VERSION 5.8 ;
BUSBITCHARS "[]" ;
DIVIDERCHAR "/" ;
UNITS DISTANCE MICRONS 2000 ;

# Comprehensive Standard Cell Library
# Technology: tcbn07 (7nm node), BWP300H8P64PD (Back-end), LVT (Low Vt)
# Contains all standard cells for CPU design
# Auto-generated from cpu_syn.v netlist

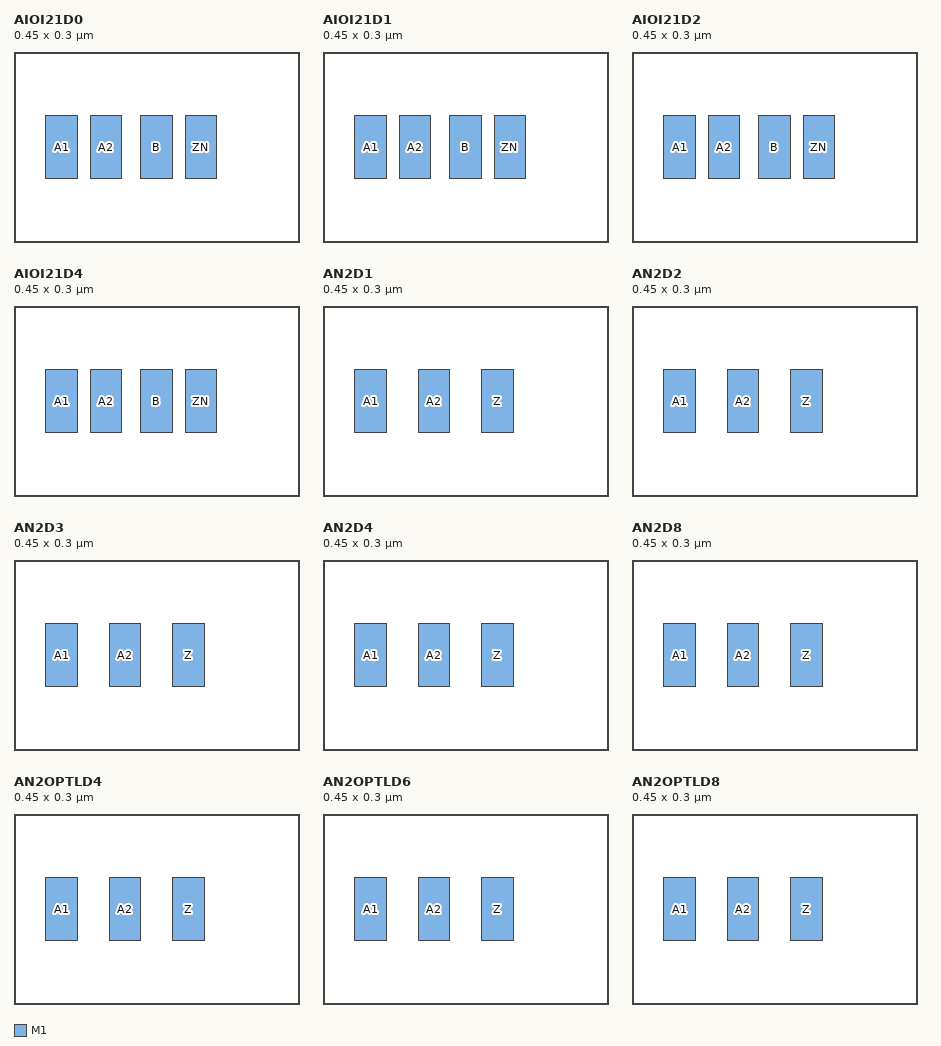
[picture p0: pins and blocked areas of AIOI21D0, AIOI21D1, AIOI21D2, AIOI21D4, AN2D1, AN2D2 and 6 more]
MACRO AIOI21D0
  CLASS CORE ;
  ORIGIN 0.0 0.0 ;
  SIZE 0.45 BY 0.3 ;
  SYMMETRY X Y ;
  PIN A1
    DIRECTION INPUT ;
    USE SIGNAL ;
    PORT
      LAYER M1 ;
      RECT 0.05 0.1 0.10 0.2 ;
    END
  END A1
  PIN A2
    DIRECTION INPUT ;
    USE SIGNAL ;
    PORT
      LAYER M1 ;
      RECT 0.12 0.1 0.17 0.2 ;
    END
  END A2
  PIN B
    DIRECTION INPUT ;
    USE SIGNAL ;
    PORT
      LAYER M1 ;
      RECT 0.20 0.1 0.25 0.2 ;
    END
  END B
  PIN ZN
    DIRECTION OUTPUT ;
    USE SIGNAL ;
    PORT
      LAYER M1 ;
      RECT 0.27 0.1 0.32 0.2 ;
    END
  END ZN
END AIOI21D0
MACRO AIOI21D1
  CLASS CORE ;
  ORIGIN 0.0 0.0 ;
  SIZE 0.45 BY 0.3 ;
  SYMMETRY X Y ;
  PIN A1
    DIRECTION INPUT ;
    USE SIGNAL ;
    PORT
      LAYER M1 ;
      RECT 0.05 0.1 0.10 0.2 ;
    END
  END A1
  PIN A2
    DIRECTION INPUT ;
    USE SIGNAL ;
    PORT
      LAYER M1 ;
      RECT 0.12 0.1 0.17 0.2 ;
    END
  END A2
  PIN B
    DIRECTION INPUT ;
    USE SIGNAL ;
    PORT
      LAYER M1 ;
      RECT 0.20 0.1 0.25 0.2 ;
    END
  END B
  PIN ZN
    DIRECTION OUTPUT ;
    USE SIGNAL ;
    PORT
      LAYER M1 ;
      RECT 0.27 0.1 0.32 0.2 ;
    END
  END ZN
END AIOI21D1
MACRO AIOI21D2
  CLASS CORE ;
  ORIGIN 0.0 0.0 ;
  SIZE 0.45 BY 0.3 ;
  SYMMETRY X Y ;
  PIN A1
    DIRECTION INPUT ;
    USE SIGNAL ;
    PORT
      LAYER M1 ;
      RECT 0.05 0.1 0.10 0.2 ;
    END
  END A1
  PIN A2
    DIRECTION INPUT ;
    USE SIGNAL ;
    PORT
      LAYER M1 ;
      RECT 0.12 0.1 0.17 0.2 ;
    END
  END A2
  PIN B
    DIRECTION INPUT ;
    USE SIGNAL ;
    PORT
      LAYER M1 ;
      RECT 0.20 0.1 0.25 0.2 ;
    END
  END B
  PIN ZN
    DIRECTION OUTPUT ;
    USE SIGNAL ;
    PORT
      LAYER M1 ;
      RECT 0.27 0.1 0.32 0.2 ;
    END
  END ZN
END AIOI21D2
MACRO AIOI21D4
  CLASS CORE ;
  ORIGIN 0.0 0.0 ;
  SIZE 0.45 BY 0.3 ;
  SYMMETRY X Y ;
  PIN A1
    DIRECTION INPUT ;
    USE SIGNAL ;
    PORT
      LAYER M1 ;
      RECT 0.05 0.1 0.10 0.2 ;
    END
  END A1
  PIN A2
    DIRECTION INPUT ;
    USE SIGNAL ;
    PORT
      LAYER M1 ;
      RECT 0.12 0.1 0.17 0.2 ;
    END
  END A2
  PIN B
    DIRECTION INPUT ;
    USE SIGNAL ;
    PORT
      LAYER M1 ;
      RECT 0.20 0.1 0.25 0.2 ;
    END
  END B
  PIN ZN
    DIRECTION OUTPUT ;
    USE SIGNAL ;
    PORT
      LAYER M1 ;
      RECT 0.27 0.1 0.32 0.2 ;
    END
  END ZN
END AIOI21D4
MACRO AN2D1
  CLASS CORE ;
  ORIGIN 0.0 0.0 ;
  SIZE 0.45 BY 0.3 ;
  SYMMETRY X Y ;
  PIN A1
    DIRECTION INPUT ;
    USE SIGNAL ;
    PORT
      LAYER M1 ;
      RECT 0.05 0.1 0.10 0.2 ;
    END
  END A1
  PIN A2
    DIRECTION INPUT ;
    USE SIGNAL ;
    PORT
      LAYER M1 ;
      RECT 0.15 0.1 0.20 0.2 ;
    END
  END A2
  PIN Z
    DIRECTION OUTPUT ;
    USE SIGNAL ;
    PORT
      LAYER M1 ;
      RECT 0.25 0.1 0.30 0.2 ;
    END
  END Z
END AN2D1
MACRO AN2D2
  CLASS CORE ;
  ORIGIN 0.0 0.0 ;
  SIZE 0.45 BY 0.3 ;
  SYMMETRY X Y ;
  PIN A1
    DIRECTION INPUT ;
    USE SIGNAL ;
    PORT
      LAYER M1 ;
      RECT 0.05 0.1 0.10 0.2 ;
    END
  END A1
  PIN A2
    DIRECTION INPUT ;
    USE SIGNAL ;
    PORT
      LAYER M1 ;
      RECT 0.15 0.1 0.20 0.2 ;
    END
  END A2
  PIN Z
    DIRECTION OUTPUT ;
    USE SIGNAL ;
    PORT
      LAYER M1 ;
      RECT 0.25 0.1 0.30 0.2 ;
    END
  END Z
END AN2D2
MACRO AN2D3
  CLASS CORE ;
  ORIGIN 0.0 0.0 ;
  SIZE 0.45 BY 0.3 ;
  SYMMETRY X Y ;
  PIN A1
    DIRECTION INPUT ;
    USE SIGNAL ;
    PORT
      LAYER M1 ;
      RECT 0.05 0.1 0.10 0.2 ;
    END
  END A1
  PIN A2
    DIRECTION INPUT ;
    USE SIGNAL ;
    PORT
      LAYER M1 ;
      RECT 0.15 0.1 0.20 0.2 ;
    END
  END A2
  PIN Z
    DIRECTION OUTPUT ;
    USE SIGNAL ;
    PORT
      LAYER M1 ;
      RECT 0.25 0.1 0.30 0.2 ;
    END
  END Z
END AN2D3
MACRO AN2D4
  CLASS CORE ;
  ORIGIN 0.0 0.0 ;
  SIZE 0.45 BY 0.3 ;
  SYMMETRY X Y ;
  PIN A1
    DIRECTION INPUT ;
    USE SIGNAL ;
    PORT
      LAYER M1 ;
      RECT 0.05 0.1 0.10 0.2 ;
    END
  END A1
  PIN A2
    DIRECTION INPUT ;
    USE SIGNAL ;
    PORT
      LAYER M1 ;
      RECT 0.15 0.1 0.20 0.2 ;
    END
  END A2
  PIN Z
    DIRECTION OUTPUT ;
    USE SIGNAL ;
    PORT
      LAYER M1 ;
      RECT 0.25 0.1 0.30 0.2 ;
    END
  END Z
END AN2D4
MACRO AN2D8
  CLASS CORE ;
  ORIGIN 0.0 0.0 ;
  SIZE 0.45 BY 0.3 ;
  SYMMETRY X Y ;
  PIN A1
    DIRECTION INPUT ;
    USE SIGNAL ;
    PORT
      LAYER M1 ;
      RECT 0.05 0.1 0.10 0.2 ;
    END
  END A1
  PIN A2
    DIRECTION INPUT ;
    USE SIGNAL ;
    PORT
      LAYER M1 ;
      RECT 0.15 0.1 0.20 0.2 ;
    END
  END A2
  PIN Z
    DIRECTION OUTPUT ;
    USE SIGNAL ;
    PORT
      LAYER M1 ;
      RECT 0.25 0.1 0.30 0.2 ;
    END
  END Z
END AN2D8
MACRO AN2OPTLD4
  CLASS CORE ;
  ORIGIN 0.0 0.0 ;
  SIZE 0.45 BY 0.3 ;
  SYMMETRY X Y ;
  PIN A1
    DIRECTION INPUT ;
    USE SIGNAL ;
    PORT
      LAYER M1 ;
      RECT 0.05 0.1 0.10 0.2 ;
    END
  END A1
  PIN A2
    DIRECTION INPUT ;
    USE SIGNAL ;
    PORT
      LAYER M1 ;
      RECT 0.15 0.1 0.20 0.2 ;
    END
  END A2
  PIN Z
    DIRECTION OUTPUT ;
    USE SIGNAL ;
    PORT
      LAYER M1 ;
      RECT 0.25 0.1 0.30 0.2 ;
    END
  END Z
END AN2OPTLD4
MACRO AN2OPTLD6
  CLASS CORE ;
  ORIGIN 0.0 0.0 ;
  SIZE 0.45 BY 0.3 ;
  SYMMETRY X Y ;
  PIN A1
    DIRECTION INPUT ;
    USE SIGNAL ;
    PORT
      LAYER M1 ;
      RECT 0.05 0.1 0.10 0.2 ;
    END
  END A1
  PIN A2
    DIRECTION INPUT ;
    USE SIGNAL ;
    PORT
      LAYER M1 ;
      RECT 0.15 0.1 0.20 0.2 ;
    END
  END A2
  PIN Z
    DIRECTION OUTPUT ;
    USE SIGNAL ;
    PORT
      LAYER M1 ;
      RECT 0.25 0.1 0.30 0.2 ;
    END
  END Z
END AN2OPTLD6
MACRO AN2OPTLD8
  CLASS CORE ;
  ORIGIN 0.0 0.0 ;
  SIZE 0.45 BY 0.3 ;
  SYMMETRY X Y ;
  PIN A1
    DIRECTION INPUT ;
    USE SIGNAL ;
    PORT
      LAYER M1 ;
      RECT 0.05 0.1 0.10 0.2 ;
    END
  END A1
  PIN A2
    DIRECTION INPUT ;
    USE SIGNAL ;
    PORT
      LAYER M1 ;
      RECT 0.15 0.1 0.20 0.2 ;
    END
  END A2
  PIN Z
    DIRECTION OUTPUT ;
    USE SIGNAL ;
    PORT
      LAYER M1 ;
      RECT 0.25 0.1 0.30 0.2 ;
    END
  END Z
END AN2OPTLD8
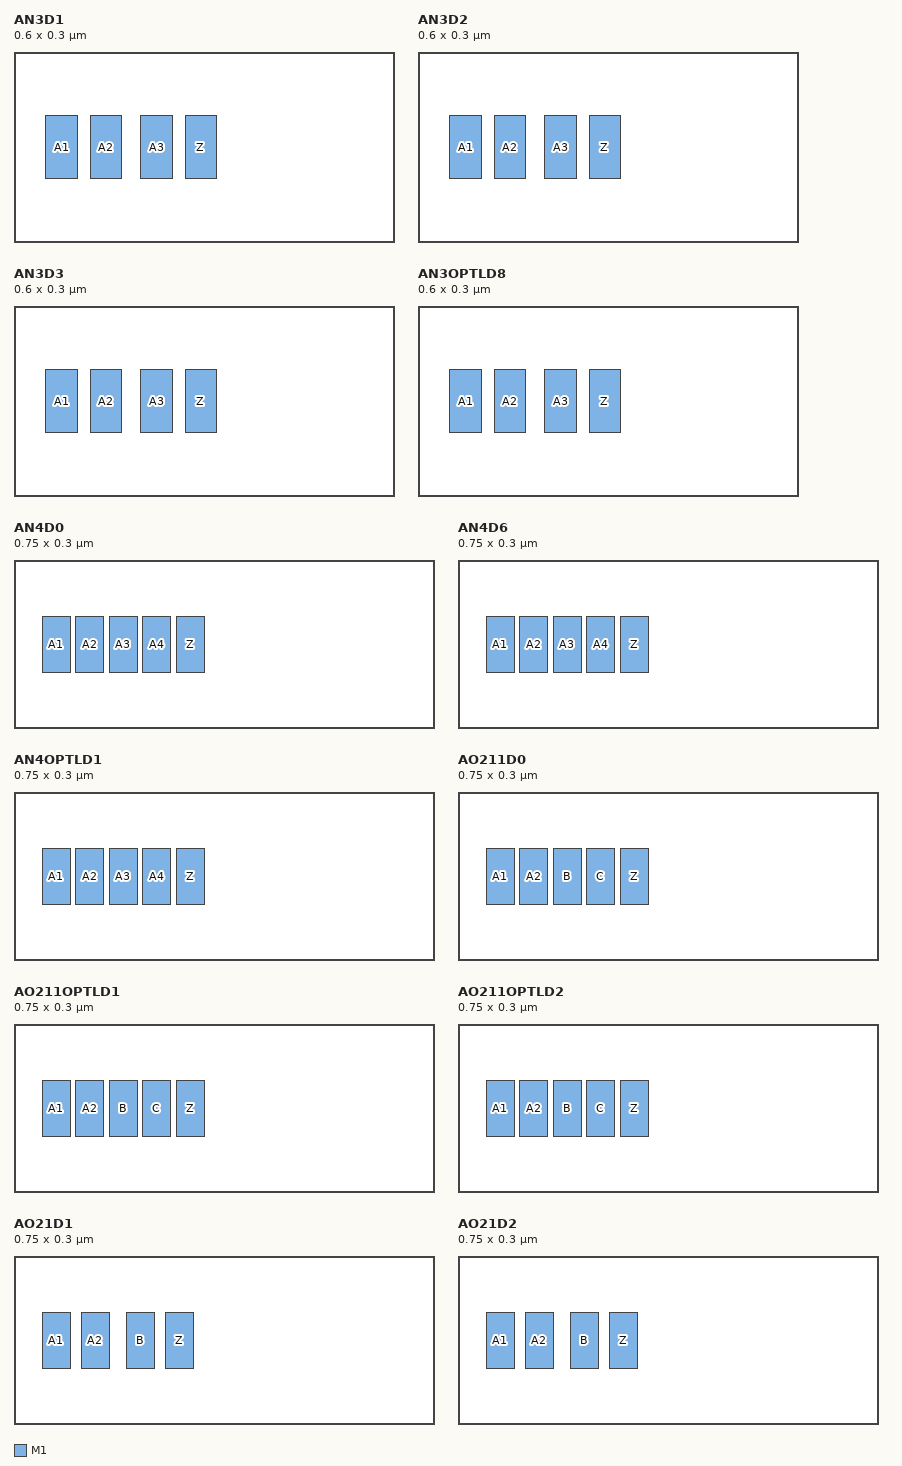
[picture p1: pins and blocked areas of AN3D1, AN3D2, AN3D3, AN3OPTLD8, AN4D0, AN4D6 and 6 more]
MACRO AN3D1
  CLASS CORE ;
  ORIGIN 0.0 0.0 ;
  SIZE 0.6 BY 0.3 ;
  SYMMETRY X Y ;
  PIN A1
    DIRECTION INPUT ;
    USE SIGNAL ;
    PORT
      LAYER M1 ;
      RECT 0.05 0.1 0.10 0.2 ;
    END
  END A1
  PIN A2
    DIRECTION INPUT ;
    USE SIGNAL ;
    PORT
      LAYER M1 ;
      RECT 0.12 0.1 0.17 0.2 ;
    END
  END A2
  PIN A3
    DIRECTION INPUT ;
    USE SIGNAL ;
    PORT
      LAYER M1 ;
      RECT 0.20 0.1 0.25 0.2 ;
    END
  END A3
  PIN Z
    DIRECTION OUTPUT ;
    USE SIGNAL ;
    PORT
      LAYER M1 ;
      RECT 0.27 0.1 0.32 0.2 ;
    END
  END Z
END AN3D1
MACRO AN3D2
  CLASS CORE ;
  ORIGIN 0.0 0.0 ;
  SIZE 0.6 BY 0.3 ;
  SYMMETRY X Y ;
  PIN A1
    DIRECTION INPUT ;
    USE SIGNAL ;
    PORT
      LAYER M1 ;
      RECT 0.05 0.1 0.10 0.2 ;
    END
  END A1
  PIN A2
    DIRECTION INPUT ;
    USE SIGNAL ;
    PORT
      LAYER M1 ;
      RECT 0.12 0.1 0.17 0.2 ;
    END
  END A2
  PIN A3
    DIRECTION INPUT ;
    USE SIGNAL ;
    PORT
      LAYER M1 ;
      RECT 0.20 0.1 0.25 0.2 ;
    END
  END A3
  PIN Z
    DIRECTION OUTPUT ;
    USE SIGNAL ;
    PORT
      LAYER M1 ;
      RECT 0.27 0.1 0.32 0.2 ;
    END
  END Z
END AN3D2
MACRO AN3D3
  CLASS CORE ;
  ORIGIN 0.0 0.0 ;
  SIZE 0.6 BY 0.3 ;
  SYMMETRY X Y ;
  PIN A1
    DIRECTION INPUT ;
    USE SIGNAL ;
    PORT
      LAYER M1 ;
      RECT 0.05 0.1 0.10 0.2 ;
    END
  END A1
  PIN A2
    DIRECTION INPUT ;
    USE SIGNAL ;
    PORT
      LAYER M1 ;
      RECT 0.12 0.1 0.17 0.2 ;
    END
  END A2
  PIN A3
    DIRECTION INPUT ;
    USE SIGNAL ;
    PORT
      LAYER M1 ;
      RECT 0.20 0.1 0.25 0.2 ;
    END
  END A3
  PIN Z
    DIRECTION OUTPUT ;
    USE SIGNAL ;
    PORT
      LAYER M1 ;
      RECT 0.27 0.1 0.32 0.2 ;
    END
  END Z
END AN3D3
MACRO AN3OPTLD8
  CLASS CORE ;
  ORIGIN 0.0 0.0 ;
  SIZE 0.6 BY 0.3 ;
  SYMMETRY X Y ;
  PIN A1
    DIRECTION INPUT ;
    USE SIGNAL ;
    PORT
      LAYER M1 ;
      RECT 0.05 0.1 0.10 0.2 ;
    END
  END A1
  PIN A2
    DIRECTION INPUT ;
    USE SIGNAL ;
    PORT
      LAYER M1 ;
      RECT 0.12 0.1 0.17 0.2 ;
    END
  END A2
  PIN A3
    DIRECTION INPUT ;
    USE SIGNAL ;
    PORT
      LAYER M1 ;
      RECT 0.20 0.1 0.25 0.2 ;
    END
  END A3
  PIN Z
    DIRECTION OUTPUT ;
    USE SIGNAL ;
    PORT
      LAYER M1 ;
      RECT 0.27 0.1 0.32 0.2 ;
    END
  END Z
END AN3OPTLD8
MACRO AN4D0
  CLASS CORE ;
  ORIGIN 0.0 0.0 ;
  SIZE 0.75 BY 0.3 ;
  SYMMETRY X Y ;
  PIN A1
    DIRECTION INPUT ;
    USE SIGNAL ;
    PORT
      LAYER M1 ;
      RECT 0.05 0.1 0.10 0.2 ;
    END
  END A1
  PIN A2
    DIRECTION INPUT ;
    USE SIGNAL ;
    PORT
      LAYER M1 ;
      RECT 0.11 0.1 0.16 0.2 ;
    END
  END A2
  PIN A3
    DIRECTION INPUT ;
    USE SIGNAL ;
    PORT
      LAYER M1 ;
      RECT 0.17 0.1 0.22 0.2 ;
    END
  END A3
  PIN A4
    DIRECTION INPUT ;
    USE SIGNAL ;
    PORT
      LAYER M1 ;
      RECT 0.23 0.1 0.28 0.2 ;
    END
  END A4
  PIN Z
    DIRECTION OUTPUT ;
    USE SIGNAL ;
    PORT
      LAYER M1 ;
      RECT 0.29 0.1 0.34 0.2 ;
    END
  END Z
END AN4D0
MACRO AN4D6
  CLASS CORE ;
  ORIGIN 0.0 0.0 ;
  SIZE 0.75 BY 0.3 ;
  SYMMETRY X Y ;
  PIN A1
    DIRECTION INPUT ;
    USE SIGNAL ;
    PORT
      LAYER M1 ;
      RECT 0.05 0.1 0.10 0.2 ;
    END
  END A1
  PIN A2
    DIRECTION INPUT ;
    USE SIGNAL ;
    PORT
      LAYER M1 ;
      RECT 0.11 0.1 0.16 0.2 ;
    END
  END A2
  PIN A3
    DIRECTION INPUT ;
    USE SIGNAL ;
    PORT
      LAYER M1 ;
      RECT 0.17 0.1 0.22 0.2 ;
    END
  END A3
  PIN A4
    DIRECTION INPUT ;
    USE SIGNAL ;
    PORT
      LAYER M1 ;
      RECT 0.23 0.1 0.28 0.2 ;
    END
  END A4
  PIN Z
    DIRECTION OUTPUT ;
    USE SIGNAL ;
    PORT
      LAYER M1 ;
      RECT 0.29 0.1 0.34 0.2 ;
    END
  END Z
END AN4D6
MACRO AN4OPTLD1
  CLASS CORE ;
  ORIGIN 0.0 0.0 ;
  SIZE 0.75 BY 0.3 ;
  SYMMETRY X Y ;
  PIN A1
    DIRECTION INPUT ;
    USE SIGNAL ;
    PORT
      LAYER M1 ;
      RECT 0.05 0.1 0.10 0.2 ;
    END
  END A1
  PIN A2
    DIRECTION INPUT ;
    USE SIGNAL ;
    PORT
      LAYER M1 ;
      RECT 0.11 0.1 0.16 0.2 ;
    END
  END A2
  PIN A3
    DIRECTION INPUT ;
    USE SIGNAL ;
    PORT
      LAYER M1 ;
      RECT 0.17 0.1 0.22 0.2 ;
    END
  END A3
  PIN A4
    DIRECTION INPUT ;
    USE SIGNAL ;
    PORT
      LAYER M1 ;
      RECT 0.23 0.1 0.28 0.2 ;
    END
  END A4
  PIN Z
    DIRECTION OUTPUT ;
    USE SIGNAL ;
    PORT
      LAYER M1 ;
      RECT 0.29 0.1 0.34 0.2 ;
    END
  END Z
END AN4OPTLD1
MACRO AO211D0
  CLASS CORE ;
  ORIGIN 0.0 0.0 ;
  SIZE 0.75 BY 0.3 ;
  SYMMETRY X Y ;
  PIN A1
    DIRECTION INPUT ;
    USE SIGNAL ;
    PORT
      LAYER M1 ;
      RECT 0.05 0.1 0.10 0.2 ;
    END
  END A1
  PIN A2
    DIRECTION INPUT ;
    USE SIGNAL ;
    PORT
      LAYER M1 ;
      RECT 0.11 0.1 0.16 0.2 ;
    END
  END A2
  PIN B
    DIRECTION INPUT ;
    USE SIGNAL ;
    PORT
      LAYER M1 ;
      RECT 0.17 0.1 0.22 0.2 ;
    END
  END B
  PIN C
    DIRECTION INPUT ;
    USE SIGNAL ;
    PORT
      LAYER M1 ;
      RECT 0.23 0.1 0.28 0.2 ;
    END
  END C
  PIN Z
    DIRECTION OUTPUT ;
    USE SIGNAL ;
    PORT
      LAYER M1 ;
      RECT 0.29 0.1 0.34 0.2 ;
    END
  END Z
END AO211D0
MACRO AO211OPTLD1
  CLASS CORE ;
  ORIGIN 0.0 0.0 ;
  SIZE 0.75 BY 0.3 ;
  SYMMETRY X Y ;
  PIN A1
    DIRECTION INPUT ;
    USE SIGNAL ;
    PORT
      LAYER M1 ;
      RECT 0.05 0.1 0.10 0.2 ;
    END
  END A1
  PIN A2
    DIRECTION INPUT ;
    USE SIGNAL ;
    PORT
      LAYER M1 ;
      RECT 0.11 0.1 0.16 0.2 ;
    END
  END A2
  PIN B
    DIRECTION INPUT ;
    USE SIGNAL ;
    PORT
      LAYER M1 ;
      RECT 0.17 0.1 0.22 0.2 ;
    END
  END B
  PIN C
    DIRECTION INPUT ;
    USE SIGNAL ;
    PORT
      LAYER M1 ;
      RECT 0.23 0.1 0.28 0.2 ;
    END
  END C
  PIN Z
    DIRECTION OUTPUT ;
    USE SIGNAL ;
    PORT
      LAYER M1 ;
      RECT 0.29 0.1 0.34 0.2 ;
    END
  END Z
END AO211OPTLD1
MACRO AO211OPTLD2
  CLASS CORE ;
  ORIGIN 0.0 0.0 ;
  SIZE 0.75 BY 0.3 ;
  SYMMETRY X Y ;
  PIN A1
    DIRECTION INPUT ;
    USE SIGNAL ;
    PORT
      LAYER M1 ;
      RECT 0.05 0.1 0.10 0.2 ;
    END
  END A1
  PIN A2
    DIRECTION INPUT ;
    USE SIGNAL ;
    PORT
      LAYER M1 ;
      RECT 0.11 0.1 0.16 0.2 ;
    END
  END A2
  PIN B
    DIRECTION INPUT ;
    USE SIGNAL ;
    PORT
      LAYER M1 ;
      RECT 0.17 0.1 0.22 0.2 ;
    END
  END B
  PIN C
    DIRECTION INPUT ;
    USE SIGNAL ;
    PORT
      LAYER M1 ;
      RECT 0.23 0.1 0.28 0.2 ;
    END
  END C
  PIN Z
    DIRECTION OUTPUT ;
    USE SIGNAL ;
    PORT
      LAYER M1 ;
      RECT 0.29 0.1 0.34 0.2 ;
    END
  END Z
END AO211OPTLD2
MACRO AO21D1
  CLASS CORE ;
  ORIGIN 0.0 0.0 ;
  SIZE 0.75 BY 0.3 ;
  SYMMETRY X Y ;
  PIN A1
    DIRECTION INPUT ;
    USE SIGNAL ;
    PORT
      LAYER M1 ;
      RECT 0.05 0.1 0.10 0.2 ;
    END
  END A1
  PIN A2
    DIRECTION INPUT ;
    USE SIGNAL ;
    PORT
      LAYER M1 ;
      RECT 0.12 0.1 0.17 0.2 ;
    END
  END A2
  PIN B
    DIRECTION INPUT ;
    USE SIGNAL ;
    PORT
      LAYER M1 ;
      RECT 0.20 0.1 0.25 0.2 ;
    END
  END B
  PIN Z
    DIRECTION OUTPUT ;
    USE SIGNAL ;
    PORT
      LAYER M1 ;
      RECT 0.27 0.1 0.32 0.2 ;
    END
  END Z
END AO21D1
MACRO AO21D2
  CLASS CORE ;
  ORIGIN 0.0 0.0 ;
  SIZE 0.75 BY 0.3 ;
  SYMMETRY X Y ;
  PIN A1
    DIRECTION INPUT ;
    USE SIGNAL ;
    PORT
      LAYER M1 ;
      RECT 0.05 0.1 0.10 0.2 ;
    END
  END A1
  PIN A2
    DIRECTION INPUT ;
    USE SIGNAL ;
    PORT
      LAYER M1 ;
      RECT 0.12 0.1 0.17 0.2 ;
    END
  END A2
  PIN B
    DIRECTION INPUT ;
    USE SIGNAL ;
    PORT
      LAYER M1 ;
      RECT 0.20 0.1 0.25 0.2 ;
    END
  END B
  PIN Z
    DIRECTION OUTPUT ;
    USE SIGNAL ;
    PORT
      LAYER M1 ;
      RECT 0.27 0.1 0.32 0.2 ;
    END
  END Z
END AO21D2
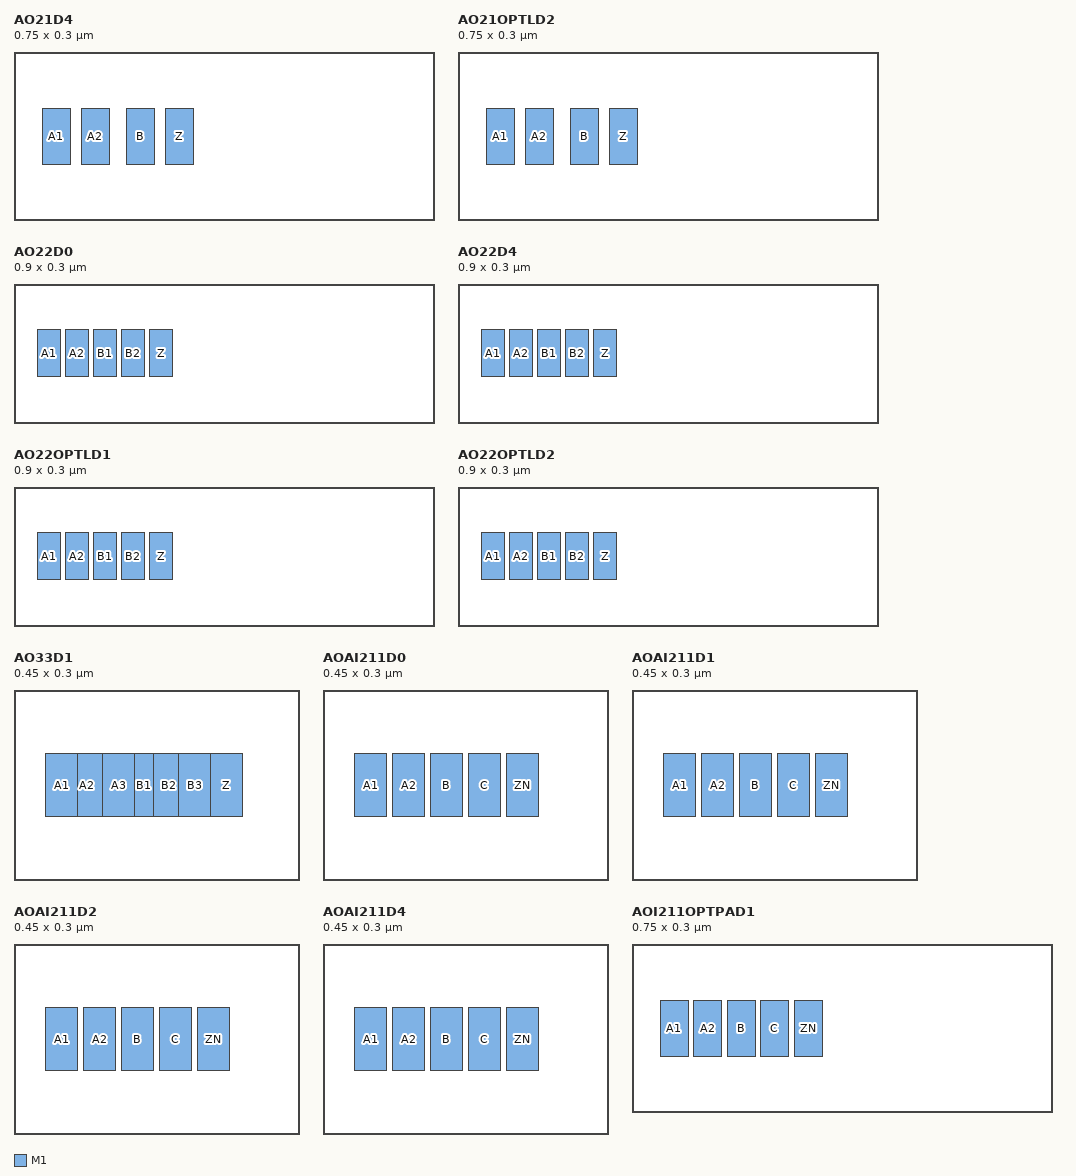
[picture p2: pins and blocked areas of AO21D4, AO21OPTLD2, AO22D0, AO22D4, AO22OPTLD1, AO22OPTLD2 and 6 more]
MACRO AO21D4
  CLASS CORE ;
  ORIGIN 0.0 0.0 ;
  SIZE 0.75 BY 0.3 ;
  SYMMETRY X Y ;
  PIN A1
    DIRECTION INPUT ;
    USE SIGNAL ;
    PORT
      LAYER M1 ;
      RECT 0.05 0.1 0.10 0.2 ;
    END
  END A1
  PIN A2
    DIRECTION INPUT ;
    USE SIGNAL ;
    PORT
      LAYER M1 ;
      RECT 0.12 0.1 0.17 0.2 ;
    END
  END A2
  PIN B
    DIRECTION INPUT ;
    USE SIGNAL ;
    PORT
      LAYER M1 ;
      RECT 0.20 0.1 0.25 0.2 ;
    END
  END B
  PIN Z
    DIRECTION OUTPUT ;
    USE SIGNAL ;
    PORT
      LAYER M1 ;
      RECT 0.27 0.1 0.32 0.2 ;
    END
  END Z
END AO21D4
MACRO AO21OPTLD2
  CLASS CORE ;
  ORIGIN 0.0 0.0 ;
  SIZE 0.75 BY 0.3 ;
  SYMMETRY X Y ;
  PIN A1
    DIRECTION INPUT ;
    USE SIGNAL ;
    PORT
      LAYER M1 ;
      RECT 0.05 0.1 0.10 0.2 ;
    END
  END A1
  PIN A2
    DIRECTION INPUT ;
    USE SIGNAL ;
    PORT
      LAYER M1 ;
      RECT 0.12 0.1 0.17 0.2 ;
    END
  END A2
  PIN B
    DIRECTION INPUT ;
    USE SIGNAL ;
    PORT
      LAYER M1 ;
      RECT 0.20 0.1 0.25 0.2 ;
    END
  END B
  PIN Z
    DIRECTION OUTPUT ;
    USE SIGNAL ;
    PORT
      LAYER M1 ;
      RECT 0.27 0.1 0.32 0.2 ;
    END
  END Z
END AO21OPTLD2
MACRO AO22D0
  CLASS CORE ;
  ORIGIN 0.0 0.0 ;
  SIZE 0.9 BY 0.3 ;
  SYMMETRY X Y ;
  PIN A1
    DIRECTION INPUT ;
    USE SIGNAL ;
    PORT
      LAYER M1 ;
      RECT 0.05 0.1 0.10 0.2 ;
    END
  END A1
  PIN A2
    DIRECTION INPUT ;
    USE SIGNAL ;
    PORT
      LAYER M1 ;
      RECT 0.11 0.1 0.16 0.2 ;
    END
  END A2
  PIN B1
    DIRECTION INPUT ;
    USE SIGNAL ;
    PORT
      LAYER M1 ;
      RECT 0.17 0.1 0.22 0.2 ;
    END
  END B1
  PIN B2
    DIRECTION INPUT ;
    USE SIGNAL ;
    PORT
      LAYER M1 ;
      RECT 0.23 0.1 0.28 0.2 ;
    END
  END B2
  PIN Z
    DIRECTION OUTPUT ;
    USE SIGNAL ;
    PORT
      LAYER M1 ;
      RECT 0.29 0.1 0.34 0.2 ;
    END
  END Z
END AO22D0
MACRO AO22D4
  CLASS CORE ;
  ORIGIN 0.0 0.0 ;
  SIZE 0.9 BY 0.3 ;
  SYMMETRY X Y ;
  PIN A1
    DIRECTION INPUT ;
    USE SIGNAL ;
    PORT
      LAYER M1 ;
      RECT 0.05 0.1 0.10 0.2 ;
    END
  END A1
  PIN A2
    DIRECTION INPUT ;
    USE SIGNAL ;
    PORT
      LAYER M1 ;
      RECT 0.11 0.1 0.16 0.2 ;
    END
  END A2
  PIN B1
    DIRECTION INPUT ;
    USE SIGNAL ;
    PORT
      LAYER M1 ;
      RECT 0.17 0.1 0.22 0.2 ;
    END
  END B1
  PIN B2
    DIRECTION INPUT ;
    USE SIGNAL ;
    PORT
      LAYER M1 ;
      RECT 0.23 0.1 0.28 0.2 ;
    END
  END B2
  PIN Z
    DIRECTION OUTPUT ;
    USE SIGNAL ;
    PORT
      LAYER M1 ;
      RECT 0.29 0.1 0.34 0.2 ;
    END
  END Z
END AO22D4
MACRO AO22OPTLD1
  CLASS CORE ;
  ORIGIN 0.0 0.0 ;
  SIZE 0.9 BY 0.3 ;
  SYMMETRY X Y ;
  PIN A1
    DIRECTION INPUT ;
    USE SIGNAL ;
    PORT
      LAYER M1 ;
      RECT 0.05 0.1 0.10 0.2 ;
    END
  END A1
  PIN A2
    DIRECTION INPUT ;
    USE SIGNAL ;
    PORT
      LAYER M1 ;
      RECT 0.11 0.1 0.16 0.2 ;
    END
  END A2
  PIN B1
    DIRECTION INPUT ;
    USE SIGNAL ;
    PORT
      LAYER M1 ;
      RECT 0.17 0.1 0.22 0.2 ;
    END
  END B1
  PIN B2
    DIRECTION INPUT ;
    USE SIGNAL ;
    PORT
      LAYER M1 ;
      RECT 0.23 0.1 0.28 0.2 ;
    END
  END B2
  PIN Z
    DIRECTION OUTPUT ;
    USE SIGNAL ;
    PORT
      LAYER M1 ;
      RECT 0.29 0.1 0.34 0.2 ;
    END
  END Z
END AO22OPTLD1
MACRO AO22OPTLD2
  CLASS CORE ;
  ORIGIN 0.0 0.0 ;
  SIZE 0.9 BY 0.3 ;
  SYMMETRY X Y ;
  PIN A1
    DIRECTION INPUT ;
    USE SIGNAL ;
    PORT
      LAYER M1 ;
      RECT 0.05 0.1 0.10 0.2 ;
    END
  END A1
  PIN A2
    DIRECTION INPUT ;
    USE SIGNAL ;
    PORT
      LAYER M1 ;
      RECT 0.11 0.1 0.16 0.2 ;
    END
  END A2
  PIN B1
    DIRECTION INPUT ;
    USE SIGNAL ;
    PORT
      LAYER M1 ;
      RECT 0.17 0.1 0.22 0.2 ;
    END
  END B1
  PIN B2
    DIRECTION INPUT ;
    USE SIGNAL ;
    PORT
      LAYER M1 ;
      RECT 0.23 0.1 0.28 0.2 ;
    END
  END B2
  PIN Z
    DIRECTION OUTPUT ;
    USE SIGNAL ;
    PORT
      LAYER M1 ;
      RECT 0.29 0.1 0.34 0.2 ;
    END
  END Z
END AO22OPTLD2
MACRO AO33D1
  CLASS CORE ;
  ORIGIN 0.0 0.0 ;
  SIZE 0.45 BY 0.3 ;
  SYMMETRY X Y ;
  PIN A1
    DIRECTION INPUT ;
    USE SIGNAL ;
    PORT
      LAYER M1 ;
      RECT 0.05 0.1 0.10 0.2 ;
    END
  END A1
  PIN A2
    DIRECTION INPUT ;
    USE SIGNAL ;
    PORT
      LAYER M1 ;
      RECT 0.09 0.1 0.14 0.2 ;
    END
  END A2
  PIN A3
    DIRECTION INPUT ;
    USE SIGNAL ;
    PORT
      LAYER M1 ;
      RECT 0.14 0.1 0.19 0.2 ;
    END
  END A3
  PIN B1
    DIRECTION INPUT ;
    USE SIGNAL ;
    PORT
      LAYER M1 ;
      RECT 0.18 0.1 0.23 0.2 ;
    END
  END B1
  PIN B2
    DIRECTION INPUT ;
    USE SIGNAL ;
    PORT
      LAYER M1 ;
      RECT 0.22 0.1 0.27 0.2 ;
    END
  END B2
  PIN B3
    DIRECTION INPUT ;
    USE SIGNAL ;
    PORT
      LAYER M1 ;
      RECT 0.26 0.1 0.31 0.2 ;
    END
  END B3
  PIN Z
    DIRECTION OUTPUT ;
    USE SIGNAL ;
    PORT
      LAYER M1 ;
      RECT 0.31 0.1 0.36 0.2 ;
    END
  END Z
END AO33D1
MACRO AOAI211D0
  CLASS CORE ;
  ORIGIN 0.0 0.0 ;
  SIZE 0.45 BY 0.3 ;
  SYMMETRY X Y ;
  PIN A1
    DIRECTION INPUT ;
    USE SIGNAL ;
    PORT
      LAYER M1 ;
      RECT 0.05 0.1 0.10 0.2 ;
    END
  END A1
  PIN A2
    DIRECTION INPUT ;
    USE SIGNAL ;
    PORT
      LAYER M1 ;
      RECT 0.11 0.1 0.16 0.2 ;
    END
  END A2
  PIN B
    DIRECTION INPUT ;
    USE SIGNAL ;
    PORT
      LAYER M1 ;
      RECT 0.17 0.1 0.22 0.2 ;
    END
  END B
  PIN C
    DIRECTION INPUT ;
    USE SIGNAL ;
    PORT
      LAYER M1 ;
      RECT 0.23 0.1 0.28 0.2 ;
    END
  END C
  PIN ZN
    DIRECTION OUTPUT ;
    USE SIGNAL ;
    PORT
      LAYER M1 ;
      RECT 0.29 0.1 0.34 0.2 ;
    END
  END ZN
END AOAI211D0
MACRO AOAI211D1
  CLASS CORE ;
  ORIGIN 0.0 0.0 ;
  SIZE 0.45 BY 0.3 ;
  SYMMETRY X Y ;
  PIN A1
    DIRECTION INPUT ;
    USE SIGNAL ;
    PORT
      LAYER M1 ;
      RECT 0.05 0.1 0.10 0.2 ;
    END
  END A1
  PIN A2
    DIRECTION INPUT ;
    USE SIGNAL ;
    PORT
      LAYER M1 ;
      RECT 0.11 0.1 0.16 0.2 ;
    END
  END A2
  PIN B
    DIRECTION INPUT ;
    USE SIGNAL ;
    PORT
      LAYER M1 ;
      RECT 0.17 0.1 0.22 0.2 ;
    END
  END B
  PIN C
    DIRECTION INPUT ;
    USE SIGNAL ;
    PORT
      LAYER M1 ;
      RECT 0.23 0.1 0.28 0.2 ;
    END
  END C
  PIN ZN
    DIRECTION OUTPUT ;
    USE SIGNAL ;
    PORT
      LAYER M1 ;
      RECT 0.29 0.1 0.34 0.2 ;
    END
  END ZN
END AOAI211D1
MACRO AOAI211D2
  CLASS CORE ;
  ORIGIN 0.0 0.0 ;
  SIZE 0.45 BY 0.3 ;
  SYMMETRY X Y ;
  PIN A1
    DIRECTION INPUT ;
    USE SIGNAL ;
    PORT
      LAYER M1 ;
      RECT 0.05 0.1 0.10 0.2 ;
    END
  END A1
  PIN A2
    DIRECTION INPUT ;
    USE SIGNAL ;
    PORT
      LAYER M1 ;
      RECT 0.11 0.1 0.16 0.2 ;
    END
  END A2
  PIN B
    DIRECTION INPUT ;
    USE SIGNAL ;
    PORT
      LAYER M1 ;
      RECT 0.17 0.1 0.22 0.2 ;
    END
  END B
  PIN C
    DIRECTION INPUT ;
    USE SIGNAL ;
    PORT
      LAYER M1 ;
      RECT 0.23 0.1 0.28 0.2 ;
    END
  END C
  PIN ZN
    DIRECTION OUTPUT ;
    USE SIGNAL ;
    PORT
      LAYER M1 ;
      RECT 0.29 0.1 0.34 0.2 ;
    END
  END ZN
END AOAI211D2
MACRO AOAI211D4
  CLASS CORE ;
  ORIGIN 0.0 0.0 ;
  SIZE 0.45 BY 0.3 ;
  SYMMETRY X Y ;
  PIN A1
    DIRECTION INPUT ;
    USE SIGNAL ;
    PORT
      LAYER M1 ;
      RECT 0.05 0.1 0.10 0.2 ;
    END
  END A1
  PIN A2
    DIRECTION INPUT ;
    USE SIGNAL ;
    PORT
      LAYER M1 ;
      RECT 0.11 0.1 0.16 0.2 ;
    END
  END A2
  PIN B
    DIRECTION INPUT ;
    USE SIGNAL ;
    PORT
      LAYER M1 ;
      RECT 0.17 0.1 0.22 0.2 ;
    END
  END B
  PIN C
    DIRECTION INPUT ;
    USE SIGNAL ;
    PORT
      LAYER M1 ;
      RECT 0.23 0.1 0.28 0.2 ;
    END
  END C
  PIN ZN
    DIRECTION OUTPUT ;
    USE SIGNAL ;
    PORT
      LAYER M1 ;
      RECT 0.29 0.1 0.34 0.2 ;
    END
  END ZN
END AOAI211D4
MACRO AOI211OPTPAD1
  CLASS CORE ;
  ORIGIN 0.0 0.0 ;
  SIZE 0.75 BY 0.3 ;
  SYMMETRY X Y ;
  PIN A1
    DIRECTION INPUT ;
    USE SIGNAL ;
    PORT
      LAYER M1 ;
      RECT 0.05 0.1 0.10 0.2 ;
    END
  END A1
  PIN A2
    DIRECTION INPUT ;
    USE SIGNAL ;
    PORT
      LAYER M1 ;
      RECT 0.11 0.1 0.16 0.2 ;
    END
  END A2
  PIN B
    DIRECTION INPUT ;
    USE SIGNAL ;
    PORT
      LAYER M1 ;
      RECT 0.17 0.1 0.22 0.2 ;
    END
  END B
  PIN C
    DIRECTION INPUT ;
    USE SIGNAL ;
    PORT
      LAYER M1 ;
      RECT 0.23 0.1 0.28 0.2 ;
    END
  END C
  PIN ZN
    DIRECTION OUTPUT ;
    USE SIGNAL ;
    PORT
      LAYER M1 ;
      RECT 0.29 0.1 0.34 0.2 ;
    END
  END ZN
END AOI211OPTPAD1
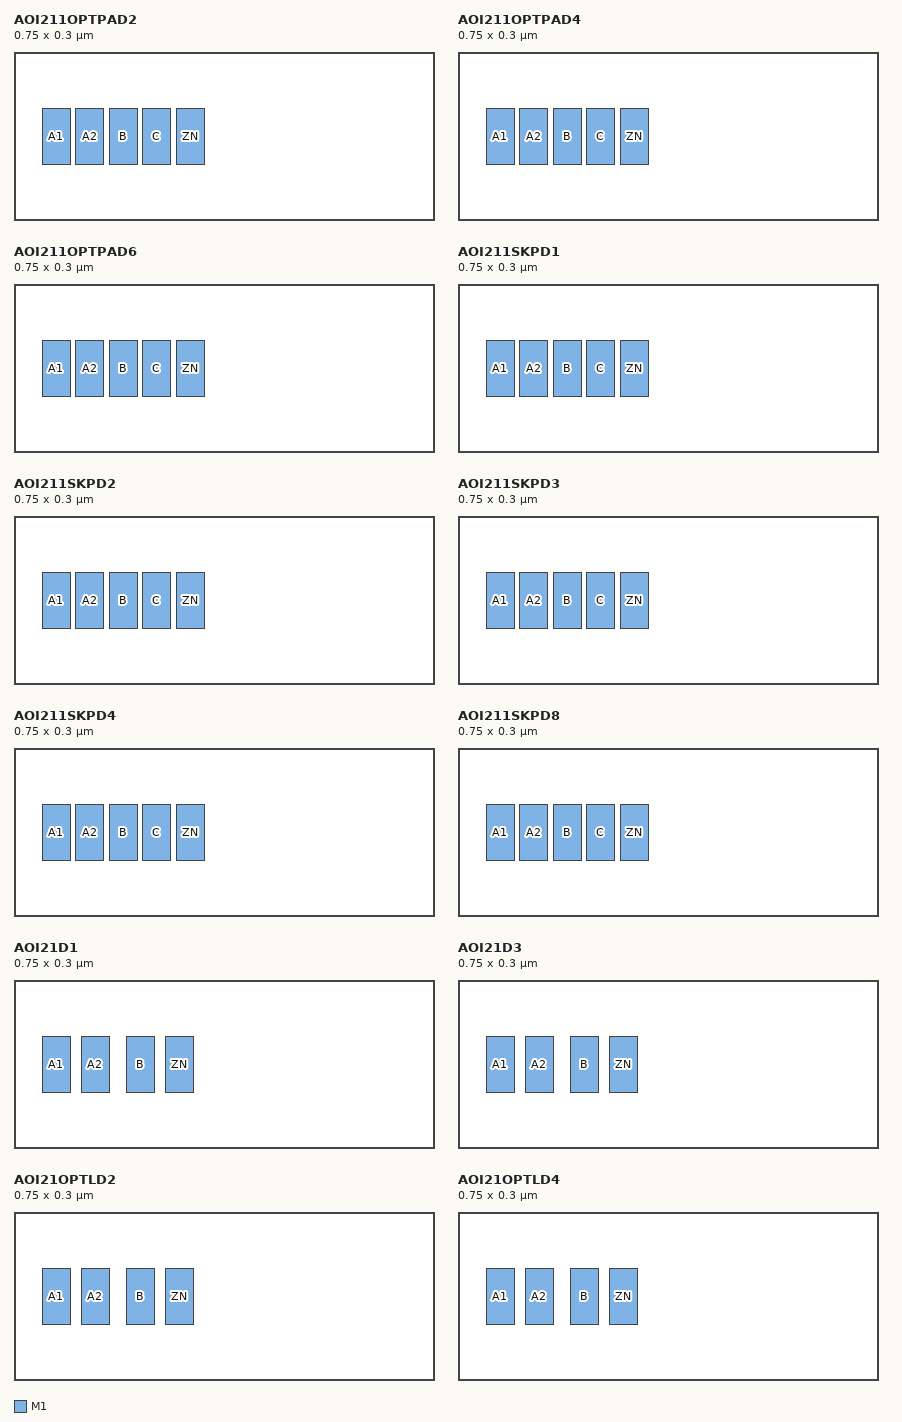
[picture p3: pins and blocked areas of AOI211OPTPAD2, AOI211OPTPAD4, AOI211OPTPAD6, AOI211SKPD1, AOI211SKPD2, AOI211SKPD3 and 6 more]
MACRO AOI211OPTPAD2
  CLASS CORE ;
  ORIGIN 0.0 0.0 ;
  SIZE 0.75 BY 0.3 ;
  SYMMETRY X Y ;
  PIN A1
    DIRECTION INPUT ;
    USE SIGNAL ;
    PORT
      LAYER M1 ;
      RECT 0.05 0.1 0.10 0.2 ;
    END
  END A1
  PIN A2
    DIRECTION INPUT ;
    USE SIGNAL ;
    PORT
      LAYER M1 ;
      RECT 0.11 0.1 0.16 0.2 ;
    END
  END A2
  PIN B
    DIRECTION INPUT ;
    USE SIGNAL ;
    PORT
      LAYER M1 ;
      RECT 0.17 0.1 0.22 0.2 ;
    END
  END B
  PIN C
    DIRECTION INPUT ;
    USE SIGNAL ;
    PORT
      LAYER M1 ;
      RECT 0.23 0.1 0.28 0.2 ;
    END
  END C
  PIN ZN
    DIRECTION OUTPUT ;
    USE SIGNAL ;
    PORT
      LAYER M1 ;
      RECT 0.29 0.1 0.34 0.2 ;
    END
  END ZN
END AOI211OPTPAD2
MACRO AOI211OPTPAD4
  CLASS CORE ;
  ORIGIN 0.0 0.0 ;
  SIZE 0.75 BY 0.3 ;
  SYMMETRY X Y ;
  PIN A1
    DIRECTION INPUT ;
    USE SIGNAL ;
    PORT
      LAYER M1 ;
      RECT 0.05 0.1 0.10 0.2 ;
    END
  END A1
  PIN A2
    DIRECTION INPUT ;
    USE SIGNAL ;
    PORT
      LAYER M1 ;
      RECT 0.11 0.1 0.16 0.2 ;
    END
  END A2
  PIN B
    DIRECTION INPUT ;
    USE SIGNAL ;
    PORT
      LAYER M1 ;
      RECT 0.17 0.1 0.22 0.2 ;
    END
  END B
  PIN C
    DIRECTION INPUT ;
    USE SIGNAL ;
    PORT
      LAYER M1 ;
      RECT 0.23 0.1 0.28 0.2 ;
    END
  END C
  PIN ZN
    DIRECTION OUTPUT ;
    USE SIGNAL ;
    PORT
      LAYER M1 ;
      RECT 0.29 0.1 0.34 0.2 ;
    END
  END ZN
END AOI211OPTPAD4
MACRO AOI211OPTPAD6
  CLASS CORE ;
  ORIGIN 0.0 0.0 ;
  SIZE 0.75 BY 0.3 ;
  SYMMETRY X Y ;
  PIN A1
    DIRECTION INPUT ;
    USE SIGNAL ;
    PORT
      LAYER M1 ;
      RECT 0.05 0.1 0.10 0.2 ;
    END
  END A1
  PIN A2
    DIRECTION INPUT ;
    USE SIGNAL ;
    PORT
      LAYER M1 ;
      RECT 0.11 0.1 0.16 0.2 ;
    END
  END A2
  PIN B
    DIRECTION INPUT ;
    USE SIGNAL ;
    PORT
      LAYER M1 ;
      RECT 0.17 0.1 0.22 0.2 ;
    END
  END B
  PIN C
    DIRECTION INPUT ;
    USE SIGNAL ;
    PORT
      LAYER M1 ;
      RECT 0.23 0.1 0.28 0.2 ;
    END
  END C
  PIN ZN
    DIRECTION OUTPUT ;
    USE SIGNAL ;
    PORT
      LAYER M1 ;
      RECT 0.29 0.1 0.34 0.2 ;
    END
  END ZN
END AOI211OPTPAD6
MACRO AOI211SKPD1
  CLASS CORE ;
  ORIGIN 0.0 0.0 ;
  SIZE 0.75 BY 0.3 ;
  SYMMETRY X Y ;
  PIN A1
    DIRECTION INPUT ;
    USE SIGNAL ;
    PORT
      LAYER M1 ;
      RECT 0.05 0.1 0.10 0.2 ;
    END
  END A1
  PIN A2
    DIRECTION INPUT ;
    USE SIGNAL ;
    PORT
      LAYER M1 ;
      RECT 0.11 0.1 0.16 0.2 ;
    END
  END A2
  PIN B
    DIRECTION INPUT ;
    USE SIGNAL ;
    PORT
      LAYER M1 ;
      RECT 0.17 0.1 0.22 0.2 ;
    END
  END B
  PIN C
    DIRECTION INPUT ;
    USE SIGNAL ;
    PORT
      LAYER M1 ;
      RECT 0.23 0.1 0.28 0.2 ;
    END
  END C
  PIN ZN
    DIRECTION OUTPUT ;
    USE SIGNAL ;
    PORT
      LAYER M1 ;
      RECT 0.29 0.1 0.34 0.2 ;
    END
  END ZN
END AOI211SKPD1
MACRO AOI211SKPD2
  CLASS CORE ;
  ORIGIN 0.0 0.0 ;
  SIZE 0.75 BY 0.3 ;
  SYMMETRY X Y ;
  PIN A1
    DIRECTION INPUT ;
    USE SIGNAL ;
    PORT
      LAYER M1 ;
      RECT 0.05 0.1 0.10 0.2 ;
    END
  END A1
  PIN A2
    DIRECTION INPUT ;
    USE SIGNAL ;
    PORT
      LAYER M1 ;
      RECT 0.11 0.1 0.16 0.2 ;
    END
  END A2
  PIN B
    DIRECTION INPUT ;
    USE SIGNAL ;
    PORT
      LAYER M1 ;
      RECT 0.17 0.1 0.22 0.2 ;
    END
  END B
  PIN C
    DIRECTION INPUT ;
    USE SIGNAL ;
    PORT
      LAYER M1 ;
      RECT 0.23 0.1 0.28 0.2 ;
    END
  END C
  PIN ZN
    DIRECTION OUTPUT ;
    USE SIGNAL ;
    PORT
      LAYER M1 ;
      RECT 0.29 0.1 0.34 0.2 ;
    END
  END ZN
END AOI211SKPD2
MACRO AOI211SKPD3
  CLASS CORE ;
  ORIGIN 0.0 0.0 ;
  SIZE 0.75 BY 0.3 ;
  SYMMETRY X Y ;
  PIN A1
    DIRECTION INPUT ;
    USE SIGNAL ;
    PORT
      LAYER M1 ;
      RECT 0.05 0.1 0.10 0.2 ;
    END
  END A1
  PIN A2
    DIRECTION INPUT ;
    USE SIGNAL ;
    PORT
      LAYER M1 ;
      RECT 0.11 0.1 0.16 0.2 ;
    END
  END A2
  PIN B
    DIRECTION INPUT ;
    USE SIGNAL ;
    PORT
      LAYER M1 ;
      RECT 0.17 0.1 0.22 0.2 ;
    END
  END B
  PIN C
    DIRECTION INPUT ;
    USE SIGNAL ;
    PORT
      LAYER M1 ;
      RECT 0.23 0.1 0.28 0.2 ;
    END
  END C
  PIN ZN
    DIRECTION OUTPUT ;
    USE SIGNAL ;
    PORT
      LAYER M1 ;
      RECT 0.29 0.1 0.34 0.2 ;
    END
  END ZN
END AOI211SKPD3
MACRO AOI211SKPD4
  CLASS CORE ;
  ORIGIN 0.0 0.0 ;
  SIZE 0.75 BY 0.3 ;
  SYMMETRY X Y ;
  PIN A1
    DIRECTION INPUT ;
    USE SIGNAL ;
    PORT
      LAYER M1 ;
      RECT 0.05 0.1 0.10 0.2 ;
    END
  END A1
  PIN A2
    DIRECTION INPUT ;
    USE SIGNAL ;
    PORT
      LAYER M1 ;
      RECT 0.11 0.1 0.16 0.2 ;
    END
  END A2
  PIN B
    DIRECTION INPUT ;
    USE SIGNAL ;
    PORT
      LAYER M1 ;
      RECT 0.17 0.1 0.22 0.2 ;
    END
  END B
  PIN C
    DIRECTION INPUT ;
    USE SIGNAL ;
    PORT
      LAYER M1 ;
      RECT 0.23 0.1 0.28 0.2 ;
    END
  END C
  PIN ZN
    DIRECTION OUTPUT ;
    USE SIGNAL ;
    PORT
      LAYER M1 ;
      RECT 0.29 0.1 0.34 0.2 ;
    END
  END ZN
END AOI211SKPD4
MACRO AOI211SKPD8
  CLASS CORE ;
  ORIGIN 0.0 0.0 ;
  SIZE 0.75 BY 0.3 ;
  SYMMETRY X Y ;
  PIN A1
    DIRECTION INPUT ;
    USE SIGNAL ;
    PORT
      LAYER M1 ;
      RECT 0.05 0.1 0.10 0.2 ;
    END
  END A1
  PIN A2
    DIRECTION INPUT ;
    USE SIGNAL ;
    PORT
      LAYER M1 ;
      RECT 0.11 0.1 0.16 0.2 ;
    END
  END A2
  PIN B
    DIRECTION INPUT ;
    USE SIGNAL ;
    PORT
      LAYER M1 ;
      RECT 0.17 0.1 0.22 0.2 ;
    END
  END B
  PIN C
    DIRECTION INPUT ;
    USE SIGNAL ;
    PORT
      LAYER M1 ;
      RECT 0.23 0.1 0.28 0.2 ;
    END
  END C
  PIN ZN
    DIRECTION OUTPUT ;
    USE SIGNAL ;
    PORT
      LAYER M1 ;
      RECT 0.29 0.1 0.34 0.2 ;
    END
  END ZN
END AOI211SKPD8
MACRO AOI21D1
  CLASS CORE ;
  ORIGIN 0.0 0.0 ;
  SIZE 0.75 BY 0.3 ;
  SYMMETRY X Y ;
  PIN A1
    DIRECTION INPUT ;
    USE SIGNAL ;
    PORT
      LAYER M1 ;
      RECT 0.05 0.1 0.10 0.2 ;
    END
  END A1
  PIN A2
    DIRECTION INPUT ;
    USE SIGNAL ;
    PORT
      LAYER M1 ;
      RECT 0.12 0.1 0.17 0.2 ;
    END
  END A2
  PIN B
    DIRECTION INPUT ;
    USE SIGNAL ;
    PORT
      LAYER M1 ;
      RECT 0.20 0.1 0.25 0.2 ;
    END
  END B
  PIN ZN
    DIRECTION OUTPUT ;
    USE SIGNAL ;
    PORT
      LAYER M1 ;
      RECT 0.27 0.1 0.32 0.2 ;
    END
  END ZN
END AOI21D1
MACRO AOI21D3
  CLASS CORE ;
  ORIGIN 0.0 0.0 ;
  SIZE 0.75 BY 0.3 ;
  SYMMETRY X Y ;
  PIN A1
    DIRECTION INPUT ;
    USE SIGNAL ;
    PORT
      LAYER M1 ;
      RECT 0.05 0.1 0.10 0.2 ;
    END
  END A1
  PIN A2
    DIRECTION INPUT ;
    USE SIGNAL ;
    PORT
      LAYER M1 ;
      RECT 0.12 0.1 0.17 0.2 ;
    END
  END A2
  PIN B
    DIRECTION INPUT ;
    USE SIGNAL ;
    PORT
      LAYER M1 ;
      RECT 0.20 0.1 0.25 0.2 ;
    END
  END B
  PIN ZN
    DIRECTION OUTPUT ;
    USE SIGNAL ;
    PORT
      LAYER M1 ;
      RECT 0.27 0.1 0.32 0.2 ;
    END
  END ZN
END AOI21D3
MACRO AOI21OPTLD2
  CLASS CORE ;
  ORIGIN 0.0 0.0 ;
  SIZE 0.75 BY 0.3 ;
  SYMMETRY X Y ;
  PIN A1
    DIRECTION INPUT ;
    USE SIGNAL ;
    PORT
      LAYER M1 ;
      RECT 0.05 0.1 0.10 0.2 ;
    END
  END A1
  PIN A2
    DIRECTION INPUT ;
    USE SIGNAL ;
    PORT
      LAYER M1 ;
      RECT 0.12 0.1 0.17 0.2 ;
    END
  END A2
  PIN B
    DIRECTION INPUT ;
    USE SIGNAL ;
    PORT
      LAYER M1 ;
      RECT 0.20 0.1 0.25 0.2 ;
    END
  END B
  PIN ZN
    DIRECTION OUTPUT ;
    USE SIGNAL ;
    PORT
      LAYER M1 ;
      RECT 0.27 0.1 0.32 0.2 ;
    END
  END ZN
END AOI21OPTLD2
MACRO AOI21OPTLD4
  CLASS CORE ;
  ORIGIN 0.0 0.0 ;
  SIZE 0.75 BY 0.3 ;
  SYMMETRY X Y ;
  PIN A1
    DIRECTION INPUT ;
    USE SIGNAL ;
    PORT
      LAYER M1 ;
      RECT 0.05 0.1 0.10 0.2 ;
    END
  END A1
  PIN A2
    DIRECTION INPUT ;
    USE SIGNAL ;
    PORT
      LAYER M1 ;
      RECT 0.12 0.1 0.17 0.2 ;
    END
  END A2
  PIN B
    DIRECTION INPUT ;
    USE SIGNAL ;
    PORT
      LAYER M1 ;
      RECT 0.20 0.1 0.25 0.2 ;
    END
  END B
  PIN ZN
    DIRECTION OUTPUT ;
    USE SIGNAL ;
    PORT
      LAYER M1 ;
      RECT 0.27 0.1 0.32 0.2 ;
    END
  END ZN
END AOI21OPTLD4
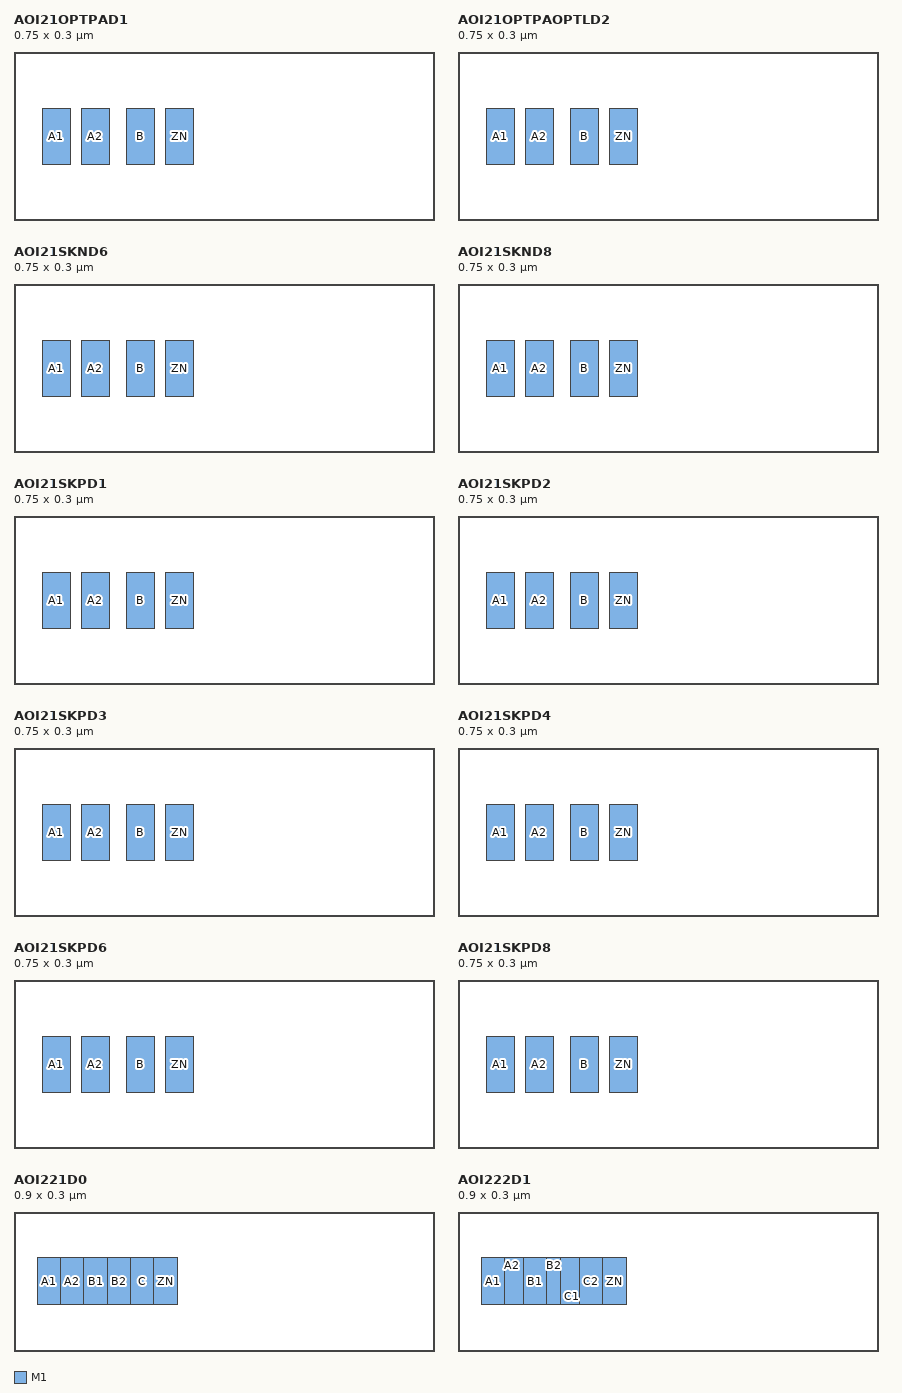
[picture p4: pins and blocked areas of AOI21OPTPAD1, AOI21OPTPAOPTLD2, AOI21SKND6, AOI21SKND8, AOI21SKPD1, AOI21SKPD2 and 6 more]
MACRO AOI21OPTPAD1
  CLASS CORE ;
  ORIGIN 0.0 0.0 ;
  SIZE 0.75 BY 0.3 ;
  SYMMETRY X Y ;
  PIN A1
    DIRECTION INPUT ;
    USE SIGNAL ;
    PORT
      LAYER M1 ;
      RECT 0.05 0.1 0.10 0.2 ;
    END
  END A1
  PIN A2
    DIRECTION INPUT ;
    USE SIGNAL ;
    PORT
      LAYER M1 ;
      RECT 0.12 0.1 0.17 0.2 ;
    END
  END A2
  PIN B
    DIRECTION INPUT ;
    USE SIGNAL ;
    PORT
      LAYER M1 ;
      RECT 0.20 0.1 0.25 0.2 ;
    END
  END B
  PIN ZN
    DIRECTION OUTPUT ;
    USE SIGNAL ;
    PORT
      LAYER M1 ;
      RECT 0.27 0.1 0.32 0.2 ;
    END
  END ZN
END AOI21OPTPAD1
MACRO AOI21OPTPAOPTLD2
  CLASS CORE ;
  ORIGIN 0.0 0.0 ;
  SIZE 0.75 BY 0.3 ;
  SYMMETRY X Y ;
  PIN A1
    DIRECTION INPUT ;
    USE SIGNAL ;
    PORT
      LAYER M1 ;
      RECT 0.05 0.1 0.10 0.2 ;
    END
  END A1
  PIN A2
    DIRECTION INPUT ;
    USE SIGNAL ;
    PORT
      LAYER M1 ;
      RECT 0.12 0.1 0.17 0.2 ;
    END
  END A2
  PIN B
    DIRECTION INPUT ;
    USE SIGNAL ;
    PORT
      LAYER M1 ;
      RECT 0.20 0.1 0.25 0.2 ;
    END
  END B
  PIN ZN
    DIRECTION OUTPUT ;
    USE SIGNAL ;
    PORT
      LAYER M1 ;
      RECT 0.27 0.1 0.32 0.2 ;
    END
  END ZN
END AOI21OPTPAOPTLD2
MACRO AOI21SKND6
  CLASS CORE ;
  ORIGIN 0.0 0.0 ;
  SIZE 0.75 BY 0.3 ;
  SYMMETRY X Y ;
  PIN A1
    DIRECTION INPUT ;
    USE SIGNAL ;
    PORT
      LAYER M1 ;
      RECT 0.05 0.1 0.10 0.2 ;
    END
  END A1
  PIN A2
    DIRECTION INPUT ;
    USE SIGNAL ;
    PORT
      LAYER M1 ;
      RECT 0.12 0.1 0.17 0.2 ;
    END
  END A2
  PIN B
    DIRECTION INPUT ;
    USE SIGNAL ;
    PORT
      LAYER M1 ;
      RECT 0.20 0.1 0.25 0.2 ;
    END
  END B
  PIN ZN
    DIRECTION OUTPUT ;
    USE SIGNAL ;
    PORT
      LAYER M1 ;
      RECT 0.27 0.1 0.32 0.2 ;
    END
  END ZN
END AOI21SKND6
MACRO AOI21SKND8
  CLASS CORE ;
  ORIGIN 0.0 0.0 ;
  SIZE 0.75 BY 0.3 ;
  SYMMETRY X Y ;
  PIN A1
    DIRECTION INPUT ;
    USE SIGNAL ;
    PORT
      LAYER M1 ;
      RECT 0.05 0.1 0.10 0.2 ;
    END
  END A1
  PIN A2
    DIRECTION INPUT ;
    USE SIGNAL ;
    PORT
      LAYER M1 ;
      RECT 0.12 0.1 0.17 0.2 ;
    END
  END A2
  PIN B
    DIRECTION INPUT ;
    USE SIGNAL ;
    PORT
      LAYER M1 ;
      RECT 0.20 0.1 0.25 0.2 ;
    END
  END B
  PIN ZN
    DIRECTION OUTPUT ;
    USE SIGNAL ;
    PORT
      LAYER M1 ;
      RECT 0.27 0.1 0.32 0.2 ;
    END
  END ZN
END AOI21SKND8
MACRO AOI21SKPD1
  CLASS CORE ;
  ORIGIN 0.0 0.0 ;
  SIZE 0.75 BY 0.3 ;
  SYMMETRY X Y ;
  PIN A1
    DIRECTION INPUT ;
    USE SIGNAL ;
    PORT
      LAYER M1 ;
      RECT 0.05 0.1 0.10 0.2 ;
    END
  END A1
  PIN A2
    DIRECTION INPUT ;
    USE SIGNAL ;
    PORT
      LAYER M1 ;
      RECT 0.12 0.1 0.17 0.2 ;
    END
  END A2
  PIN B
    DIRECTION INPUT ;
    USE SIGNAL ;
    PORT
      LAYER M1 ;
      RECT 0.20 0.1 0.25 0.2 ;
    END
  END B
  PIN ZN
    DIRECTION OUTPUT ;
    USE SIGNAL ;
    PORT
      LAYER M1 ;
      RECT 0.27 0.1 0.32 0.2 ;
    END
  END ZN
END AOI21SKPD1
MACRO AOI21SKPD2
  CLASS CORE ;
  ORIGIN 0.0 0.0 ;
  SIZE 0.75 BY 0.3 ;
  SYMMETRY X Y ;
  PIN A1
    DIRECTION INPUT ;
    USE SIGNAL ;
    PORT
      LAYER M1 ;
      RECT 0.05 0.1 0.10 0.2 ;
    END
  END A1
  PIN A2
    DIRECTION INPUT ;
    USE SIGNAL ;
    PORT
      LAYER M1 ;
      RECT 0.12 0.1 0.17 0.2 ;
    END
  END A2
  PIN B
    DIRECTION INPUT ;
    USE SIGNAL ;
    PORT
      LAYER M1 ;
      RECT 0.20 0.1 0.25 0.2 ;
    END
  END B
  PIN ZN
    DIRECTION OUTPUT ;
    USE SIGNAL ;
    PORT
      LAYER M1 ;
      RECT 0.27 0.1 0.32 0.2 ;
    END
  END ZN
END AOI21SKPD2
MACRO AOI21SKPD3
  CLASS CORE ;
  ORIGIN 0.0 0.0 ;
  SIZE 0.75 BY 0.3 ;
  SYMMETRY X Y ;
  PIN A1
    DIRECTION INPUT ;
    USE SIGNAL ;
    PORT
      LAYER M1 ;
      RECT 0.05 0.1 0.10 0.2 ;
    END
  END A1
  PIN A2
    DIRECTION INPUT ;
    USE SIGNAL ;
    PORT
      LAYER M1 ;
      RECT 0.12 0.1 0.17 0.2 ;
    END
  END A2
  PIN B
    DIRECTION INPUT ;
    USE SIGNAL ;
    PORT
      LAYER M1 ;
      RECT 0.20 0.1 0.25 0.2 ;
    END
  END B
  PIN ZN
    DIRECTION OUTPUT ;
    USE SIGNAL ;
    PORT
      LAYER M1 ;
      RECT 0.27 0.1 0.32 0.2 ;
    END
  END ZN
END AOI21SKPD3
MACRO AOI21SKPD4
  CLASS CORE ;
  ORIGIN 0.0 0.0 ;
  SIZE 0.75 BY 0.3 ;
  SYMMETRY X Y ;
  PIN A1
    DIRECTION INPUT ;
    USE SIGNAL ;
    PORT
      LAYER M1 ;
      RECT 0.05 0.1 0.10 0.2 ;
    END
  END A1
  PIN A2
    DIRECTION INPUT ;
    USE SIGNAL ;
    PORT
      LAYER M1 ;
      RECT 0.12 0.1 0.17 0.2 ;
    END
  END A2
  PIN B
    DIRECTION INPUT ;
    USE SIGNAL ;
    PORT
      LAYER M1 ;
      RECT 0.20 0.1 0.25 0.2 ;
    END
  END B
  PIN ZN
    DIRECTION OUTPUT ;
    USE SIGNAL ;
    PORT
      LAYER M1 ;
      RECT 0.27 0.1 0.32 0.2 ;
    END
  END ZN
END AOI21SKPD4
MACRO AOI21SKPD6
  CLASS CORE ;
  ORIGIN 0.0 0.0 ;
  SIZE 0.75 BY 0.3 ;
  SYMMETRY X Y ;
  PIN A1
    DIRECTION INPUT ;
    USE SIGNAL ;
    PORT
      LAYER M1 ;
      RECT 0.05 0.1 0.10 0.2 ;
    END
  END A1
  PIN A2
    DIRECTION INPUT ;
    USE SIGNAL ;
    PORT
      LAYER M1 ;
      RECT 0.12 0.1 0.17 0.2 ;
    END
  END A2
  PIN B
    DIRECTION INPUT ;
    USE SIGNAL ;
    PORT
      LAYER M1 ;
      RECT 0.20 0.1 0.25 0.2 ;
    END
  END B
  PIN ZN
    DIRECTION OUTPUT ;
    USE SIGNAL ;
    PORT
      LAYER M1 ;
      RECT 0.27 0.1 0.32 0.2 ;
    END
  END ZN
END AOI21SKPD6
MACRO AOI21SKPD8
  CLASS CORE ;
  ORIGIN 0.0 0.0 ;
  SIZE 0.75 BY 0.3 ;
  SYMMETRY X Y ;
  PIN A1
    DIRECTION INPUT ;
    USE SIGNAL ;
    PORT
      LAYER M1 ;
      RECT 0.05 0.1 0.10 0.2 ;
    END
  END A1
  PIN A2
    DIRECTION INPUT ;
    USE SIGNAL ;
    PORT
      LAYER M1 ;
      RECT 0.12 0.1 0.17 0.2 ;
    END
  END A2
  PIN B
    DIRECTION INPUT ;
    USE SIGNAL ;
    PORT
      LAYER M1 ;
      RECT 0.20 0.1 0.25 0.2 ;
    END
  END B
  PIN ZN
    DIRECTION OUTPUT ;
    USE SIGNAL ;
    PORT
      LAYER M1 ;
      RECT 0.27 0.1 0.32 0.2 ;
    END
  END ZN
END AOI21SKPD8
MACRO AOI221D0
  CLASS CORE ;
  ORIGIN 0.0 0.0 ;
  SIZE 0.9 BY 0.3 ;
  SYMMETRY X Y ;
  PIN A1
    DIRECTION INPUT ;
    USE SIGNAL ;
    PORT
      LAYER M1 ;
      RECT 0.05 0.1 0.10 0.2 ;
    END
  END A1
  PIN A2
    DIRECTION INPUT ;
    USE SIGNAL ;
    PORT
      LAYER M1 ;
      RECT 0.10 0.1 0.15 0.2 ;
    END
  END A2
  PIN B1
    DIRECTION INPUT ;
    USE SIGNAL ;
    PORT
      LAYER M1 ;
      RECT 0.15 0.1 0.20 0.2 ;
    END
  END B1
  PIN B2
    DIRECTION INPUT ;
    USE SIGNAL ;
    PORT
      LAYER M1 ;
      RECT 0.20 0.1 0.25 0.2 ;
    END
  END B2
  PIN C
    DIRECTION INPUT ;
    USE SIGNAL ;
    PORT
      LAYER M1 ;
      RECT 0.25 0.1 0.30 0.2 ;
    END
  END C
  PIN ZN
    DIRECTION OUTPUT ;
    USE SIGNAL ;
    PORT
      LAYER M1 ;
      RECT 0.30 0.1 0.35 0.2 ;
    END
  END ZN
END AOI221D0
MACRO AOI222D1
  CLASS CORE ;
  ORIGIN 0.0 0.0 ;
  SIZE 0.9 BY 0.3 ;
  SYMMETRY X Y ;
  PIN A1
    DIRECTION INPUT ;
    USE SIGNAL ;
    PORT
      LAYER M1 ;
      RECT 0.05 0.1 0.10 0.2 ;
    END
  END A1
  PIN A2
    DIRECTION INPUT ;
    USE SIGNAL ;
    PORT
      LAYER M1 ;
      RECT 0.09 0.1 0.14 0.2 ;
    END
  END A2
  PIN B1
    DIRECTION INPUT ;
    USE SIGNAL ;
    PORT
      LAYER M1 ;
      RECT 0.14 0.1 0.19 0.2 ;
    END
  END B1
  PIN B2
    DIRECTION INPUT ;
    USE SIGNAL ;
    PORT
      LAYER M1 ;
      RECT 0.18 0.1 0.23 0.2 ;
    END
  END B2
  PIN C1
    DIRECTION INPUT ;
    USE SIGNAL ;
    PORT
      LAYER M1 ;
      RECT 0.22 0.1 0.27 0.2 ;
    END
  END C1
  PIN C2
    DIRECTION INPUT ;
    USE SIGNAL ;
    PORT
      LAYER M1 ;
      RECT 0.26 0.1 0.31 0.2 ;
    END
  END C2
  PIN ZN
    DIRECTION OUTPUT ;
    USE SIGNAL ;
    PORT
      LAYER M1 ;
      RECT 0.31 0.1 0.36 0.2 ;
    END
  END ZN
END AOI222D1
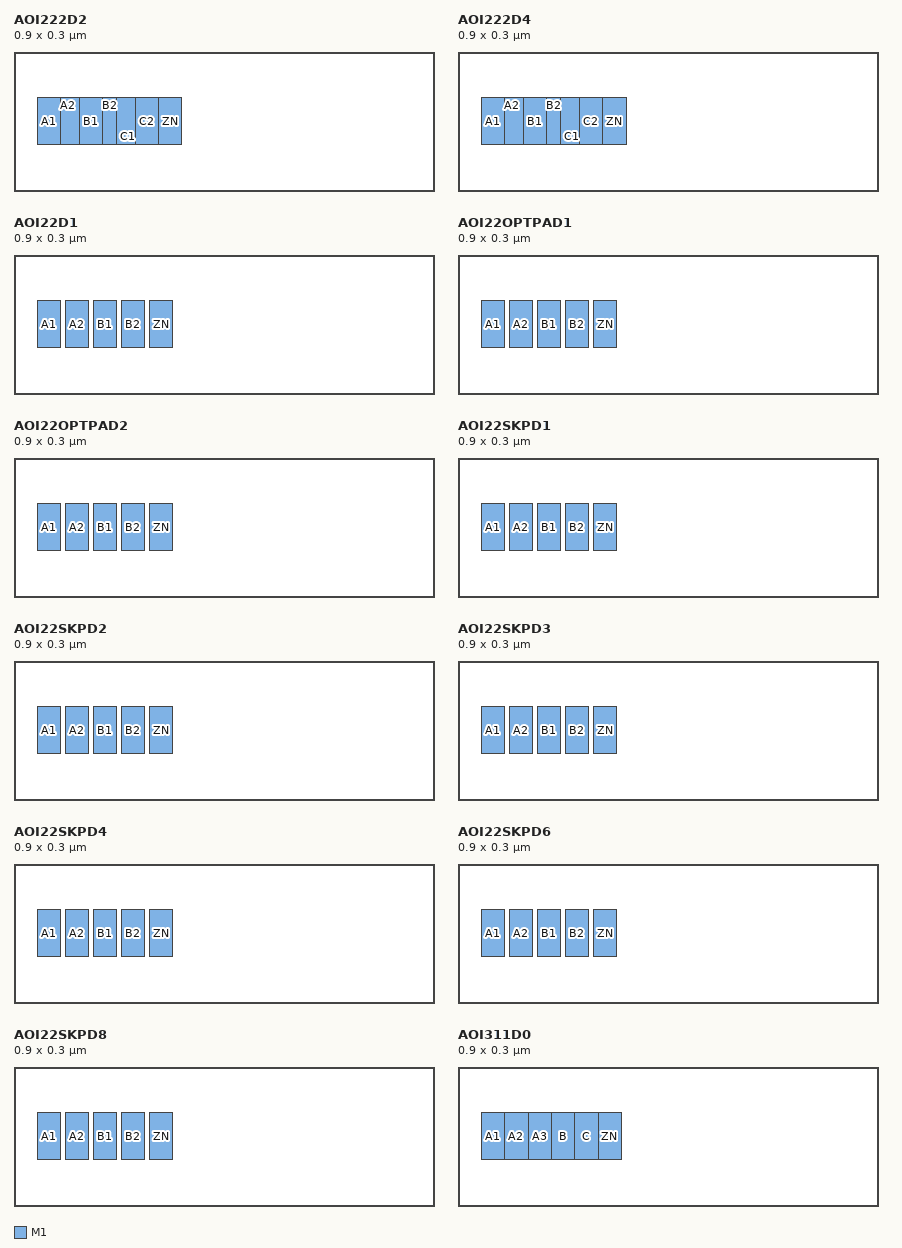
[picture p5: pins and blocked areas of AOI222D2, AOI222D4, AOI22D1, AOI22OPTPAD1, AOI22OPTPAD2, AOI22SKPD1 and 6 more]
MACRO AOI222D2
  CLASS CORE ;
  ORIGIN 0.0 0.0 ;
  SIZE 0.9 BY 0.3 ;
  SYMMETRY X Y ;
  PIN A1
    DIRECTION INPUT ;
    USE SIGNAL ;
    PORT
      LAYER M1 ;
      RECT 0.05 0.1 0.10 0.2 ;
    END
  END A1
  PIN A2
    DIRECTION INPUT ;
    USE SIGNAL ;
    PORT
      LAYER M1 ;
      RECT 0.09 0.1 0.14 0.2 ;
    END
  END A2
  PIN B1
    DIRECTION INPUT ;
    USE SIGNAL ;
    PORT
      LAYER M1 ;
      RECT 0.14 0.1 0.19 0.2 ;
    END
  END B1
  PIN B2
    DIRECTION INPUT ;
    USE SIGNAL ;
    PORT
      LAYER M1 ;
      RECT 0.18 0.1 0.23 0.2 ;
    END
  END B2
  PIN C1
    DIRECTION INPUT ;
    USE SIGNAL ;
    PORT
      LAYER M1 ;
      RECT 0.22 0.1 0.27 0.2 ;
    END
  END C1
  PIN C2
    DIRECTION INPUT ;
    USE SIGNAL ;
    PORT
      LAYER M1 ;
      RECT 0.26 0.1 0.31 0.2 ;
    END
  END C2
  PIN ZN
    DIRECTION OUTPUT ;
    USE SIGNAL ;
    PORT
      LAYER M1 ;
      RECT 0.31 0.1 0.36 0.2 ;
    END
  END ZN
END AOI222D2
MACRO AOI222D4
  CLASS CORE ;
  ORIGIN 0.0 0.0 ;
  SIZE 0.9 BY 0.3 ;
  SYMMETRY X Y ;
  PIN A1
    DIRECTION INPUT ;
    USE SIGNAL ;
    PORT
      LAYER M1 ;
      RECT 0.05 0.1 0.10 0.2 ;
    END
  END A1
  PIN A2
    DIRECTION INPUT ;
    USE SIGNAL ;
    PORT
      LAYER M1 ;
      RECT 0.09 0.1 0.14 0.2 ;
    END
  END A2
  PIN B1
    DIRECTION INPUT ;
    USE SIGNAL ;
    PORT
      LAYER M1 ;
      RECT 0.14 0.1 0.19 0.2 ;
    END
  END B1
  PIN B2
    DIRECTION INPUT ;
    USE SIGNAL ;
    PORT
      LAYER M1 ;
      RECT 0.18 0.1 0.23 0.2 ;
    END
  END B2
  PIN C1
    DIRECTION INPUT ;
    USE SIGNAL ;
    PORT
      LAYER M1 ;
      RECT 0.22 0.1 0.27 0.2 ;
    END
  END C1
  PIN C2
    DIRECTION INPUT ;
    USE SIGNAL ;
    PORT
      LAYER M1 ;
      RECT 0.26 0.1 0.31 0.2 ;
    END
  END C2
  PIN ZN
    DIRECTION OUTPUT ;
    USE SIGNAL ;
    PORT
      LAYER M1 ;
      RECT 0.31 0.1 0.36 0.2 ;
    END
  END ZN
END AOI222D4
MACRO AOI22D1
  CLASS CORE ;
  ORIGIN 0.0 0.0 ;
  SIZE 0.9 BY 0.3 ;
  SYMMETRY X Y ;
  PIN A1
    DIRECTION INPUT ;
    USE SIGNAL ;
    PORT
      LAYER M1 ;
      RECT 0.05 0.1 0.10 0.2 ;
    END
  END A1
  PIN A2
    DIRECTION INPUT ;
    USE SIGNAL ;
    PORT
      LAYER M1 ;
      RECT 0.11 0.1 0.16 0.2 ;
    END
  END A2
  PIN B1
    DIRECTION INPUT ;
    USE SIGNAL ;
    PORT
      LAYER M1 ;
      RECT 0.17 0.1 0.22 0.2 ;
    END
  END B1
  PIN B2
    DIRECTION INPUT ;
    USE SIGNAL ;
    PORT
      LAYER M1 ;
      RECT 0.23 0.1 0.28 0.2 ;
    END
  END B2
  PIN ZN
    DIRECTION OUTPUT ;
    USE SIGNAL ;
    PORT
      LAYER M1 ;
      RECT 0.29 0.1 0.34 0.2 ;
    END
  END ZN
END AOI22D1
MACRO AOI22OPTPAD1
  CLASS CORE ;
  ORIGIN 0.0 0.0 ;
  SIZE 0.9 BY 0.3 ;
  SYMMETRY X Y ;
  PIN A1
    DIRECTION INPUT ;
    USE SIGNAL ;
    PORT
      LAYER M1 ;
      RECT 0.05 0.1 0.10 0.2 ;
    END
  END A1
  PIN A2
    DIRECTION INPUT ;
    USE SIGNAL ;
    PORT
      LAYER M1 ;
      RECT 0.11 0.1 0.16 0.2 ;
    END
  END A2
  PIN B1
    DIRECTION INPUT ;
    USE SIGNAL ;
    PORT
      LAYER M1 ;
      RECT 0.17 0.1 0.22 0.2 ;
    END
  END B1
  PIN B2
    DIRECTION INPUT ;
    USE SIGNAL ;
    PORT
      LAYER M1 ;
      RECT 0.23 0.1 0.28 0.2 ;
    END
  END B2
  PIN ZN
    DIRECTION OUTPUT ;
    USE SIGNAL ;
    PORT
      LAYER M1 ;
      RECT 0.29 0.1 0.34 0.2 ;
    END
  END ZN
END AOI22OPTPAD1
MACRO AOI22OPTPAD2
  CLASS CORE ;
  ORIGIN 0.0 0.0 ;
  SIZE 0.9 BY 0.3 ;
  SYMMETRY X Y ;
  PIN A1
    DIRECTION INPUT ;
    USE SIGNAL ;
    PORT
      LAYER M1 ;
      RECT 0.05 0.1 0.10 0.2 ;
    END
  END A1
  PIN A2
    DIRECTION INPUT ;
    USE SIGNAL ;
    PORT
      LAYER M1 ;
      RECT 0.11 0.1 0.16 0.2 ;
    END
  END A2
  PIN B1
    DIRECTION INPUT ;
    USE SIGNAL ;
    PORT
      LAYER M1 ;
      RECT 0.17 0.1 0.22 0.2 ;
    END
  END B1
  PIN B2
    DIRECTION INPUT ;
    USE SIGNAL ;
    PORT
      LAYER M1 ;
      RECT 0.23 0.1 0.28 0.2 ;
    END
  END B2
  PIN ZN
    DIRECTION OUTPUT ;
    USE SIGNAL ;
    PORT
      LAYER M1 ;
      RECT 0.29 0.1 0.34 0.2 ;
    END
  END ZN
END AOI22OPTPAD2
MACRO AOI22SKPD1
  CLASS CORE ;
  ORIGIN 0.0 0.0 ;
  SIZE 0.9 BY 0.3 ;
  SYMMETRY X Y ;
  PIN A1
    DIRECTION INPUT ;
    USE SIGNAL ;
    PORT
      LAYER M1 ;
      RECT 0.05 0.1 0.10 0.2 ;
    END
  END A1
  PIN A2
    DIRECTION INPUT ;
    USE SIGNAL ;
    PORT
      LAYER M1 ;
      RECT 0.11 0.1 0.16 0.2 ;
    END
  END A2
  PIN B1
    DIRECTION INPUT ;
    USE SIGNAL ;
    PORT
      LAYER M1 ;
      RECT 0.17 0.1 0.22 0.2 ;
    END
  END B1
  PIN B2
    DIRECTION INPUT ;
    USE SIGNAL ;
    PORT
      LAYER M1 ;
      RECT 0.23 0.1 0.28 0.2 ;
    END
  END B2
  PIN ZN
    DIRECTION OUTPUT ;
    USE SIGNAL ;
    PORT
      LAYER M1 ;
      RECT 0.29 0.1 0.34 0.2 ;
    END
  END ZN
END AOI22SKPD1
MACRO AOI22SKPD2
  CLASS CORE ;
  ORIGIN 0.0 0.0 ;
  SIZE 0.9 BY 0.3 ;
  SYMMETRY X Y ;
  PIN A1
    DIRECTION INPUT ;
    USE SIGNAL ;
    PORT
      LAYER M1 ;
      RECT 0.05 0.1 0.10 0.2 ;
    END
  END A1
  PIN A2
    DIRECTION INPUT ;
    USE SIGNAL ;
    PORT
      LAYER M1 ;
      RECT 0.11 0.1 0.16 0.2 ;
    END
  END A2
  PIN B1
    DIRECTION INPUT ;
    USE SIGNAL ;
    PORT
      LAYER M1 ;
      RECT 0.17 0.1 0.22 0.2 ;
    END
  END B1
  PIN B2
    DIRECTION INPUT ;
    USE SIGNAL ;
    PORT
      LAYER M1 ;
      RECT 0.23 0.1 0.28 0.2 ;
    END
  END B2
  PIN ZN
    DIRECTION OUTPUT ;
    USE SIGNAL ;
    PORT
      LAYER M1 ;
      RECT 0.29 0.1 0.34 0.2 ;
    END
  END ZN
END AOI22SKPD2
MACRO AOI22SKPD3
  CLASS CORE ;
  ORIGIN 0.0 0.0 ;
  SIZE 0.9 BY 0.3 ;
  SYMMETRY X Y ;
  PIN A1
    DIRECTION INPUT ;
    USE SIGNAL ;
    PORT
      LAYER M1 ;
      RECT 0.05 0.1 0.10 0.2 ;
    END
  END A1
  PIN A2
    DIRECTION INPUT ;
    USE SIGNAL ;
    PORT
      LAYER M1 ;
      RECT 0.11 0.1 0.16 0.2 ;
    END
  END A2
  PIN B1
    DIRECTION INPUT ;
    USE SIGNAL ;
    PORT
      LAYER M1 ;
      RECT 0.17 0.1 0.22 0.2 ;
    END
  END B1
  PIN B2
    DIRECTION INPUT ;
    USE SIGNAL ;
    PORT
      LAYER M1 ;
      RECT 0.23 0.1 0.28 0.2 ;
    END
  END B2
  PIN ZN
    DIRECTION OUTPUT ;
    USE SIGNAL ;
    PORT
      LAYER M1 ;
      RECT 0.29 0.1 0.34 0.2 ;
    END
  END ZN
END AOI22SKPD3
MACRO AOI22SKPD4
  CLASS CORE ;
  ORIGIN 0.0 0.0 ;
  SIZE 0.9 BY 0.3 ;
  SYMMETRY X Y ;
  PIN A1
    DIRECTION INPUT ;
    USE SIGNAL ;
    PORT
      LAYER M1 ;
      RECT 0.05 0.1 0.10 0.2 ;
    END
  END A1
  PIN A2
    DIRECTION INPUT ;
    USE SIGNAL ;
    PORT
      LAYER M1 ;
      RECT 0.11 0.1 0.16 0.2 ;
    END
  END A2
  PIN B1
    DIRECTION INPUT ;
    USE SIGNAL ;
    PORT
      LAYER M1 ;
      RECT 0.17 0.1 0.22 0.2 ;
    END
  END B1
  PIN B2
    DIRECTION INPUT ;
    USE SIGNAL ;
    PORT
      LAYER M1 ;
      RECT 0.23 0.1 0.28 0.2 ;
    END
  END B2
  PIN ZN
    DIRECTION OUTPUT ;
    USE SIGNAL ;
    PORT
      LAYER M1 ;
      RECT 0.29 0.1 0.34 0.2 ;
    END
  END ZN
END AOI22SKPD4
MACRO AOI22SKPD6
  CLASS CORE ;
  ORIGIN 0.0 0.0 ;
  SIZE 0.9 BY 0.3 ;
  SYMMETRY X Y ;
  PIN A1
    DIRECTION INPUT ;
    USE SIGNAL ;
    PORT
      LAYER M1 ;
      RECT 0.05 0.1 0.10 0.2 ;
    END
  END A1
  PIN A2
    DIRECTION INPUT ;
    USE SIGNAL ;
    PORT
      LAYER M1 ;
      RECT 0.11 0.1 0.16 0.2 ;
    END
  END A2
  PIN B1
    DIRECTION INPUT ;
    USE SIGNAL ;
    PORT
      LAYER M1 ;
      RECT 0.17 0.1 0.22 0.2 ;
    END
  END B1
  PIN B2
    DIRECTION INPUT ;
    USE SIGNAL ;
    PORT
      LAYER M1 ;
      RECT 0.23 0.1 0.28 0.2 ;
    END
  END B2
  PIN ZN
    DIRECTION OUTPUT ;
    USE SIGNAL ;
    PORT
      LAYER M1 ;
      RECT 0.29 0.1 0.34 0.2 ;
    END
  END ZN
END AOI22SKPD6
MACRO AOI22SKPD8
  CLASS CORE ;
  ORIGIN 0.0 0.0 ;
  SIZE 0.9 BY 0.3 ;
  SYMMETRY X Y ;
  PIN A1
    DIRECTION INPUT ;
    USE SIGNAL ;
    PORT
      LAYER M1 ;
      RECT 0.05 0.1 0.10 0.2 ;
    END
  END A1
  PIN A2
    DIRECTION INPUT ;
    USE SIGNAL ;
    PORT
      LAYER M1 ;
      RECT 0.11 0.1 0.16 0.2 ;
    END
  END A2
  PIN B1
    DIRECTION INPUT ;
    USE SIGNAL ;
    PORT
      LAYER M1 ;
      RECT 0.17 0.1 0.22 0.2 ;
    END
  END B1
  PIN B2
    DIRECTION INPUT ;
    USE SIGNAL ;
    PORT
      LAYER M1 ;
      RECT 0.23 0.1 0.28 0.2 ;
    END
  END B2
  PIN ZN
    DIRECTION OUTPUT ;
    USE SIGNAL ;
    PORT
      LAYER M1 ;
      RECT 0.29 0.1 0.34 0.2 ;
    END
  END ZN
END AOI22SKPD8
MACRO AOI311D0
  CLASS CORE ;
  ORIGIN 0.0 0.0 ;
  SIZE 0.9 BY 0.3 ;
  SYMMETRY X Y ;
  PIN A1
    DIRECTION INPUT ;
    USE SIGNAL ;
    PORT
      LAYER M1 ;
      RECT 0.05 0.1 0.10 0.2 ;
    END
  END A1
  PIN A2
    DIRECTION INPUT ;
    USE SIGNAL ;
    PORT
      LAYER M1 ;
      RECT 0.10 0.1 0.15 0.2 ;
    END
  END A2
  PIN A3
    DIRECTION INPUT ;
    USE SIGNAL ;
    PORT
      LAYER M1 ;
      RECT 0.15 0.1 0.20 0.2 ;
    END
  END A3
  PIN B
    DIRECTION INPUT ;
    USE SIGNAL ;
    PORT
      LAYER M1 ;
      RECT 0.20 0.1 0.25 0.2 ;
    END
  END B
  PIN C
    DIRECTION INPUT ;
    USE SIGNAL ;
    PORT
      LAYER M1 ;
      RECT 0.25 0.1 0.30 0.2 ;
    END
  END C
  PIN ZN
    DIRECTION OUTPUT ;
    USE SIGNAL ;
    PORT
      LAYER M1 ;
      RECT 0.30 0.1 0.35 0.2 ;
    END
  END ZN
END AOI311D0
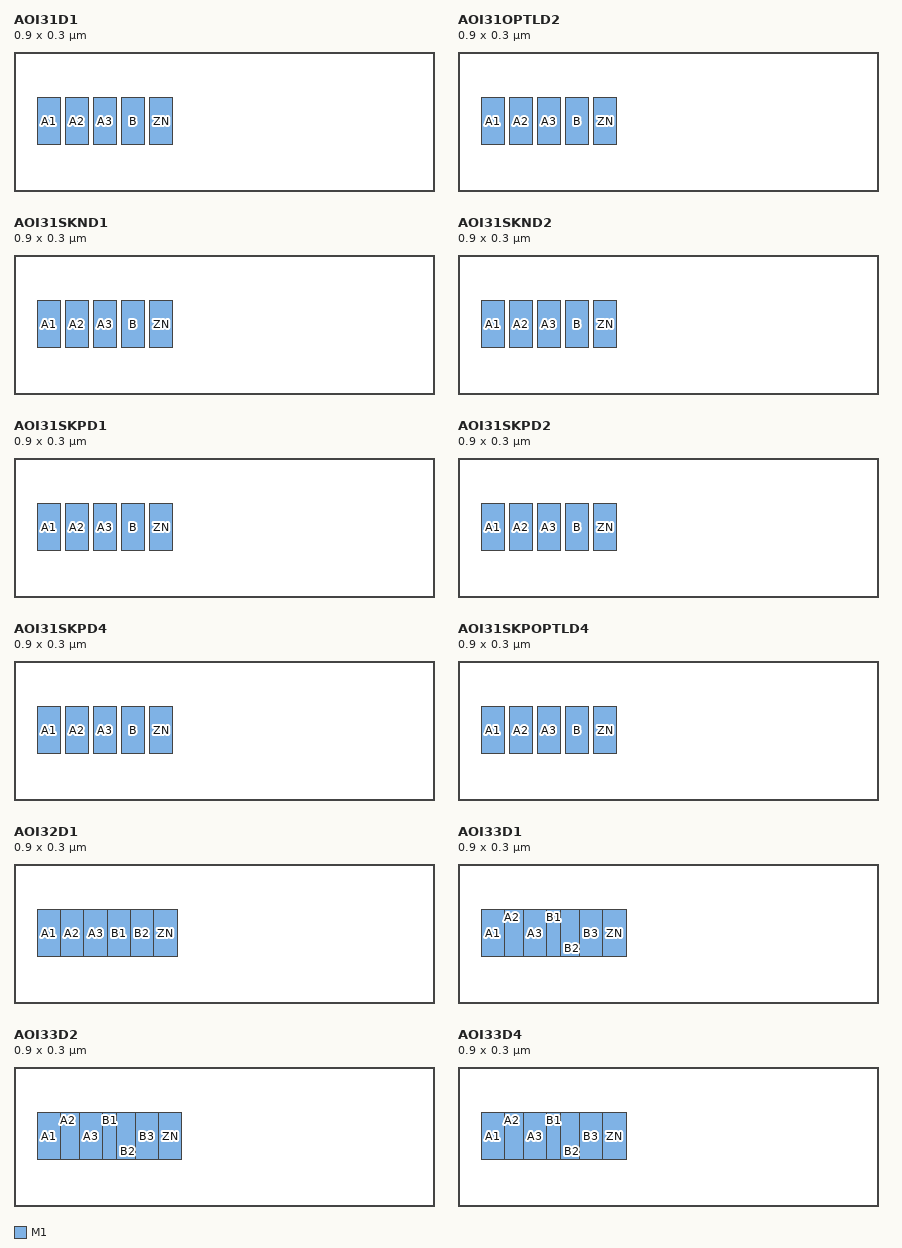
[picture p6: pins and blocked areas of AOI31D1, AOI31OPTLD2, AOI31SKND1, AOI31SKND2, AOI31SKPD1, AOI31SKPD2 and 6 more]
MACRO AOI31D1
  CLASS CORE ;
  ORIGIN 0.0 0.0 ;
  SIZE 0.9 BY 0.3 ;
  SYMMETRY X Y ;
  PIN A1
    DIRECTION INPUT ;
    USE SIGNAL ;
    PORT
      LAYER M1 ;
      RECT 0.05 0.1 0.10 0.2 ;
    END
  END A1
  PIN A2
    DIRECTION INPUT ;
    USE SIGNAL ;
    PORT
      LAYER M1 ;
      RECT 0.11 0.1 0.16 0.2 ;
    END
  END A2
  PIN A3
    DIRECTION INPUT ;
    USE SIGNAL ;
    PORT
      LAYER M1 ;
      RECT 0.17 0.1 0.22 0.2 ;
    END
  END A3
  PIN B
    DIRECTION INPUT ;
    USE SIGNAL ;
    PORT
      LAYER M1 ;
      RECT 0.23 0.1 0.28 0.2 ;
    END
  END B
  PIN ZN
    DIRECTION OUTPUT ;
    USE SIGNAL ;
    PORT
      LAYER M1 ;
      RECT 0.29 0.1 0.34 0.2 ;
    END
  END ZN
END AOI31D1
MACRO AOI31OPTLD2
  CLASS CORE ;
  ORIGIN 0.0 0.0 ;
  SIZE 0.9 BY 0.3 ;
  SYMMETRY X Y ;
  PIN A1
    DIRECTION INPUT ;
    USE SIGNAL ;
    PORT
      LAYER M1 ;
      RECT 0.05 0.1 0.10 0.2 ;
    END
  END A1
  PIN A2
    DIRECTION INPUT ;
    USE SIGNAL ;
    PORT
      LAYER M1 ;
      RECT 0.11 0.1 0.16 0.2 ;
    END
  END A2
  PIN A3
    DIRECTION INPUT ;
    USE SIGNAL ;
    PORT
      LAYER M1 ;
      RECT 0.17 0.1 0.22 0.2 ;
    END
  END A3
  PIN B
    DIRECTION INPUT ;
    USE SIGNAL ;
    PORT
      LAYER M1 ;
      RECT 0.23 0.1 0.28 0.2 ;
    END
  END B
  PIN ZN
    DIRECTION OUTPUT ;
    USE SIGNAL ;
    PORT
      LAYER M1 ;
      RECT 0.29 0.1 0.34 0.2 ;
    END
  END ZN
END AOI31OPTLD2
MACRO AOI31SKND1
  CLASS CORE ;
  ORIGIN 0.0 0.0 ;
  SIZE 0.9 BY 0.3 ;
  SYMMETRY X Y ;
  PIN A1
    DIRECTION INPUT ;
    USE SIGNAL ;
    PORT
      LAYER M1 ;
      RECT 0.05 0.1 0.10 0.2 ;
    END
  END A1
  PIN A2
    DIRECTION INPUT ;
    USE SIGNAL ;
    PORT
      LAYER M1 ;
      RECT 0.11 0.1 0.16 0.2 ;
    END
  END A2
  PIN A3
    DIRECTION INPUT ;
    USE SIGNAL ;
    PORT
      LAYER M1 ;
      RECT 0.17 0.1 0.22 0.2 ;
    END
  END A3
  PIN B
    DIRECTION INPUT ;
    USE SIGNAL ;
    PORT
      LAYER M1 ;
      RECT 0.23 0.1 0.28 0.2 ;
    END
  END B
  PIN ZN
    DIRECTION OUTPUT ;
    USE SIGNAL ;
    PORT
      LAYER M1 ;
      RECT 0.29 0.1 0.34 0.2 ;
    END
  END ZN
END AOI31SKND1
MACRO AOI31SKND2
  CLASS CORE ;
  ORIGIN 0.0 0.0 ;
  SIZE 0.9 BY 0.3 ;
  SYMMETRY X Y ;
  PIN A1
    DIRECTION INPUT ;
    USE SIGNAL ;
    PORT
      LAYER M1 ;
      RECT 0.05 0.1 0.10 0.2 ;
    END
  END A1
  PIN A2
    DIRECTION INPUT ;
    USE SIGNAL ;
    PORT
      LAYER M1 ;
      RECT 0.11 0.1 0.16 0.2 ;
    END
  END A2
  PIN A3
    DIRECTION INPUT ;
    USE SIGNAL ;
    PORT
      LAYER M1 ;
      RECT 0.17 0.1 0.22 0.2 ;
    END
  END A3
  PIN B
    DIRECTION INPUT ;
    USE SIGNAL ;
    PORT
      LAYER M1 ;
      RECT 0.23 0.1 0.28 0.2 ;
    END
  END B
  PIN ZN
    DIRECTION OUTPUT ;
    USE SIGNAL ;
    PORT
      LAYER M1 ;
      RECT 0.29 0.1 0.34 0.2 ;
    END
  END ZN
END AOI31SKND2
MACRO AOI31SKPD1
  CLASS CORE ;
  ORIGIN 0.0 0.0 ;
  SIZE 0.9 BY 0.3 ;
  SYMMETRY X Y ;
  PIN A1
    DIRECTION INPUT ;
    USE SIGNAL ;
    PORT
      LAYER M1 ;
      RECT 0.05 0.1 0.10 0.2 ;
    END
  END A1
  PIN A2
    DIRECTION INPUT ;
    USE SIGNAL ;
    PORT
      LAYER M1 ;
      RECT 0.11 0.1 0.16 0.2 ;
    END
  END A2
  PIN A3
    DIRECTION INPUT ;
    USE SIGNAL ;
    PORT
      LAYER M1 ;
      RECT 0.17 0.1 0.22 0.2 ;
    END
  END A3
  PIN B
    DIRECTION INPUT ;
    USE SIGNAL ;
    PORT
      LAYER M1 ;
      RECT 0.23 0.1 0.28 0.2 ;
    END
  END B
  PIN ZN
    DIRECTION OUTPUT ;
    USE SIGNAL ;
    PORT
      LAYER M1 ;
      RECT 0.29 0.1 0.34 0.2 ;
    END
  END ZN
END AOI31SKPD1
MACRO AOI31SKPD2
  CLASS CORE ;
  ORIGIN 0.0 0.0 ;
  SIZE 0.9 BY 0.3 ;
  SYMMETRY X Y ;
  PIN A1
    DIRECTION INPUT ;
    USE SIGNAL ;
    PORT
      LAYER M1 ;
      RECT 0.05 0.1 0.10 0.2 ;
    END
  END A1
  PIN A2
    DIRECTION INPUT ;
    USE SIGNAL ;
    PORT
      LAYER M1 ;
      RECT 0.11 0.1 0.16 0.2 ;
    END
  END A2
  PIN A3
    DIRECTION INPUT ;
    USE SIGNAL ;
    PORT
      LAYER M1 ;
      RECT 0.17 0.1 0.22 0.2 ;
    END
  END A3
  PIN B
    DIRECTION INPUT ;
    USE SIGNAL ;
    PORT
      LAYER M1 ;
      RECT 0.23 0.1 0.28 0.2 ;
    END
  END B
  PIN ZN
    DIRECTION OUTPUT ;
    USE SIGNAL ;
    PORT
      LAYER M1 ;
      RECT 0.29 0.1 0.34 0.2 ;
    END
  END ZN
END AOI31SKPD2
MACRO AOI31SKPD4
  CLASS CORE ;
  ORIGIN 0.0 0.0 ;
  SIZE 0.9 BY 0.3 ;
  SYMMETRY X Y ;
  PIN A1
    DIRECTION INPUT ;
    USE SIGNAL ;
    PORT
      LAYER M1 ;
      RECT 0.05 0.1 0.10 0.2 ;
    END
  END A1
  PIN A2
    DIRECTION INPUT ;
    USE SIGNAL ;
    PORT
      LAYER M1 ;
      RECT 0.11 0.1 0.16 0.2 ;
    END
  END A2
  PIN A3
    DIRECTION INPUT ;
    USE SIGNAL ;
    PORT
      LAYER M1 ;
      RECT 0.17 0.1 0.22 0.2 ;
    END
  END A3
  PIN B
    DIRECTION INPUT ;
    USE SIGNAL ;
    PORT
      LAYER M1 ;
      RECT 0.23 0.1 0.28 0.2 ;
    END
  END B
  PIN ZN
    DIRECTION OUTPUT ;
    USE SIGNAL ;
    PORT
      LAYER M1 ;
      RECT 0.29 0.1 0.34 0.2 ;
    END
  END ZN
END AOI31SKPD4
MACRO AOI31SKPOPTLD4
  CLASS CORE ;
  ORIGIN 0.0 0.0 ;
  SIZE 0.9 BY 0.3 ;
  SYMMETRY X Y ;
  PIN A1
    DIRECTION INPUT ;
    USE SIGNAL ;
    PORT
      LAYER M1 ;
      RECT 0.05 0.1 0.10 0.2 ;
    END
  END A1
  PIN A2
    DIRECTION INPUT ;
    USE SIGNAL ;
    PORT
      LAYER M1 ;
      RECT 0.11 0.1 0.16 0.2 ;
    END
  END A2
  PIN A3
    DIRECTION INPUT ;
    USE SIGNAL ;
    PORT
      LAYER M1 ;
      RECT 0.17 0.1 0.22 0.2 ;
    END
  END A3
  PIN B
    DIRECTION INPUT ;
    USE SIGNAL ;
    PORT
      LAYER M1 ;
      RECT 0.23 0.1 0.28 0.2 ;
    END
  END B
  PIN ZN
    DIRECTION OUTPUT ;
    USE SIGNAL ;
    PORT
      LAYER M1 ;
      RECT 0.29 0.1 0.34 0.2 ;
    END
  END ZN
END AOI31SKPOPTLD4
MACRO AOI32D1
  CLASS CORE ;
  ORIGIN 0.0 0.0 ;
  SIZE 0.9 BY 0.3 ;
  SYMMETRY X Y ;
  PIN A1
    DIRECTION INPUT ;
    USE SIGNAL ;
    PORT
      LAYER M1 ;
      RECT 0.05 0.1 0.10 0.2 ;
    END
  END A1
  PIN A2
    DIRECTION INPUT ;
    USE SIGNAL ;
    PORT
      LAYER M1 ;
      RECT 0.10 0.1 0.15 0.2 ;
    END
  END A2
  PIN A3
    DIRECTION INPUT ;
    USE SIGNAL ;
    PORT
      LAYER M1 ;
      RECT 0.15 0.1 0.20 0.2 ;
    END
  END A3
  PIN B1
    DIRECTION INPUT ;
    USE SIGNAL ;
    PORT
      LAYER M1 ;
      RECT 0.20 0.1 0.25 0.2 ;
    END
  END B1
  PIN B2
    DIRECTION INPUT ;
    USE SIGNAL ;
    PORT
      LAYER M1 ;
      RECT 0.25 0.1 0.30 0.2 ;
    END
  END B2
  PIN ZN
    DIRECTION OUTPUT ;
    USE SIGNAL ;
    PORT
      LAYER M1 ;
      RECT 0.30 0.1 0.35 0.2 ;
    END
  END ZN
END AOI32D1
MACRO AOI33D1
  CLASS CORE ;
  ORIGIN 0.0 0.0 ;
  SIZE 0.9 BY 0.3 ;
  SYMMETRY X Y ;
  PIN A1
    DIRECTION INPUT ;
    USE SIGNAL ;
    PORT
      LAYER M1 ;
      RECT 0.05 0.1 0.10 0.2 ;
    END
  END A1
  PIN A2
    DIRECTION INPUT ;
    USE SIGNAL ;
    PORT
      LAYER M1 ;
      RECT 0.09 0.1 0.14 0.2 ;
    END
  END A2
  PIN A3
    DIRECTION INPUT ;
    USE SIGNAL ;
    PORT
      LAYER M1 ;
      RECT 0.14 0.1 0.19 0.2 ;
    END
  END A3
  PIN B1
    DIRECTION INPUT ;
    USE SIGNAL ;
    PORT
      LAYER M1 ;
      RECT 0.18 0.1 0.23 0.2 ;
    END
  END B1
  PIN B2
    DIRECTION INPUT ;
    USE SIGNAL ;
    PORT
      LAYER M1 ;
      RECT 0.22 0.1 0.27 0.2 ;
    END
  END B2
  PIN B3
    DIRECTION INPUT ;
    USE SIGNAL ;
    PORT
      LAYER M1 ;
      RECT 0.26 0.1 0.31 0.2 ;
    END
  END B3
  PIN ZN
    DIRECTION OUTPUT ;
    USE SIGNAL ;
    PORT
      LAYER M1 ;
      RECT 0.31 0.1 0.36 0.2 ;
    END
  END ZN
END AOI33D1
MACRO AOI33D2
  CLASS CORE ;
  ORIGIN 0.0 0.0 ;
  SIZE 0.9 BY 0.3 ;
  SYMMETRY X Y ;
  PIN A1
    DIRECTION INPUT ;
    USE SIGNAL ;
    PORT
      LAYER M1 ;
      RECT 0.05 0.1 0.10 0.2 ;
    END
  END A1
  PIN A2
    DIRECTION INPUT ;
    USE SIGNAL ;
    PORT
      LAYER M1 ;
      RECT 0.09 0.1 0.14 0.2 ;
    END
  END A2
  PIN A3
    DIRECTION INPUT ;
    USE SIGNAL ;
    PORT
      LAYER M1 ;
      RECT 0.14 0.1 0.19 0.2 ;
    END
  END A3
  PIN B1
    DIRECTION INPUT ;
    USE SIGNAL ;
    PORT
      LAYER M1 ;
      RECT 0.18 0.1 0.23 0.2 ;
    END
  END B1
  PIN B2
    DIRECTION INPUT ;
    USE SIGNAL ;
    PORT
      LAYER M1 ;
      RECT 0.22 0.1 0.27 0.2 ;
    END
  END B2
  PIN B3
    DIRECTION INPUT ;
    USE SIGNAL ;
    PORT
      LAYER M1 ;
      RECT 0.26 0.1 0.31 0.2 ;
    END
  END B3
  PIN ZN
    DIRECTION OUTPUT ;
    USE SIGNAL ;
    PORT
      LAYER M1 ;
      RECT 0.31 0.1 0.36 0.2 ;
    END
  END ZN
END AOI33D2
MACRO AOI33D4
  CLASS CORE ;
  ORIGIN 0.0 0.0 ;
  SIZE 0.9 BY 0.3 ;
  SYMMETRY X Y ;
  PIN A1
    DIRECTION INPUT ;
    USE SIGNAL ;
    PORT
      LAYER M1 ;
      RECT 0.05 0.1 0.10 0.2 ;
    END
  END A1
  PIN A2
    DIRECTION INPUT ;
    USE SIGNAL ;
    PORT
      LAYER M1 ;
      RECT 0.09 0.1 0.14 0.2 ;
    END
  END A2
  PIN A3
    DIRECTION INPUT ;
    USE SIGNAL ;
    PORT
      LAYER M1 ;
      RECT 0.14 0.1 0.19 0.2 ;
    END
  END A3
  PIN B1
    DIRECTION INPUT ;
    USE SIGNAL ;
    PORT
      LAYER M1 ;
      RECT 0.18 0.1 0.23 0.2 ;
    END
  END B1
  PIN B2
    DIRECTION INPUT ;
    USE SIGNAL ;
    PORT
      LAYER M1 ;
      RECT 0.22 0.1 0.27 0.2 ;
    END
  END B2
  PIN B3
    DIRECTION INPUT ;
    USE SIGNAL ;
    PORT
      LAYER M1 ;
      RECT 0.26 0.1 0.31 0.2 ;
    END
  END B3
  PIN ZN
    DIRECTION OUTPUT ;
    USE SIGNAL ;
    PORT
      LAYER M1 ;
      RECT 0.31 0.1 0.36 0.2 ;
    END
  END ZN
END AOI33D4
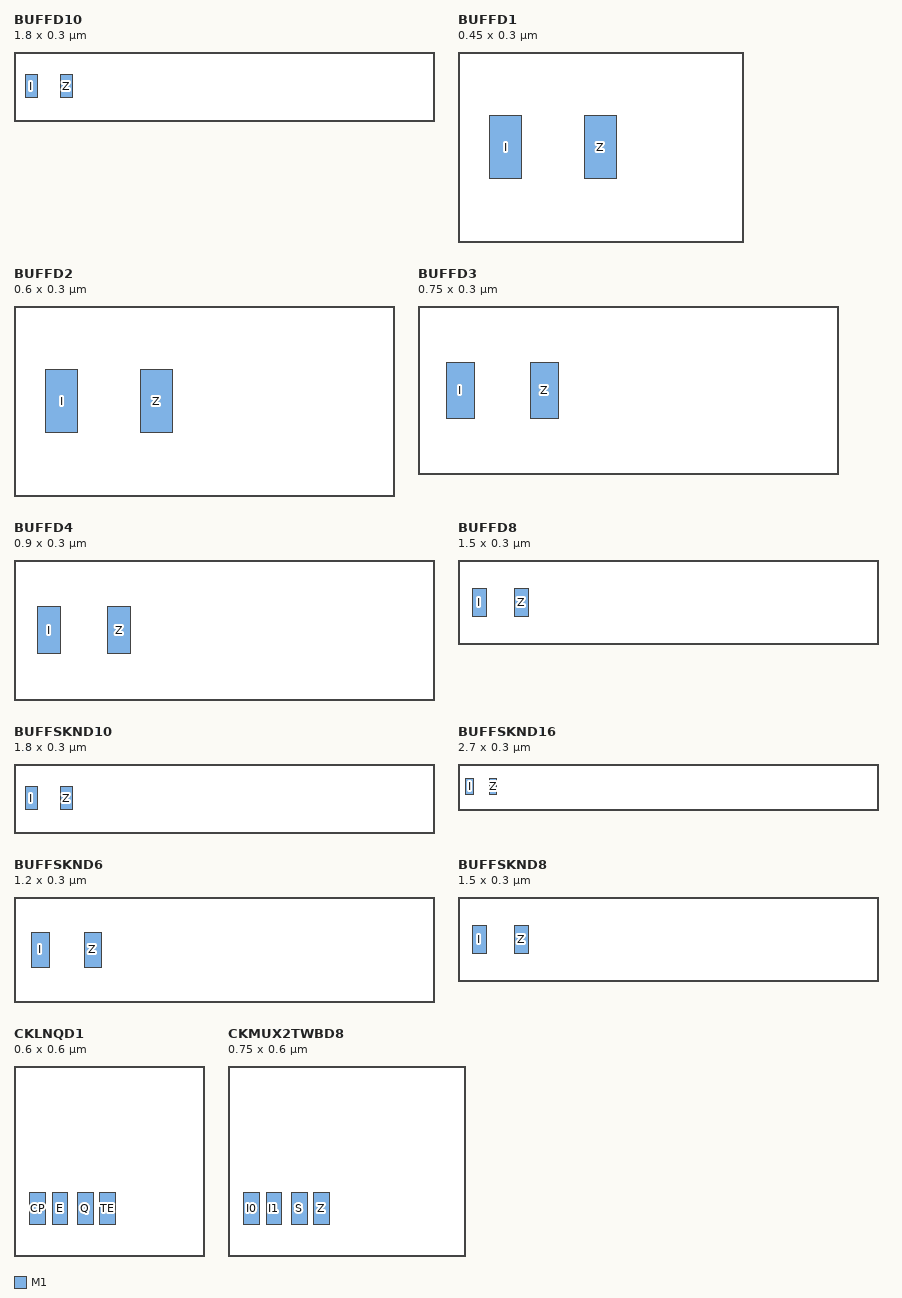
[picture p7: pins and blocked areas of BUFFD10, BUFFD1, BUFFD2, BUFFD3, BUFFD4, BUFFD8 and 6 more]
MACRO BUFFD10
  CLASS CORE ;
  ORIGIN 0.0 0.0 ;
  SIZE 1.8 BY 0.3 ;
  SYMMETRY X Y ;
  PIN I
    DIRECTION INPUT ;
    USE SIGNAL ;
    PORT
      LAYER M1 ;
      RECT 0.05 0.1 0.10 0.2 ;
    END
  END I
  PIN Z
    DIRECTION OUTPUT ;
    USE SIGNAL ;
    PORT
      LAYER M1 ;
      RECT 0.20 0.1 0.25 0.2 ;
    END
  END Z
END BUFFD10
MACRO BUFFD1
  CLASS CORE ;
  ORIGIN 0.0 0.0 ;
  SIZE 0.44999999999999996 BY 0.3 ;
  SYMMETRY X Y ;
  PIN I
    DIRECTION INPUT ;
    USE SIGNAL ;
    PORT
      LAYER M1 ;
      RECT 0.05 0.1 0.10 0.2 ;
    END
  END I
  PIN Z
    DIRECTION OUTPUT ;
    USE SIGNAL ;
    PORT
      LAYER M1 ;
      RECT 0.20 0.1 0.25 0.2 ;
    END
  END Z
END BUFFD1
MACRO BUFFD2
  CLASS CORE ;
  ORIGIN 0.0 0.0 ;
  SIZE 0.6 BY 0.3 ;
  SYMMETRY X Y ;
  PIN I
    DIRECTION INPUT ;
    USE SIGNAL ;
    PORT
      LAYER M1 ;
      RECT 0.05 0.1 0.10 0.2 ;
    END
  END I
  PIN Z
    DIRECTION OUTPUT ;
    USE SIGNAL ;
    PORT
      LAYER M1 ;
      RECT 0.20 0.1 0.25 0.2 ;
    END
  END Z
END BUFFD2
MACRO BUFFD3
  CLASS CORE ;
  ORIGIN 0.0 0.0 ;
  SIZE 0.75 BY 0.3 ;
  SYMMETRY X Y ;
  PIN I
    DIRECTION INPUT ;
    USE SIGNAL ;
    PORT
      LAYER M1 ;
      RECT 0.05 0.1 0.10 0.2 ;
    END
  END I
  PIN Z
    DIRECTION OUTPUT ;
    USE SIGNAL ;
    PORT
      LAYER M1 ;
      RECT 0.20 0.1 0.25 0.2 ;
    END
  END Z
END BUFFD3
MACRO BUFFD4
  CLASS CORE ;
  ORIGIN 0.0 0.0 ;
  SIZE 0.8999999999999999 BY 0.3 ;
  SYMMETRY X Y ;
  PIN I
    DIRECTION INPUT ;
    USE SIGNAL ;
    PORT
      LAYER M1 ;
      RECT 0.05 0.1 0.10 0.2 ;
    END
  END I
  PIN Z
    DIRECTION OUTPUT ;
    USE SIGNAL ;
    PORT
      LAYER M1 ;
      RECT 0.20 0.1 0.25 0.2 ;
    END
  END Z
END BUFFD4
MACRO BUFFD8
  CLASS CORE ;
  ORIGIN 0.0 0.0 ;
  SIZE 1.5 BY 0.3 ;
  SYMMETRY X Y ;
  PIN I
    DIRECTION INPUT ;
    USE SIGNAL ;
    PORT
      LAYER M1 ;
      RECT 0.05 0.1 0.10 0.2 ;
    END
  END I
  PIN Z
    DIRECTION OUTPUT ;
    USE SIGNAL ;
    PORT
      LAYER M1 ;
      RECT 0.20 0.1 0.25 0.2 ;
    END
  END Z
END BUFFD8
MACRO BUFFSKND10
  CLASS CORE ;
  ORIGIN 0.0 0.0 ;
  SIZE 1.8 BY 0.3 ;
  SYMMETRY X Y ;
  PIN I
    DIRECTION INPUT ;
    USE SIGNAL ;
    PORT
      LAYER M1 ;
      RECT 0.05 0.1 0.10 0.2 ;
    END
  END I
  PIN Z
    DIRECTION OUTPUT ;
    USE SIGNAL ;
    PORT
      LAYER M1 ;
      RECT 0.20 0.1 0.25 0.2 ;
    END
  END Z
END BUFFSKND10
MACRO BUFFSKND16
  CLASS CORE ;
  ORIGIN 0.0 0.0 ;
  SIZE 2.6999999999999997 BY 0.3 ;
  SYMMETRY X Y ;
  PIN I
    DIRECTION INPUT ;
    USE SIGNAL ;
    PORT
      LAYER M1 ;
      RECT 0.05 0.1 0.10 0.2 ;
    END
  END I
  PIN Z
    DIRECTION OUTPUT ;
    USE SIGNAL ;
    PORT
      LAYER M1 ;
      RECT 0.20 0.1 0.25 0.2 ;
    END
  END Z
END BUFFSKND16
MACRO BUFFSKND6
  CLASS CORE ;
  ORIGIN 0.0 0.0 ;
  SIZE 1.2 BY 0.3 ;
  SYMMETRY X Y ;
  PIN I
    DIRECTION INPUT ;
    USE SIGNAL ;
    PORT
      LAYER M1 ;
      RECT 0.05 0.1 0.10 0.2 ;
    END
  END I
  PIN Z
    DIRECTION OUTPUT ;
    USE SIGNAL ;
    PORT
      LAYER M1 ;
      RECT 0.20 0.1 0.25 0.2 ;
    END
  END Z
END BUFFSKND6
MACRO BUFFSKND8
  CLASS CORE ;
  ORIGIN 0.0 0.0 ;
  SIZE 1.5 BY 0.3 ;
  SYMMETRY X Y ;
  PIN I
    DIRECTION INPUT ;
    USE SIGNAL ;
    PORT
      LAYER M1 ;
      RECT 0.05 0.1 0.10 0.2 ;
    END
  END I
  PIN Z
    DIRECTION OUTPUT ;
    USE SIGNAL ;
    PORT
      LAYER M1 ;
      RECT 0.20 0.1 0.25 0.2 ;
    END
  END Z
END BUFFSKND8
MACRO CKLNQD1
  CLASS CORE ;
  ORIGIN 0.0 0.0 ;
  SIZE 0.6 BY 0.6 ;
  SYMMETRY X Y ;
  PIN CP
    DIRECTION INPUT ;
    USE SIGNAL ;
    PORT
      LAYER M1 ;
      RECT 0.05 0.1 0.10 0.2 ;
    END
  END CP
  PIN E
    DIRECTION INPUT ;
    USE SIGNAL ;
    PORT
      LAYER M1 ;
      RECT 0.12 0.1 0.17 0.2 ;
    END
  END E
  PIN Q
    DIRECTION OUTPUT ;
    USE SIGNAL ;
    PORT
      LAYER M1 ;
      RECT 0.20 0.1 0.25 0.2 ;
    END
  END Q
  PIN TE
    DIRECTION INPUT ;
    USE SIGNAL ;
    PORT
      LAYER M1 ;
      RECT 0.27 0.1 0.32 0.2 ;
    END
  END TE
END CKLNQD1
MACRO CKMUX2TWBD8
  CLASS CORE ;
  ORIGIN 0.0 0.0 ;
  SIZE 0.75 BY 0.6 ;
  SYMMETRY X Y ;
  PIN I0
    DIRECTION INPUT ;
    USE SIGNAL ;
    PORT
      LAYER M1 ;
      RECT 0.05 0.1 0.10 0.2 ;
    END
  END I0
  PIN I1
    DIRECTION INPUT ;
    USE SIGNAL ;
    PORT
      LAYER M1 ;
      RECT 0.12 0.1 0.17 0.2 ;
    END
  END I1
  PIN S
    DIRECTION OUTPUT ;
    USE SIGNAL ;
    PORT
      LAYER M1 ;
      RECT 0.20 0.1 0.25 0.2 ;
    END
  END S
  PIN Z
    DIRECTION OUTPUT ;
    USE SIGNAL ;
    PORT
      LAYER M1 ;
      RECT 0.27 0.1 0.32 0.2 ;
    END
  END Z
END CKMUX2TWBD8
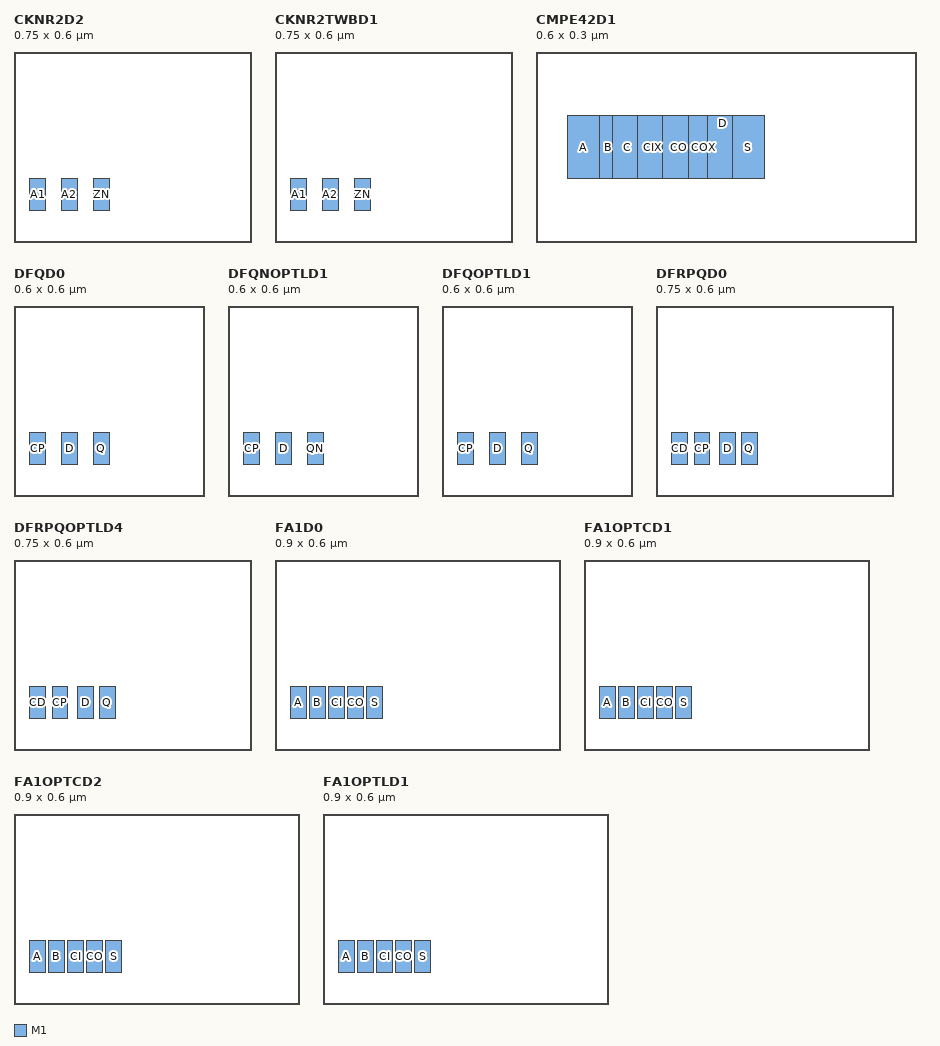
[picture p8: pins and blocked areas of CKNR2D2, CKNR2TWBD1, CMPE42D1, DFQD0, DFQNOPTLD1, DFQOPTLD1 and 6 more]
MACRO CKNR2D2
  CLASS CORE ;
  ORIGIN 0.0 0.0 ;
  SIZE 0.75 BY 0.6 ;
  SYMMETRY X Y ;
  PIN A1
    DIRECTION INPUT ;
    USE SIGNAL ;
    PORT
      LAYER M1 ;
      RECT 0.05 0.1 0.10 0.2 ;
    END
  END A1
  PIN A2
    DIRECTION INPUT ;
    USE SIGNAL ;
    PORT
      LAYER M1 ;
      RECT 0.15 0.1 0.20 0.2 ;
    END
  END A2
  PIN ZN
    DIRECTION OUTPUT ;
    USE SIGNAL ;
    PORT
      LAYER M1 ;
      RECT 0.25 0.1 0.30 0.2 ;
    END
  END ZN
END CKNR2D2
MACRO CKNR2TWBD1
  CLASS CORE ;
  ORIGIN 0.0 0.0 ;
  SIZE 0.75 BY 0.6 ;
  SYMMETRY X Y ;
  PIN A1
    DIRECTION INPUT ;
    USE SIGNAL ;
    PORT
      LAYER M1 ;
      RECT 0.05 0.1 0.10 0.2 ;
    END
  END A1
  PIN A2
    DIRECTION INPUT ;
    USE SIGNAL ;
    PORT
      LAYER M1 ;
      RECT 0.15 0.1 0.20 0.2 ;
    END
  END A2
  PIN ZN
    DIRECTION OUTPUT ;
    USE SIGNAL ;
    PORT
      LAYER M1 ;
      RECT 0.25 0.1 0.30 0.2 ;
    END
  END ZN
END CKNR2TWBD1
MACRO CMPE42D1
  CLASS CORE ;
  ORIGIN 0.0 0.0 ;
  SIZE 0.6 BY 0.3 ;
  SYMMETRY X Y ;
  PIN A
    DIRECTION INPUT ;
    USE SIGNAL ;
    PORT
      LAYER M1 ;
      RECT 0.05 0.1 0.10 0.2 ;
    END
  END A
  PIN B
    DIRECTION INPUT ;
    USE SIGNAL ;
    PORT
      LAYER M1 ;
      RECT 0.09 0.1 0.14 0.2 ;
    END
  END B
  PIN C
    DIRECTION INPUT ;
    USE SIGNAL ;
    PORT
      LAYER M1 ;
      RECT 0.12 0.1 0.17 0.2 ;
    END
  END C
  PIN CIX
    DIRECTION INPUT ;
    USE SIGNAL ;
    PORT
      LAYER M1 ;
      RECT 0.16 0.1 0.21 0.2 ;
    END
  END CIX
  PIN CO
    DIRECTION OUTPUT ;
    USE SIGNAL ;
    PORT
      LAYER M1 ;
      RECT 0.20 0.1 0.25 0.2 ;
    END
  END CO
  PIN COX
    DIRECTION INPUT ;
    USE SIGNAL ;
    PORT
      LAYER M1 ;
      RECT 0.24 0.1 0.29 0.2 ;
    END
  END COX
  PIN D
    DIRECTION INPUT ;
    USE SIGNAL ;
    PORT
      LAYER M1 ;
      RECT 0.27 0.1 0.32 0.2 ;
    END
  END D
  PIN S
    DIRECTION OUTPUT ;
    USE SIGNAL ;
    PORT
      LAYER M1 ;
      RECT 0.31 0.1 0.36 0.2 ;
    END
  END S
END CMPE42D1
MACRO DFQD0
  CLASS CORE ;
  ORIGIN 0.0 0.0 ;
  SIZE 0.6 BY 0.6 ;
  SYMMETRY X Y ;
  PIN CP
    DIRECTION INPUT ;
    USE SIGNAL ;
    PORT
      LAYER M1 ;
      RECT 0.05 0.1 0.10 0.2 ;
    END
  END CP
  PIN D
    DIRECTION INPUT ;
    USE SIGNAL ;
    PORT
      LAYER M1 ;
      RECT 0.15 0.1 0.20 0.2 ;
    END
  END D
  PIN Q
    DIRECTION OUTPUT ;
    USE SIGNAL ;
    PORT
      LAYER M1 ;
      RECT 0.25 0.1 0.30 0.2 ;
    END
  END Q
END DFQD0
MACRO DFQNOPTLD1
  CLASS CORE ;
  ORIGIN 0.0 0.0 ;
  SIZE 0.6 BY 0.6 ;
  SYMMETRY X Y ;
  PIN CP
    DIRECTION INPUT ;
    USE SIGNAL ;
    PORT
      LAYER M1 ;
      RECT 0.05 0.1 0.10 0.2 ;
    END
  END CP
  PIN D
    DIRECTION INPUT ;
    USE SIGNAL ;
    PORT
      LAYER M1 ;
      RECT 0.15 0.1 0.20 0.2 ;
    END
  END D
  PIN QN
    DIRECTION OUTPUT ;
    USE SIGNAL ;
    PORT
      LAYER M1 ;
      RECT 0.25 0.1 0.30 0.2 ;
    END
  END QN
END DFQNOPTLD1
MACRO DFQOPTLD1
  CLASS CORE ;
  ORIGIN 0.0 0.0 ;
  SIZE 0.6 BY 0.6 ;
  SYMMETRY X Y ;
  PIN CP
    DIRECTION INPUT ;
    USE SIGNAL ;
    PORT
      LAYER M1 ;
      RECT 0.05 0.1 0.10 0.2 ;
    END
  END CP
  PIN D
    DIRECTION INPUT ;
    USE SIGNAL ;
    PORT
      LAYER M1 ;
      RECT 0.15 0.1 0.20 0.2 ;
    END
  END D
  PIN Q
    DIRECTION OUTPUT ;
    USE SIGNAL ;
    PORT
      LAYER M1 ;
      RECT 0.25 0.1 0.30 0.2 ;
    END
  END Q
END DFQOPTLD1
MACRO DFRPQD0
  CLASS CORE ;
  ORIGIN 0.0 0.0 ;
  SIZE 0.75 BY 0.6 ;
  SYMMETRY X Y ;
  PIN CD
    DIRECTION INPUT ;
    USE SIGNAL ;
    PORT
      LAYER M1 ;
      RECT 0.05 0.1 0.10 0.2 ;
    END
  END CD
  PIN CP
    DIRECTION INPUT ;
    USE SIGNAL ;
    PORT
      LAYER M1 ;
      RECT 0.12 0.1 0.17 0.2 ;
    END
  END CP
  PIN D
    DIRECTION INPUT ;
    USE SIGNAL ;
    PORT
      LAYER M1 ;
      RECT 0.20 0.1 0.25 0.2 ;
    END
  END D
  PIN Q
    DIRECTION OUTPUT ;
    USE SIGNAL ;
    PORT
      LAYER M1 ;
      RECT 0.27 0.1 0.32 0.2 ;
    END
  END Q
END DFRPQD0
MACRO DFRPQOPTLD4
  CLASS CORE ;
  ORIGIN 0.0 0.0 ;
  SIZE 0.75 BY 0.6 ;
  SYMMETRY X Y ;
  PIN CD
    DIRECTION INPUT ;
    USE SIGNAL ;
    PORT
      LAYER M1 ;
      RECT 0.05 0.1 0.10 0.2 ;
    END
  END CD
  PIN CP
    DIRECTION INPUT ;
    USE SIGNAL ;
    PORT
      LAYER M1 ;
      RECT 0.12 0.1 0.17 0.2 ;
    END
  END CP
  PIN D
    DIRECTION INPUT ;
    USE SIGNAL ;
    PORT
      LAYER M1 ;
      RECT 0.20 0.1 0.25 0.2 ;
    END
  END D
  PIN Q
    DIRECTION OUTPUT ;
    USE SIGNAL ;
    PORT
      LAYER M1 ;
      RECT 0.27 0.1 0.32 0.2 ;
    END
  END Q
END DFRPQOPTLD4
MACRO FA1D0
  CLASS CORE ;
  ORIGIN 0.0 0.0 ;
  SIZE 0.9 BY 0.6 ;
  SYMMETRY X Y ;
  PIN A
    DIRECTION INPUT ;
    USE SIGNAL ;
    PORT
      LAYER M1 ;
      RECT 0.05 0.1 0.10 0.2 ;
    END
  END A
  PIN B
    DIRECTION INPUT ;
    USE SIGNAL ;
    PORT
      LAYER M1 ;
      RECT 0.11 0.1 0.16 0.2 ;
    END
  END B
  PIN CI
    DIRECTION INPUT ;
    USE SIGNAL ;
    PORT
      LAYER M1 ;
      RECT 0.17 0.1 0.22 0.2 ;
    END
  END CI
  PIN CO
    DIRECTION OUTPUT ;
    USE SIGNAL ;
    PORT
      LAYER M1 ;
      RECT 0.23 0.1 0.28 0.2 ;
    END
  END CO
  PIN S
    DIRECTION OUTPUT ;
    USE SIGNAL ;
    PORT
      LAYER M1 ;
      RECT 0.29 0.1 0.34 0.2 ;
    END
  END S
END FA1D0
MACRO FA1OPTCD1
  CLASS CORE ;
  ORIGIN 0.0 0.0 ;
  SIZE 0.9 BY 0.6 ;
  SYMMETRY X Y ;
  PIN A
    DIRECTION INPUT ;
    USE SIGNAL ;
    PORT
      LAYER M1 ;
      RECT 0.05 0.1 0.10 0.2 ;
    END
  END A
  PIN B
    DIRECTION INPUT ;
    USE SIGNAL ;
    PORT
      LAYER M1 ;
      RECT 0.11 0.1 0.16 0.2 ;
    END
  END B
  PIN CI
    DIRECTION INPUT ;
    USE SIGNAL ;
    PORT
      LAYER M1 ;
      RECT 0.17 0.1 0.22 0.2 ;
    END
  END CI
  PIN CO
    DIRECTION OUTPUT ;
    USE SIGNAL ;
    PORT
      LAYER M1 ;
      RECT 0.23 0.1 0.28 0.2 ;
    END
  END CO
  PIN S
    DIRECTION OUTPUT ;
    USE SIGNAL ;
    PORT
      LAYER M1 ;
      RECT 0.29 0.1 0.34 0.2 ;
    END
  END S
END FA1OPTCD1
MACRO FA1OPTCD2
  CLASS CORE ;
  ORIGIN 0.0 0.0 ;
  SIZE 0.9 BY 0.6 ;
  SYMMETRY X Y ;
  PIN A
    DIRECTION INPUT ;
    USE SIGNAL ;
    PORT
      LAYER M1 ;
      RECT 0.05 0.1 0.10 0.2 ;
    END
  END A
  PIN B
    DIRECTION INPUT ;
    USE SIGNAL ;
    PORT
      LAYER M1 ;
      RECT 0.11 0.1 0.16 0.2 ;
    END
  END B
  PIN CI
    DIRECTION INPUT ;
    USE SIGNAL ;
    PORT
      LAYER M1 ;
      RECT 0.17 0.1 0.22 0.2 ;
    END
  END CI
  PIN CO
    DIRECTION OUTPUT ;
    USE SIGNAL ;
    PORT
      LAYER M1 ;
      RECT 0.23 0.1 0.28 0.2 ;
    END
  END CO
  PIN S
    DIRECTION OUTPUT ;
    USE SIGNAL ;
    PORT
      LAYER M1 ;
      RECT 0.29 0.1 0.34 0.2 ;
    END
  END S
END FA1OPTCD2
MACRO FA1OPTLD1
  CLASS CORE ;
  ORIGIN 0.0 0.0 ;
  SIZE 0.9 BY 0.6 ;
  SYMMETRY X Y ;
  PIN A
    DIRECTION INPUT ;
    USE SIGNAL ;
    PORT
      LAYER M1 ;
      RECT 0.05 0.1 0.10 0.2 ;
    END
  END A
  PIN B
    DIRECTION INPUT ;
    USE SIGNAL ;
    PORT
      LAYER M1 ;
      RECT 0.11 0.1 0.16 0.2 ;
    END
  END B
  PIN CI
    DIRECTION INPUT ;
    USE SIGNAL ;
    PORT
      LAYER M1 ;
      RECT 0.17 0.1 0.22 0.2 ;
    END
  END CI
  PIN CO
    DIRECTION OUTPUT ;
    USE SIGNAL ;
    PORT
      LAYER M1 ;
      RECT 0.23 0.1 0.28 0.2 ;
    END
  END CO
  PIN S
    DIRECTION OUTPUT ;
    USE SIGNAL ;
    PORT
      LAYER M1 ;
      RECT 0.29 0.1 0.34 0.2 ;
    END
  END S
END FA1OPTLD1
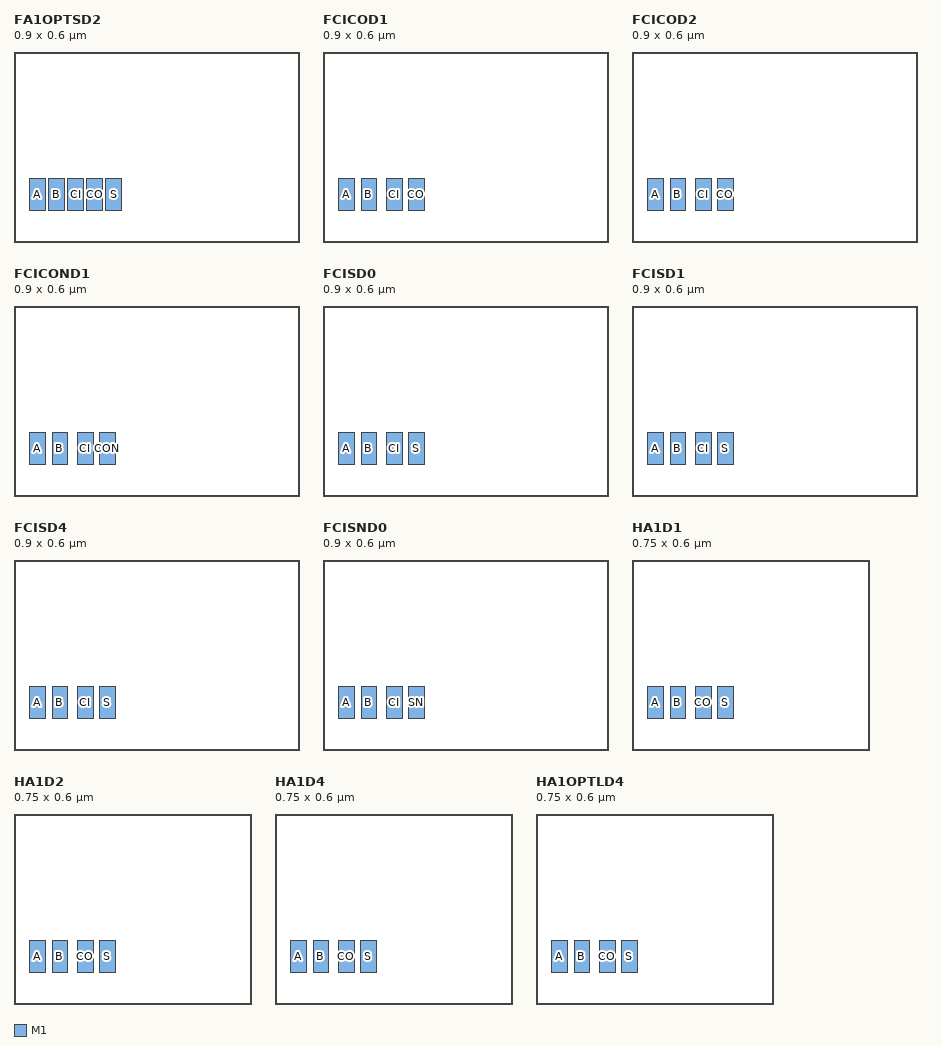
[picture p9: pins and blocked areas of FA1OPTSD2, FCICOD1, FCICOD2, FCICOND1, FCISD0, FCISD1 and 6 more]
MACRO FA1OPTSD2
  CLASS CORE ;
  ORIGIN 0.0 0.0 ;
  SIZE 0.9 BY 0.6 ;
  SYMMETRY X Y ;
  PIN A
    DIRECTION INPUT ;
    USE SIGNAL ;
    PORT
      LAYER M1 ;
      RECT 0.05 0.1 0.10 0.2 ;
    END
  END A
  PIN B
    DIRECTION INPUT ;
    USE SIGNAL ;
    PORT
      LAYER M1 ;
      RECT 0.11 0.1 0.16 0.2 ;
    END
  END B
  PIN CI
    DIRECTION INPUT ;
    USE SIGNAL ;
    PORT
      LAYER M1 ;
      RECT 0.17 0.1 0.22 0.2 ;
    END
  END CI
  PIN CO
    DIRECTION OUTPUT ;
    USE SIGNAL ;
    PORT
      LAYER M1 ;
      RECT 0.23 0.1 0.28 0.2 ;
    END
  END CO
  PIN S
    DIRECTION OUTPUT ;
    USE SIGNAL ;
    PORT
      LAYER M1 ;
      RECT 0.29 0.1 0.34 0.2 ;
    END
  END S
END FA1OPTSD2
MACRO FCICOD1
  CLASS CORE ;
  ORIGIN 0.0 0.0 ;
  SIZE 0.9 BY 0.6 ;
  SYMMETRY X Y ;
  PIN A
    DIRECTION INPUT ;
    USE SIGNAL ;
    PORT
      LAYER M1 ;
      RECT 0.05 0.1 0.10 0.2 ;
    END
  END A
  PIN B
    DIRECTION INPUT ;
    USE SIGNAL ;
    PORT
      LAYER M1 ;
      RECT 0.12 0.1 0.17 0.2 ;
    END
  END B
  PIN CI
    DIRECTION INPUT ;
    USE SIGNAL ;
    PORT
      LAYER M1 ;
      RECT 0.20 0.1 0.25 0.2 ;
    END
  END CI
  PIN CO
    DIRECTION OUTPUT ;
    USE SIGNAL ;
    PORT
      LAYER M1 ;
      RECT 0.27 0.1 0.32 0.2 ;
    END
  END CO
END FCICOD1
MACRO FCICOD2
  CLASS CORE ;
  ORIGIN 0.0 0.0 ;
  SIZE 0.9 BY 0.6 ;
  SYMMETRY X Y ;
  PIN A
    DIRECTION INPUT ;
    USE SIGNAL ;
    PORT
      LAYER M1 ;
      RECT 0.05 0.1 0.10 0.2 ;
    END
  END A
  PIN B
    DIRECTION INPUT ;
    USE SIGNAL ;
    PORT
      LAYER M1 ;
      RECT 0.12 0.1 0.17 0.2 ;
    END
  END B
  PIN CI
    DIRECTION INPUT ;
    USE SIGNAL ;
    PORT
      LAYER M1 ;
      RECT 0.20 0.1 0.25 0.2 ;
    END
  END CI
  PIN CO
    DIRECTION OUTPUT ;
    USE SIGNAL ;
    PORT
      LAYER M1 ;
      RECT 0.27 0.1 0.32 0.2 ;
    END
  END CO
END FCICOD2
MACRO FCICOND1
  CLASS CORE ;
  ORIGIN 0.0 0.0 ;
  SIZE 0.9 BY 0.6 ;
  SYMMETRY X Y ;
  PIN A
    DIRECTION INPUT ;
    USE SIGNAL ;
    PORT
      LAYER M1 ;
      RECT 0.05 0.1 0.10 0.2 ;
    END
  END A
  PIN B
    DIRECTION INPUT ;
    USE SIGNAL ;
    PORT
      LAYER M1 ;
      RECT 0.12 0.1 0.17 0.2 ;
    END
  END B
  PIN CI
    DIRECTION OUTPUT ;
    USE SIGNAL ;
    PORT
      LAYER M1 ;
      RECT 0.20 0.1 0.25 0.2 ;
    END
  END CI
  PIN CON
    DIRECTION INPUT ;
    USE SIGNAL ;
    PORT
      LAYER M1 ;
      RECT 0.27 0.1 0.32 0.2 ;
    END
  END CON
END FCICOND1
MACRO FCISD0
  CLASS CORE ;
  ORIGIN 0.0 0.0 ;
  SIZE 0.9 BY 0.6 ;
  SYMMETRY X Y ;
  PIN A
    DIRECTION INPUT ;
    USE SIGNAL ;
    PORT
      LAYER M1 ;
      RECT 0.05 0.1 0.10 0.2 ;
    END
  END A
  PIN B
    DIRECTION INPUT ;
    USE SIGNAL ;
    PORT
      LAYER M1 ;
      RECT 0.12 0.1 0.17 0.2 ;
    END
  END B
  PIN CI
    DIRECTION INPUT ;
    USE SIGNAL ;
    PORT
      LAYER M1 ;
      RECT 0.20 0.1 0.25 0.2 ;
    END
  END CI
  PIN S
    DIRECTION OUTPUT ;
    USE SIGNAL ;
    PORT
      LAYER M1 ;
      RECT 0.27 0.1 0.32 0.2 ;
    END
  END S
END FCISD0
MACRO FCISD1
  CLASS CORE ;
  ORIGIN 0.0 0.0 ;
  SIZE 0.9 BY 0.6 ;
  SYMMETRY X Y ;
  PIN A
    DIRECTION INPUT ;
    USE SIGNAL ;
    PORT
      LAYER M1 ;
      RECT 0.05 0.1 0.10 0.2 ;
    END
  END A
  PIN B
    DIRECTION INPUT ;
    USE SIGNAL ;
    PORT
      LAYER M1 ;
      RECT 0.12 0.1 0.17 0.2 ;
    END
  END B
  PIN CI
    DIRECTION INPUT ;
    USE SIGNAL ;
    PORT
      LAYER M1 ;
      RECT 0.20 0.1 0.25 0.2 ;
    END
  END CI
  PIN S
    DIRECTION OUTPUT ;
    USE SIGNAL ;
    PORT
      LAYER M1 ;
      RECT 0.27 0.1 0.32 0.2 ;
    END
  END S
END FCISD1
MACRO FCISD4
  CLASS CORE ;
  ORIGIN 0.0 0.0 ;
  SIZE 0.9 BY 0.6 ;
  SYMMETRY X Y ;
  PIN A
    DIRECTION INPUT ;
    USE SIGNAL ;
    PORT
      LAYER M1 ;
      RECT 0.05 0.1 0.10 0.2 ;
    END
  END A
  PIN B
    DIRECTION INPUT ;
    USE SIGNAL ;
    PORT
      LAYER M1 ;
      RECT 0.12 0.1 0.17 0.2 ;
    END
  END B
  PIN CI
    DIRECTION INPUT ;
    USE SIGNAL ;
    PORT
      LAYER M1 ;
      RECT 0.20 0.1 0.25 0.2 ;
    END
  END CI
  PIN S
    DIRECTION OUTPUT ;
    USE SIGNAL ;
    PORT
      LAYER M1 ;
      RECT 0.27 0.1 0.32 0.2 ;
    END
  END S
END FCISD4
MACRO FCISND0
  CLASS CORE ;
  ORIGIN 0.0 0.0 ;
  SIZE 0.9 BY 0.6 ;
  SYMMETRY X Y ;
  PIN A
    DIRECTION OUTPUT ;
    USE SIGNAL ;
    PORT
      LAYER M1 ;
      RECT 0.05 0.1 0.10 0.2 ;
    END
  END A
  PIN B
    DIRECTION INPUT ;
    USE SIGNAL ;
    PORT
      LAYER M1 ;
      RECT 0.12 0.1 0.17 0.2 ;
    END
  END B
  PIN CI
    DIRECTION INPUT ;
    USE SIGNAL ;
    PORT
      LAYER M1 ;
      RECT 0.20 0.1 0.25 0.2 ;
    END
  END CI
  PIN SN
    DIRECTION INPUT ;
    USE SIGNAL ;
    PORT
      LAYER M1 ;
      RECT 0.27 0.1 0.32 0.2 ;
    END
  END SN
END FCISND0
MACRO HA1D1
  CLASS CORE ;
  ORIGIN 0.0 0.0 ;
  SIZE 0.75 BY 0.6 ;
  SYMMETRY X Y ;
  PIN A
    DIRECTION INPUT ;
    USE SIGNAL ;
    PORT
      LAYER M1 ;
      RECT 0.05 0.1 0.10 0.2 ;
    END
  END A
  PIN B
    DIRECTION INPUT ;
    USE SIGNAL ;
    PORT
      LAYER M1 ;
      RECT 0.12 0.1 0.17 0.2 ;
    END
  END B
  PIN CO
    DIRECTION OUTPUT ;
    USE SIGNAL ;
    PORT
      LAYER M1 ;
      RECT 0.20 0.1 0.25 0.2 ;
    END
  END CO
  PIN S
    DIRECTION OUTPUT ;
    USE SIGNAL ;
    PORT
      LAYER M1 ;
      RECT 0.27 0.1 0.32 0.2 ;
    END
  END S
END HA1D1
MACRO HA1D2
  CLASS CORE ;
  ORIGIN 0.0 0.0 ;
  SIZE 0.75 BY 0.6 ;
  SYMMETRY X Y ;
  PIN A
    DIRECTION INPUT ;
    USE SIGNAL ;
    PORT
      LAYER M1 ;
      RECT 0.05 0.1 0.10 0.2 ;
    END
  END A
  PIN B
    DIRECTION INPUT ;
    USE SIGNAL ;
    PORT
      LAYER M1 ;
      RECT 0.12 0.1 0.17 0.2 ;
    END
  END B
  PIN CO
    DIRECTION OUTPUT ;
    USE SIGNAL ;
    PORT
      LAYER M1 ;
      RECT 0.20 0.1 0.25 0.2 ;
    END
  END CO
  PIN S
    DIRECTION OUTPUT ;
    USE SIGNAL ;
    PORT
      LAYER M1 ;
      RECT 0.27 0.1 0.32 0.2 ;
    END
  END S
END HA1D2
MACRO HA1D4
  CLASS CORE ;
  ORIGIN 0.0 0.0 ;
  SIZE 0.75 BY 0.6 ;
  SYMMETRY X Y ;
  PIN A
    DIRECTION INPUT ;
    USE SIGNAL ;
    PORT
      LAYER M1 ;
      RECT 0.05 0.1 0.10 0.2 ;
    END
  END A
  PIN B
    DIRECTION INPUT ;
    USE SIGNAL ;
    PORT
      LAYER M1 ;
      RECT 0.12 0.1 0.17 0.2 ;
    END
  END B
  PIN CO
    DIRECTION OUTPUT ;
    USE SIGNAL ;
    PORT
      LAYER M1 ;
      RECT 0.20 0.1 0.25 0.2 ;
    END
  END CO
  PIN S
    DIRECTION OUTPUT ;
    USE SIGNAL ;
    PORT
      LAYER M1 ;
      RECT 0.27 0.1 0.32 0.2 ;
    END
  END S
END HA1D4
MACRO HA1OPTLD4
  CLASS CORE ;
  ORIGIN 0.0 0.0 ;
  SIZE 0.75 BY 0.6 ;
  SYMMETRY X Y ;
  PIN A
    DIRECTION INPUT ;
    USE SIGNAL ;
    PORT
      LAYER M1 ;
      RECT 0.05 0.1 0.10 0.2 ;
    END
  END A
  PIN B
    DIRECTION INPUT ;
    USE SIGNAL ;
    PORT
      LAYER M1 ;
      RECT 0.12 0.1 0.17 0.2 ;
    END
  END B
  PIN CO
    DIRECTION OUTPUT ;
    USE SIGNAL ;
    PORT
      LAYER M1 ;
      RECT 0.20 0.1 0.25 0.2 ;
    END
  END CO
  PIN S
    DIRECTION OUTPUT ;
    USE SIGNAL ;
    PORT
      LAYER M1 ;
      RECT 0.27 0.1 0.32 0.2 ;
    END
  END S
END HA1OPTLD4
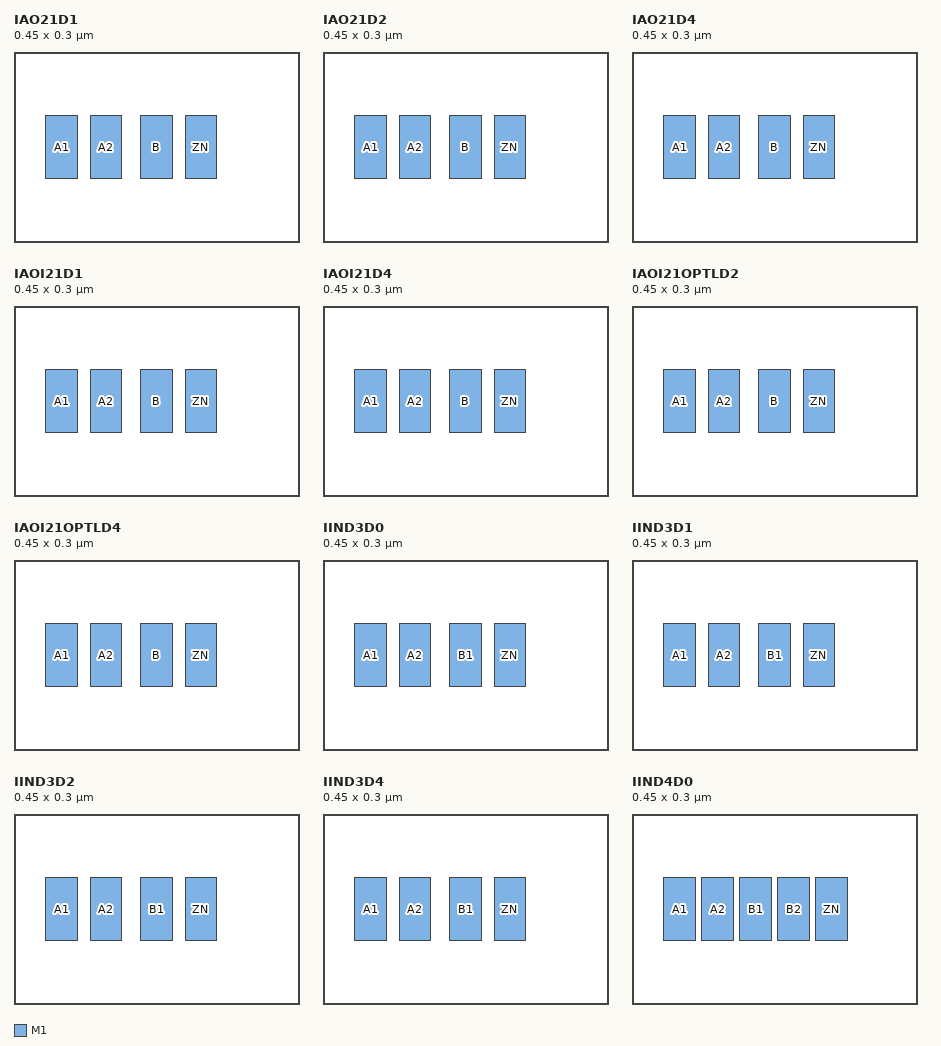
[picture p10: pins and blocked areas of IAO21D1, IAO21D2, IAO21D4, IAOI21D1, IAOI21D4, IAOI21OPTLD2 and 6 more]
MACRO IAO21D1
  CLASS CORE ;
  ORIGIN 0.0 0.0 ;
  SIZE 0.45 BY 0.3 ;
  SYMMETRY X Y ;
  PIN A1
    DIRECTION INPUT ;
    USE SIGNAL ;
    PORT
      LAYER M1 ;
      RECT 0.05 0.1 0.10 0.2 ;
    END
  END A1
  PIN A2
    DIRECTION INPUT ;
    USE SIGNAL ;
    PORT
      LAYER M1 ;
      RECT 0.12 0.1 0.17 0.2 ;
    END
  END A2
  PIN B
    DIRECTION INPUT ;
    USE SIGNAL ;
    PORT
      LAYER M1 ;
      RECT 0.20 0.1 0.25 0.2 ;
    END
  END B
  PIN ZN
    DIRECTION OUTPUT ;
    USE SIGNAL ;
    PORT
      LAYER M1 ;
      RECT 0.27 0.1 0.32 0.2 ;
    END
  END ZN
END IAO21D1
MACRO IAO21D2
  CLASS CORE ;
  ORIGIN 0.0 0.0 ;
  SIZE 0.45 BY 0.3 ;
  SYMMETRY X Y ;
  PIN A1
    DIRECTION INPUT ;
    USE SIGNAL ;
    PORT
      LAYER M1 ;
      RECT 0.05 0.1 0.10 0.2 ;
    END
  END A1
  PIN A2
    DIRECTION INPUT ;
    USE SIGNAL ;
    PORT
      LAYER M1 ;
      RECT 0.12 0.1 0.17 0.2 ;
    END
  END A2
  PIN B
    DIRECTION INPUT ;
    USE SIGNAL ;
    PORT
      LAYER M1 ;
      RECT 0.20 0.1 0.25 0.2 ;
    END
  END B
  PIN ZN
    DIRECTION OUTPUT ;
    USE SIGNAL ;
    PORT
      LAYER M1 ;
      RECT 0.27 0.1 0.32 0.2 ;
    END
  END ZN
END IAO21D2
MACRO IAO21D4
  CLASS CORE ;
  ORIGIN 0.0 0.0 ;
  SIZE 0.45 BY 0.3 ;
  SYMMETRY X Y ;
  PIN A1
    DIRECTION INPUT ;
    USE SIGNAL ;
    PORT
      LAYER M1 ;
      RECT 0.05 0.1 0.10 0.2 ;
    END
  END A1
  PIN A2
    DIRECTION INPUT ;
    USE SIGNAL ;
    PORT
      LAYER M1 ;
      RECT 0.12 0.1 0.17 0.2 ;
    END
  END A2
  PIN B
    DIRECTION INPUT ;
    USE SIGNAL ;
    PORT
      LAYER M1 ;
      RECT 0.20 0.1 0.25 0.2 ;
    END
  END B
  PIN ZN
    DIRECTION OUTPUT ;
    USE SIGNAL ;
    PORT
      LAYER M1 ;
      RECT 0.27 0.1 0.32 0.2 ;
    END
  END ZN
END IAO21D4
MACRO IAOI21D1
  CLASS CORE ;
  ORIGIN 0.0 0.0 ;
  SIZE 0.45 BY 0.3 ;
  SYMMETRY X Y ;
  PIN A1
    DIRECTION INPUT ;
    USE SIGNAL ;
    PORT
      LAYER M1 ;
      RECT 0.05 0.1 0.10 0.2 ;
    END
  END A1
  PIN A2
    DIRECTION INPUT ;
    USE SIGNAL ;
    PORT
      LAYER M1 ;
      RECT 0.12 0.1 0.17 0.2 ;
    END
  END A2
  PIN B
    DIRECTION INPUT ;
    USE SIGNAL ;
    PORT
      LAYER M1 ;
      RECT 0.20 0.1 0.25 0.2 ;
    END
  END B
  PIN ZN
    DIRECTION OUTPUT ;
    USE SIGNAL ;
    PORT
      LAYER M1 ;
      RECT 0.27 0.1 0.32 0.2 ;
    END
  END ZN
END IAOI21D1
MACRO IAOI21D4
  CLASS CORE ;
  ORIGIN 0.0 0.0 ;
  SIZE 0.45 BY 0.3 ;
  SYMMETRY X Y ;
  PIN A1
    DIRECTION INPUT ;
    USE SIGNAL ;
    PORT
      LAYER M1 ;
      RECT 0.05 0.1 0.10 0.2 ;
    END
  END A1
  PIN A2
    DIRECTION INPUT ;
    USE SIGNAL ;
    PORT
      LAYER M1 ;
      RECT 0.12 0.1 0.17 0.2 ;
    END
  END A2
  PIN B
    DIRECTION INPUT ;
    USE SIGNAL ;
    PORT
      LAYER M1 ;
      RECT 0.20 0.1 0.25 0.2 ;
    END
  END B
  PIN ZN
    DIRECTION OUTPUT ;
    USE SIGNAL ;
    PORT
      LAYER M1 ;
      RECT 0.27 0.1 0.32 0.2 ;
    END
  END ZN
END IAOI21D4
MACRO IAOI21OPTLD2
  CLASS CORE ;
  ORIGIN 0.0 0.0 ;
  SIZE 0.45 BY 0.3 ;
  SYMMETRY X Y ;
  PIN A1
    DIRECTION INPUT ;
    USE SIGNAL ;
    PORT
      LAYER M1 ;
      RECT 0.05 0.1 0.10 0.2 ;
    END
  END A1
  PIN A2
    DIRECTION INPUT ;
    USE SIGNAL ;
    PORT
      LAYER M1 ;
      RECT 0.12 0.1 0.17 0.2 ;
    END
  END A2
  PIN B
    DIRECTION INPUT ;
    USE SIGNAL ;
    PORT
      LAYER M1 ;
      RECT 0.20 0.1 0.25 0.2 ;
    END
  END B
  PIN ZN
    DIRECTION OUTPUT ;
    USE SIGNAL ;
    PORT
      LAYER M1 ;
      RECT 0.27 0.1 0.32 0.2 ;
    END
  END ZN
END IAOI21OPTLD2
MACRO IAOI21OPTLD4
  CLASS CORE ;
  ORIGIN 0.0 0.0 ;
  SIZE 0.45 BY 0.3 ;
  SYMMETRY X Y ;
  PIN A1
    DIRECTION INPUT ;
    USE SIGNAL ;
    PORT
      LAYER M1 ;
      RECT 0.05 0.1 0.10 0.2 ;
    END
  END A1
  PIN A2
    DIRECTION INPUT ;
    USE SIGNAL ;
    PORT
      LAYER M1 ;
      RECT 0.12 0.1 0.17 0.2 ;
    END
  END A2
  PIN B
    DIRECTION INPUT ;
    USE SIGNAL ;
    PORT
      LAYER M1 ;
      RECT 0.20 0.1 0.25 0.2 ;
    END
  END B
  PIN ZN
    DIRECTION OUTPUT ;
    USE SIGNAL ;
    PORT
      LAYER M1 ;
      RECT 0.27 0.1 0.32 0.2 ;
    END
  END ZN
END IAOI21OPTLD4
MACRO IIND3D0
  CLASS CORE ;
  ORIGIN 0.0 0.0 ;
  SIZE 0.45 BY 0.3 ;
  SYMMETRY X Y ;
  PIN A1
    DIRECTION INPUT ;
    USE SIGNAL ;
    PORT
      LAYER M1 ;
      RECT 0.05 0.1 0.10 0.2 ;
    END
  END A1
  PIN A2
    DIRECTION INPUT ;
    USE SIGNAL ;
    PORT
      LAYER M1 ;
      RECT 0.12 0.1 0.17 0.2 ;
    END
  END A2
  PIN B1
    DIRECTION INPUT ;
    USE SIGNAL ;
    PORT
      LAYER M1 ;
      RECT 0.20 0.1 0.25 0.2 ;
    END
  END B1
  PIN ZN
    DIRECTION OUTPUT ;
    USE SIGNAL ;
    PORT
      LAYER M1 ;
      RECT 0.27 0.1 0.32 0.2 ;
    END
  END ZN
END IIND3D0
MACRO IIND3D1
  CLASS CORE ;
  ORIGIN 0.0 0.0 ;
  SIZE 0.45 BY 0.3 ;
  SYMMETRY X Y ;
  PIN A1
    DIRECTION INPUT ;
    USE SIGNAL ;
    PORT
      LAYER M1 ;
      RECT 0.05 0.1 0.10 0.2 ;
    END
  END A1
  PIN A2
    DIRECTION INPUT ;
    USE SIGNAL ;
    PORT
      LAYER M1 ;
      RECT 0.12 0.1 0.17 0.2 ;
    END
  END A2
  PIN B1
    DIRECTION INPUT ;
    USE SIGNAL ;
    PORT
      LAYER M1 ;
      RECT 0.20 0.1 0.25 0.2 ;
    END
  END B1
  PIN ZN
    DIRECTION OUTPUT ;
    USE SIGNAL ;
    PORT
      LAYER M1 ;
      RECT 0.27 0.1 0.32 0.2 ;
    END
  END ZN
END IIND3D1
MACRO IIND3D2
  CLASS CORE ;
  ORIGIN 0.0 0.0 ;
  SIZE 0.45 BY 0.3 ;
  SYMMETRY X Y ;
  PIN A1
    DIRECTION INPUT ;
    USE SIGNAL ;
    PORT
      LAYER M1 ;
      RECT 0.05 0.1 0.10 0.2 ;
    END
  END A1
  PIN A2
    DIRECTION INPUT ;
    USE SIGNAL ;
    PORT
      LAYER M1 ;
      RECT 0.12 0.1 0.17 0.2 ;
    END
  END A2
  PIN B1
    DIRECTION INPUT ;
    USE SIGNAL ;
    PORT
      LAYER M1 ;
      RECT 0.20 0.1 0.25 0.2 ;
    END
  END B1
  PIN ZN
    DIRECTION OUTPUT ;
    USE SIGNAL ;
    PORT
      LAYER M1 ;
      RECT 0.27 0.1 0.32 0.2 ;
    END
  END ZN
END IIND3D2
MACRO IIND3D4
  CLASS CORE ;
  ORIGIN 0.0 0.0 ;
  SIZE 0.45 BY 0.3 ;
  SYMMETRY X Y ;
  PIN A1
    DIRECTION INPUT ;
    USE SIGNAL ;
    PORT
      LAYER M1 ;
      RECT 0.05 0.1 0.10 0.2 ;
    END
  END A1
  PIN A2
    DIRECTION INPUT ;
    USE SIGNAL ;
    PORT
      LAYER M1 ;
      RECT 0.12 0.1 0.17 0.2 ;
    END
  END A2
  PIN B1
    DIRECTION INPUT ;
    USE SIGNAL ;
    PORT
      LAYER M1 ;
      RECT 0.20 0.1 0.25 0.2 ;
    END
  END B1
  PIN ZN
    DIRECTION OUTPUT ;
    USE SIGNAL ;
    PORT
      LAYER M1 ;
      RECT 0.27 0.1 0.32 0.2 ;
    END
  END ZN
END IIND3D4
MACRO IIND4D0
  CLASS CORE ;
  ORIGIN 0.0 0.0 ;
  SIZE 0.45 BY 0.3 ;
  SYMMETRY X Y ;
  PIN A1
    DIRECTION INPUT ;
    USE SIGNAL ;
    PORT
      LAYER M1 ;
      RECT 0.05 0.1 0.10 0.2 ;
    END
  END A1
  PIN A2
    DIRECTION INPUT ;
    USE SIGNAL ;
    PORT
      LAYER M1 ;
      RECT 0.11 0.1 0.16 0.2 ;
    END
  END A2
  PIN B1
    DIRECTION INPUT ;
    USE SIGNAL ;
    PORT
      LAYER M1 ;
      RECT 0.17 0.1 0.22 0.2 ;
    END
  END B1
  PIN B2
    DIRECTION INPUT ;
    USE SIGNAL ;
    PORT
      LAYER M1 ;
      RECT 0.23 0.1 0.28 0.2 ;
    END
  END B2
  PIN ZN
    DIRECTION OUTPUT ;
    USE SIGNAL ;
    PORT
      LAYER M1 ;
      RECT 0.29 0.1 0.34 0.2 ;
    END
  END ZN
END IIND4D0
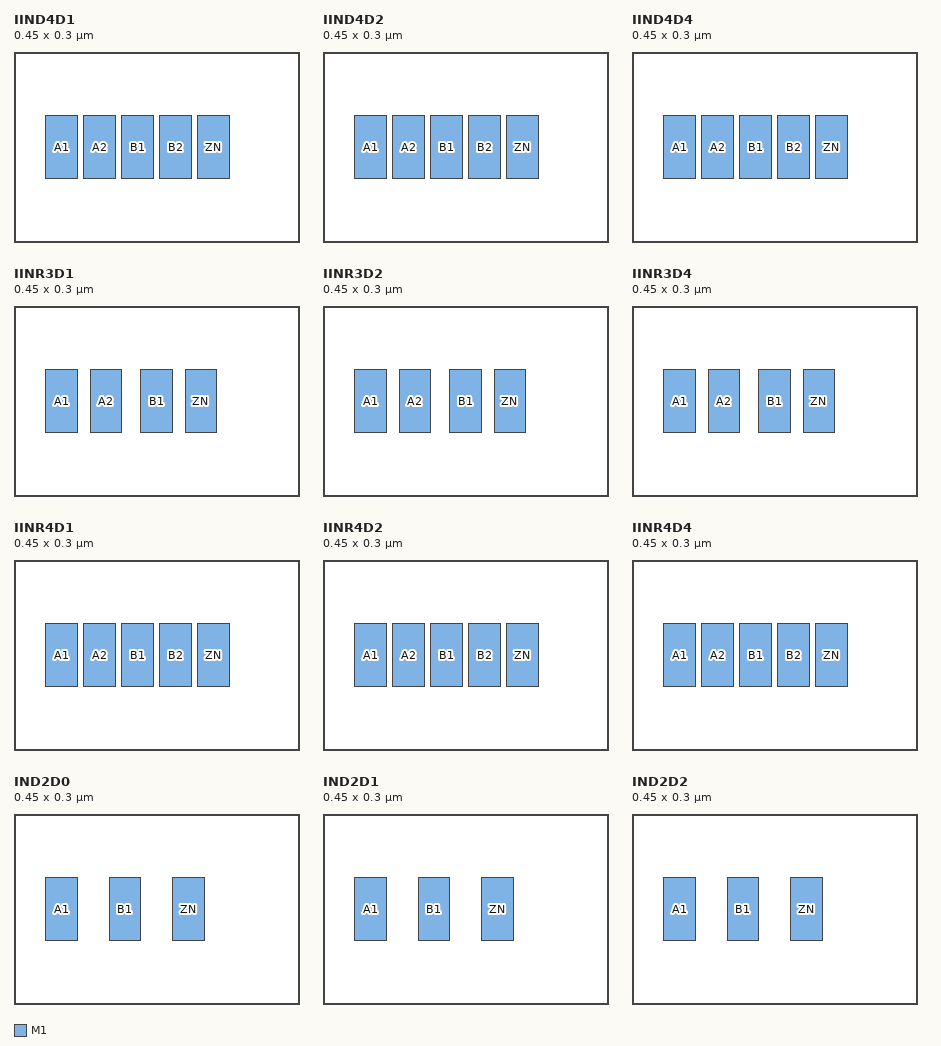
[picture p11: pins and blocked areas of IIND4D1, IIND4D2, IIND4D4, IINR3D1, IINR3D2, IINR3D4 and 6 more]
MACRO IIND4D1
  CLASS CORE ;
  ORIGIN 0.0 0.0 ;
  SIZE 0.45 BY 0.3 ;
  SYMMETRY X Y ;
  PIN A1
    DIRECTION INPUT ;
    USE SIGNAL ;
    PORT
      LAYER M1 ;
      RECT 0.05 0.1 0.10 0.2 ;
    END
  END A1
  PIN A2
    DIRECTION INPUT ;
    USE SIGNAL ;
    PORT
      LAYER M1 ;
      RECT 0.11 0.1 0.16 0.2 ;
    END
  END A2
  PIN B1
    DIRECTION INPUT ;
    USE SIGNAL ;
    PORT
      LAYER M1 ;
      RECT 0.17 0.1 0.22 0.2 ;
    END
  END B1
  PIN B2
    DIRECTION INPUT ;
    USE SIGNAL ;
    PORT
      LAYER M1 ;
      RECT 0.23 0.1 0.28 0.2 ;
    END
  END B2
  PIN ZN
    DIRECTION OUTPUT ;
    USE SIGNAL ;
    PORT
      LAYER M1 ;
      RECT 0.29 0.1 0.34 0.2 ;
    END
  END ZN
END IIND4D1
MACRO IIND4D2
  CLASS CORE ;
  ORIGIN 0.0 0.0 ;
  SIZE 0.45 BY 0.3 ;
  SYMMETRY X Y ;
  PIN A1
    DIRECTION INPUT ;
    USE SIGNAL ;
    PORT
      LAYER M1 ;
      RECT 0.05 0.1 0.10 0.2 ;
    END
  END A1
  PIN A2
    DIRECTION INPUT ;
    USE SIGNAL ;
    PORT
      LAYER M1 ;
      RECT 0.11 0.1 0.16 0.2 ;
    END
  END A2
  PIN B1
    DIRECTION INPUT ;
    USE SIGNAL ;
    PORT
      LAYER M1 ;
      RECT 0.17 0.1 0.22 0.2 ;
    END
  END B1
  PIN B2
    DIRECTION INPUT ;
    USE SIGNAL ;
    PORT
      LAYER M1 ;
      RECT 0.23 0.1 0.28 0.2 ;
    END
  END B2
  PIN ZN
    DIRECTION OUTPUT ;
    USE SIGNAL ;
    PORT
      LAYER M1 ;
      RECT 0.29 0.1 0.34 0.2 ;
    END
  END ZN
END IIND4D2
MACRO IIND4D4
  CLASS CORE ;
  ORIGIN 0.0 0.0 ;
  SIZE 0.45 BY 0.3 ;
  SYMMETRY X Y ;
  PIN A1
    DIRECTION INPUT ;
    USE SIGNAL ;
    PORT
      LAYER M1 ;
      RECT 0.05 0.1 0.10 0.2 ;
    END
  END A1
  PIN A2
    DIRECTION INPUT ;
    USE SIGNAL ;
    PORT
      LAYER M1 ;
      RECT 0.11 0.1 0.16 0.2 ;
    END
  END A2
  PIN B1
    DIRECTION INPUT ;
    USE SIGNAL ;
    PORT
      LAYER M1 ;
      RECT 0.17 0.1 0.22 0.2 ;
    END
  END B1
  PIN B2
    DIRECTION INPUT ;
    USE SIGNAL ;
    PORT
      LAYER M1 ;
      RECT 0.23 0.1 0.28 0.2 ;
    END
  END B2
  PIN ZN
    DIRECTION OUTPUT ;
    USE SIGNAL ;
    PORT
      LAYER M1 ;
      RECT 0.29 0.1 0.34 0.2 ;
    END
  END ZN
END IIND4D4
MACRO IINR3D1
  CLASS CORE ;
  ORIGIN 0.0 0.0 ;
  SIZE 0.45 BY 0.3 ;
  SYMMETRY X Y ;
  PIN A1
    DIRECTION INPUT ;
    USE SIGNAL ;
    PORT
      LAYER M1 ;
      RECT 0.05 0.1 0.10 0.2 ;
    END
  END A1
  PIN A2
    DIRECTION INPUT ;
    USE SIGNAL ;
    PORT
      LAYER M1 ;
      RECT 0.12 0.1 0.17 0.2 ;
    END
  END A2
  PIN B1
    DIRECTION INPUT ;
    USE SIGNAL ;
    PORT
      LAYER M1 ;
      RECT 0.20 0.1 0.25 0.2 ;
    END
  END B1
  PIN ZN
    DIRECTION OUTPUT ;
    USE SIGNAL ;
    PORT
      LAYER M1 ;
      RECT 0.27 0.1 0.32 0.2 ;
    END
  END ZN
END IINR3D1
MACRO IINR3D2
  CLASS CORE ;
  ORIGIN 0.0 0.0 ;
  SIZE 0.45 BY 0.3 ;
  SYMMETRY X Y ;
  PIN A1
    DIRECTION INPUT ;
    USE SIGNAL ;
    PORT
      LAYER M1 ;
      RECT 0.05 0.1 0.10 0.2 ;
    END
  END A1
  PIN A2
    DIRECTION INPUT ;
    USE SIGNAL ;
    PORT
      LAYER M1 ;
      RECT 0.12 0.1 0.17 0.2 ;
    END
  END A2
  PIN B1
    DIRECTION INPUT ;
    USE SIGNAL ;
    PORT
      LAYER M1 ;
      RECT 0.20 0.1 0.25 0.2 ;
    END
  END B1
  PIN ZN
    DIRECTION OUTPUT ;
    USE SIGNAL ;
    PORT
      LAYER M1 ;
      RECT 0.27 0.1 0.32 0.2 ;
    END
  END ZN
END IINR3D2
MACRO IINR3D4
  CLASS CORE ;
  ORIGIN 0.0 0.0 ;
  SIZE 0.45 BY 0.3 ;
  SYMMETRY X Y ;
  PIN A1
    DIRECTION INPUT ;
    USE SIGNAL ;
    PORT
      LAYER M1 ;
      RECT 0.05 0.1 0.10 0.2 ;
    END
  END A1
  PIN A2
    DIRECTION INPUT ;
    USE SIGNAL ;
    PORT
      LAYER M1 ;
      RECT 0.12 0.1 0.17 0.2 ;
    END
  END A2
  PIN B1
    DIRECTION INPUT ;
    USE SIGNAL ;
    PORT
      LAYER M1 ;
      RECT 0.20 0.1 0.25 0.2 ;
    END
  END B1
  PIN ZN
    DIRECTION OUTPUT ;
    USE SIGNAL ;
    PORT
      LAYER M1 ;
      RECT 0.27 0.1 0.32 0.2 ;
    END
  END ZN
END IINR3D4
MACRO IINR4D1
  CLASS CORE ;
  ORIGIN 0.0 0.0 ;
  SIZE 0.45 BY 0.3 ;
  SYMMETRY X Y ;
  PIN A1
    DIRECTION INPUT ;
    USE SIGNAL ;
    PORT
      LAYER M1 ;
      RECT 0.05 0.1 0.10 0.2 ;
    END
  END A1
  PIN A2
    DIRECTION INPUT ;
    USE SIGNAL ;
    PORT
      LAYER M1 ;
      RECT 0.11 0.1 0.16 0.2 ;
    END
  END A2
  PIN B1
    DIRECTION INPUT ;
    USE SIGNAL ;
    PORT
      LAYER M1 ;
      RECT 0.17 0.1 0.22 0.2 ;
    END
  END B1
  PIN B2
    DIRECTION INPUT ;
    USE SIGNAL ;
    PORT
      LAYER M1 ;
      RECT 0.23 0.1 0.28 0.2 ;
    END
  END B2
  PIN ZN
    DIRECTION OUTPUT ;
    USE SIGNAL ;
    PORT
      LAYER M1 ;
      RECT 0.29 0.1 0.34 0.2 ;
    END
  END ZN
END IINR4D1
MACRO IINR4D2
  CLASS CORE ;
  ORIGIN 0.0 0.0 ;
  SIZE 0.45 BY 0.3 ;
  SYMMETRY X Y ;
  PIN A1
    DIRECTION INPUT ;
    USE SIGNAL ;
    PORT
      LAYER M1 ;
      RECT 0.05 0.1 0.10 0.2 ;
    END
  END A1
  PIN A2
    DIRECTION INPUT ;
    USE SIGNAL ;
    PORT
      LAYER M1 ;
      RECT 0.11 0.1 0.16 0.2 ;
    END
  END A2
  PIN B1
    DIRECTION INPUT ;
    USE SIGNAL ;
    PORT
      LAYER M1 ;
      RECT 0.17 0.1 0.22 0.2 ;
    END
  END B1
  PIN B2
    DIRECTION INPUT ;
    USE SIGNAL ;
    PORT
      LAYER M1 ;
      RECT 0.23 0.1 0.28 0.2 ;
    END
  END B2
  PIN ZN
    DIRECTION OUTPUT ;
    USE SIGNAL ;
    PORT
      LAYER M1 ;
      RECT 0.29 0.1 0.34 0.2 ;
    END
  END ZN
END IINR4D2
MACRO IINR4D4
  CLASS CORE ;
  ORIGIN 0.0 0.0 ;
  SIZE 0.45 BY 0.3 ;
  SYMMETRY X Y ;
  PIN A1
    DIRECTION INPUT ;
    USE SIGNAL ;
    PORT
      LAYER M1 ;
      RECT 0.05 0.1 0.10 0.2 ;
    END
  END A1
  PIN A2
    DIRECTION INPUT ;
    USE SIGNAL ;
    PORT
      LAYER M1 ;
      RECT 0.11 0.1 0.16 0.2 ;
    END
  END A2
  PIN B1
    DIRECTION INPUT ;
    USE SIGNAL ;
    PORT
      LAYER M1 ;
      RECT 0.17 0.1 0.22 0.2 ;
    END
  END B1
  PIN B2
    DIRECTION INPUT ;
    USE SIGNAL ;
    PORT
      LAYER M1 ;
      RECT 0.23 0.1 0.28 0.2 ;
    END
  END B2
  PIN ZN
    DIRECTION OUTPUT ;
    USE SIGNAL ;
    PORT
      LAYER M1 ;
      RECT 0.29 0.1 0.34 0.2 ;
    END
  END ZN
END IINR4D4
MACRO IND2D0
  CLASS CORE ;
  ORIGIN 0.0 0.0 ;
  SIZE 0.45 BY 0.3 ;
  SYMMETRY X Y ;
  PIN A1
    DIRECTION INPUT ;
    USE SIGNAL ;
    PORT
      LAYER M1 ;
      RECT 0.05 0.1 0.10 0.2 ;
    END
  END A1
  PIN B1
    DIRECTION INPUT ;
    USE SIGNAL ;
    PORT
      LAYER M1 ;
      RECT 0.15 0.1 0.20 0.2 ;
    END
  END B1
  PIN ZN
    DIRECTION OUTPUT ;
    USE SIGNAL ;
    PORT
      LAYER M1 ;
      RECT 0.25 0.1 0.30 0.2 ;
    END
  END ZN
END IND2D0
MACRO IND2D1
  CLASS CORE ;
  ORIGIN 0.0 0.0 ;
  SIZE 0.45 BY 0.3 ;
  SYMMETRY X Y ;
  PIN A1
    DIRECTION INPUT ;
    USE SIGNAL ;
    PORT
      LAYER M1 ;
      RECT 0.05 0.1 0.10 0.2 ;
    END
  END A1
  PIN B1
    DIRECTION INPUT ;
    USE SIGNAL ;
    PORT
      LAYER M1 ;
      RECT 0.15 0.1 0.20 0.2 ;
    END
  END B1
  PIN ZN
    DIRECTION OUTPUT ;
    USE SIGNAL ;
    PORT
      LAYER M1 ;
      RECT 0.25 0.1 0.30 0.2 ;
    END
  END ZN
END IND2D1
MACRO IND2D2
  CLASS CORE ;
  ORIGIN 0.0 0.0 ;
  SIZE 0.45 BY 0.3 ;
  SYMMETRY X Y ;
  PIN A1
    DIRECTION INPUT ;
    USE SIGNAL ;
    PORT
      LAYER M1 ;
      RECT 0.05 0.1 0.10 0.2 ;
    END
  END A1
  PIN B1
    DIRECTION INPUT ;
    USE SIGNAL ;
    PORT
      LAYER M1 ;
      RECT 0.15 0.1 0.20 0.2 ;
    END
  END B1
  PIN ZN
    DIRECTION OUTPUT ;
    USE SIGNAL ;
    PORT
      LAYER M1 ;
      RECT 0.25 0.1 0.30 0.2 ;
    END
  END ZN
END IND2D2
MACRO IND2D3
  CLASS CORE ;
  ORIGIN 0.0 0.0 ;
  SIZE 0.45 BY 0.3 ;
  SYMMETRY X Y ;
  PIN A1
    DIRECTION INPUT ;
    USE SIGNAL ;
    PORT
      LAYER M1 ;
      RECT 0.05 0.1 0.10 0.2 ;
    END
  END A1
  PIN B1
    DIRECTION INPUT ;
    USE SIGNAL ;
    PORT
      LAYER M1 ;
      RECT 0.15 0.1 0.20 0.2 ;
    END
  END B1
  PIN ZN
    DIRECTION OUTPUT ;
    USE SIGNAL ;
    PORT
      LAYER M1 ;
      RECT 0.25 0.1 0.30 0.2 ;
    END
  END ZN
END IND2D3
MACRO IND2D4
  CLASS CORE ;
  ORIGIN 0.0 0.0 ;
  SIZE 0.45 BY 0.3 ;
  SYMMETRY X Y ;
  PIN A1
    DIRECTION INPUT ;
    USE SIGNAL ;
    PORT
      LAYER M1 ;
      RECT 0.05 0.1 0.10 0.2 ;
    END
  END A1
  PIN B1
    DIRECTION INPUT ;
    USE SIGNAL ;
    PORT
      LAYER M1 ;
      RECT 0.15 0.1 0.20 0.2 ;
    END
  END B1
  PIN ZN
    DIRECTION OUTPUT ;
    USE SIGNAL ;
    PORT
      LAYER M1 ;
      RECT 0.25 0.1 0.30 0.2 ;
    END
  END ZN
END IND2D4
MACRO IND2D6
  CLASS CORE ;
  ORIGIN 0.0 0.0 ;
  SIZE 0.45 BY 0.3 ;
  SYMMETRY X Y ;
  PIN A1
    DIRECTION INPUT ;
    USE SIGNAL ;
    PORT
      LAYER M1 ;
      RECT 0.05 0.1 0.10 0.2 ;
    END
  END A1
  PIN B1
    DIRECTION INPUT ;
    USE SIGNAL ;
    PORT
      LAYER M1 ;
      RECT 0.15 0.1 0.20 0.2 ;
    END
  END B1
  PIN ZN
    DIRECTION OUTPUT ;
    USE SIGNAL ;
    PORT
      LAYER M1 ;
      RECT 0.25 0.1 0.30 0.2 ;
    END
  END ZN
END IND2D6
MACRO IND2D8
  CLASS CORE ;
  ORIGIN 0.0 0.0 ;
  SIZE 0.45 BY 0.3 ;
  SYMMETRY X Y ;
  PIN A1
    DIRECTION INPUT ;
    USE SIGNAL ;
    PORT
      LAYER M1 ;
      RECT 0.05 0.1 0.10 0.2 ;
    END
  END A1
  PIN B1
    DIRECTION INPUT ;
    USE SIGNAL ;
    PORT
      LAYER M1 ;
      RECT 0.15 0.1 0.20 0.2 ;
    END
  END B1
  PIN ZN
    DIRECTION OUTPUT ;
    USE SIGNAL ;
    PORT
      LAYER M1 ;
      RECT 0.25 0.1 0.30 0.2 ;
    END
  END ZN
END IND2D8
MACRO IND3D1
  CLASS CORE ;
  ORIGIN 0.0 0.0 ;
  SIZE 0.45 BY 0.3 ;
  SYMMETRY X Y ;
  PIN A1
    DIRECTION INPUT ;
    USE SIGNAL ;
    PORT
      LAYER M1 ;
      RECT 0.05 0.1 0.10 0.2 ;
    END
  END A1
  PIN B1
    DIRECTION INPUT ;
    USE SIGNAL ;
    PORT
      LAYER M1 ;
      RECT 0.12 0.1 0.17 0.2 ;
    END
  END B1
  PIN B2
    DIRECTION INPUT ;
    USE SIGNAL ;
    PORT
      LAYER M1 ;
      RECT 0.20 0.1 0.25 0.2 ;
    END
  END B2
  PIN ZN
    DIRECTION OUTPUT ;
    USE SIGNAL ;
    PORT
      LAYER M1 ;
      RECT 0.27 0.1 0.32 0.2 ;
    END
  END ZN
END IND3D1
MACRO IND3D3
  CLASS CORE ;
  ORIGIN 0.0 0.0 ;
  SIZE 0.45 BY 0.3 ;
  SYMMETRY X Y ;
  PIN A1
    DIRECTION INPUT ;
    USE SIGNAL ;
    PORT
      LAYER M1 ;
      RECT 0.05 0.1 0.10 0.2 ;
    END
  END A1
  PIN B1
    DIRECTION INPUT ;
    USE SIGNAL ;
    PORT
      LAYER M1 ;
      RECT 0.12 0.1 0.17 0.2 ;
    END
  END B1
  PIN B2
    DIRECTION INPUT ;
    USE SIGNAL ;
    PORT
      LAYER M1 ;
      RECT 0.20 0.1 0.25 0.2 ;
    END
  END B2
  PIN ZN
    DIRECTION OUTPUT ;
    USE SIGNAL ;
    PORT
      LAYER M1 ;
      RECT 0.27 0.1 0.32 0.2 ;
    END
  END ZN
END IND3D3
MACRO IND3OPTPAD1
  CLASS CORE ;
  ORIGIN 0.0 0.0 ;
  SIZE 0.45 BY 0.3 ;
  SYMMETRY X Y ;
  PIN A1
    DIRECTION INPUT ;
    USE SIGNAL ;
    PORT
      LAYER M1 ;
      RECT 0.05 0.1 0.10 0.2 ;
    END
  END A1
  PIN B1
    DIRECTION INPUT ;
    USE SIGNAL ;
    PORT
      LAYER M1 ;
      RECT 0.12 0.1 0.17 0.2 ;
    END
  END B1
  PIN B2
    DIRECTION INPUT ;
    USE SIGNAL ;
    PORT
      LAYER M1 ;
      RECT 0.20 0.1 0.25 0.2 ;
    END
  END B2
  PIN ZN
    DIRECTION OUTPUT ;
    USE SIGNAL ;
    PORT
      LAYER M1 ;
      RECT 0.27 0.1 0.32 0.2 ;
    END
  END ZN
END IND3OPTPAD1
MACRO IND3OPTPAD2
  CLASS CORE ;
  ORIGIN 0.0 0.0 ;
  SIZE 0.45 BY 0.3 ;
  SYMMETRY X Y ;
  PIN A1
    DIRECTION INPUT ;
    USE SIGNAL ;
    PORT
      LAYER M1 ;
      RECT 0.05 0.1 0.10 0.2 ;
    END
  END A1
  PIN B1
    DIRECTION INPUT ;
    USE SIGNAL ;
    PORT
      LAYER M1 ;
      RECT 0.12 0.1 0.17 0.2 ;
    END
  END B1
  PIN B2
    DIRECTION INPUT ;
    USE SIGNAL ;
    PORT
      LAYER M1 ;
      RECT 0.20 0.1 0.25 0.2 ;
    END
  END B2
  PIN ZN
    DIRECTION OUTPUT ;
    USE SIGNAL ;
    PORT
      LAYER M1 ;
      RECT 0.27 0.1 0.32 0.2 ;
    END
  END ZN
END IND3OPTPAD2
MACRO IND4D0
  CLASS CORE ;
  ORIGIN 0.0 0.0 ;
  SIZE 0.45 BY 0.3 ;
  SYMMETRY X Y ;
  PIN A1
    DIRECTION INPUT ;
    USE SIGNAL ;
    PORT
      LAYER M1 ;
      RECT 0.05 0.1 0.10 0.2 ;
    END
  END A1
  PIN B1
    DIRECTION INPUT ;
    USE SIGNAL ;
    PORT
      LAYER M1 ;
      RECT 0.11 0.1 0.16 0.2 ;
    END
  END B1
  PIN B2
    DIRECTION INPUT ;
    USE SIGNAL ;
    PORT
      LAYER M1 ;
      RECT 0.17 0.1 0.22 0.2 ;
    END
  END B2
  PIN B3
    DIRECTION INPUT ;
    USE SIGNAL ;
    PORT
      LAYER M1 ;
      RECT 0.23 0.1 0.28 0.2 ;
    END
  END B3
  PIN ZN
    DIRECTION OUTPUT ;
    USE SIGNAL ;
    PORT
      LAYER M1 ;
      RECT 0.29 0.1 0.34 0.2 ;
    END
  END ZN
END IND4D0
MACRO IND4D1
  CLASS CORE ;
  ORIGIN 0.0 0.0 ;
  SIZE 0.45 BY 0.3 ;
  SYMMETRY X Y ;
  PIN A1
    DIRECTION INPUT ;
    USE SIGNAL ;
    PORT
      LAYER M1 ;
      RECT 0.05 0.1 0.10 0.2 ;
    END
  END A1
  PIN B1
    DIRECTION INPUT ;
    USE SIGNAL ;
    PORT
      LAYER M1 ;
      RECT 0.11 0.1 0.16 0.2 ;
    END
  END B1
  PIN B2
    DIRECTION INPUT ;
    USE SIGNAL ;
    PORT
      LAYER M1 ;
      RECT 0.17 0.1 0.22 0.2 ;
    END
  END B2
  PIN B3
    DIRECTION INPUT ;
    USE SIGNAL ;
    PORT
      LAYER M1 ;
      RECT 0.23 0.1 0.28 0.2 ;
    END
  END B3
  PIN ZN
    DIRECTION OUTPUT ;
    USE SIGNAL ;
    PORT
      LAYER M1 ;
      RECT 0.29 0.1 0.34 0.2 ;
    END
  END ZN
END IND4D1
MACRO IND4D2
  CLASS CORE ;
  ORIGIN 0.0 0.0 ;
  SIZE 0.45 BY 0.3 ;
  SYMMETRY X Y ;
  PIN A1
    DIRECTION INPUT ;
    USE SIGNAL ;
    PORT
      LAYER M1 ;
      RECT 0.05 0.1 0.10 0.2 ;
    END
  END A1
  PIN B1
    DIRECTION INPUT ;
    USE SIGNAL ;
    PORT
      LAYER M1 ;
      RECT 0.11 0.1 0.16 0.2 ;
    END
  END B1
  PIN B2
    DIRECTION INPUT ;
    USE SIGNAL ;
    PORT
      LAYER M1 ;
      RECT 0.17 0.1 0.22 0.2 ;
    END
  END B2
  PIN B3
    DIRECTION INPUT ;
    USE SIGNAL ;
    PORT
      LAYER M1 ;
      RECT 0.23 0.1 0.28 0.2 ;
    END
  END B3
  PIN ZN
    DIRECTION OUTPUT ;
    USE SIGNAL ;
    PORT
      LAYER M1 ;
      RECT 0.29 0.1 0.34 0.2 ;
    END
  END ZN
END IND4D2
MACRO IND4D4
  CLASS CORE ;
  ORIGIN 0.0 0.0 ;
  SIZE 0.45 BY 0.3 ;
  SYMMETRY X Y ;
  PIN A1
    DIRECTION INPUT ;
    USE SIGNAL ;
    PORT
      LAYER M1 ;
      RECT 0.05 0.1 0.10 0.2 ;
    END
  END A1
  PIN B1
    DIRECTION INPUT ;
    USE SIGNAL ;
    PORT
      LAYER M1 ;
      RECT 0.11 0.1 0.16 0.2 ;
    END
  END B1
  PIN B2
    DIRECTION INPUT ;
    USE SIGNAL ;
    PORT
      LAYER M1 ;
      RECT 0.17 0.1 0.22 0.2 ;
    END
  END B2
  PIN B3
    DIRECTION INPUT ;
    USE SIGNAL ;
    PORT
      LAYER M1 ;
      RECT 0.23 0.1 0.28 0.2 ;
    END
  END B3
  PIN ZN
    DIRECTION OUTPUT ;
    USE SIGNAL ;
    PORT
      LAYER M1 ;
      RECT 0.29 0.1 0.34 0.2 ;
    END
  END ZN
END IND4D4
MACRO INR2D1
  CLASS CORE ;
  ORIGIN 0.0 0.0 ;
  SIZE 0.45 BY 0.3 ;
  SYMMETRY X Y ;
  PIN A1
    DIRECTION INPUT ;
    USE SIGNAL ;
    PORT
      LAYER M1 ;
      RECT 0.05 0.1 0.10 0.2 ;
    END
  END A1
  PIN B1
    DIRECTION INPUT ;
    USE SIGNAL ;
    PORT
      LAYER M1 ;
      RECT 0.15 0.1 0.20 0.2 ;
    END
  END B1
  PIN ZN
    DIRECTION OUTPUT ;
    USE SIGNAL ;
    PORT
      LAYER M1 ;
      RECT 0.25 0.1 0.30 0.2 ;
    END
  END ZN
END INR2D1
MACRO INR2D2
  CLASS CORE ;
  ORIGIN 0.0 0.0 ;
  SIZE 0.45 BY 0.3 ;
  SYMMETRY X Y ;
  PIN A1
    DIRECTION INPUT ;
    USE SIGNAL ;
    PORT
      LAYER M1 ;
      RECT 0.05 0.1 0.10 0.2 ;
    END
  END A1
  PIN B1
    DIRECTION INPUT ;
    USE SIGNAL ;
    PORT
      LAYER M1 ;
      RECT 0.15 0.1 0.20 0.2 ;
    END
  END B1
  PIN ZN
    DIRECTION OUTPUT ;
    USE SIGNAL ;
    PORT
      LAYER M1 ;
      RECT 0.25 0.1 0.30 0.2 ;
    END
  END ZN
END INR2D2
MACRO INR2D3
  CLASS CORE ;
  ORIGIN 0.0 0.0 ;
  SIZE 0.45 BY 0.3 ;
  SYMMETRY X Y ;
  PIN A1
    DIRECTION INPUT ;
    USE SIGNAL ;
    PORT
      LAYER M1 ;
      RECT 0.05 0.1 0.10 0.2 ;
    END
  END A1
  PIN B1
    DIRECTION INPUT ;
    USE SIGNAL ;
    PORT
      LAYER M1 ;
      RECT 0.15 0.1 0.20 0.2 ;
    END
  END B1
  PIN ZN
    DIRECTION OUTPUT ;
    USE SIGNAL ;
    PORT
      LAYER M1 ;
      RECT 0.25 0.1 0.30 0.2 ;
    END
  END ZN
END INR2D3
MACRO INR2D4
  CLASS CORE ;
  ORIGIN 0.0 0.0 ;
  SIZE 0.45 BY 0.3 ;
  SYMMETRY X Y ;
  PIN A1
    DIRECTION INPUT ;
    USE SIGNAL ;
    PORT
      LAYER M1 ;
      RECT 0.05 0.1 0.10 0.2 ;
    END
  END A1
  PIN B1
    DIRECTION INPUT ;
    USE SIGNAL ;
    PORT
      LAYER M1 ;
      RECT 0.15 0.1 0.20 0.2 ;
    END
  END B1
  PIN ZN
    DIRECTION OUTPUT ;
    USE SIGNAL ;
    PORT
      LAYER M1 ;
      RECT 0.25 0.1 0.30 0.2 ;
    END
  END ZN
END INR2D4
MACRO INR2D6
  CLASS CORE ;
  ORIGIN 0.0 0.0 ;
  SIZE 0.45 BY 0.3 ;
  SYMMETRY X Y ;
  PIN A1
    DIRECTION INPUT ;
    USE SIGNAL ;
    PORT
      LAYER M1 ;
      RECT 0.05 0.1 0.10 0.2 ;
    END
  END A1
  PIN B1
    DIRECTION INPUT ;
    USE SIGNAL ;
    PORT
      LAYER M1 ;
      RECT 0.15 0.1 0.20 0.2 ;
    END
  END B1
  PIN ZN
    DIRECTION OUTPUT ;
    USE SIGNAL ;
    PORT
      LAYER M1 ;
      RECT 0.25 0.1 0.30 0.2 ;
    END
  END ZN
END INR2D6
MACRO INR2D8
  CLASS CORE ;
  ORIGIN 0.0 0.0 ;
  SIZE 0.45 BY 0.3 ;
  SYMMETRY X Y ;
  PIN A1
    DIRECTION INPUT ;
    USE SIGNAL ;
    PORT
      LAYER M1 ;
      RECT 0.05 0.1 0.10 0.2 ;
    END
  END A1
  PIN B1
    DIRECTION INPUT ;
    USE SIGNAL ;
    PORT
      LAYER M1 ;
      RECT 0.15 0.1 0.20 0.2 ;
    END
  END B1
  PIN ZN
    DIRECTION OUTPUT ;
    USE SIGNAL ;
    PORT
      LAYER M1 ;
      RECT 0.25 0.1 0.30 0.2 ;
    END
  END ZN
END INR2D8
MACRO INR3D1
  CLASS CORE ;
  ORIGIN 0.0 0.0 ;
  SIZE 0.45 BY 0.3 ;
  SYMMETRY X Y ;
  PIN A1
    DIRECTION INPUT ;
    USE SIGNAL ;
    PORT
      LAYER M1 ;
      RECT 0.05 0.1 0.10 0.2 ;
    END
  END A1
  PIN B1
    DIRECTION INPUT ;
    USE SIGNAL ;
    PORT
      LAYER M1 ;
      RECT 0.12 0.1 0.17 0.2 ;
    END
  END B1
  PIN B2
    DIRECTION INPUT ;
    USE SIGNAL ;
    PORT
      LAYER M1 ;
      RECT 0.20 0.1 0.25 0.2 ;
    END
  END B2
  PIN ZN
    DIRECTION OUTPUT ;
    USE SIGNAL ;
    PORT
      LAYER M1 ;
      RECT 0.27 0.1 0.32 0.2 ;
    END
  END ZN
END INR3D1
MACRO INR3D3
  CLASS CORE ;
  ORIGIN 0.0 0.0 ;
  SIZE 0.45 BY 0.3 ;
  SYMMETRY X Y ;
  PIN A1
    DIRECTION INPUT ;
    USE SIGNAL ;
    PORT
      LAYER M1 ;
      RECT 0.05 0.1 0.10 0.2 ;
    END
  END A1
  PIN B1
    DIRECTION INPUT ;
    USE SIGNAL ;
    PORT
      LAYER M1 ;
      RECT 0.12 0.1 0.17 0.2 ;
    END
  END B1
  PIN B2
    DIRECTION INPUT ;
    USE SIGNAL ;
    PORT
      LAYER M1 ;
      RECT 0.20 0.1 0.25 0.2 ;
    END
  END B2
  PIN ZN
    DIRECTION OUTPUT ;
    USE SIGNAL ;
    PORT
      LAYER M1 ;
      RECT 0.27 0.1 0.32 0.2 ;
    END
  END ZN
END INR3D3
MACRO INR3D4
  CLASS CORE ;
  ORIGIN 0.0 0.0 ;
  SIZE 0.45 BY 0.3 ;
  SYMMETRY X Y ;
  PIN A1
    DIRECTION INPUT ;
    USE SIGNAL ;
    PORT
      LAYER M1 ;
      RECT 0.05 0.1 0.10 0.2 ;
    END
  END A1
  PIN B1
    DIRECTION INPUT ;
    USE SIGNAL ;
    PORT
      LAYER M1 ;
      RECT 0.12 0.1 0.17 0.2 ;
    END
  END B1
  PIN B2
    DIRECTION INPUT ;
    USE SIGNAL ;
    PORT
      LAYER M1 ;
      RECT 0.20 0.1 0.25 0.2 ;
    END
  END B2
  PIN ZN
    DIRECTION OUTPUT ;
    USE SIGNAL ;
    PORT
      LAYER M1 ;
      RECT 0.27 0.1 0.32 0.2 ;
    END
  END ZN
END INR3D4
MACRO INR3D6
  CLASS CORE ;
  ORIGIN 0.0 0.0 ;
  SIZE 0.45 BY 0.3 ;
  SYMMETRY X Y ;
  PIN A1
    DIRECTION INPUT ;
    USE SIGNAL ;
    PORT
      LAYER M1 ;
      RECT 0.05 0.1 0.10 0.2 ;
    END
  END A1
  PIN B1
    DIRECTION INPUT ;
    USE SIGNAL ;
    PORT
      LAYER M1 ;
      RECT 0.12 0.1 0.17 0.2 ;
    END
  END B1
  PIN B2
    DIRECTION INPUT ;
    USE SIGNAL ;
    PORT
      LAYER M1 ;
      RECT 0.20 0.1 0.25 0.2 ;
    END
  END B2
  PIN ZN
    DIRECTION OUTPUT ;
    USE SIGNAL ;
    PORT
      LAYER M1 ;
      RECT 0.27 0.1 0.32 0.2 ;
    END
  END ZN
END INR3D6
MACRO INR3D8
  CLASS CORE ;
  ORIGIN 0.0 0.0 ;
  SIZE 0.45 BY 0.3 ;
  SYMMETRY X Y ;
  PIN A1
    DIRECTION INPUT ;
    USE SIGNAL ;
    PORT
      LAYER M1 ;
      RECT 0.05 0.1 0.10 0.2 ;
    END
  END A1
  PIN B1
    DIRECTION INPUT ;
    USE SIGNAL ;
    PORT
      LAYER M1 ;
      RECT 0.12 0.1 0.17 0.2 ;
    END
  END B1
  PIN B2
    DIRECTION INPUT ;
    USE SIGNAL ;
    PORT
      LAYER M1 ;
      RECT 0.20 0.1 0.25 0.2 ;
    END
  END B2
  PIN ZN
    DIRECTION OUTPUT ;
    USE SIGNAL ;
    PORT
      LAYER M1 ;
      RECT 0.27 0.1 0.32 0.2 ;
    END
  END ZN
END INR3D8
MACRO INR3OPTPAD1
  CLASS CORE ;
  ORIGIN 0.0 0.0 ;
  SIZE 0.45 BY 0.3 ;
  SYMMETRY X Y ;
  PIN A1
    DIRECTION INPUT ;
    USE SIGNAL ;
    PORT
      LAYER M1 ;
      RECT 0.05 0.1 0.10 0.2 ;
    END
  END A1
  PIN B1
    DIRECTION INPUT ;
    USE SIGNAL ;
    PORT
      LAYER M1 ;
      RECT 0.12 0.1 0.17 0.2 ;
    END
  END B1
  PIN B2
    DIRECTION INPUT ;
    USE SIGNAL ;
    PORT
      LAYER M1 ;
      RECT 0.20 0.1 0.25 0.2 ;
    END
  END B2
  PIN ZN
    DIRECTION OUTPUT ;
    USE SIGNAL ;
    PORT
      LAYER M1 ;
      RECT 0.27 0.1 0.32 0.2 ;
    END
  END ZN
END INR3OPTPAD1
MACRO INR3OPTPAD2
  CLASS CORE ;
  ORIGIN 0.0 0.0 ;
  SIZE 0.45 BY 0.3 ;
  SYMMETRY X Y ;
  PIN A1
    DIRECTION INPUT ;
    USE SIGNAL ;
    PORT
      LAYER M1 ;
      RECT 0.05 0.1 0.10 0.2 ;
    END
  END A1
  PIN B1
    DIRECTION INPUT ;
    USE SIGNAL ;
    PORT
      LAYER M1 ;
      RECT 0.12 0.1 0.17 0.2 ;
    END
  END B1
  PIN B2
    DIRECTION INPUT ;
    USE SIGNAL ;
    PORT
      LAYER M1 ;
      RECT 0.20 0.1 0.25 0.2 ;
    END
  END B2
  PIN ZN
    DIRECTION OUTPUT ;
    USE SIGNAL ;
    PORT
      LAYER M1 ;
      RECT 0.27 0.1 0.32 0.2 ;
    END
  END ZN
END INR3OPTPAD2
MACRO INR4D1
  CLASS CORE ;
  ORIGIN 0.0 0.0 ;
  SIZE 0.45 BY 0.3 ;
  SYMMETRY X Y ;
  PIN A1
    DIRECTION INPUT ;
    USE SIGNAL ;
    PORT
      LAYER M1 ;
      RECT 0.05 0.1 0.10 0.2 ;
    END
  END A1
  PIN B1
    DIRECTION INPUT ;
    USE SIGNAL ;
    PORT
      LAYER M1 ;
      RECT 0.11 0.1 0.16 0.2 ;
    END
  END B1
  PIN B2
    DIRECTION INPUT ;
    USE SIGNAL ;
    PORT
      LAYER M1 ;
      RECT 0.17 0.1 0.22 0.2 ;
    END
  END B2
  PIN B3
    DIRECTION INPUT ;
    USE SIGNAL ;
    PORT
      LAYER M1 ;
      RECT 0.23 0.1 0.28 0.2 ;
    END
  END B3
  PIN ZN
    DIRECTION OUTPUT ;
    USE SIGNAL ;
    PORT
      LAYER M1 ;
      RECT 0.29 0.1 0.34 0.2 ;
    END
  END ZN
END INR4D1
MACRO INR4D2
  CLASS CORE ;
  ORIGIN 0.0 0.0 ;
  SIZE 0.45 BY 0.3 ;
  SYMMETRY X Y ;
  PIN A1
    DIRECTION INPUT ;
    USE SIGNAL ;
    PORT
      LAYER M1 ;
      RECT 0.05 0.1 0.10 0.2 ;
    END
  END A1
  PIN B1
    DIRECTION INPUT ;
    USE SIGNAL ;
    PORT
      LAYER M1 ;
      RECT 0.11 0.1 0.16 0.2 ;
    END
  END B1
  PIN B2
    DIRECTION INPUT ;
    USE SIGNAL ;
    PORT
      LAYER M1 ;
      RECT 0.17 0.1 0.22 0.2 ;
    END
  END B2
  PIN B3
    DIRECTION INPUT ;
    USE SIGNAL ;
    PORT
      LAYER M1 ;
      RECT 0.23 0.1 0.28 0.2 ;
    END
  END B3
  PIN ZN
    DIRECTION OUTPUT ;
    USE SIGNAL ;
    PORT
      LAYER M1 ;
      RECT 0.29 0.1 0.34 0.2 ;
    END
  END ZN
END INR4D2
MACRO INR4D4
  CLASS CORE ;
  ORIGIN 0.0 0.0 ;
  SIZE 0.45 BY 0.3 ;
  SYMMETRY X Y ;
  PIN A1
    DIRECTION INPUT ;
    USE SIGNAL ;
    PORT
      LAYER M1 ;
      RECT 0.05 0.1 0.10 0.2 ;
    END
  END A1
  PIN B1
    DIRECTION INPUT ;
    USE SIGNAL ;
    PORT
      LAYER M1 ;
      RECT 0.11 0.1 0.16 0.2 ;
    END
  END B1
  PIN B2
    DIRECTION INPUT ;
    USE SIGNAL ;
    PORT
      LAYER M1 ;
      RECT 0.17 0.1 0.22 0.2 ;
    END
  END B2
  PIN B3
    DIRECTION INPUT ;
    USE SIGNAL ;
    PORT
      LAYER M1 ;
      RECT 0.23 0.1 0.28 0.2 ;
    END
  END B3
  PIN ZN
    DIRECTION OUTPUT ;
    USE SIGNAL ;
    PORT
      LAYER M1 ;
      RECT 0.29 0.1 0.34 0.2 ;
    END
  END ZN
END INR4D4
MACRO INVD1
  CLASS CORE ;
  ORIGIN 0.0 0.0 ;
  SIZE 0.45 BY 0.3 ;
  SYMMETRY X Y ;
  PIN I
    DIRECTION INPUT ;
    USE SIGNAL ;
    PORT
      LAYER M1 ;
      RECT 0.05 0.1 0.10 0.2 ;
    END
  END I
  PIN ZN
    DIRECTION OUTPUT ;
    USE SIGNAL ;
    PORT
      LAYER M1 ;
      RECT 0.20 0.1 0.25 0.2 ;
    END
  END ZN
END INVD1
MACRO INVD2
  CLASS CORE ;
  ORIGIN 0.0 0.0 ;
  SIZE 0.45 BY 0.3 ;
  SYMMETRY X Y ;
  PIN I
    DIRECTION INPUT ;
    USE SIGNAL ;
    PORT
      LAYER M1 ;
      RECT 0.05 0.1 0.10 0.2 ;
    END
  END I
  PIN ZN
    DIRECTION OUTPUT ;
    USE SIGNAL ;
    PORT
      LAYER M1 ;
      RECT 0.20 0.1 0.25 0.2 ;
    END
  END ZN
END INVD2
MACRO INVD3
  CLASS CORE ;
  ORIGIN 0.0 0.0 ;
  SIZE 0.45 BY 0.3 ;
  SYMMETRY X Y ;
  PIN I
    DIRECTION INPUT ;
    USE SIGNAL ;
    PORT
      LAYER M1 ;
      RECT 0.05 0.1 0.10 0.2 ;
    END
  END I
  PIN ZN
    DIRECTION OUTPUT ;
    USE SIGNAL ;
    PORT
      LAYER M1 ;
      RECT 0.20 0.1 0.25 0.2 ;
    END
  END ZN
END INVD3
MACRO INVD4
  CLASS CORE ;
  ORIGIN 0.0 0.0 ;
  SIZE 0.45 BY 0.3 ;
  SYMMETRY X Y ;
  PIN I
    DIRECTION INPUT ;
    USE SIGNAL ;
    PORT
      LAYER M1 ;
      RECT 0.05 0.1 0.10 0.2 ;
    END
  END I
  PIN ZN
    DIRECTION OUTPUT ;
    USE SIGNAL ;
    PORT
      LAYER M1 ;
      RECT 0.20 0.1 0.25 0.2 ;
    END
  END ZN
END INVD4
MACRO INVD8
  CLASS CORE ;
  ORIGIN 0.0 0.0 ;
  SIZE 0.45 BY 0.3 ;
  SYMMETRY X Y ;
  PIN I
    DIRECTION INPUT ;
    USE SIGNAL ;
    PORT
      LAYER M1 ;
      RECT 0.05 0.1 0.10 0.2 ;
    END
  END I
  PIN ZN
    DIRECTION OUTPUT ;
    USE SIGNAL ;
    PORT
      LAYER M1 ;
      RECT 0.20 0.1 0.25 0.2 ;
    END
  END ZN
END INVD8
MACRO INVSKND5
  CLASS CORE ;
  ORIGIN 0.0 0.0 ;
  SIZE 0.45 BY 0.3 ;
  SYMMETRY X Y ;
  PIN I
    DIRECTION INPUT ;
    USE SIGNAL ;
    PORT
      LAYER M1 ;
      RECT 0.05 0.1 0.10 0.2 ;
    END
  END I
  PIN ZN
    DIRECTION OUTPUT ;
    USE SIGNAL ;
    PORT
      LAYER M1 ;
      RECT 0.20 0.1 0.25 0.2 ;
    END
  END ZN
END INVSKND5
MACRO INVSKPD12
  CLASS CORE ;
  ORIGIN 0.0 0.0 ;
  SIZE 0.45 BY 0.3 ;
  SYMMETRY X Y ;
  PIN I
    DIRECTION INPUT ;
    USE SIGNAL ;
    PORT
      LAYER M1 ;
      RECT 0.05 0.1 0.10 0.2 ;
    END
  END I
  PIN ZN
    DIRECTION OUTPUT ;
    USE SIGNAL ;
    PORT
      LAYER M1 ;
      RECT 0.20 0.1 0.25 0.2 ;
    END
  END ZN
END INVSKPD12
MACRO INVSKPD14
  CLASS CORE ;
  ORIGIN 0.0 0.0 ;
  SIZE 0.45 BY 0.3 ;
  SYMMETRY X Y ;
  PIN I
    DIRECTION INPUT ;
    USE SIGNAL ;
    PORT
      LAYER M1 ;
      RECT 0.05 0.1 0.10 0.2 ;
    END
  END I
  PIN ZN
    DIRECTION OUTPUT ;
    USE SIGNAL ;
    PORT
      LAYER M1 ;
      RECT 0.20 0.1 0.25 0.2 ;
    END
  END ZN
END INVSKPD14
MACRO INVSKPD1
  CLASS CORE ;
  ORIGIN 0.0 0.0 ;
  SIZE 0.45 BY 0.3 ;
  SYMMETRY X Y ;
  PIN I
    DIRECTION INPUT ;
    USE SIGNAL ;
    PORT
      LAYER M1 ;
      RECT 0.05 0.1 0.10 0.2 ;
    END
  END I
  PIN ZN
    DIRECTION OUTPUT ;
    USE SIGNAL ;
    PORT
      LAYER M1 ;
      RECT 0.20 0.1 0.25 0.2 ;
    END
  END ZN
END INVSKPD1
MACRO INVSKPD2
  CLASS CORE ;
  ORIGIN 0.0 0.0 ;
  SIZE 0.45 BY 0.3 ;
  SYMMETRY X Y ;
  PIN I
    DIRECTION INPUT ;
    USE SIGNAL ;
    PORT
      LAYER M1 ;
      RECT 0.05 0.1 0.10 0.2 ;
    END
  END I
  PIN ZN
    DIRECTION OUTPUT ;
    USE SIGNAL ;
    PORT
      LAYER M1 ;
      RECT 0.20 0.1 0.25 0.2 ;
    END
  END ZN
END INVSKPD2
MACRO INVSKPD3
  CLASS CORE ;
  ORIGIN 0.0 0.0 ;
  SIZE 0.45 BY 0.3 ;
  SYMMETRY X Y ;
  PIN I
    DIRECTION INPUT ;
    USE SIGNAL ;
    PORT
      LAYER M1 ;
      RECT 0.05 0.1 0.10 0.2 ;
    END
  END I
  PIN ZN
    DIRECTION OUTPUT ;
    USE SIGNAL ;
    PORT
      LAYER M1 ;
      RECT 0.20 0.1 0.25 0.2 ;
    END
  END ZN
END INVSKPD3
MACRO INVSKPD4
  CLASS CORE ;
  ORIGIN 0.0 0.0 ;
  SIZE 0.45 BY 0.3 ;
  SYMMETRY X Y ;
  PIN I
    DIRECTION INPUT ;
    USE SIGNAL ;
    PORT
      LAYER M1 ;
      RECT 0.05 0.1 0.10 0.2 ;
    END
  END I
  PIN ZN
    DIRECTION OUTPUT ;
    USE SIGNAL ;
    PORT
      LAYER M1 ;
      RECT 0.20 0.1 0.25 0.2 ;
    END
  END ZN
END INVSKPD4
MACRO INVSKPD6
  CLASS CORE ;
  ORIGIN 0.0 0.0 ;
  SIZE 0.45 BY 0.3 ;
  SYMMETRY X Y ;
  PIN I
    DIRECTION INPUT ;
    USE SIGNAL ;
    PORT
      LAYER M1 ;
      RECT 0.05 0.1 0.10 0.2 ;
    END
  END I
  PIN ZN
    DIRECTION OUTPUT ;
    USE SIGNAL ;
    PORT
      LAYER M1 ;
      RECT 0.20 0.1 0.25 0.2 ;
    END
  END ZN
END INVSKPD6
MACRO INVSKPD8
  CLASS CORE ;
  ORIGIN 0.0 0.0 ;
  SIZE 0.45 BY 0.3 ;
  SYMMETRY X Y ;
  PIN I
    DIRECTION INPUT ;
    USE SIGNAL ;
    PORT
      LAYER M1 ;
      RECT 0.05 0.1 0.10 0.2 ;
    END
  END I
  PIN ZN
    DIRECTION OUTPUT ;
    USE SIGNAL ;
    PORT
      LAYER M1 ;
      RECT 0.20 0.1 0.25 0.2 ;
    END
  END ZN
END INVSKPD8
MACRO IOA21D0
  CLASS CORE ;
  ORIGIN 0.0 0.0 ;
  SIZE 0.45 BY 0.3 ;
  SYMMETRY X Y ;
  PIN A1
    DIRECTION INPUT ;
    USE SIGNAL ;
    PORT
      LAYER M1 ;
      RECT 0.05 0.1 0.10 0.2 ;
    END
  END A1
  PIN A2
    DIRECTION INPUT ;
    USE SIGNAL ;
    PORT
      LAYER M1 ;
      RECT 0.12 0.1 0.17 0.2 ;
    END
  END A2
  PIN B
    DIRECTION INPUT ;
    USE SIGNAL ;
    PORT
      LAYER M1 ;
      RECT 0.20 0.1 0.25 0.2 ;
    END
  END B
  PIN ZN
    DIRECTION OUTPUT ;
    USE SIGNAL ;
    PORT
      LAYER M1 ;
      RECT 0.27 0.1 0.32 0.2 ;
    END
  END ZN
END IOA21D0
MACRO IOA21D1
  CLASS CORE ;
  ORIGIN 0.0 0.0 ;
  SIZE 0.45 BY 0.3 ;
  SYMMETRY X Y ;
  PIN A1
    DIRECTION INPUT ;
    USE SIGNAL ;
    PORT
      LAYER M1 ;
      RECT 0.05 0.1 0.10 0.2 ;
    END
  END A1
  PIN A2
    DIRECTION INPUT ;
    USE SIGNAL ;
    PORT
      LAYER M1 ;
      RECT 0.12 0.1 0.17 0.2 ;
    END
  END A2
  PIN B
    DIRECTION INPUT ;
    USE SIGNAL ;
    PORT
      LAYER M1 ;
      RECT 0.20 0.1 0.25 0.2 ;
    END
  END B
  PIN ZN
    DIRECTION OUTPUT ;
    USE SIGNAL ;
    PORT
      LAYER M1 ;
      RECT 0.27 0.1 0.32 0.2 ;
    END
  END ZN
END IOA21D1
MACRO IOA21D2
  CLASS CORE ;
  ORIGIN 0.0 0.0 ;
  SIZE 0.45 BY 0.3 ;
  SYMMETRY X Y ;
  PIN A1
    DIRECTION INPUT ;
    USE SIGNAL ;
    PORT
      LAYER M1 ;
      RECT 0.05 0.1 0.10 0.2 ;
    END
  END A1
  PIN A2
    DIRECTION INPUT ;
    USE SIGNAL ;
    PORT
      LAYER M1 ;
      RECT 0.12 0.1 0.17 0.2 ;
    END
  END A2
  PIN B
    DIRECTION INPUT ;
    USE SIGNAL ;
    PORT
      LAYER M1 ;
      RECT 0.20 0.1 0.25 0.2 ;
    END
  END B
  PIN ZN
    DIRECTION OUTPUT ;
    USE SIGNAL ;
    PORT
      LAYER M1 ;
      RECT 0.27 0.1 0.32 0.2 ;
    END
  END ZN
END IOA21D2
MACRO IOA21D4
  CLASS CORE ;
  ORIGIN 0.0 0.0 ;
  SIZE 0.45 BY 0.3 ;
  SYMMETRY X Y ;
  PIN A1
    DIRECTION INPUT ;
    USE SIGNAL ;
    PORT
      LAYER M1 ;
      RECT 0.05 0.1 0.10 0.2 ;
    END
  END A1
  PIN A2
    DIRECTION INPUT ;
    USE SIGNAL ;
    PORT
      LAYER M1 ;
      RECT 0.12 0.1 0.17 0.2 ;
    END
  END A2
  PIN B
    DIRECTION INPUT ;
    USE SIGNAL ;
    PORT
      LAYER M1 ;
      RECT 0.20 0.1 0.25 0.2 ;
    END
  END B
  PIN ZN
    DIRECTION OUTPUT ;
    USE SIGNAL ;
    PORT
      LAYER M1 ;
      RECT 0.27 0.1 0.32 0.2 ;
    END
  END ZN
END IOA21D4
MACRO IOAI21D0
  CLASS CORE ;
  ORIGIN 0.0 0.0 ;
  SIZE 0.45 BY 0.3 ;
  SYMMETRY X Y ;
  PIN A1
    DIRECTION INPUT ;
    USE SIGNAL ;
    PORT
      LAYER M1 ;
      RECT 0.05 0.1 0.10 0.2 ;
    END
  END A1
  PIN A2
    DIRECTION INPUT ;
    USE SIGNAL ;
    PORT
      LAYER M1 ;
      RECT 0.12 0.1 0.17 0.2 ;
    END
  END A2
  PIN B
    DIRECTION INPUT ;
    USE SIGNAL ;
    PORT
      LAYER M1 ;
      RECT 0.20 0.1 0.25 0.2 ;
    END
  END B
  PIN ZN
    DIRECTION OUTPUT ;
    USE SIGNAL ;
    PORT
      LAYER M1 ;
      RECT 0.27 0.1 0.32 0.2 ;
    END
  END ZN
END IOAI21D0
MACRO IOAI21D1
  CLASS CORE ;
  ORIGIN 0.0 0.0 ;
  SIZE 0.45 BY 0.3 ;
  SYMMETRY X Y ;
  PIN A1
    DIRECTION INPUT ;
    USE SIGNAL ;
    PORT
      LAYER M1 ;
      RECT 0.05 0.1 0.10 0.2 ;
    END
  END A1
  PIN A2
    DIRECTION INPUT ;
    USE SIGNAL ;
    PORT
      LAYER M1 ;
      RECT 0.12 0.1 0.17 0.2 ;
    END
  END A2
  PIN B
    DIRECTION INPUT ;
    USE SIGNAL ;
    PORT
      LAYER M1 ;
      RECT 0.20 0.1 0.25 0.2 ;
    END
  END B
  PIN ZN
    DIRECTION OUTPUT ;
    USE SIGNAL ;
    PORT
      LAYER M1 ;
      RECT 0.27 0.1 0.32 0.2 ;
    END
  END ZN
END IOAI21D1
MACRO IOAI21D2
  CLASS CORE ;
  ORIGIN 0.0 0.0 ;
  SIZE 0.45 BY 0.3 ;
  SYMMETRY X Y ;
  PIN A1
    DIRECTION INPUT ;
    USE SIGNAL ;
    PORT
      LAYER M1 ;
      RECT 0.05 0.1 0.10 0.2 ;
    END
  END A1
  PIN A2
    DIRECTION INPUT ;
    USE SIGNAL ;
    PORT
      LAYER M1 ;
      RECT 0.12 0.1 0.17 0.2 ;
    END
  END A2
  PIN B
    DIRECTION INPUT ;
    USE SIGNAL ;
    PORT
      LAYER M1 ;
      RECT 0.20 0.1 0.25 0.2 ;
    END
  END B
  PIN ZN
    DIRECTION OUTPUT ;
    USE SIGNAL ;
    PORT
      LAYER M1 ;
      RECT 0.27 0.1 0.32 0.2 ;
    END
  END ZN
END IOAI21D2
MACRO IOAI21D4
  CLASS CORE ;
  ORIGIN 0.0 0.0 ;
  SIZE 0.45 BY 0.3 ;
  SYMMETRY X Y ;
  PIN A1
    DIRECTION INPUT ;
    USE SIGNAL ;
    PORT
      LAYER M1 ;
      RECT 0.05 0.1 0.10 0.2 ;
    END
  END A1
  PIN A2
    DIRECTION INPUT ;
    USE SIGNAL ;
    PORT
      LAYER M1 ;
      RECT 0.12 0.1 0.17 0.2 ;
    END
  END A2
  PIN B
    DIRECTION INPUT ;
    USE SIGNAL ;
    PORT
      LAYER M1 ;
      RECT 0.20 0.1 0.25 0.2 ;
    END
  END B
  PIN ZN
    DIRECTION OUTPUT ;
    USE SIGNAL ;
    PORT
      LAYER M1 ;
      RECT 0.27 0.1 0.32 0.2 ;
    END
  END ZN
END IOAI21D4
MACRO IOAI21OPTLD2
  CLASS CORE ;
  ORIGIN 0.0 0.0 ;
  SIZE 0.45 BY 0.3 ;
  SYMMETRY X Y ;
  PIN A1
    DIRECTION INPUT ;
    USE SIGNAL ;
    PORT
      LAYER M1 ;
      RECT 0.05 0.1 0.10 0.2 ;
    END
  END A1
  PIN A2
    DIRECTION INPUT ;
    USE SIGNAL ;
    PORT
      LAYER M1 ;
      RECT 0.12 0.1 0.17 0.2 ;
    END
  END A2
  PIN B
    DIRECTION INPUT ;
    USE SIGNAL ;
    PORT
      LAYER M1 ;
      RECT 0.20 0.1 0.25 0.2 ;
    END
  END B
  PIN ZN
    DIRECTION OUTPUT ;
    USE SIGNAL ;
    PORT
      LAYER M1 ;
      RECT 0.27 0.1 0.32 0.2 ;
    END
  END ZN
END IOAI21OPTLD2
MACRO ISOCLSNKCWD4
  CLASS CORE ;
  ORIGIN 0.0 0.0 ;
  SIZE 0.45 BY 0.3 ;
  SYMMETRY X Y ;
  PIN I
    DIRECTION INPUT ;
    USE SIGNAL ;
    PORT
      LAYER M1 ;
      RECT 0.05 0.1 0.10 0.2 ;
    END
  END I
  PIN ISO
    DIRECTION INPUT ;
    USE SIGNAL ;
    PORT
      LAYER M1 ;
      RECT 0.15 0.1 0.20 0.2 ;
    END
  END ISO
  PIN Z
    DIRECTION OUTPUT ;
    USE SIGNAL ;
    PORT
      LAYER M1 ;
      RECT 0.25 0.1 0.30 0.2 ;
    END
  END Z
END ISOCLSNKCWD4
MACRO MAOI222D2
  CLASS CORE ;
  ORIGIN 0.0 0.0 ;
  SIZE 0.45 BY 0.3 ;
  SYMMETRY X Y ;
  PIN A
    DIRECTION INPUT ;
    USE SIGNAL ;
    PORT
      LAYER M1 ;
      RECT 0.05 0.1 0.10 0.2 ;
    END
  END A
  PIN B
    DIRECTION INPUT ;
    USE SIGNAL ;
    PORT
      LAYER M1 ;
      RECT 0.12 0.1 0.17 0.2 ;
    END
  END B
  PIN C
    DIRECTION INPUT ;
    USE SIGNAL ;
    PORT
      LAYER M1 ;
      RECT 0.20 0.1 0.25 0.2 ;
    END
  END C
  PIN ZN
    DIRECTION OUTPUT ;
    USE SIGNAL ;
    PORT
      LAYER M1 ;
      RECT 0.27 0.1 0.32 0.2 ;
    END
  END ZN
END MAOI222D2
MACRO MAOI222D4
  CLASS CORE ;
  ORIGIN 0.0 0.0 ;
  SIZE 0.45 BY 0.3 ;
  SYMMETRY X Y ;
  PIN A
    DIRECTION INPUT ;
    USE SIGNAL ;
    PORT
      LAYER M1 ;
      RECT 0.05 0.1 0.10 0.2 ;
    END
  END A
  PIN B
    DIRECTION INPUT ;
    USE SIGNAL ;
    PORT
      LAYER M1 ;
      RECT 0.12 0.1 0.17 0.2 ;
    END
  END B
  PIN C
    DIRECTION INPUT ;
    USE SIGNAL ;
    PORT
      LAYER M1 ;
      RECT 0.20 0.1 0.25 0.2 ;
    END
  END C
  PIN ZN
    DIRECTION OUTPUT ;
    USE SIGNAL ;
    PORT
      LAYER M1 ;
      RECT 0.27 0.1 0.32 0.2 ;
    END
  END ZN
END MAOI222D4
MACRO MAOI22D1
  CLASS CORE ;
  ORIGIN 0.0 0.0 ;
  SIZE 0.45 BY 0.3 ;
  SYMMETRY X Y ;
  PIN A1
    DIRECTION INPUT ;
    USE SIGNAL ;
    PORT
      LAYER M1 ;
      RECT 0.05 0.1 0.10 0.2 ;
    END
  END A1
  PIN A2
    DIRECTION INPUT ;
    USE SIGNAL ;
    PORT
      LAYER M1 ;
      RECT 0.11 0.1 0.16 0.2 ;
    END
  END A2
  PIN B1
    DIRECTION INPUT ;
    USE SIGNAL ;
    PORT
      LAYER M1 ;
      RECT 0.17 0.1 0.22 0.2 ;
    END
  END B1
  PIN B2
    DIRECTION INPUT ;
    USE SIGNAL ;
    PORT
      LAYER M1 ;
      RECT 0.23 0.1 0.28 0.2 ;
    END
  END B2
  PIN ZN
    DIRECTION OUTPUT ;
    USE SIGNAL ;
    PORT
      LAYER M1 ;
      RECT 0.29 0.1 0.34 0.2 ;
    END
  END ZN
END MAOI22D1
MACRO MAOI22D2
  CLASS CORE ;
  ORIGIN 0.0 0.0 ;
  SIZE 0.45 BY 0.3 ;
  SYMMETRY X Y ;
  PIN A1
    DIRECTION INPUT ;
    USE SIGNAL ;
    PORT
      LAYER M1 ;
      RECT 0.05 0.1 0.10 0.2 ;
    END
  END A1
  PIN A2
    DIRECTION INPUT ;
    USE SIGNAL ;
    PORT
      LAYER M1 ;
      RECT 0.11 0.1 0.16 0.2 ;
    END
  END A2
  PIN B1
    DIRECTION INPUT ;
    USE SIGNAL ;
    PORT
      LAYER M1 ;
      RECT 0.17 0.1 0.22 0.2 ;
    END
  END B1
  PIN B2
    DIRECTION INPUT ;
    USE SIGNAL ;
    PORT
      LAYER M1 ;
      RECT 0.23 0.1 0.28 0.2 ;
    END
  END B2
  PIN ZN
    DIRECTION OUTPUT ;
    USE SIGNAL ;
    PORT
      LAYER M1 ;
      RECT 0.29 0.1 0.34 0.2 ;
    END
  END ZN
END MAOI22D2
MACRO MAOI22D4
  CLASS CORE ;
  ORIGIN 0.0 0.0 ;
  SIZE 0.45 BY 0.3 ;
  SYMMETRY X Y ;
  PIN A1
    DIRECTION INPUT ;
    USE SIGNAL ;
    PORT
      LAYER M1 ;
      RECT 0.05 0.1 0.10 0.2 ;
    END
  END A1
  PIN A2
    DIRECTION INPUT ;
    USE SIGNAL ;
    PORT
      LAYER M1 ;
      RECT 0.11 0.1 0.16 0.2 ;
    END
  END A2
  PIN B1
    DIRECTION INPUT ;
    USE SIGNAL ;
    PORT
      LAYER M1 ;
      RECT 0.17 0.1 0.22 0.2 ;
    END
  END B1
  PIN B2
    DIRECTION INPUT ;
    USE SIGNAL ;
    PORT
      LAYER M1 ;
      RECT 0.23 0.1 0.28 0.2 ;
    END
  END B2
  PIN ZN
    DIRECTION OUTPUT ;
    USE SIGNAL ;
    PORT
      LAYER M1 ;
      RECT 0.29 0.1 0.34 0.2 ;
    END
  END ZN
END MAOI22D4
MACRO MOAI22D0
  CLASS CORE ;
  ORIGIN 0.0 0.0 ;
  SIZE 0.45 BY 0.3 ;
  SYMMETRY X Y ;
  PIN A1
    DIRECTION INPUT ;
    USE SIGNAL ;
    PORT
      LAYER M1 ;
      RECT 0.05 0.1 0.10 0.2 ;
    END
  END A1
  PIN A2
    DIRECTION INPUT ;
    USE SIGNAL ;
    PORT
      LAYER M1 ;
      RECT 0.11 0.1 0.16 0.2 ;
    END
  END A2
  PIN B1
    DIRECTION INPUT ;
    USE SIGNAL ;
    PORT
      LAYER M1 ;
      RECT 0.17 0.1 0.22 0.2 ;
    END
  END B1
  PIN B2
    DIRECTION INPUT ;
    USE SIGNAL ;
    PORT
      LAYER M1 ;
      RECT 0.23 0.1 0.28 0.2 ;
    END
  END B2
  PIN ZN
    DIRECTION OUTPUT ;
    USE SIGNAL ;
    PORT
      LAYER M1 ;
      RECT 0.29 0.1 0.34 0.2 ;
    END
  END ZN
END MOAI22D0
MACRO MOAI22D2
  CLASS CORE ;
  ORIGIN 0.0 0.0 ;
  SIZE 0.45 BY 0.3 ;
  SYMMETRY X Y ;
  PIN A1
    DIRECTION INPUT ;
    USE SIGNAL ;
    PORT
      LAYER M1 ;
      RECT 0.05 0.1 0.10 0.2 ;
    END
  END A1
  PIN A2
    DIRECTION INPUT ;
    USE SIGNAL ;
    PORT
      LAYER M1 ;
      RECT 0.11 0.1 0.16 0.2 ;
    END
  END A2
  PIN B1
    DIRECTION INPUT ;
    USE SIGNAL ;
    PORT
      LAYER M1 ;
      RECT 0.17 0.1 0.22 0.2 ;
    END
  END B1
  PIN B2
    DIRECTION INPUT ;
    USE SIGNAL ;
    PORT
      LAYER M1 ;
      RECT 0.23 0.1 0.28 0.2 ;
    END
  END B2
  PIN ZN
    DIRECTION OUTPUT ;
    USE SIGNAL ;
    PORT
      LAYER M1 ;
      RECT 0.29 0.1 0.34 0.2 ;
    END
  END ZN
END MOAI22D2
MACRO MOAI22D4
  CLASS CORE ;
  ORIGIN 0.0 0.0 ;
  SIZE 0.45 BY 0.3 ;
  SYMMETRY X Y ;
  PIN A1
    DIRECTION INPUT ;
    USE SIGNAL ;
    PORT
      LAYER M1 ;
      RECT 0.05 0.1 0.10 0.2 ;
    END
  END A1
  PIN A2
    DIRECTION INPUT ;
    USE SIGNAL ;
    PORT
      LAYER M1 ;
      RECT 0.11 0.1 0.16 0.2 ;
    END
  END A2
  PIN B1
    DIRECTION INPUT ;
    USE SIGNAL ;
    PORT
      LAYER M1 ;
      RECT 0.17 0.1 0.22 0.2 ;
    END
  END B1
  PIN B2
    DIRECTION INPUT ;
    USE SIGNAL ;
    PORT
      LAYER M1 ;
      RECT 0.23 0.1 0.28 0.2 ;
    END
  END B2
  PIN ZN
    DIRECTION OUTPUT ;
    USE SIGNAL ;
    PORT
      LAYER M1 ;
      RECT 0.29 0.1 0.34 0.2 ;
    END
  END ZN
END MOAI22D4
MACRO MUX2D0
  CLASS CORE ;
  ORIGIN 0.0 0.0 ;
  SIZE 0.45 BY 0.3 ;
  SYMMETRY X Y ;
  PIN I0
    DIRECTION INPUT ;
    USE SIGNAL ;
    PORT
      LAYER M1 ;
      RECT 0.05 0.1 0.10 0.2 ;
    END
  END I0
  PIN I1
    DIRECTION INPUT ;
    USE SIGNAL ;
    PORT
      LAYER M1 ;
      RECT 0.12 0.1 0.17 0.2 ;
    END
  END I1
  PIN S
    DIRECTION INPUT ;
    USE SIGNAL ;
    PORT
      LAYER M1 ;
      RECT 0.20 0.1 0.25 0.2 ;
    END
  END S
  PIN Z
    DIRECTION OUTPUT ;
    USE SIGNAL ;
    PORT
      LAYER M1 ;
      RECT 0.27 0.1 0.32 0.2 ;
    END
  END Z
END MUX2D0
MACRO MUX2D1
  CLASS CORE ;
  ORIGIN 0.0 0.0 ;
  SIZE 0.45 BY 0.3 ;
  SYMMETRY X Y ;
  PIN I0
    DIRECTION INPUT ;
    USE SIGNAL ;
    PORT
      LAYER M1 ;
      RECT 0.05 0.1 0.10 0.2 ;
    END
  END I0
  PIN I1
    DIRECTION INPUT ;
    USE SIGNAL ;
    PORT
      LAYER M1 ;
      RECT 0.12 0.1 0.17 0.2 ;
    END
  END I1
  PIN S
    DIRECTION INPUT ;
    USE SIGNAL ;
    PORT
      LAYER M1 ;
      RECT 0.20 0.1 0.25 0.2 ;
    END
  END S
  PIN Z
    DIRECTION OUTPUT ;
    USE SIGNAL ;
    PORT
      LAYER M1 ;
      RECT 0.27 0.1 0.32 0.2 ;
    END
  END Z
END MUX2D1
MACRO MUX2D2
  CLASS CORE ;
  ORIGIN 0.0 0.0 ;
  SIZE 0.45 BY 0.3 ;
  SYMMETRY X Y ;
  PIN I0
    DIRECTION INPUT ;
    USE SIGNAL ;
    PORT
      LAYER M1 ;
      RECT 0.05 0.1 0.10 0.2 ;
    END
  END I0
  PIN I1
    DIRECTION INPUT ;
    USE SIGNAL ;
    PORT
      LAYER M1 ;
      RECT 0.12 0.1 0.17 0.2 ;
    END
  END I1
  PIN S
    DIRECTION INPUT ;
    USE SIGNAL ;
    PORT
      LAYER M1 ;
      RECT 0.20 0.1 0.25 0.2 ;
    END
  END S
  PIN Z
    DIRECTION OUTPUT ;
    USE SIGNAL ;
    PORT
      LAYER M1 ;
      RECT 0.27 0.1 0.32 0.2 ;
    END
  END Z
END MUX2D2
MACRO MUX2D3
  CLASS CORE ;
  ORIGIN 0.0 0.0 ;
  SIZE 0.45 BY 0.3 ;
  SYMMETRY X Y ;
  PIN I0
    DIRECTION INPUT ;
    USE SIGNAL ;
    PORT
      LAYER M1 ;
      RECT 0.05 0.1 0.10 0.2 ;
    END
  END I0
  PIN I1
    DIRECTION INPUT ;
    USE SIGNAL ;
    PORT
      LAYER M1 ;
      RECT 0.12 0.1 0.17 0.2 ;
    END
  END I1
  PIN S
    DIRECTION INPUT ;
    USE SIGNAL ;
    PORT
      LAYER M1 ;
      RECT 0.20 0.1 0.25 0.2 ;
    END
  END S
  PIN Z
    DIRECTION OUTPUT ;
    USE SIGNAL ;
    PORT
      LAYER M1 ;
      RECT 0.27 0.1 0.32 0.2 ;
    END
  END Z
END MUX2D3
MACRO MUX2D4
  CLASS CORE ;
  ORIGIN 0.0 0.0 ;
  SIZE 0.45 BY 0.3 ;
  SYMMETRY X Y ;
  PIN I0
    DIRECTION INPUT ;
    USE SIGNAL ;
    PORT
      LAYER M1 ;
      RECT 0.05 0.1 0.10 0.2 ;
    END
  END I0
  PIN I1
    DIRECTION INPUT ;
    USE SIGNAL ;
    PORT
      LAYER M1 ;
      RECT 0.12 0.1 0.17 0.2 ;
    END
  END I1
  PIN S
    DIRECTION OUTPUT ;
    USE SIGNAL ;
    PORT
      LAYER M1 ;
      RECT 0.20 0.1 0.25 0.2 ;
    END
  END S
  PIN Z
    DIRECTION OUTPUT ;
    USE SIGNAL ;
    PORT
      LAYER M1 ;
      RECT 0.27 0.1 0.32 0.2 ;
    END
  END Z
END MUX2D4
MACRO MUX2ND0
  CLASS CORE ;
  ORIGIN 0.0 0.0 ;
  SIZE 0.45 BY 0.3 ;
  SYMMETRY X Y ;
  PIN I0
    DIRECTION INPUT ;
    USE SIGNAL ;
    PORT
      LAYER M1 ;
      RECT 0.05 0.1 0.10 0.2 ;
    END
  END I0
  PIN I1
    DIRECTION INPUT ;
    USE SIGNAL ;
    PORT
      LAYER M1 ;
      RECT 0.12 0.1 0.17 0.2 ;
    END
  END I1
  PIN S
    DIRECTION INPUT ;
    USE SIGNAL ;
    PORT
      LAYER M1 ;
      RECT 0.20 0.1 0.25 0.2 ;
    END
  END S
  PIN ZN
    DIRECTION OUTPUT ;
    USE SIGNAL ;
    PORT
      LAYER M1 ;
      RECT 0.27 0.1 0.32 0.2 ;
    END
  END ZN
END MUX2ND0
MACRO MUX2ND3
  CLASS CORE ;
  ORIGIN 0.0 0.0 ;
  SIZE 0.45 BY 0.3 ;
  SYMMETRY X Y ;
  PIN I0
    DIRECTION INPUT ;
    USE SIGNAL ;
    PORT
      LAYER M1 ;
      RECT 0.05 0.1 0.10 0.2 ;
    END
  END I0
  PIN I1
    DIRECTION INPUT ;
    USE SIGNAL ;
    PORT
      LAYER M1 ;
      RECT 0.12 0.1 0.17 0.2 ;
    END
  END I1
  PIN S
    DIRECTION OUTPUT ;
    USE SIGNAL ;
    PORT
      LAYER M1 ;
      RECT 0.20 0.1 0.25 0.2 ;
    END
  END S
  PIN ZN
    DIRECTION OUTPUT ;
    USE SIGNAL ;
    PORT
      LAYER M1 ;
      RECT 0.27 0.1 0.32 0.2 ;
    END
  END ZN
END MUX2ND3
MACRO MUX2ND4
  CLASS CORE ;
  ORIGIN 0.0 0.0 ;
  SIZE 0.45 BY 0.3 ;
  SYMMETRY X Y ;
  PIN I0
    DIRECTION INPUT ;
    USE SIGNAL ;
    PORT
      LAYER M1 ;
      RECT 0.05 0.1 0.10 0.2 ;
    END
  END I0
  PIN I1
    DIRECTION INPUT ;
    USE SIGNAL ;
    PORT
      LAYER M1 ;
      RECT 0.12 0.1 0.17 0.2 ;
    END
  END I1
  PIN S
    DIRECTION OUTPUT ;
    USE SIGNAL ;
    PORT
      LAYER M1 ;
      RECT 0.20 0.1 0.25 0.2 ;
    END
  END S
  PIN ZN
    DIRECTION OUTPUT ;
    USE SIGNAL ;
    PORT
      LAYER M1 ;
      RECT 0.27 0.1 0.32 0.2 ;
    END
  END ZN
END MUX2ND4
MACRO MUX2ND8
  CLASS CORE ;
  ORIGIN 0.0 0.0 ;
  SIZE 0.45 BY 0.3 ;
  SYMMETRY X Y ;
  PIN I0
    DIRECTION INPUT ;
    USE SIGNAL ;
    PORT
      LAYER M1 ;
      RECT 0.05 0.1 0.10 0.2 ;
    END
  END I0
  PIN I1
    DIRECTION INPUT ;
    USE SIGNAL ;
    PORT
      LAYER M1 ;
      RECT 0.12 0.1 0.17 0.2 ;
    END
  END I1
  PIN S
    DIRECTION OUTPUT ;
    USE SIGNAL ;
    PORT
      LAYER M1 ;
      RECT 0.20 0.1 0.25 0.2 ;
    END
  END S
  PIN ZN
    DIRECTION OUTPUT ;
    USE SIGNAL ;
    PORT
      LAYER M1 ;
      RECT 0.27 0.1 0.32 0.2 ;
    END
  END ZN
END MUX2ND8
MACRO MUX3D0
  CLASS CORE ;
  ORIGIN 0.0 0.0 ;
  SIZE 0.45 BY 0.3 ;
  SYMMETRY X Y ;
  PIN I0
    DIRECTION INPUT ;
    USE SIGNAL ;
    PORT
      LAYER M1 ;
      RECT 0.05 0.1 0.10 0.2 ;
    END
  END I0
  PIN I1
    DIRECTION INPUT ;
    USE SIGNAL ;
    PORT
      LAYER M1 ;
      RECT 0.10 0.1 0.15 0.2 ;
    END
  END I1
  PIN I2
    DIRECTION INPUT ;
    USE SIGNAL ;
    PORT
      LAYER M1 ;
      RECT 0.15 0.1 0.20 0.2 ;
    END
  END I2
  PIN S0
    DIRECTION INPUT ;
    USE SIGNAL ;
    PORT
      LAYER M1 ;
      RECT 0.20 0.1 0.25 0.2 ;
    END
  END S0
  PIN S1
    DIRECTION INPUT ;
    USE SIGNAL ;
    PORT
      LAYER M1 ;
      RECT 0.25 0.1 0.30 0.2 ;
    END
  END S1
  PIN Z
    DIRECTION OUTPUT ;
    USE SIGNAL ;
    PORT
      LAYER M1 ;
      RECT 0.30 0.1 0.35 0.2 ;
    END
  END Z
END MUX3D0
MACRO MUX3OPTLD1
  CLASS CORE ;
  ORIGIN 0.0 0.0 ;
  SIZE 0.45 BY 0.3 ;
  SYMMETRY X Y ;
  PIN I0
    DIRECTION INPUT ;
    USE SIGNAL ;
    PORT
      LAYER M1 ;
      RECT 0.05 0.1 0.10 0.2 ;
    END
  END I0
  PIN I1
    DIRECTION INPUT ;
    USE SIGNAL ;
    PORT
      LAYER M1 ;
      RECT 0.10 0.1 0.15 0.2 ;
    END
  END I1
  PIN I2
    DIRECTION INPUT ;
    USE SIGNAL ;
    PORT
      LAYER M1 ;
      RECT 0.15 0.1 0.20 0.2 ;
    END
  END I2
  PIN S0
    DIRECTION INPUT ;
    USE SIGNAL ;
    PORT
      LAYER M1 ;
      RECT 0.20 0.1 0.25 0.2 ;
    END
  END S0
  PIN S1
    DIRECTION INPUT ;
    USE SIGNAL ;
    PORT
      LAYER M1 ;
      RECT 0.25 0.1 0.30 0.2 ;
    END
  END S1
  PIN Z
    DIRECTION OUTPUT ;
    USE SIGNAL ;
    PORT
      LAYER M1 ;
      RECT 0.30 0.1 0.35 0.2 ;
    END
  END Z
END MUX3OPTLD1
MACRO MUX4D0
  CLASS CORE ;
  ORIGIN 0.0 0.0 ;
  SIZE 0.45 BY 0.3 ;
  SYMMETRY X Y ;
  PIN I0
    DIRECTION INPUT ;
    USE SIGNAL ;
    PORT
      LAYER M1 ;
      RECT 0.05 0.1 0.10 0.2 ;
    END
  END I0
  PIN I1
    DIRECTION INPUT ;
    USE SIGNAL ;
    PORT
      LAYER M1 ;
      RECT 0.09 0.1 0.14 0.2 ;
    END
  END I1
  PIN I2
    DIRECTION INPUT ;
    USE SIGNAL ;
    PORT
      LAYER M1 ;
      RECT 0.14 0.1 0.19 0.2 ;
    END
  END I2
  PIN I3
    DIRECTION INPUT ;
    USE SIGNAL ;
    PORT
      LAYER M1 ;
      RECT 0.18 0.1 0.23 0.2 ;
    END
  END I3
  PIN S0
    DIRECTION INPUT ;
    USE SIGNAL ;
    PORT
      LAYER M1 ;
      RECT 0.22 0.1 0.27 0.2 ;
    END
  END S0
  PIN S1
    DIRECTION INPUT ;
    USE SIGNAL ;
    PORT
      LAYER M1 ;
      RECT 0.26 0.1 0.31 0.2 ;
    END
  END S1
  PIN Z
    DIRECTION OUTPUT ;
    USE SIGNAL ;
    PORT
      LAYER M1 ;
      RECT 0.31 0.1 0.36 0.2 ;
    END
  END Z
END MUX4D0
MACRO MUX4ND0
  CLASS CORE ;
  ORIGIN 0.0 0.0 ;
  SIZE 0.45 BY 0.3 ;
  SYMMETRY X Y ;
  PIN I0
    DIRECTION INPUT ;
    USE SIGNAL ;
    PORT
      LAYER M1 ;
      RECT 0.05 0.1 0.10 0.2 ;
    END
  END I0
  PIN I1
    DIRECTION INPUT ;
    USE SIGNAL ;
    PORT
      LAYER M1 ;
      RECT 0.09 0.1 0.14 0.2 ;
    END
  END I1
  PIN I2
    DIRECTION INPUT ;
    USE SIGNAL ;
    PORT
      LAYER M1 ;
      RECT 0.14 0.1 0.19 0.2 ;
    END
  END I2
  PIN I3
    DIRECTION INPUT ;
    USE SIGNAL ;
    PORT
      LAYER M1 ;
      RECT 0.18 0.1 0.23 0.2 ;
    END
  END I3
  PIN S0
    DIRECTION INPUT ;
    USE SIGNAL ;
    PORT
      LAYER M1 ;
      RECT 0.22 0.1 0.27 0.2 ;
    END
  END S0
  PIN S1
    DIRECTION INPUT ;
    USE SIGNAL ;
    PORT
      LAYER M1 ;
      RECT 0.26 0.1 0.31 0.2 ;
    END
  END S1
  PIN ZN
    DIRECTION OUTPUT ;
    USE SIGNAL ;
    PORT
      LAYER M1 ;
      RECT 0.31 0.1 0.36 0.2 ;
    END
  END ZN
END MUX4ND0
MACRO ND2D1
  CLASS CORE ;
  ORIGIN 0.0 0.0 ;
  SIZE 0.45 BY 0.3 ;
  SYMMETRY X Y ;
  PIN A1
    DIRECTION INPUT ;
    USE SIGNAL ;
    PORT
      LAYER M1 ;
      RECT 0.05 0.1 0.10 0.2 ;
    END
  END A1
  PIN A2
    DIRECTION INPUT ;
    USE SIGNAL ;
    PORT
      LAYER M1 ;
      RECT 0.15 0.1 0.20 0.2 ;
    END
  END A2
  PIN ZN
    DIRECTION OUTPUT ;
    USE SIGNAL ;
    PORT
      LAYER M1 ;
      RECT 0.25 0.1 0.30 0.2 ;
    END
  END ZN
END ND2D1
MACRO ND2OPTPAD1
  CLASS CORE ;
  ORIGIN 0.0 0.0 ;
  SIZE 0.45 BY 0.3 ;
  SYMMETRY X Y ;
  PIN A1
    DIRECTION INPUT ;
    USE SIGNAL ;
    PORT
      LAYER M1 ;
      RECT 0.05 0.1 0.10 0.2 ;
    END
  END A1
  PIN A2
    DIRECTION INPUT ;
    USE SIGNAL ;
    PORT
      LAYER M1 ;
      RECT 0.15 0.1 0.20 0.2 ;
    END
  END A2
  PIN ZN
    DIRECTION OUTPUT ;
    USE SIGNAL ;
    PORT
      LAYER M1 ;
      RECT 0.25 0.1 0.30 0.2 ;
    END
  END ZN
END ND2OPTPAD1
MACRO ND2OPTPAD2
  CLASS CORE ;
  ORIGIN 0.0 0.0 ;
  SIZE 0.45 BY 0.3 ;
  SYMMETRY X Y ;
  PIN A1
    DIRECTION INPUT ;
    USE SIGNAL ;
    PORT
      LAYER M1 ;
      RECT 0.05 0.1 0.10 0.2 ;
    END
  END A1
  PIN A2
    DIRECTION INPUT ;
    USE SIGNAL ;
    PORT
      LAYER M1 ;
      RECT 0.15 0.1 0.20 0.2 ;
    END
  END A2
  PIN ZN
    DIRECTION OUTPUT ;
    USE SIGNAL ;
    PORT
      LAYER M1 ;
      RECT 0.25 0.1 0.30 0.2 ;
    END
  END ZN
END ND2OPTPAD2
MACRO ND2SKND10
  CLASS CORE ;
  ORIGIN 0.0 0.0 ;
  SIZE 0.45 BY 0.3 ;
  SYMMETRY X Y ;
  PIN A1
    DIRECTION INPUT ;
    USE SIGNAL ;
    PORT
      LAYER M1 ;
      RECT 0.05 0.1 0.10 0.2 ;
    END
  END A1
  PIN A2
    DIRECTION INPUT ;
    USE SIGNAL ;
    PORT
      LAYER M1 ;
      RECT 0.15 0.1 0.20 0.2 ;
    END
  END A2
  PIN ZN
    DIRECTION OUTPUT ;
    USE SIGNAL ;
    PORT
      LAYER M1 ;
      RECT 0.25 0.1 0.30 0.2 ;
    END
  END ZN
END ND2SKND10
MACRO ND2SKND16
  CLASS CORE ;
  ORIGIN 0.0 0.0 ;
  SIZE 0.45 BY 0.3 ;
  SYMMETRY X Y ;
  PIN A1
    DIRECTION INPUT ;
    USE SIGNAL ;
    PORT
      LAYER M1 ;
      RECT 0.05 0.1 0.10 0.2 ;
    END
  END A1
  PIN A2
    DIRECTION INPUT ;
    USE SIGNAL ;
    PORT
      LAYER M1 ;
      RECT 0.15 0.1 0.20 0.2 ;
    END
  END A2
  PIN ZN
    DIRECTION OUTPUT ;
    USE SIGNAL ;
    PORT
      LAYER M1 ;
      RECT 0.25 0.1 0.30 0.2 ;
    END
  END ZN
END ND2SKND16
MACRO ND2SKND2
  CLASS CORE ;
  ORIGIN 0.0 0.0 ;
  SIZE 0.45 BY 0.3 ;
  SYMMETRY X Y ;
  PIN A1
    DIRECTION INPUT ;
    USE SIGNAL ;
    PORT
      LAYER M1 ;
      RECT 0.05 0.1 0.10 0.2 ;
    END
  END A1
  PIN A2
    DIRECTION INPUT ;
    USE SIGNAL ;
    PORT
      LAYER M1 ;
      RECT 0.15 0.1 0.20 0.2 ;
    END
  END A2
  PIN ZN
    DIRECTION OUTPUT ;
    USE SIGNAL ;
    PORT
      LAYER M1 ;
      RECT 0.25 0.1 0.30 0.2 ;
    END
  END ZN
END ND2SKND2
MACRO ND2SKND3
  CLASS CORE ;
  ORIGIN 0.0 0.0 ;
  SIZE 0.45 BY 0.3 ;
  SYMMETRY X Y ;
  PIN A1
    DIRECTION INPUT ;
    USE SIGNAL ;
    PORT
      LAYER M1 ;
      RECT 0.05 0.1 0.10 0.2 ;
    END
  END A1
  PIN A2
    DIRECTION INPUT ;
    USE SIGNAL ;
    PORT
      LAYER M1 ;
      RECT 0.15 0.1 0.20 0.2 ;
    END
  END A2
  PIN ZN
    DIRECTION OUTPUT ;
    USE SIGNAL ;
    PORT
      LAYER M1 ;
      RECT 0.25 0.1 0.30 0.2 ;
    END
  END ZN
END ND2SKND3
MACRO ND2SKND4
  CLASS CORE ;
  ORIGIN 0.0 0.0 ;
  SIZE 0.45 BY 0.3 ;
  SYMMETRY X Y ;
  PIN A1
    DIRECTION INPUT ;
    USE SIGNAL ;
    PORT
      LAYER M1 ;
      RECT 0.05 0.1 0.10 0.2 ;
    END
  END A1
  PIN A2
    DIRECTION INPUT ;
    USE SIGNAL ;
    PORT
      LAYER M1 ;
      RECT 0.15 0.1 0.20 0.2 ;
    END
  END A2
  PIN ZN
    DIRECTION OUTPUT ;
    USE SIGNAL ;
    PORT
      LAYER M1 ;
      RECT 0.25 0.1 0.30 0.2 ;
    END
  END ZN
END ND2SKND4
MACRO ND2SKND6
  CLASS CORE ;
  ORIGIN 0.0 0.0 ;
  SIZE 0.45 BY 0.3 ;
  SYMMETRY X Y ;
  PIN A1
    DIRECTION INPUT ;
    USE SIGNAL ;
    PORT
      LAYER M1 ;
      RECT 0.05 0.1 0.10 0.2 ;
    END
  END A1
  PIN A2
    DIRECTION INPUT ;
    USE SIGNAL ;
    PORT
      LAYER M1 ;
      RECT 0.15 0.1 0.20 0.2 ;
    END
  END A2
  PIN ZN
    DIRECTION OUTPUT ;
    USE SIGNAL ;
    PORT
      LAYER M1 ;
      RECT 0.25 0.1 0.30 0.2 ;
    END
  END ZN
END ND2SKND6
MACRO ND2SKND8
  CLASS CORE ;
  ORIGIN 0.0 0.0 ;
  SIZE 0.45 BY 0.3 ;
  SYMMETRY X Y ;
  PIN A1
    DIRECTION INPUT ;
    USE SIGNAL ;
    PORT
      LAYER M1 ;
      RECT 0.05 0.1 0.10 0.2 ;
    END
  END A1
  PIN A2
    DIRECTION INPUT ;
    USE SIGNAL ;
    PORT
      LAYER M1 ;
      RECT 0.15 0.1 0.20 0.2 ;
    END
  END A2
  PIN ZN
    DIRECTION OUTPUT ;
    USE SIGNAL ;
    PORT
      LAYER M1 ;
      RECT 0.25 0.1 0.30 0.2 ;
    END
  END ZN
END ND2SKND8
MACRO ND3OPTPAD1
  CLASS CORE ;
  ORIGIN 0.0 0.0 ;
  SIZE 0.45 BY 0.3 ;
  SYMMETRY X Y ;
  PIN A1
    DIRECTION INPUT ;
    USE SIGNAL ;
    PORT
      LAYER M1 ;
      RECT 0.05 0.1 0.10 0.2 ;
    END
  END A1
  PIN A2
    DIRECTION INPUT ;
    USE SIGNAL ;
    PORT
      LAYER M1 ;
      RECT 0.12 0.1 0.17 0.2 ;
    END
  END A2
  PIN A3
    DIRECTION INPUT ;
    USE SIGNAL ;
    PORT
      LAYER M1 ;
      RECT 0.20 0.1 0.25 0.2 ;
    END
  END A3
  PIN ZN
    DIRECTION OUTPUT ;
    USE SIGNAL ;
    PORT
      LAYER M1 ;
      RECT 0.27 0.1 0.32 0.2 ;
    END
  END ZN
END ND3OPTPAD1
MACRO ND3OPTPAD2
  CLASS CORE ;
  ORIGIN 0.0 0.0 ;
  SIZE 0.45 BY 0.3 ;
  SYMMETRY X Y ;
  PIN A1
    DIRECTION INPUT ;
    USE SIGNAL ;
    PORT
      LAYER M1 ;
      RECT 0.05 0.1 0.10 0.2 ;
    END
  END A1
  PIN A2
    DIRECTION INPUT ;
    USE SIGNAL ;
    PORT
      LAYER M1 ;
      RECT 0.12 0.1 0.17 0.2 ;
    END
  END A2
  PIN A3
    DIRECTION INPUT ;
    USE SIGNAL ;
    PORT
      LAYER M1 ;
      RECT 0.20 0.1 0.25 0.2 ;
    END
  END A3
  PIN ZN
    DIRECTION OUTPUT ;
    USE SIGNAL ;
    PORT
      LAYER M1 ;
      RECT 0.27 0.1 0.32 0.2 ;
    END
  END ZN
END ND3OPTPAD2
MACRO ND3SKND12
  CLASS CORE ;
  ORIGIN 0.0 0.0 ;
  SIZE 0.45 BY 0.3 ;
  SYMMETRY X Y ;
  PIN A1
    DIRECTION INPUT ;
    USE SIGNAL ;
    PORT
      LAYER M1 ;
      RECT 0.05 0.1 0.10 0.2 ;
    END
  END A1
  PIN A2
    DIRECTION INPUT ;
    USE SIGNAL ;
    PORT
      LAYER M1 ;
      RECT 0.12 0.1 0.17 0.2 ;
    END
  END A2
  PIN A3
    DIRECTION INPUT ;
    USE SIGNAL ;
    PORT
      LAYER M1 ;
      RECT 0.20 0.1 0.25 0.2 ;
    END
  END A3
  PIN ZN
    DIRECTION OUTPUT ;
    USE SIGNAL ;
    PORT
      LAYER M1 ;
      RECT 0.27 0.1 0.32 0.2 ;
    END
  END ZN
END ND3SKND12
MACRO ND3SKND1
  CLASS CORE ;
  ORIGIN 0.0 0.0 ;
  SIZE 0.45 BY 0.3 ;
  SYMMETRY X Y ;
  PIN A1
    DIRECTION INPUT ;
    USE SIGNAL ;
    PORT
      LAYER M1 ;
      RECT 0.05 0.1 0.10 0.2 ;
    END
  END A1
  PIN A2
    DIRECTION INPUT ;
    USE SIGNAL ;
    PORT
      LAYER M1 ;
      RECT 0.12 0.1 0.17 0.2 ;
    END
  END A2
  PIN A3
    DIRECTION INPUT ;
    USE SIGNAL ;
    PORT
      LAYER M1 ;
      RECT 0.20 0.1 0.25 0.2 ;
    END
  END A3
  PIN ZN
    DIRECTION OUTPUT ;
    USE SIGNAL ;
    PORT
      LAYER M1 ;
      RECT 0.27 0.1 0.32 0.2 ;
    END
  END ZN
END ND3SKND1
MACRO ND3SKND2
  CLASS CORE ;
  ORIGIN 0.0 0.0 ;
  SIZE 0.45 BY 0.3 ;
  SYMMETRY X Y ;
  PIN A1
    DIRECTION INPUT ;
    USE SIGNAL ;
    PORT
      LAYER M1 ;
      RECT 0.05 0.1 0.10 0.2 ;
    END
  END A1
  PIN A2
    DIRECTION INPUT ;
    USE SIGNAL ;
    PORT
      LAYER M1 ;
      RECT 0.12 0.1 0.17 0.2 ;
    END
  END A2
  PIN A3
    DIRECTION INPUT ;
    USE SIGNAL ;
    PORT
      LAYER M1 ;
      RECT 0.20 0.1 0.25 0.2 ;
    END
  END A3
  PIN ZN
    DIRECTION OUTPUT ;
    USE SIGNAL ;
    PORT
      LAYER M1 ;
      RECT 0.27 0.1 0.32 0.2 ;
    END
  END ZN
END ND3SKND2
MACRO ND3SKND3
  CLASS CORE ;
  ORIGIN 0.0 0.0 ;
  SIZE 0.45 BY 0.3 ;
  SYMMETRY X Y ;
  PIN A1
    DIRECTION INPUT ;
    USE SIGNAL ;
    PORT
      LAYER M1 ;
      RECT 0.05 0.1 0.10 0.2 ;
    END
  END A1
  PIN A2
    DIRECTION INPUT ;
    USE SIGNAL ;
    PORT
      LAYER M1 ;
      RECT 0.12 0.1 0.17 0.2 ;
    END
  END A2
  PIN A3
    DIRECTION INPUT ;
    USE SIGNAL ;
    PORT
      LAYER M1 ;
      RECT 0.20 0.1 0.25 0.2 ;
    END
  END A3
  PIN ZN
    DIRECTION OUTPUT ;
    USE SIGNAL ;
    PORT
      LAYER M1 ;
      RECT 0.27 0.1 0.32 0.2 ;
    END
  END ZN
END ND3SKND3
MACRO ND3SKND4
  CLASS CORE ;
  ORIGIN 0.0 0.0 ;
  SIZE 0.45 BY 0.3 ;
  SYMMETRY X Y ;
  PIN A1
    DIRECTION INPUT ;
    USE SIGNAL ;
    PORT
      LAYER M1 ;
      RECT 0.05 0.1 0.10 0.2 ;
    END
  END A1
  PIN A2
    DIRECTION INPUT ;
    USE SIGNAL ;
    PORT
      LAYER M1 ;
      RECT 0.12 0.1 0.17 0.2 ;
    END
  END A2
  PIN A3
    DIRECTION INPUT ;
    USE SIGNAL ;
    PORT
      LAYER M1 ;
      RECT 0.20 0.1 0.25 0.2 ;
    END
  END A3
  PIN ZN
    DIRECTION OUTPUT ;
    USE SIGNAL ;
    PORT
      LAYER M1 ;
      RECT 0.27 0.1 0.32 0.2 ;
    END
  END ZN
END ND3SKND4
MACRO ND3SKND6
  CLASS CORE ;
  ORIGIN 0.0 0.0 ;
  SIZE 0.45 BY 0.3 ;
  SYMMETRY X Y ;
  PIN A1
    DIRECTION INPUT ;
    USE SIGNAL ;
    PORT
      LAYER M1 ;
      RECT 0.05 0.1 0.10 0.2 ;
    END
  END A1
  PIN A2
    DIRECTION INPUT ;
    USE SIGNAL ;
    PORT
      LAYER M1 ;
      RECT 0.12 0.1 0.17 0.2 ;
    END
  END A2
  PIN A3
    DIRECTION INPUT ;
    USE SIGNAL ;
    PORT
      LAYER M1 ;
      RECT 0.20 0.1 0.25 0.2 ;
    END
  END A3
  PIN ZN
    DIRECTION OUTPUT ;
    USE SIGNAL ;
    PORT
      LAYER M1 ;
      RECT 0.27 0.1 0.32 0.2 ;
    END
  END ZN
END ND3SKND6
MACRO ND3SKND8
  CLASS CORE ;
  ORIGIN 0.0 0.0 ;
  SIZE 0.45 BY 0.3 ;
  SYMMETRY X Y ;
  PIN A1
    DIRECTION INPUT ;
    USE SIGNAL ;
    PORT
      LAYER M1 ;
      RECT 0.05 0.1 0.10 0.2 ;
    END
  END A1
  PIN A2
    DIRECTION INPUT ;
    USE SIGNAL ;
    PORT
      LAYER M1 ;
      RECT 0.12 0.1 0.17 0.2 ;
    END
  END A2
  PIN A3
    DIRECTION INPUT ;
    USE SIGNAL ;
    PORT
      LAYER M1 ;
      RECT 0.20 0.1 0.25 0.2 ;
    END
  END A3
  PIN ZN
    DIRECTION OUTPUT ;
    USE SIGNAL ;
    PORT
      LAYER M1 ;
      RECT 0.27 0.1 0.32 0.2 ;
    END
  END ZN
END ND3SKND8
MACRO ND4SKND1
  CLASS CORE ;
  ORIGIN 0.0 0.0 ;
  SIZE 0.45 BY 0.3 ;
  SYMMETRY X Y ;
  PIN A1
    DIRECTION INPUT ;
    USE SIGNAL ;
    PORT
      LAYER M1 ;
      RECT 0.05 0.1 0.10 0.2 ;
    END
  END A1
  PIN A2
    DIRECTION INPUT ;
    USE SIGNAL ;
    PORT
      LAYER M1 ;
      RECT 0.11 0.1 0.16 0.2 ;
    END
  END A2
  PIN A3
    DIRECTION INPUT ;
    USE SIGNAL ;
    PORT
      LAYER M1 ;
      RECT 0.17 0.1 0.22 0.2 ;
    END
  END A3
  PIN A4
    DIRECTION INPUT ;
    USE SIGNAL ;
    PORT
      LAYER M1 ;
      RECT 0.23 0.1 0.28 0.2 ;
    END
  END A4
  PIN ZN
    DIRECTION OUTPUT ;
    USE SIGNAL ;
    PORT
      LAYER M1 ;
      RECT 0.29 0.1 0.34 0.2 ;
    END
  END ZN
END ND4SKND1
MACRO ND4SKND2
  CLASS CORE ;
  ORIGIN 0.0 0.0 ;
  SIZE 0.45 BY 0.3 ;
  SYMMETRY X Y ;
  PIN A1
    DIRECTION INPUT ;
    USE SIGNAL ;
    PORT
      LAYER M1 ;
      RECT 0.05 0.1 0.10 0.2 ;
    END
  END A1
  PIN A2
    DIRECTION INPUT ;
    USE SIGNAL ;
    PORT
      LAYER M1 ;
      RECT 0.11 0.1 0.16 0.2 ;
    END
  END A2
  PIN A3
    DIRECTION INPUT ;
    USE SIGNAL ;
    PORT
      LAYER M1 ;
      RECT 0.17 0.1 0.22 0.2 ;
    END
  END A3
  PIN A4
    DIRECTION INPUT ;
    USE SIGNAL ;
    PORT
      LAYER M1 ;
      RECT 0.23 0.1 0.28 0.2 ;
    END
  END A4
  PIN ZN
    DIRECTION OUTPUT ;
    USE SIGNAL ;
    PORT
      LAYER M1 ;
      RECT 0.29 0.1 0.34 0.2 ;
    END
  END ZN
END ND4SKND2
MACRO ND4SKND3
  CLASS CORE ;
  ORIGIN 0.0 0.0 ;
  SIZE 0.45 BY 0.3 ;
  SYMMETRY X Y ;
  PIN A1
    DIRECTION INPUT ;
    USE SIGNAL ;
    PORT
      LAYER M1 ;
      RECT 0.05 0.1 0.10 0.2 ;
    END
  END A1
  PIN A2
    DIRECTION INPUT ;
    USE SIGNAL ;
    PORT
      LAYER M1 ;
      RECT 0.11 0.1 0.16 0.2 ;
    END
  END A2
  PIN A3
    DIRECTION INPUT ;
    USE SIGNAL ;
    PORT
      LAYER M1 ;
      RECT 0.17 0.1 0.22 0.2 ;
    END
  END A3
  PIN A4
    DIRECTION INPUT ;
    USE SIGNAL ;
    PORT
      LAYER M1 ;
      RECT 0.23 0.1 0.28 0.2 ;
    END
  END A4
  PIN ZN
    DIRECTION OUTPUT ;
    USE SIGNAL ;
    PORT
      LAYER M1 ;
      RECT 0.29 0.1 0.34 0.2 ;
    END
  END ZN
END ND4SKND3
MACRO ND4SKNNMED4
  CLASS CORE ;
  ORIGIN 0.0 0.0 ;
  SIZE 0.45 BY 0.3 ;
  SYMMETRY X Y ;
  PIN A1
    DIRECTION INPUT ;
    USE SIGNAL ;
    PORT
      LAYER M1 ;
      RECT 0.05 0.1 0.10 0.2 ;
    END
  END A1
  PIN A2
    DIRECTION INPUT ;
    USE SIGNAL ;
    PORT
      LAYER M1 ;
      RECT 0.11 0.1 0.16 0.2 ;
    END
  END A2
  PIN A3
    DIRECTION INPUT ;
    USE SIGNAL ;
    PORT
      LAYER M1 ;
      RECT 0.17 0.1 0.22 0.2 ;
    END
  END A3
  PIN A4
    DIRECTION INPUT ;
    USE SIGNAL ;
    PORT
      LAYER M1 ;
      RECT 0.23 0.1 0.28 0.2 ;
    END
  END A4
  PIN ZN
    DIRECTION OUTPUT ;
    USE SIGNAL ;
    PORT
      LAYER M1 ;
      RECT 0.29 0.1 0.34 0.2 ;
    END
  END ZN
END ND4SKNNMED4
MACRO ND4SKNNMED6
  CLASS CORE ;
  ORIGIN 0.0 0.0 ;
  SIZE 0.45 BY 0.3 ;
  SYMMETRY X Y ;
  PIN A1
    DIRECTION INPUT ;
    USE SIGNAL ;
    PORT
      LAYER M1 ;
      RECT 0.05 0.1 0.10 0.2 ;
    END
  END A1
  PIN A2
    DIRECTION INPUT ;
    USE SIGNAL ;
    PORT
      LAYER M1 ;
      RECT 0.11 0.1 0.16 0.2 ;
    END
  END A2
  PIN A3
    DIRECTION INPUT ;
    USE SIGNAL ;
    PORT
      LAYER M1 ;
      RECT 0.17 0.1 0.22 0.2 ;
    END
  END A3
  PIN A4
    DIRECTION INPUT ;
    USE SIGNAL ;
    PORT
      LAYER M1 ;
      RECT 0.23 0.1 0.28 0.2 ;
    END
  END A4
  PIN ZN
    DIRECTION OUTPUT ;
    USE SIGNAL ;
    PORT
      LAYER M1 ;
      RECT 0.29 0.1 0.34 0.2 ;
    END
  END ZN
END ND4SKNNMED6
MACRO ND4SKNNMED8
  CLASS CORE ;
  ORIGIN 0.0 0.0 ;
  SIZE 0.45 BY 0.3 ;
  SYMMETRY X Y ;
  PIN A1
    DIRECTION INPUT ;
    USE SIGNAL ;
    PORT
      LAYER M1 ;
      RECT 0.05 0.1 0.10 0.2 ;
    END
  END A1
  PIN A2
    DIRECTION INPUT ;
    USE SIGNAL ;
    PORT
      LAYER M1 ;
      RECT 0.11 0.1 0.16 0.2 ;
    END
  END A2
  PIN A3
    DIRECTION INPUT ;
    USE SIGNAL ;
    PORT
      LAYER M1 ;
      RECT 0.17 0.1 0.22 0.2 ;
    END
  END A3
  PIN A4
    DIRECTION INPUT ;
    USE SIGNAL ;
    PORT
      LAYER M1 ;
      RECT 0.23 0.1 0.28 0.2 ;
    END
  END A4
  PIN ZN
    DIRECTION OUTPUT ;
    USE SIGNAL ;
    PORT
      LAYER M1 ;
      RECT 0.29 0.1 0.34 0.2 ;
    END
  END ZN
END ND4SKNNMED8
MACRO NR2D1
  CLASS CORE ;
  ORIGIN 0.0 0.0 ;
  SIZE 0.45 BY 0.3 ;
  SYMMETRY X Y ;
  PIN A1
    DIRECTION INPUT ;
    USE SIGNAL ;
    PORT
      LAYER M1 ;
      RECT 0.05 0.1 0.10 0.2 ;
    END
  END A1
  PIN A2
    DIRECTION INPUT ;
    USE SIGNAL ;
    PORT
      LAYER M1 ;
      RECT 0.15 0.1 0.20 0.2 ;
    END
  END A2
  PIN ZN
    DIRECTION OUTPUT ;
    USE SIGNAL ;
    PORT
      LAYER M1 ;
      RECT 0.25 0.1 0.30 0.2 ;
    END
  END ZN
END NR2D1
MACRO NR2OPTPAD12
  CLASS CORE ;
  ORIGIN 0.0 0.0 ;
  SIZE 0.45 BY 0.3 ;
  SYMMETRY X Y ;
  PIN A1
    DIRECTION INPUT ;
    USE SIGNAL ;
    PORT
      LAYER M1 ;
      RECT 0.05 0.1 0.10 0.2 ;
    END
  END A1
  PIN A2
    DIRECTION INPUT ;
    USE SIGNAL ;
    PORT
      LAYER M1 ;
      RECT 0.15 0.1 0.20 0.2 ;
    END
  END A2
  PIN ZN
    DIRECTION OUTPUT ;
    USE SIGNAL ;
    PORT
      LAYER M1 ;
      RECT 0.25 0.1 0.30 0.2 ;
    END
  END ZN
END NR2OPTPAD12
MACRO NR2OPTPAD16
  CLASS CORE ;
  ORIGIN 0.0 0.0 ;
  SIZE 0.45 BY 0.3 ;
  SYMMETRY X Y ;
  PIN A1
    DIRECTION INPUT ;
    USE SIGNAL ;
    PORT
      LAYER M1 ;
      RECT 0.05 0.1 0.10 0.2 ;
    END
  END A1
  PIN A2
    DIRECTION INPUT ;
    USE SIGNAL ;
    PORT
      LAYER M1 ;
      RECT 0.15 0.1 0.20 0.2 ;
    END
  END A2
  PIN ZN
    DIRECTION OUTPUT ;
    USE SIGNAL ;
    PORT
      LAYER M1 ;
      RECT 0.25 0.1 0.30 0.2 ;
    END
  END ZN
END NR2OPTPAD16
MACRO NR2OPTPAD4
  CLASS CORE ;
  ORIGIN 0.0 0.0 ;
  SIZE 0.45 BY 0.3 ;
  SYMMETRY X Y ;
  PIN A1
    DIRECTION INPUT ;
    USE SIGNAL ;
    PORT
      LAYER M1 ;
      RECT 0.05 0.1 0.10 0.2 ;
    END
  END A1
  PIN A2
    DIRECTION INPUT ;
    USE SIGNAL ;
    PORT
      LAYER M1 ;
      RECT 0.15 0.1 0.20 0.2 ;
    END
  END A2
  PIN ZN
    DIRECTION OUTPUT ;
    USE SIGNAL ;
    PORT
      LAYER M1 ;
      RECT 0.25 0.1 0.30 0.2 ;
    END
  END ZN
END NR2OPTPAD4
MACRO NR2SKPD10
  CLASS CORE ;
  ORIGIN 0.0 0.0 ;
  SIZE 0.45 BY 0.3 ;
  SYMMETRY X Y ;
  PIN A1
    DIRECTION INPUT ;
    USE SIGNAL ;
    PORT
      LAYER M1 ;
      RECT 0.05 0.1 0.10 0.2 ;
    END
  END A1
  PIN A2
    DIRECTION INPUT ;
    USE SIGNAL ;
    PORT
      LAYER M1 ;
      RECT 0.15 0.1 0.20 0.2 ;
    END
  END A2
  PIN ZN
    DIRECTION OUTPUT ;
    USE SIGNAL ;
    PORT
      LAYER M1 ;
      RECT 0.25 0.1 0.30 0.2 ;
    END
  END ZN
END NR2SKPD10
MACRO NR2SKPD2
  CLASS CORE ;
  ORIGIN 0.0 0.0 ;
  SIZE 0.45 BY 0.3 ;
  SYMMETRY X Y ;
  PIN A1
    DIRECTION INPUT ;
    USE SIGNAL ;
    PORT
      LAYER M1 ;
      RECT 0.05 0.1 0.10 0.2 ;
    END
  END A1
  PIN A2
    DIRECTION INPUT ;
    USE SIGNAL ;
    PORT
      LAYER M1 ;
      RECT 0.15 0.1 0.20 0.2 ;
    END
  END A2
  PIN ZN
    DIRECTION OUTPUT ;
    USE SIGNAL ;
    PORT
      LAYER M1 ;
      RECT 0.25 0.1 0.30 0.2 ;
    END
  END ZN
END NR2SKPD2
MACRO NR2SKPD3
  CLASS CORE ;
  ORIGIN 0.0 0.0 ;
  SIZE 0.45 BY 0.3 ;
  SYMMETRY X Y ;
  PIN A1
    DIRECTION INPUT ;
    USE SIGNAL ;
    PORT
      LAYER M1 ;
      RECT 0.05 0.1 0.10 0.2 ;
    END
  END A1
  PIN A2
    DIRECTION INPUT ;
    USE SIGNAL ;
    PORT
      LAYER M1 ;
      RECT 0.15 0.1 0.20 0.2 ;
    END
  END A2
  PIN ZN
    DIRECTION OUTPUT ;
    USE SIGNAL ;
    PORT
      LAYER M1 ;
      RECT 0.25 0.1 0.30 0.2 ;
    END
  END ZN
END NR2SKPD3
MACRO NR2SKPD4
  CLASS CORE ;
  ORIGIN 0.0 0.0 ;
  SIZE 0.45 BY 0.3 ;
  SYMMETRY X Y ;
  PIN A1
    DIRECTION INPUT ;
    USE SIGNAL ;
    PORT
      LAYER M1 ;
      RECT 0.05 0.1 0.10 0.2 ;
    END
  END A1
  PIN A2
    DIRECTION INPUT ;
    USE SIGNAL ;
    PORT
      LAYER M1 ;
      RECT 0.15 0.1 0.20 0.2 ;
    END
  END A2
  PIN ZN
    DIRECTION OUTPUT ;
    USE SIGNAL ;
    PORT
      LAYER M1 ;
      RECT 0.25 0.1 0.30 0.2 ;
    END
  END ZN
END NR2SKPD4
MACRO NR2SKPD6
  CLASS CORE ;
  ORIGIN 0.0 0.0 ;
  SIZE 0.45 BY 0.3 ;
  SYMMETRY X Y ;
  PIN A1
    DIRECTION INPUT ;
    USE SIGNAL ;
    PORT
      LAYER M1 ;
      RECT 0.05 0.1 0.10 0.2 ;
    END
  END A1
  PIN A2
    DIRECTION INPUT ;
    USE SIGNAL ;
    PORT
      LAYER M1 ;
      RECT 0.15 0.1 0.20 0.2 ;
    END
  END A2
  PIN ZN
    DIRECTION OUTPUT ;
    USE SIGNAL ;
    PORT
      LAYER M1 ;
      RECT 0.25 0.1 0.30 0.2 ;
    END
  END ZN
END NR2SKPD6
MACRO NR2SKPD8
  CLASS CORE ;
  ORIGIN 0.0 0.0 ;
  SIZE 0.45 BY 0.3 ;
  SYMMETRY X Y ;
  PIN A1
    DIRECTION INPUT ;
    USE SIGNAL ;
    PORT
      LAYER M1 ;
      RECT 0.05 0.1 0.10 0.2 ;
    END
  END A1
  PIN A2
    DIRECTION INPUT ;
    USE SIGNAL ;
    PORT
      LAYER M1 ;
      RECT 0.15 0.1 0.20 0.2 ;
    END
  END A2
  PIN ZN
    DIRECTION OUTPUT ;
    USE SIGNAL ;
    PORT
      LAYER M1 ;
      RECT 0.25 0.1 0.30 0.2 ;
    END
  END ZN
END NR2SKPD8
MACRO NR3OPTPAD12
  CLASS CORE ;
  ORIGIN 0.0 0.0 ;
  SIZE 0.45 BY 0.3 ;
  SYMMETRY X Y ;
  PIN A1
    DIRECTION INPUT ;
    USE SIGNAL ;
    PORT
      LAYER M1 ;
      RECT 0.05 0.1 0.10 0.2 ;
    END
  END A1
  PIN A2
    DIRECTION INPUT ;
    USE SIGNAL ;
    PORT
      LAYER M1 ;
      RECT 0.12 0.1 0.17 0.2 ;
    END
  END A2
  PIN A3
    DIRECTION INPUT ;
    USE SIGNAL ;
    PORT
      LAYER M1 ;
      RECT 0.20 0.1 0.25 0.2 ;
    END
  END A3
  PIN ZN
    DIRECTION OUTPUT ;
    USE SIGNAL ;
    PORT
      LAYER M1 ;
      RECT 0.27 0.1 0.32 0.2 ;
    END
  END ZN
END NR3OPTPAD12
MACRO NR3OPTPAD1
  CLASS CORE ;
  ORIGIN 0.0 0.0 ;
  SIZE 0.45 BY 0.3 ;
  SYMMETRY X Y ;
  PIN A1
    DIRECTION INPUT ;
    USE SIGNAL ;
    PORT
      LAYER M1 ;
      RECT 0.05 0.1 0.10 0.2 ;
    END
  END A1
  PIN A2
    DIRECTION INPUT ;
    USE SIGNAL ;
    PORT
      LAYER M1 ;
      RECT 0.12 0.1 0.17 0.2 ;
    END
  END A2
  PIN A3
    DIRECTION INPUT ;
    USE SIGNAL ;
    PORT
      LAYER M1 ;
      RECT 0.20 0.1 0.25 0.2 ;
    END
  END A3
  PIN ZN
    DIRECTION OUTPUT ;
    USE SIGNAL ;
    PORT
      LAYER M1 ;
      RECT 0.27 0.1 0.32 0.2 ;
    END
  END ZN
END NR3OPTPAD1
MACRO NR3OPTPAD2
  CLASS CORE ;
  ORIGIN 0.0 0.0 ;
  SIZE 0.45 BY 0.3 ;
  SYMMETRY X Y ;
  PIN A1
    DIRECTION INPUT ;
    USE SIGNAL ;
    PORT
      LAYER M1 ;
      RECT 0.05 0.1 0.10 0.2 ;
    END
  END A1
  PIN A2
    DIRECTION INPUT ;
    USE SIGNAL ;
    PORT
      LAYER M1 ;
      RECT 0.12 0.1 0.17 0.2 ;
    END
  END A2
  PIN A3
    DIRECTION INPUT ;
    USE SIGNAL ;
    PORT
      LAYER M1 ;
      RECT 0.20 0.1 0.25 0.2 ;
    END
  END A3
  PIN ZN
    DIRECTION OUTPUT ;
    USE SIGNAL ;
    PORT
      LAYER M1 ;
      RECT 0.27 0.1 0.32 0.2 ;
    END
  END ZN
END NR3OPTPAD2
MACRO NR3SKPD12
  CLASS CORE ;
  ORIGIN 0.0 0.0 ;
  SIZE 0.45 BY 0.3 ;
  SYMMETRY X Y ;
  PIN A1
    DIRECTION INPUT ;
    USE SIGNAL ;
    PORT
      LAYER M1 ;
      RECT 0.05 0.1 0.10 0.2 ;
    END
  END A1
  PIN A2
    DIRECTION INPUT ;
    USE SIGNAL ;
    PORT
      LAYER M1 ;
      RECT 0.12 0.1 0.17 0.2 ;
    END
  END A2
  PIN A3
    DIRECTION INPUT ;
    USE SIGNAL ;
    PORT
      LAYER M1 ;
      RECT 0.20 0.1 0.25 0.2 ;
    END
  END A3
  PIN ZN
    DIRECTION OUTPUT ;
    USE SIGNAL ;
    PORT
      LAYER M1 ;
      RECT 0.27 0.1 0.32 0.2 ;
    END
  END ZN
END NR3SKPD12
MACRO NR3SKPD1
  CLASS CORE ;
  ORIGIN 0.0 0.0 ;
  SIZE 0.45 BY 0.3 ;
  SYMMETRY X Y ;
  PIN A1
    DIRECTION INPUT ;
    USE SIGNAL ;
    PORT
      LAYER M1 ;
      RECT 0.05 0.1 0.10 0.2 ;
    END
  END A1
  PIN A2
    DIRECTION INPUT ;
    USE SIGNAL ;
    PORT
      LAYER M1 ;
      RECT 0.12 0.1 0.17 0.2 ;
    END
  END A2
  PIN A3
    DIRECTION INPUT ;
    USE SIGNAL ;
    PORT
      LAYER M1 ;
      RECT 0.20 0.1 0.25 0.2 ;
    END
  END A3
  PIN ZN
    DIRECTION OUTPUT ;
    USE SIGNAL ;
    PORT
      LAYER M1 ;
      RECT 0.27 0.1 0.32 0.2 ;
    END
  END ZN
END NR3SKPD1
MACRO NR3SKPD2
  CLASS CORE ;
  ORIGIN 0.0 0.0 ;
  SIZE 0.45 BY 0.3 ;
  SYMMETRY X Y ;
  PIN A1
    DIRECTION INPUT ;
    USE SIGNAL ;
    PORT
      LAYER M1 ;
      RECT 0.05 0.1 0.10 0.2 ;
    END
  END A1
  PIN A2
    DIRECTION INPUT ;
    USE SIGNAL ;
    PORT
      LAYER M1 ;
      RECT 0.12 0.1 0.17 0.2 ;
    END
  END A2
  PIN A3
    DIRECTION INPUT ;
    USE SIGNAL ;
    PORT
      LAYER M1 ;
      RECT 0.20 0.1 0.25 0.2 ;
    END
  END A3
  PIN ZN
    DIRECTION OUTPUT ;
    USE SIGNAL ;
    PORT
      LAYER M1 ;
      RECT 0.27 0.1 0.32 0.2 ;
    END
  END ZN
END NR3SKPD2
MACRO NR3SKPD3
  CLASS CORE ;
  ORIGIN 0.0 0.0 ;
  SIZE 0.45 BY 0.3 ;
  SYMMETRY X Y ;
  PIN A1
    DIRECTION INPUT ;
    USE SIGNAL ;
    PORT
      LAYER M1 ;
      RECT 0.05 0.1 0.10 0.2 ;
    END
  END A1
  PIN A2
    DIRECTION INPUT ;
    USE SIGNAL ;
    PORT
      LAYER M1 ;
      RECT 0.12 0.1 0.17 0.2 ;
    END
  END A2
  PIN A3
    DIRECTION INPUT ;
    USE SIGNAL ;
    PORT
      LAYER M1 ;
      RECT 0.20 0.1 0.25 0.2 ;
    END
  END A3
  PIN ZN
    DIRECTION OUTPUT ;
    USE SIGNAL ;
    PORT
      LAYER M1 ;
      RECT 0.27 0.1 0.32 0.2 ;
    END
  END ZN
END NR3SKPD3
MACRO NR3SKPD4
  CLASS CORE ;
  ORIGIN 0.0 0.0 ;
  SIZE 0.45 BY 0.3 ;
  SYMMETRY X Y ;
  PIN A1
    DIRECTION INPUT ;
    USE SIGNAL ;
    PORT
      LAYER M1 ;
      RECT 0.05 0.1 0.10 0.2 ;
    END
  END A1
  PIN A2
    DIRECTION INPUT ;
    USE SIGNAL ;
    PORT
      LAYER M1 ;
      RECT 0.12 0.1 0.17 0.2 ;
    END
  END A2
  PIN A3
    DIRECTION INPUT ;
    USE SIGNAL ;
    PORT
      LAYER M1 ;
      RECT 0.20 0.1 0.25 0.2 ;
    END
  END A3
  PIN ZN
    DIRECTION OUTPUT ;
    USE SIGNAL ;
    PORT
      LAYER M1 ;
      RECT 0.27 0.1 0.32 0.2 ;
    END
  END ZN
END NR3SKPD4
MACRO NR3SKPD6
  CLASS CORE ;
  ORIGIN 0.0 0.0 ;
  SIZE 0.45 BY 0.3 ;
  SYMMETRY X Y ;
  PIN A1
    DIRECTION INPUT ;
    USE SIGNAL ;
    PORT
      LAYER M1 ;
      RECT 0.05 0.1 0.10 0.2 ;
    END
  END A1
  PIN A2
    DIRECTION INPUT ;
    USE SIGNAL ;
    PORT
      LAYER M1 ;
      RECT 0.12 0.1 0.17 0.2 ;
    END
  END A2
  PIN A3
    DIRECTION INPUT ;
    USE SIGNAL ;
    PORT
      LAYER M1 ;
      RECT 0.20 0.1 0.25 0.2 ;
    END
  END A3
  PIN ZN
    DIRECTION OUTPUT ;
    USE SIGNAL ;
    PORT
      LAYER M1 ;
      RECT 0.27 0.1 0.32 0.2 ;
    END
  END ZN
END NR3SKPD6
MACRO NR3SKPD8
  CLASS CORE ;
  ORIGIN 0.0 0.0 ;
  SIZE 0.45 BY 0.3 ;
  SYMMETRY X Y ;
  PIN A1
    DIRECTION INPUT ;
    USE SIGNAL ;
    PORT
      LAYER M1 ;
      RECT 0.05 0.1 0.10 0.2 ;
    END
  END A1
  PIN A2
    DIRECTION INPUT ;
    USE SIGNAL ;
    PORT
      LAYER M1 ;
      RECT 0.12 0.1 0.17 0.2 ;
    END
  END A2
  PIN A3
    DIRECTION INPUT ;
    USE SIGNAL ;
    PORT
      LAYER M1 ;
      RECT 0.20 0.1 0.25 0.2 ;
    END
  END A3
  PIN ZN
    DIRECTION OUTPUT ;
    USE SIGNAL ;
    PORT
      LAYER M1 ;
      RECT 0.27 0.1 0.32 0.2 ;
    END
  END ZN
END NR3SKPD8
MACRO NR4SKPD1
  CLASS CORE ;
  ORIGIN 0.0 0.0 ;
  SIZE 0.45 BY 0.3 ;
  SYMMETRY X Y ;
  PIN A1
    DIRECTION INPUT ;
    USE SIGNAL ;
    PORT
      LAYER M1 ;
      RECT 0.05 0.1 0.10 0.2 ;
    END
  END A1
  PIN A2
    DIRECTION INPUT ;
    USE SIGNAL ;
    PORT
      LAYER M1 ;
      RECT 0.11 0.1 0.16 0.2 ;
    END
  END A2
  PIN A3
    DIRECTION INPUT ;
    USE SIGNAL ;
    PORT
      LAYER M1 ;
      RECT 0.17 0.1 0.22 0.2 ;
    END
  END A3
  PIN A4
    DIRECTION INPUT ;
    USE SIGNAL ;
    PORT
      LAYER M1 ;
      RECT 0.23 0.1 0.28 0.2 ;
    END
  END A4
  PIN ZN
    DIRECTION OUTPUT ;
    USE SIGNAL ;
    PORT
      LAYER M1 ;
      RECT 0.29 0.1 0.34 0.2 ;
    END
  END ZN
END NR4SKPD1
MACRO NR4SKPD2
  CLASS CORE ;
  ORIGIN 0.0 0.0 ;
  SIZE 0.45 BY 0.3 ;
  SYMMETRY X Y ;
  PIN A1
    DIRECTION INPUT ;
    USE SIGNAL ;
    PORT
      LAYER M1 ;
      RECT 0.05 0.1 0.10 0.2 ;
    END
  END A1
  PIN A2
    DIRECTION INPUT ;
    USE SIGNAL ;
    PORT
      LAYER M1 ;
      RECT 0.11 0.1 0.16 0.2 ;
    END
  END A2
  PIN A3
    DIRECTION INPUT ;
    USE SIGNAL ;
    PORT
      LAYER M1 ;
      RECT 0.17 0.1 0.22 0.2 ;
    END
  END A3
  PIN A4
    DIRECTION INPUT ;
    USE SIGNAL ;
    PORT
      LAYER M1 ;
      RECT 0.23 0.1 0.28 0.2 ;
    END
  END A4
  PIN ZN
    DIRECTION OUTPUT ;
    USE SIGNAL ;
    PORT
      LAYER M1 ;
      RECT 0.29 0.1 0.34 0.2 ;
    END
  END ZN
END NR4SKPD2
MACRO NR4SKPD3
  CLASS CORE ;
  ORIGIN 0.0 0.0 ;
  SIZE 0.45 BY 0.3 ;
  SYMMETRY X Y ;
  PIN A1
    DIRECTION INPUT ;
    USE SIGNAL ;
    PORT
      LAYER M1 ;
      RECT 0.05 0.1 0.10 0.2 ;
    END
  END A1
  PIN A2
    DIRECTION INPUT ;
    USE SIGNAL ;
    PORT
      LAYER M1 ;
      RECT 0.11 0.1 0.16 0.2 ;
    END
  END A2
  PIN A3
    DIRECTION INPUT ;
    USE SIGNAL ;
    PORT
      LAYER M1 ;
      RECT 0.17 0.1 0.22 0.2 ;
    END
  END A3
  PIN A4
    DIRECTION INPUT ;
    USE SIGNAL ;
    PORT
      LAYER M1 ;
      RECT 0.23 0.1 0.28 0.2 ;
    END
  END A4
  PIN ZN
    DIRECTION OUTPUT ;
    USE SIGNAL ;
    PORT
      LAYER M1 ;
      RECT 0.29 0.1 0.34 0.2 ;
    END
  END ZN
END NR4SKPD3
MACRO NR4SKPD4
  CLASS CORE ;
  ORIGIN 0.0 0.0 ;
  SIZE 0.45 BY 0.3 ;
  SYMMETRY X Y ;
  PIN A1
    DIRECTION INPUT ;
    USE SIGNAL ;
    PORT
      LAYER M1 ;
      RECT 0.05 0.1 0.10 0.2 ;
    END
  END A1
  PIN A2
    DIRECTION INPUT ;
    USE SIGNAL ;
    PORT
      LAYER M1 ;
      RECT 0.11 0.1 0.16 0.2 ;
    END
  END A2
  PIN A3
    DIRECTION INPUT ;
    USE SIGNAL ;
    PORT
      LAYER M1 ;
      RECT 0.17 0.1 0.22 0.2 ;
    END
  END A3
  PIN A4
    DIRECTION INPUT ;
    USE SIGNAL ;
    PORT
      LAYER M1 ;
      RECT 0.23 0.1 0.28 0.2 ;
    END
  END A4
  PIN ZN
    DIRECTION OUTPUT ;
    USE SIGNAL ;
    PORT
      LAYER M1 ;
      RECT 0.29 0.1 0.34 0.2 ;
    END
  END ZN
END NR4SKPD4
MACRO NR4SKPD6
  CLASS CORE ;
  ORIGIN 0.0 0.0 ;
  SIZE 0.45 BY 0.3 ;
  SYMMETRY X Y ;
  PIN A1
    DIRECTION INPUT ;
    USE SIGNAL ;
    PORT
      LAYER M1 ;
      RECT 0.05 0.1 0.10 0.2 ;
    END
  END A1
  PIN A2
    DIRECTION INPUT ;
    USE SIGNAL ;
    PORT
      LAYER M1 ;
      RECT 0.11 0.1 0.16 0.2 ;
    END
  END A2
  PIN A3
    DIRECTION INPUT ;
    USE SIGNAL ;
    PORT
      LAYER M1 ;
      RECT 0.17 0.1 0.22 0.2 ;
    END
  END A3
  PIN A4
    DIRECTION INPUT ;
    USE SIGNAL ;
    PORT
      LAYER M1 ;
      RECT 0.23 0.1 0.28 0.2 ;
    END
  END A4
  PIN ZN
    DIRECTION OUTPUT ;
    USE SIGNAL ;
    PORT
      LAYER M1 ;
      RECT 0.29 0.1 0.34 0.2 ;
    END
  END ZN
END NR4SKPD6
MACRO NR4SKPD8
  CLASS CORE ;
  ORIGIN 0.0 0.0 ;
  SIZE 0.45 BY 0.3 ;
  SYMMETRY X Y ;
  PIN A1
    DIRECTION INPUT ;
    USE SIGNAL ;
    PORT
      LAYER M1 ;
      RECT 0.05 0.1 0.10 0.2 ;
    END
  END A1
  PIN A2
    DIRECTION INPUT ;
    USE SIGNAL ;
    PORT
      LAYER M1 ;
      RECT 0.11 0.1 0.16 0.2 ;
    END
  END A2
  PIN A3
    DIRECTION INPUT ;
    USE SIGNAL ;
    PORT
      LAYER M1 ;
      RECT 0.17 0.1 0.22 0.2 ;
    END
  END A3
  PIN A4
    DIRECTION INPUT ;
    USE SIGNAL ;
    PORT
      LAYER M1 ;
      RECT 0.23 0.1 0.28 0.2 ;
    END
  END A4
  PIN ZN
    DIRECTION OUTPUT ;
    USE SIGNAL ;
    PORT
      LAYER M1 ;
      RECT 0.29 0.1 0.34 0.2 ;
    END
  END ZN
END NR4SKPD8
MACRO OA211D0
  CLASS CORE ;
  ORIGIN 0.0 0.0 ;
  SIZE 0.45 BY 0.3 ;
  SYMMETRY X Y ;
  PIN A1
    DIRECTION INPUT ;
    USE SIGNAL ;
    PORT
      LAYER M1 ;
      RECT 0.05 0.1 0.10 0.2 ;
    END
  END A1
  PIN A2
    DIRECTION INPUT ;
    USE SIGNAL ;
    PORT
      LAYER M1 ;
      RECT 0.11 0.1 0.16 0.2 ;
    END
  END A2
  PIN B
    DIRECTION INPUT ;
    USE SIGNAL ;
    PORT
      LAYER M1 ;
      RECT 0.17 0.1 0.22 0.2 ;
    END
  END B
  PIN C
    DIRECTION INPUT ;
    USE SIGNAL ;
    PORT
      LAYER M1 ;
      RECT 0.23 0.1 0.28 0.2 ;
    END
  END C
  PIN Z
    DIRECTION OUTPUT ;
    USE SIGNAL ;
    PORT
      LAYER M1 ;
      RECT 0.29 0.1 0.34 0.2 ;
    END
  END Z
END OA211D0
MACRO OA211OPTLD1
  CLASS CORE ;
  ORIGIN 0.0 0.0 ;
  SIZE 0.45 BY 0.3 ;
  SYMMETRY X Y ;
  PIN A1
    DIRECTION INPUT ;
    USE SIGNAL ;
    PORT
      LAYER M1 ;
      RECT 0.05 0.1 0.10 0.2 ;
    END
  END A1
  PIN A2
    DIRECTION INPUT ;
    USE SIGNAL ;
    PORT
      LAYER M1 ;
      RECT 0.11 0.1 0.16 0.2 ;
    END
  END A2
  PIN B
    DIRECTION INPUT ;
    USE SIGNAL ;
    PORT
      LAYER M1 ;
      RECT 0.17 0.1 0.22 0.2 ;
    END
  END B
  PIN C
    DIRECTION INPUT ;
    USE SIGNAL ;
    PORT
      LAYER M1 ;
      RECT 0.23 0.1 0.28 0.2 ;
    END
  END C
  PIN Z
    DIRECTION OUTPUT ;
    USE SIGNAL ;
    PORT
      LAYER M1 ;
      RECT 0.29 0.1 0.34 0.2 ;
    END
  END Z
END OA211OPTLD1
MACRO OA211OPTLD2
  CLASS CORE ;
  ORIGIN 0.0 0.0 ;
  SIZE 0.45 BY 0.3 ;
  SYMMETRY X Y ;
  PIN A1
    DIRECTION INPUT ;
    USE SIGNAL ;
    PORT
      LAYER M1 ;
      RECT 0.05 0.1 0.10 0.2 ;
    END
  END A1
  PIN A2
    DIRECTION INPUT ;
    USE SIGNAL ;
    PORT
      LAYER M1 ;
      RECT 0.11 0.1 0.16 0.2 ;
    END
  END A2
  PIN B
    DIRECTION INPUT ;
    USE SIGNAL ;
    PORT
      LAYER M1 ;
      RECT 0.17 0.1 0.22 0.2 ;
    END
  END B
  PIN C
    DIRECTION INPUT ;
    USE SIGNAL ;
    PORT
      LAYER M1 ;
      RECT 0.23 0.1 0.28 0.2 ;
    END
  END C
  PIN Z
    DIRECTION OUTPUT ;
    USE SIGNAL ;
    PORT
      LAYER M1 ;
      RECT 0.29 0.1 0.34 0.2 ;
    END
  END Z
END OA211OPTLD2
MACRO OA211OPTLD4
  CLASS CORE ;
  ORIGIN 0.0 0.0 ;
  SIZE 0.45 BY 0.3 ;
  SYMMETRY X Y ;
  PIN A1
    DIRECTION INPUT ;
    USE SIGNAL ;
    PORT
      LAYER M1 ;
      RECT 0.05 0.1 0.10 0.2 ;
    END
  END A1
  PIN A2
    DIRECTION INPUT ;
    USE SIGNAL ;
    PORT
      LAYER M1 ;
      RECT 0.11 0.1 0.16 0.2 ;
    END
  END A2
  PIN B
    DIRECTION INPUT ;
    USE SIGNAL ;
    PORT
      LAYER M1 ;
      RECT 0.17 0.1 0.22 0.2 ;
    END
  END B
  PIN C
    DIRECTION INPUT ;
    USE SIGNAL ;
    PORT
      LAYER M1 ;
      RECT 0.23 0.1 0.28 0.2 ;
    END
  END C
  PIN Z
    DIRECTION OUTPUT ;
    USE SIGNAL ;
    PORT
      LAYER M1 ;
      RECT 0.29 0.1 0.34 0.2 ;
    END
  END Z
END OA211OPTLD4
MACRO OA21D0
  CLASS CORE ;
  ORIGIN 0.0 0.0 ;
  SIZE 0.45 BY 0.3 ;
  SYMMETRY X Y ;
  PIN A1
    DIRECTION INPUT ;
    USE SIGNAL ;
    PORT
      LAYER M1 ;
      RECT 0.05 0.1 0.10 0.2 ;
    END
  END A1
  PIN A2
    DIRECTION INPUT ;
    USE SIGNAL ;
    PORT
      LAYER M1 ;
      RECT 0.12 0.1 0.17 0.2 ;
    END
  END A2
  PIN B
    DIRECTION INPUT ;
    USE SIGNAL ;
    PORT
      LAYER M1 ;
      RECT 0.20 0.1 0.25 0.2 ;
    END
  END B
  PIN Z
    DIRECTION OUTPUT ;
    USE SIGNAL ;
    PORT
      LAYER M1 ;
      RECT 0.27 0.1 0.32 0.2 ;
    END
  END Z
END OA21D0
MACRO OA21D1
  CLASS CORE ;
  ORIGIN 0.0 0.0 ;
  SIZE 0.45 BY 0.3 ;
  SYMMETRY X Y ;
  PIN A1
    DIRECTION INPUT ;
    USE SIGNAL ;
    PORT
      LAYER M1 ;
      RECT 0.05 0.1 0.10 0.2 ;
    END
  END A1
  PIN A2
    DIRECTION INPUT ;
    USE SIGNAL ;
    PORT
      LAYER M1 ;
      RECT 0.12 0.1 0.17 0.2 ;
    END
  END A2
  PIN B
    DIRECTION INPUT ;
    USE SIGNAL ;
    PORT
      LAYER M1 ;
      RECT 0.20 0.1 0.25 0.2 ;
    END
  END B
  PIN Z
    DIRECTION OUTPUT ;
    USE SIGNAL ;
    PORT
      LAYER M1 ;
      RECT 0.27 0.1 0.32 0.2 ;
    END
  END Z
END OA21D1
MACRO OA21OPTLD2
  CLASS CORE ;
  ORIGIN 0.0 0.0 ;
  SIZE 0.45 BY 0.3 ;
  SYMMETRY X Y ;
  PIN A1
    DIRECTION INPUT ;
    USE SIGNAL ;
    PORT
      LAYER M1 ;
      RECT 0.05 0.1 0.10 0.2 ;
    END
  END A1
  PIN A2
    DIRECTION INPUT ;
    USE SIGNAL ;
    PORT
      LAYER M1 ;
      RECT 0.12 0.1 0.17 0.2 ;
    END
  END A2
  PIN B
    DIRECTION INPUT ;
    USE SIGNAL ;
    PORT
      LAYER M1 ;
      RECT 0.20 0.1 0.25 0.2 ;
    END
  END B
  PIN Z
    DIRECTION OUTPUT ;
    USE SIGNAL ;
    PORT
      LAYER M1 ;
      RECT 0.27 0.1 0.32 0.2 ;
    END
  END Z
END OA21OPTLD2
MACRO OA21OPTLD4
  CLASS CORE ;
  ORIGIN 0.0 0.0 ;
  SIZE 0.45 BY 0.3 ;
  SYMMETRY X Y ;
  PIN A1
    DIRECTION INPUT ;
    USE SIGNAL ;
    PORT
      LAYER M1 ;
      RECT 0.05 0.1 0.10 0.2 ;
    END
  END A1
  PIN A2
    DIRECTION INPUT ;
    USE SIGNAL ;
    PORT
      LAYER M1 ;
      RECT 0.12 0.1 0.17 0.2 ;
    END
  END A2
  PIN B
    DIRECTION INPUT ;
    USE SIGNAL ;
    PORT
      LAYER M1 ;
      RECT 0.20 0.1 0.25 0.2 ;
    END
  END B
  PIN Z
    DIRECTION OUTPUT ;
    USE SIGNAL ;
    PORT
      LAYER M1 ;
      RECT 0.27 0.1 0.32 0.2 ;
    END
  END Z
END OA21OPTLD4
MACRO OA22D0
  CLASS CORE ;
  ORIGIN 0.0 0.0 ;
  SIZE 0.45 BY 0.3 ;
  SYMMETRY X Y ;
  PIN A1
    DIRECTION INPUT ;
    USE SIGNAL ;
    PORT
      LAYER M1 ;
      RECT 0.05 0.1 0.10 0.2 ;
    END
  END A1
  PIN A2
    DIRECTION INPUT ;
    USE SIGNAL ;
    PORT
      LAYER M1 ;
      RECT 0.11 0.1 0.16 0.2 ;
    END
  END A2
  PIN B1
    DIRECTION INPUT ;
    USE SIGNAL ;
    PORT
      LAYER M1 ;
      RECT 0.17 0.1 0.22 0.2 ;
    END
  END B1
  PIN B2
    DIRECTION INPUT ;
    USE SIGNAL ;
    PORT
      LAYER M1 ;
      RECT 0.23 0.1 0.28 0.2 ;
    END
  END B2
  PIN Z
    DIRECTION OUTPUT ;
    USE SIGNAL ;
    PORT
      LAYER M1 ;
      RECT 0.29 0.1 0.34 0.2 ;
    END
  END Z
END OA22D0
MACRO OA22D4
  CLASS CORE ;
  ORIGIN 0.0 0.0 ;
  SIZE 0.45 BY 0.3 ;
  SYMMETRY X Y ;
  PIN A1
    DIRECTION INPUT ;
    USE SIGNAL ;
    PORT
      LAYER M1 ;
      RECT 0.05 0.1 0.10 0.2 ;
    END
  END A1
  PIN A2
    DIRECTION INPUT ;
    USE SIGNAL ;
    PORT
      LAYER M1 ;
      RECT 0.11 0.1 0.16 0.2 ;
    END
  END A2
  PIN B1
    DIRECTION INPUT ;
    USE SIGNAL ;
    PORT
      LAYER M1 ;
      RECT 0.17 0.1 0.22 0.2 ;
    END
  END B1
  PIN B2
    DIRECTION INPUT ;
    USE SIGNAL ;
    PORT
      LAYER M1 ;
      RECT 0.23 0.1 0.28 0.2 ;
    END
  END B2
  PIN Z
    DIRECTION OUTPUT ;
    USE SIGNAL ;
    PORT
      LAYER M1 ;
      RECT 0.29 0.1 0.34 0.2 ;
    END
  END Z
END OA22D4
MACRO OA22OPTLD1
  CLASS CORE ;
  ORIGIN 0.0 0.0 ;
  SIZE 0.45 BY 0.3 ;
  SYMMETRY X Y ;
  PIN A1
    DIRECTION INPUT ;
    USE SIGNAL ;
    PORT
      LAYER M1 ;
      RECT 0.05 0.1 0.10 0.2 ;
    END
  END A1
  PIN A2
    DIRECTION INPUT ;
    USE SIGNAL ;
    PORT
      LAYER M1 ;
      RECT 0.11 0.1 0.16 0.2 ;
    END
  END A2
  PIN B1
    DIRECTION INPUT ;
    USE SIGNAL ;
    PORT
      LAYER M1 ;
      RECT 0.17 0.1 0.22 0.2 ;
    END
  END B1
  PIN B2
    DIRECTION INPUT ;
    USE SIGNAL ;
    PORT
      LAYER M1 ;
      RECT 0.23 0.1 0.28 0.2 ;
    END
  END B2
  PIN Z
    DIRECTION OUTPUT ;
    USE SIGNAL ;
    PORT
      LAYER M1 ;
      RECT 0.29 0.1 0.34 0.2 ;
    END
  END Z
END OA22OPTLD1
MACRO OAI211OPTPAD1
  CLASS CORE ;
  ORIGIN 0.0 0.0 ;
  SIZE 0.45 BY 0.3 ;
  SYMMETRY X Y ;
  PIN A1
    DIRECTION INPUT ;
    USE SIGNAL ;
    PORT
      LAYER M1 ;
      RECT 0.05 0.1 0.10 0.2 ;
    END
  END A1
  PIN A2
    DIRECTION INPUT ;
    USE SIGNAL ;
    PORT
      LAYER M1 ;
      RECT 0.11 0.1 0.16 0.2 ;
    END
  END A2
  PIN B
    DIRECTION INPUT ;
    USE SIGNAL ;
    PORT
      LAYER M1 ;
      RECT 0.17 0.1 0.22 0.2 ;
    END
  END B
  PIN C
    DIRECTION INPUT ;
    USE SIGNAL ;
    PORT
      LAYER M1 ;
      RECT 0.23 0.1 0.28 0.2 ;
    END
  END C
  PIN ZN
    DIRECTION OUTPUT ;
    USE SIGNAL ;
    PORT
      LAYER M1 ;
      RECT 0.29 0.1 0.34 0.2 ;
    END
  END ZN
END OAI211OPTPAD1
MACRO OAI211OPTPAD2
  CLASS CORE ;
  ORIGIN 0.0 0.0 ;
  SIZE 0.45 BY 0.3 ;
  SYMMETRY X Y ;
  PIN A1
    DIRECTION INPUT ;
    USE SIGNAL ;
    PORT
      LAYER M1 ;
      RECT 0.05 0.1 0.10 0.2 ;
    END
  END A1
  PIN A2
    DIRECTION INPUT ;
    USE SIGNAL ;
    PORT
      LAYER M1 ;
      RECT 0.11 0.1 0.16 0.2 ;
    END
  END A2
  PIN B
    DIRECTION INPUT ;
    USE SIGNAL ;
    PORT
      LAYER M1 ;
      RECT 0.17 0.1 0.22 0.2 ;
    END
  END B
  PIN C
    DIRECTION INPUT ;
    USE SIGNAL ;
    PORT
      LAYER M1 ;
      RECT 0.23 0.1 0.28 0.2 ;
    END
  END C
  PIN ZN
    DIRECTION OUTPUT ;
    USE SIGNAL ;
    PORT
      LAYER M1 ;
      RECT 0.29 0.1 0.34 0.2 ;
    END
  END ZN
END OAI211OPTPAD2
MACRO OAI211OPTPAD4
  CLASS CORE ;
  ORIGIN 0.0 0.0 ;
  SIZE 0.45 BY 0.3 ;
  SYMMETRY X Y ;
  PIN A1
    DIRECTION INPUT ;
    USE SIGNAL ;
    PORT
      LAYER M1 ;
      RECT 0.05 0.1 0.10 0.2 ;
    END
  END A1
  PIN A2
    DIRECTION INPUT ;
    USE SIGNAL ;
    PORT
      LAYER M1 ;
      RECT 0.11 0.1 0.16 0.2 ;
    END
  END A2
  PIN B
    DIRECTION INPUT ;
    USE SIGNAL ;
    PORT
      LAYER M1 ;
      RECT 0.17 0.1 0.22 0.2 ;
    END
  END B
  PIN C
    DIRECTION INPUT ;
    USE SIGNAL ;
    PORT
      LAYER M1 ;
      RECT 0.23 0.1 0.28 0.2 ;
    END
  END C
  PIN ZN
    DIRECTION OUTPUT ;
    USE SIGNAL ;
    PORT
      LAYER M1 ;
      RECT 0.29 0.1 0.34 0.2 ;
    END
  END ZN
END OAI211OPTPAD4
MACRO OAI211OPTPAD6
  CLASS CORE ;
  ORIGIN 0.0 0.0 ;
  SIZE 0.45 BY 0.3 ;
  SYMMETRY X Y ;
  PIN A1
    DIRECTION INPUT ;
    USE SIGNAL ;
    PORT
      LAYER M1 ;
      RECT 0.05 0.1 0.10 0.2 ;
    END
  END A1
  PIN A2
    DIRECTION INPUT ;
    USE SIGNAL ;
    PORT
      LAYER M1 ;
      RECT 0.11 0.1 0.16 0.2 ;
    END
  END A2
  PIN B
    DIRECTION INPUT ;
    USE SIGNAL ;
    PORT
      LAYER M1 ;
      RECT 0.17 0.1 0.22 0.2 ;
    END
  END B
  PIN C
    DIRECTION INPUT ;
    USE SIGNAL ;
    PORT
      LAYER M1 ;
      RECT 0.23 0.1 0.28 0.2 ;
    END
  END C
  PIN ZN
    DIRECTION OUTPUT ;
    USE SIGNAL ;
    PORT
      LAYER M1 ;
      RECT 0.29 0.1 0.34 0.2 ;
    END
  END ZN
END OAI211OPTPAD6
MACRO OAI211SKND1
  CLASS CORE ;
  ORIGIN 0.0 0.0 ;
  SIZE 0.45 BY 0.3 ;
  SYMMETRY X Y ;
  PIN A1
    DIRECTION INPUT ;
    USE SIGNAL ;
    PORT
      LAYER M1 ;
      RECT 0.05 0.1 0.10 0.2 ;
    END
  END A1
  PIN A2
    DIRECTION INPUT ;
    USE SIGNAL ;
    PORT
      LAYER M1 ;
      RECT 0.11 0.1 0.16 0.2 ;
    END
  END A2
  PIN B
    DIRECTION INPUT ;
    USE SIGNAL ;
    PORT
      LAYER M1 ;
      RECT 0.17 0.1 0.22 0.2 ;
    END
  END B
  PIN C
    DIRECTION INPUT ;
    USE SIGNAL ;
    PORT
      LAYER M1 ;
      RECT 0.23 0.1 0.28 0.2 ;
    END
  END C
  PIN ZN
    DIRECTION OUTPUT ;
    USE SIGNAL ;
    PORT
      LAYER M1 ;
      RECT 0.29 0.1 0.34 0.2 ;
    END
  END ZN
END OAI211SKND1
MACRO OAI211SKND2
  CLASS CORE ;
  ORIGIN 0.0 0.0 ;
  SIZE 0.45 BY 0.3 ;
  SYMMETRY X Y ;
  PIN A1
    DIRECTION INPUT ;
    USE SIGNAL ;
    PORT
      LAYER M1 ;
      RECT 0.05 0.1 0.10 0.2 ;
    END
  END A1
  PIN A2
    DIRECTION INPUT ;
    USE SIGNAL ;
    PORT
      LAYER M1 ;
      RECT 0.11 0.1 0.16 0.2 ;
    END
  END A2
  PIN B
    DIRECTION INPUT ;
    USE SIGNAL ;
    PORT
      LAYER M1 ;
      RECT 0.17 0.1 0.22 0.2 ;
    END
  END B
  PIN C
    DIRECTION INPUT ;
    USE SIGNAL ;
    PORT
      LAYER M1 ;
      RECT 0.23 0.1 0.28 0.2 ;
    END
  END C
  PIN ZN
    DIRECTION OUTPUT ;
    USE SIGNAL ;
    PORT
      LAYER M1 ;
      RECT 0.29 0.1 0.34 0.2 ;
    END
  END ZN
END OAI211SKND2
MACRO OAI211SKND3
  CLASS CORE ;
  ORIGIN 0.0 0.0 ;
  SIZE 0.45 BY 0.3 ;
  SYMMETRY X Y ;
  PIN A1
    DIRECTION INPUT ;
    USE SIGNAL ;
    PORT
      LAYER M1 ;
      RECT 0.05 0.1 0.10 0.2 ;
    END
  END A1
  PIN A2
    DIRECTION INPUT ;
    USE SIGNAL ;
    PORT
      LAYER M1 ;
      RECT 0.11 0.1 0.16 0.2 ;
    END
  END A2
  PIN B
    DIRECTION INPUT ;
    USE SIGNAL ;
    PORT
      LAYER M1 ;
      RECT 0.17 0.1 0.22 0.2 ;
    END
  END B
  PIN C
    DIRECTION INPUT ;
    USE SIGNAL ;
    PORT
      LAYER M1 ;
      RECT 0.23 0.1 0.28 0.2 ;
    END
  END C
  PIN ZN
    DIRECTION OUTPUT ;
    USE SIGNAL ;
    PORT
      LAYER M1 ;
      RECT 0.29 0.1 0.34 0.2 ;
    END
  END ZN
END OAI211SKND3
MACRO OAI211SKND4
  CLASS CORE ;
  ORIGIN 0.0 0.0 ;
  SIZE 0.45 BY 0.3 ;
  SYMMETRY X Y ;
  PIN A1
    DIRECTION INPUT ;
    USE SIGNAL ;
    PORT
      LAYER M1 ;
      RECT 0.05 0.1 0.10 0.2 ;
    END
  END A1
  PIN A2
    DIRECTION INPUT ;
    USE SIGNAL ;
    PORT
      LAYER M1 ;
      RECT 0.11 0.1 0.16 0.2 ;
    END
  END A2
  PIN B
    DIRECTION INPUT ;
    USE SIGNAL ;
    PORT
      LAYER M1 ;
      RECT 0.17 0.1 0.22 0.2 ;
    END
  END B
  PIN C
    DIRECTION INPUT ;
    USE SIGNAL ;
    PORT
      LAYER M1 ;
      RECT 0.23 0.1 0.28 0.2 ;
    END
  END C
  PIN ZN
    DIRECTION OUTPUT ;
    USE SIGNAL ;
    PORT
      LAYER M1 ;
      RECT 0.29 0.1 0.34 0.2 ;
    END
  END ZN
END OAI211SKND4
MACRO OAI211SKND6
  CLASS CORE ;
  ORIGIN 0.0 0.0 ;
  SIZE 0.45 BY 0.3 ;
  SYMMETRY X Y ;
  PIN A1
    DIRECTION INPUT ;
    USE SIGNAL ;
    PORT
      LAYER M1 ;
      RECT 0.05 0.1 0.10 0.2 ;
    END
  END A1
  PIN A2
    DIRECTION INPUT ;
    USE SIGNAL ;
    PORT
      LAYER M1 ;
      RECT 0.11 0.1 0.16 0.2 ;
    END
  END A2
  PIN B
    DIRECTION INPUT ;
    USE SIGNAL ;
    PORT
      LAYER M1 ;
      RECT 0.17 0.1 0.22 0.2 ;
    END
  END B
  PIN C
    DIRECTION INPUT ;
    USE SIGNAL ;
    PORT
      LAYER M1 ;
      RECT 0.23 0.1 0.28 0.2 ;
    END
  END C
  PIN ZN
    DIRECTION OUTPUT ;
    USE SIGNAL ;
    PORT
      LAYER M1 ;
      RECT 0.29 0.1 0.34 0.2 ;
    END
  END ZN
END OAI211SKND6
MACRO OAI211SKND8
  CLASS CORE ;
  ORIGIN 0.0 0.0 ;
  SIZE 0.45 BY 0.3 ;
  SYMMETRY X Y ;
  PIN A1
    DIRECTION INPUT ;
    USE SIGNAL ;
    PORT
      LAYER M1 ;
      RECT 0.05 0.1 0.10 0.2 ;
    END
  END A1
  PIN A2
    DIRECTION INPUT ;
    USE SIGNAL ;
    PORT
      LAYER M1 ;
      RECT 0.11 0.1 0.16 0.2 ;
    END
  END A2
  PIN B
    DIRECTION INPUT ;
    USE SIGNAL ;
    PORT
      LAYER M1 ;
      RECT 0.17 0.1 0.22 0.2 ;
    END
  END B
  PIN C
    DIRECTION INPUT ;
    USE SIGNAL ;
    PORT
      LAYER M1 ;
      RECT 0.23 0.1 0.28 0.2 ;
    END
  END C
  PIN ZN
    DIRECTION OUTPUT ;
    USE SIGNAL ;
    PORT
      LAYER M1 ;
      RECT 0.29 0.1 0.34 0.2 ;
    END
  END ZN
END OAI211SKND8
MACRO OAI211SKPD1
  CLASS CORE ;
  ORIGIN 0.0 0.0 ;
  SIZE 0.45 BY 0.3 ;
  SYMMETRY X Y ;
  PIN A1
    DIRECTION INPUT ;
    USE SIGNAL ;
    PORT
      LAYER M1 ;
      RECT 0.05 0.1 0.10 0.2 ;
    END
  END A1
  PIN A2
    DIRECTION INPUT ;
    USE SIGNAL ;
    PORT
      LAYER M1 ;
      RECT 0.11 0.1 0.16 0.2 ;
    END
  END A2
  PIN B
    DIRECTION INPUT ;
    USE SIGNAL ;
    PORT
      LAYER M1 ;
      RECT 0.17 0.1 0.22 0.2 ;
    END
  END B
  PIN C
    DIRECTION INPUT ;
    USE SIGNAL ;
    PORT
      LAYER M1 ;
      RECT 0.23 0.1 0.28 0.2 ;
    END
  END C
  PIN ZN
    DIRECTION OUTPUT ;
    USE SIGNAL ;
    PORT
      LAYER M1 ;
      RECT 0.29 0.1 0.34 0.2 ;
    END
  END ZN
END OAI211SKPD1
MACRO OAI211SKPD2
  CLASS CORE ;
  ORIGIN 0.0 0.0 ;
  SIZE 0.45 BY 0.3 ;
  SYMMETRY X Y ;
  PIN A1
    DIRECTION INPUT ;
    USE SIGNAL ;
    PORT
      LAYER M1 ;
      RECT 0.05 0.1 0.10 0.2 ;
    END
  END A1
  PIN A2
    DIRECTION INPUT ;
    USE SIGNAL ;
    PORT
      LAYER M1 ;
      RECT 0.11 0.1 0.16 0.2 ;
    END
  END A2
  PIN B
    DIRECTION INPUT ;
    USE SIGNAL ;
    PORT
      LAYER M1 ;
      RECT 0.17 0.1 0.22 0.2 ;
    END
  END B
  PIN C
    DIRECTION INPUT ;
    USE SIGNAL ;
    PORT
      LAYER M1 ;
      RECT 0.23 0.1 0.28 0.2 ;
    END
  END C
  PIN ZN
    DIRECTION OUTPUT ;
    USE SIGNAL ;
    PORT
      LAYER M1 ;
      RECT 0.29 0.1 0.34 0.2 ;
    END
  END ZN
END OAI211SKPD2
MACRO OAI21D1
  CLASS CORE ;
  ORIGIN 0.0 0.0 ;
  SIZE 0.45 BY 0.3 ;
  SYMMETRY X Y ;
  PIN A1
    DIRECTION INPUT ;
    USE SIGNAL ;
    PORT
      LAYER M1 ;
      RECT 0.05 0.1 0.10 0.2 ;
    END
  END A1
  PIN A2
    DIRECTION INPUT ;
    USE SIGNAL ;
    PORT
      LAYER M1 ;
      RECT 0.12 0.1 0.17 0.2 ;
    END
  END A2
  PIN B
    DIRECTION INPUT ;
    USE SIGNAL ;
    PORT
      LAYER M1 ;
      RECT 0.20 0.1 0.25 0.2 ;
    END
  END B
  PIN ZN
    DIRECTION OUTPUT ;
    USE SIGNAL ;
    PORT
      LAYER M1 ;
      RECT 0.27 0.1 0.32 0.2 ;
    END
  END ZN
END OAI21D1
MACRO OAI21OPTPAD1
  CLASS CORE ;
  ORIGIN 0.0 0.0 ;
  SIZE 0.45 BY 0.3 ;
  SYMMETRY X Y ;
  PIN A1
    DIRECTION INPUT ;
    USE SIGNAL ;
    PORT
      LAYER M1 ;
      RECT 0.05 0.1 0.10 0.2 ;
    END
  END A1
  PIN A2
    DIRECTION INPUT ;
    USE SIGNAL ;
    PORT
      LAYER M1 ;
      RECT 0.12 0.1 0.17 0.2 ;
    END
  END A2
  PIN B
    DIRECTION INPUT ;
    USE SIGNAL ;
    PORT
      LAYER M1 ;
      RECT 0.20 0.1 0.25 0.2 ;
    END
  END B
  PIN ZN
    DIRECTION OUTPUT ;
    USE SIGNAL ;
    PORT
      LAYER M1 ;
      RECT 0.27 0.1 0.32 0.2 ;
    END
  END ZN
END OAI21OPTPAD1
MACRO OAI21OPTPAD2
  CLASS CORE ;
  ORIGIN 0.0 0.0 ;
  SIZE 0.45 BY 0.3 ;
  SYMMETRY X Y ;
  PIN A1
    DIRECTION INPUT ;
    USE SIGNAL ;
    PORT
      LAYER M1 ;
      RECT 0.05 0.1 0.10 0.2 ;
    END
  END A1
  PIN A2
    DIRECTION INPUT ;
    USE SIGNAL ;
    PORT
      LAYER M1 ;
      RECT 0.12 0.1 0.17 0.2 ;
    END
  END A2
  PIN B
    DIRECTION INPUT ;
    USE SIGNAL ;
    PORT
      LAYER M1 ;
      RECT 0.20 0.1 0.25 0.2 ;
    END
  END B
  PIN ZN
    DIRECTION OUTPUT ;
    USE SIGNAL ;
    PORT
      LAYER M1 ;
      RECT 0.27 0.1 0.32 0.2 ;
    END
  END ZN
END OAI21OPTPAD2
MACRO OAI21OPTPAD4
  CLASS CORE ;
  ORIGIN 0.0 0.0 ;
  SIZE 0.45 BY 0.3 ;
  SYMMETRY X Y ;
  PIN A1
    DIRECTION INPUT ;
    USE SIGNAL ;
    PORT
      LAYER M1 ;
      RECT 0.05 0.1 0.10 0.2 ;
    END
  END A1
  PIN A2
    DIRECTION INPUT ;
    USE SIGNAL ;
    PORT
      LAYER M1 ;
      RECT 0.12 0.1 0.17 0.2 ;
    END
  END A2
  PIN B
    DIRECTION INPUT ;
    USE SIGNAL ;
    PORT
      LAYER M1 ;
      RECT 0.20 0.1 0.25 0.2 ;
    END
  END B
  PIN ZN
    DIRECTION OUTPUT ;
    USE SIGNAL ;
    PORT
      LAYER M1 ;
      RECT 0.27 0.1 0.32 0.2 ;
    END
  END ZN
END OAI21OPTPAD4
MACRO OAI21OPTPAOPTLD2
  CLASS CORE ;
  ORIGIN 0.0 0.0 ;
  SIZE 0.45 BY 0.3 ;
  SYMMETRY X Y ;
  PIN A1
    DIRECTION INPUT ;
    USE SIGNAL ;
    PORT
      LAYER M1 ;
      RECT 0.05 0.1 0.10 0.2 ;
    END
  END A1
  PIN A2
    DIRECTION INPUT ;
    USE SIGNAL ;
    PORT
      LAYER M1 ;
      RECT 0.12 0.1 0.17 0.2 ;
    END
  END A2
  PIN B
    DIRECTION INPUT ;
    USE SIGNAL ;
    PORT
      LAYER M1 ;
      RECT 0.20 0.1 0.25 0.2 ;
    END
  END B
  PIN ZN
    DIRECTION OUTPUT ;
    USE SIGNAL ;
    PORT
      LAYER M1 ;
      RECT 0.27 0.1 0.32 0.2 ;
    END
  END ZN
END OAI21OPTPAOPTLD2
MACRO OAI21OPTPAOPTLD4
  CLASS CORE ;
  ORIGIN 0.0 0.0 ;
  SIZE 0.45 BY 0.3 ;
  SYMMETRY X Y ;
  PIN A1
    DIRECTION INPUT ;
    USE SIGNAL ;
    PORT
      LAYER M1 ;
      RECT 0.05 0.1 0.10 0.2 ;
    END
  END A1
  PIN A2
    DIRECTION INPUT ;
    USE SIGNAL ;
    PORT
      LAYER M1 ;
      RECT 0.12 0.1 0.17 0.2 ;
    END
  END A2
  PIN B
    DIRECTION INPUT ;
    USE SIGNAL ;
    PORT
      LAYER M1 ;
      RECT 0.20 0.1 0.25 0.2 ;
    END
  END B
  PIN ZN
    DIRECTION OUTPUT ;
    USE SIGNAL ;
    PORT
      LAYER M1 ;
      RECT 0.27 0.1 0.32 0.2 ;
    END
  END ZN
END OAI21OPTPAOPTLD4
MACRO OAI21SKND1
  CLASS CORE ;
  ORIGIN 0.0 0.0 ;
  SIZE 0.45 BY 0.3 ;
  SYMMETRY X Y ;
  PIN A1
    DIRECTION INPUT ;
    USE SIGNAL ;
    PORT
      LAYER M1 ;
      RECT 0.05 0.1 0.10 0.2 ;
    END
  END A1
  PIN A2
    DIRECTION INPUT ;
    USE SIGNAL ;
    PORT
      LAYER M1 ;
      RECT 0.12 0.1 0.17 0.2 ;
    END
  END A2
  PIN B
    DIRECTION INPUT ;
    USE SIGNAL ;
    PORT
      LAYER M1 ;
      RECT 0.20 0.1 0.25 0.2 ;
    END
  END B
  PIN ZN
    DIRECTION OUTPUT ;
    USE SIGNAL ;
    PORT
      LAYER M1 ;
      RECT 0.27 0.1 0.32 0.2 ;
    END
  END ZN
END OAI21SKND1
MACRO OAI21SKND2
  CLASS CORE ;
  ORIGIN 0.0 0.0 ;
  SIZE 0.45 BY 0.3 ;
  SYMMETRY X Y ;
  PIN A1
    DIRECTION INPUT ;
    USE SIGNAL ;
    PORT
      LAYER M1 ;
      RECT 0.05 0.1 0.10 0.2 ;
    END
  END A1
  PIN A2
    DIRECTION INPUT ;
    USE SIGNAL ;
    PORT
      LAYER M1 ;
      RECT 0.12 0.1 0.17 0.2 ;
    END
  END A2
  PIN B
    DIRECTION INPUT ;
    USE SIGNAL ;
    PORT
      LAYER M1 ;
      RECT 0.20 0.1 0.25 0.2 ;
    END
  END B
  PIN ZN
    DIRECTION OUTPUT ;
    USE SIGNAL ;
    PORT
      LAYER M1 ;
      RECT 0.27 0.1 0.32 0.2 ;
    END
  END ZN
END OAI21SKND2
MACRO OAI21SKND3
  CLASS CORE ;
  ORIGIN 0.0 0.0 ;
  SIZE 0.45 BY 0.3 ;
  SYMMETRY X Y ;
  PIN A1
    DIRECTION INPUT ;
    USE SIGNAL ;
    PORT
      LAYER M1 ;
      RECT 0.05 0.1 0.10 0.2 ;
    END
  END A1
  PIN A2
    DIRECTION INPUT ;
    USE SIGNAL ;
    PORT
      LAYER M1 ;
      RECT 0.12 0.1 0.17 0.2 ;
    END
  END A2
  PIN B
    DIRECTION INPUT ;
    USE SIGNAL ;
    PORT
      LAYER M1 ;
      RECT 0.20 0.1 0.25 0.2 ;
    END
  END B
  PIN ZN
    DIRECTION OUTPUT ;
    USE SIGNAL ;
    PORT
      LAYER M1 ;
      RECT 0.27 0.1 0.32 0.2 ;
    END
  END ZN
END OAI21SKND3
MACRO OAI21SKND4
  CLASS CORE ;
  ORIGIN 0.0 0.0 ;
  SIZE 0.45 BY 0.3 ;
  SYMMETRY X Y ;
  PIN A1
    DIRECTION INPUT ;
    USE SIGNAL ;
    PORT
      LAYER M1 ;
      RECT 0.05 0.1 0.10 0.2 ;
    END
  END A1
  PIN A2
    DIRECTION INPUT ;
    USE SIGNAL ;
    PORT
      LAYER M1 ;
      RECT 0.12 0.1 0.17 0.2 ;
    END
  END A2
  PIN B
    DIRECTION INPUT ;
    USE SIGNAL ;
    PORT
      LAYER M1 ;
      RECT 0.20 0.1 0.25 0.2 ;
    END
  END B
  PIN ZN
    DIRECTION OUTPUT ;
    USE SIGNAL ;
    PORT
      LAYER M1 ;
      RECT 0.27 0.1 0.32 0.2 ;
    END
  END ZN
END OAI21SKND4
MACRO OAI21SKND6
  CLASS CORE ;
  ORIGIN 0.0 0.0 ;
  SIZE 0.45 BY 0.3 ;
  SYMMETRY X Y ;
  PIN A1
    DIRECTION INPUT ;
    USE SIGNAL ;
    PORT
      LAYER M1 ;
      RECT 0.05 0.1 0.10 0.2 ;
    END
  END A1
  PIN A2
    DIRECTION INPUT ;
    USE SIGNAL ;
    PORT
      LAYER M1 ;
      RECT 0.12 0.1 0.17 0.2 ;
    END
  END A2
  PIN B
    DIRECTION INPUT ;
    USE SIGNAL ;
    PORT
      LAYER M1 ;
      RECT 0.20 0.1 0.25 0.2 ;
    END
  END B
  PIN ZN
    DIRECTION OUTPUT ;
    USE SIGNAL ;
    PORT
      LAYER M1 ;
      RECT 0.27 0.1 0.32 0.2 ;
    END
  END ZN
END OAI21SKND6
MACRO OAI21SKND8
  CLASS CORE ;
  ORIGIN 0.0 0.0 ;
  SIZE 0.45 BY 0.3 ;
  SYMMETRY X Y ;
  PIN A1
    DIRECTION INPUT ;
    USE SIGNAL ;
    PORT
      LAYER M1 ;
      RECT 0.05 0.1 0.10 0.2 ;
    END
  END A1
  PIN A2
    DIRECTION INPUT ;
    USE SIGNAL ;
    PORT
      LAYER M1 ;
      RECT 0.12 0.1 0.17 0.2 ;
    END
  END A2
  PIN B
    DIRECTION INPUT ;
    USE SIGNAL ;
    PORT
      LAYER M1 ;
      RECT 0.20 0.1 0.25 0.2 ;
    END
  END B
  PIN ZN
    DIRECTION OUTPUT ;
    USE SIGNAL ;
    PORT
      LAYER M1 ;
      RECT 0.27 0.1 0.32 0.2 ;
    END
  END ZN
END OAI21SKND8
MACRO OAI21SKPD1
  CLASS CORE ;
  ORIGIN 0.0 0.0 ;
  SIZE 0.45 BY 0.3 ;
  SYMMETRY X Y ;
  PIN A1
    DIRECTION INPUT ;
    USE SIGNAL ;
    PORT
      LAYER M1 ;
      RECT 0.05 0.1 0.10 0.2 ;
    END
  END A1
  PIN A2
    DIRECTION INPUT ;
    USE SIGNAL ;
    PORT
      LAYER M1 ;
      RECT 0.12 0.1 0.17 0.2 ;
    END
  END A2
  PIN B
    DIRECTION INPUT ;
    USE SIGNAL ;
    PORT
      LAYER M1 ;
      RECT 0.20 0.1 0.25 0.2 ;
    END
  END B
  PIN ZN
    DIRECTION OUTPUT ;
    USE SIGNAL ;
    PORT
      LAYER M1 ;
      RECT 0.27 0.1 0.32 0.2 ;
    END
  END ZN
END OAI21SKPD1
MACRO OAI21SKPD2
  CLASS CORE ;
  ORIGIN 0.0 0.0 ;
  SIZE 0.45 BY 0.3 ;
  SYMMETRY X Y ;
  PIN A1
    DIRECTION INPUT ;
    USE SIGNAL ;
    PORT
      LAYER M1 ;
      RECT 0.05 0.1 0.10 0.2 ;
    END
  END A1
  PIN A2
    DIRECTION INPUT ;
    USE SIGNAL ;
    PORT
      LAYER M1 ;
      RECT 0.12 0.1 0.17 0.2 ;
    END
  END A2
  PIN B
    DIRECTION INPUT ;
    USE SIGNAL ;
    PORT
      LAYER M1 ;
      RECT 0.20 0.1 0.25 0.2 ;
    END
  END B
  PIN ZN
    DIRECTION OUTPUT ;
    USE SIGNAL ;
    PORT
      LAYER M1 ;
      RECT 0.27 0.1 0.32 0.2 ;
    END
  END ZN
END OAI21SKPD2
MACRO OAI21SKPD4
  CLASS CORE ;
  ORIGIN 0.0 0.0 ;
  SIZE 0.45 BY 0.3 ;
  SYMMETRY X Y ;
  PIN A1
    DIRECTION INPUT ;
    USE SIGNAL ;
    PORT
      LAYER M1 ;
      RECT 0.05 0.1 0.10 0.2 ;
    END
  END A1
  PIN A2
    DIRECTION INPUT ;
    USE SIGNAL ;
    PORT
      LAYER M1 ;
      RECT 0.12 0.1 0.17 0.2 ;
    END
  END A2
  PIN B
    DIRECTION INPUT ;
    USE SIGNAL ;
    PORT
      LAYER M1 ;
      RECT 0.20 0.1 0.25 0.2 ;
    END
  END B
  PIN ZN
    DIRECTION OUTPUT ;
    USE SIGNAL ;
    PORT
      LAYER M1 ;
      RECT 0.27 0.1 0.32 0.2 ;
    END
  END ZN
END OAI21SKPD4
MACRO OAI221D1
  CLASS CORE ;
  ORIGIN 0.0 0.0 ;
  SIZE 0.45 BY 0.3 ;
  SYMMETRY X Y ;
  PIN A1
    DIRECTION INPUT ;
    USE SIGNAL ;
    PORT
      LAYER M1 ;
      RECT 0.05 0.1 0.10 0.2 ;
    END
  END A1
  PIN A2
    DIRECTION INPUT ;
    USE SIGNAL ;
    PORT
      LAYER M1 ;
      RECT 0.10 0.1 0.15 0.2 ;
    END
  END A2
  PIN B1
    DIRECTION INPUT ;
    USE SIGNAL ;
    PORT
      LAYER M1 ;
      RECT 0.15 0.1 0.20 0.2 ;
    END
  END B1
  PIN B2
    DIRECTION INPUT ;
    USE SIGNAL ;
    PORT
      LAYER M1 ;
      RECT 0.20 0.1 0.25 0.2 ;
    END
  END B2
  PIN C
    DIRECTION INPUT ;
    USE SIGNAL ;
    PORT
      LAYER M1 ;
      RECT 0.25 0.1 0.30 0.2 ;
    END
  END C
  PIN ZN
    DIRECTION OUTPUT ;
    USE SIGNAL ;
    PORT
      LAYER M1 ;
      RECT 0.30 0.1 0.35 0.2 ;
    END
  END ZN
END OAI221D1
MACRO OAI222D0
  CLASS CORE ;
  ORIGIN 0.0 0.0 ;
  SIZE 0.45 BY 0.3 ;
  SYMMETRY X Y ;
  PIN A1
    DIRECTION INPUT ;
    USE SIGNAL ;
    PORT
      LAYER M1 ;
      RECT 0.05 0.1 0.10 0.2 ;
    END
  END A1
  PIN A2
    DIRECTION INPUT ;
    USE SIGNAL ;
    PORT
      LAYER M1 ;
      RECT 0.09 0.1 0.14 0.2 ;
    END
  END A2
  PIN B1
    DIRECTION INPUT ;
    USE SIGNAL ;
    PORT
      LAYER M1 ;
      RECT 0.14 0.1 0.19 0.2 ;
    END
  END B1
  PIN B2
    DIRECTION INPUT ;
    USE SIGNAL ;
    PORT
      LAYER M1 ;
      RECT 0.18 0.1 0.23 0.2 ;
    END
  END B2
  PIN C1
    DIRECTION INPUT ;
    USE SIGNAL ;
    PORT
      LAYER M1 ;
      RECT 0.22 0.1 0.27 0.2 ;
    END
  END C1
  PIN C2
    DIRECTION INPUT ;
    USE SIGNAL ;
    PORT
      LAYER M1 ;
      RECT 0.26 0.1 0.31 0.2 ;
    END
  END C2
  PIN ZN
    DIRECTION OUTPUT ;
    USE SIGNAL ;
    PORT
      LAYER M1 ;
      RECT 0.31 0.1 0.36 0.2 ;
    END
  END ZN
END OAI222D0
MACRO OAI222D2
  CLASS CORE ;
  ORIGIN 0.0 0.0 ;
  SIZE 0.45 BY 0.3 ;
  SYMMETRY X Y ;
  PIN A1
    DIRECTION INPUT ;
    USE SIGNAL ;
    PORT
      LAYER M1 ;
      RECT 0.05 0.1 0.10 0.2 ;
    END
  END A1
  PIN A2
    DIRECTION INPUT ;
    USE SIGNAL ;
    PORT
      LAYER M1 ;
      RECT 0.09 0.1 0.14 0.2 ;
    END
  END A2
  PIN B1
    DIRECTION INPUT ;
    USE SIGNAL ;
    PORT
      LAYER M1 ;
      RECT 0.14 0.1 0.19 0.2 ;
    END
  END B1
  PIN B2
    DIRECTION INPUT ;
    USE SIGNAL ;
    PORT
      LAYER M1 ;
      RECT 0.18 0.1 0.23 0.2 ;
    END
  END B2
  PIN C1
    DIRECTION INPUT ;
    USE SIGNAL ;
    PORT
      LAYER M1 ;
      RECT 0.22 0.1 0.27 0.2 ;
    END
  END C1
  PIN C2
    DIRECTION INPUT ;
    USE SIGNAL ;
    PORT
      LAYER M1 ;
      RECT 0.26 0.1 0.31 0.2 ;
    END
  END C2
  PIN ZN
    DIRECTION OUTPUT ;
    USE SIGNAL ;
    PORT
      LAYER M1 ;
      RECT 0.31 0.1 0.36 0.2 ;
    END
  END ZN
END OAI222D2
MACRO OAI222D4
  CLASS CORE ;
  ORIGIN 0.0 0.0 ;
  SIZE 0.45 BY 0.3 ;
  SYMMETRY X Y ;
  PIN A1
    DIRECTION INPUT ;
    USE SIGNAL ;
    PORT
      LAYER M1 ;
      RECT 0.05 0.1 0.10 0.2 ;
    END
  END A1
  PIN A2
    DIRECTION INPUT ;
    USE SIGNAL ;
    PORT
      LAYER M1 ;
      RECT 0.09 0.1 0.14 0.2 ;
    END
  END A2
  PIN B1
    DIRECTION INPUT ;
    USE SIGNAL ;
    PORT
      LAYER M1 ;
      RECT 0.14 0.1 0.19 0.2 ;
    END
  END B1
  PIN B2
    DIRECTION INPUT ;
    USE SIGNAL ;
    PORT
      LAYER M1 ;
      RECT 0.18 0.1 0.23 0.2 ;
    END
  END B2
  PIN C1
    DIRECTION INPUT ;
    USE SIGNAL ;
    PORT
      LAYER M1 ;
      RECT 0.22 0.1 0.27 0.2 ;
    END
  END C1
  PIN C2
    DIRECTION INPUT ;
    USE SIGNAL ;
    PORT
      LAYER M1 ;
      RECT 0.26 0.1 0.31 0.2 ;
    END
  END C2
  PIN ZN
    DIRECTION OUTPUT ;
    USE SIGNAL ;
    PORT
      LAYER M1 ;
      RECT 0.31 0.1 0.36 0.2 ;
    END
  END ZN
END OAI222D4
MACRO OAI22OPTPAD1
  CLASS CORE ;
  ORIGIN 0.0 0.0 ;
  SIZE 0.45 BY 0.3 ;
  SYMMETRY X Y ;
  PIN A1
    DIRECTION INPUT ;
    USE SIGNAL ;
    PORT
      LAYER M1 ;
      RECT 0.05 0.1 0.10 0.2 ;
    END
  END A1
  PIN A2
    DIRECTION INPUT ;
    USE SIGNAL ;
    PORT
      LAYER M1 ;
      RECT 0.11 0.1 0.16 0.2 ;
    END
  END A2
  PIN B1
    DIRECTION INPUT ;
    USE SIGNAL ;
    PORT
      LAYER M1 ;
      RECT 0.17 0.1 0.22 0.2 ;
    END
  END B1
  PIN B2
    DIRECTION INPUT ;
    USE SIGNAL ;
    PORT
      LAYER M1 ;
      RECT 0.23 0.1 0.28 0.2 ;
    END
  END B2
  PIN ZN
    DIRECTION OUTPUT ;
    USE SIGNAL ;
    PORT
      LAYER M1 ;
      RECT 0.29 0.1 0.34 0.2 ;
    END
  END ZN
END OAI22OPTPAD1
MACRO OAI22OPTPAD2
  CLASS CORE ;
  ORIGIN 0.0 0.0 ;
  SIZE 0.45 BY 0.3 ;
  SYMMETRY X Y ;
  PIN A1
    DIRECTION INPUT ;
    USE SIGNAL ;
    PORT
      LAYER M1 ;
      RECT 0.05 0.1 0.10 0.2 ;
    END
  END A1
  PIN A2
    DIRECTION INPUT ;
    USE SIGNAL ;
    PORT
      LAYER M1 ;
      RECT 0.11 0.1 0.16 0.2 ;
    END
  END A2
  PIN B1
    DIRECTION INPUT ;
    USE SIGNAL ;
    PORT
      LAYER M1 ;
      RECT 0.17 0.1 0.22 0.2 ;
    END
  END B1
  PIN B2
    DIRECTION INPUT ;
    USE SIGNAL ;
    PORT
      LAYER M1 ;
      RECT 0.23 0.1 0.28 0.2 ;
    END
  END B2
  PIN ZN
    DIRECTION OUTPUT ;
    USE SIGNAL ;
    PORT
      LAYER M1 ;
      RECT 0.29 0.1 0.34 0.2 ;
    END
  END ZN
END OAI22OPTPAD2
MACRO OAI22OPTPAD4
  CLASS CORE ;
  ORIGIN 0.0 0.0 ;
  SIZE 0.45 BY 0.3 ;
  SYMMETRY X Y ;
  PIN A1
    DIRECTION INPUT ;
    USE SIGNAL ;
    PORT
      LAYER M1 ;
      RECT 0.05 0.1 0.10 0.2 ;
    END
  END A1
  PIN A2
    DIRECTION INPUT ;
    USE SIGNAL ;
    PORT
      LAYER M1 ;
      RECT 0.11 0.1 0.16 0.2 ;
    END
  END A2
  PIN B1
    DIRECTION INPUT ;
    USE SIGNAL ;
    PORT
      LAYER M1 ;
      RECT 0.17 0.1 0.22 0.2 ;
    END
  END B1
  PIN B2
    DIRECTION INPUT ;
    USE SIGNAL ;
    PORT
      LAYER M1 ;
      RECT 0.23 0.1 0.28 0.2 ;
    END
  END B2
  PIN ZN
    DIRECTION OUTPUT ;
    USE SIGNAL ;
    PORT
      LAYER M1 ;
      RECT 0.29 0.1 0.34 0.2 ;
    END
  END ZN
END OAI22OPTPAD4
MACRO OAI22SKND1
  CLASS CORE ;
  ORIGIN 0.0 0.0 ;
  SIZE 0.45 BY 0.3 ;
  SYMMETRY X Y ;
  PIN A1
    DIRECTION INPUT ;
    USE SIGNAL ;
    PORT
      LAYER M1 ;
      RECT 0.05 0.1 0.10 0.2 ;
    END
  END A1
  PIN A2
    DIRECTION INPUT ;
    USE SIGNAL ;
    PORT
      LAYER M1 ;
      RECT 0.11 0.1 0.16 0.2 ;
    END
  END A2
  PIN B1
    DIRECTION INPUT ;
    USE SIGNAL ;
    PORT
      LAYER M1 ;
      RECT 0.17 0.1 0.22 0.2 ;
    END
  END B1
  PIN B2
    DIRECTION INPUT ;
    USE SIGNAL ;
    PORT
      LAYER M1 ;
      RECT 0.23 0.1 0.28 0.2 ;
    END
  END B2
  PIN ZN
    DIRECTION OUTPUT ;
    USE SIGNAL ;
    PORT
      LAYER M1 ;
      RECT 0.29 0.1 0.34 0.2 ;
    END
  END ZN
END OAI22SKND1
MACRO OAI22SKND2
  CLASS CORE ;
  ORIGIN 0.0 0.0 ;
  SIZE 0.45 BY 0.3 ;
  SYMMETRY X Y ;
  PIN A1
    DIRECTION INPUT ;
    USE SIGNAL ;
    PORT
      LAYER M1 ;
      RECT 0.05 0.1 0.10 0.2 ;
    END
  END A1
  PIN A2
    DIRECTION INPUT ;
    USE SIGNAL ;
    PORT
      LAYER M1 ;
      RECT 0.11 0.1 0.16 0.2 ;
    END
  END A2
  PIN B1
    DIRECTION INPUT ;
    USE SIGNAL ;
    PORT
      LAYER M1 ;
      RECT 0.17 0.1 0.22 0.2 ;
    END
  END B1
  PIN B2
    DIRECTION INPUT ;
    USE SIGNAL ;
    PORT
      LAYER M1 ;
      RECT 0.23 0.1 0.28 0.2 ;
    END
  END B2
  PIN ZN
    DIRECTION OUTPUT ;
    USE SIGNAL ;
    PORT
      LAYER M1 ;
      RECT 0.29 0.1 0.34 0.2 ;
    END
  END ZN
END OAI22SKND2
MACRO OAI22SKND3
  CLASS CORE ;
  ORIGIN 0.0 0.0 ;
  SIZE 0.45 BY 0.3 ;
  SYMMETRY X Y ;
  PIN A1
    DIRECTION INPUT ;
    USE SIGNAL ;
    PORT
      LAYER M1 ;
      RECT 0.05 0.1 0.10 0.2 ;
    END
  END A1
  PIN A2
    DIRECTION INPUT ;
    USE SIGNAL ;
    PORT
      LAYER M1 ;
      RECT 0.11 0.1 0.16 0.2 ;
    END
  END A2
  PIN B1
    DIRECTION INPUT ;
    USE SIGNAL ;
    PORT
      LAYER M1 ;
      RECT 0.17 0.1 0.22 0.2 ;
    END
  END B1
  PIN B2
    DIRECTION INPUT ;
    USE SIGNAL ;
    PORT
      LAYER M1 ;
      RECT 0.23 0.1 0.28 0.2 ;
    END
  END B2
  PIN ZN
    DIRECTION OUTPUT ;
    USE SIGNAL ;
    PORT
      LAYER M1 ;
      RECT 0.29 0.1 0.34 0.2 ;
    END
  END ZN
END OAI22SKND3
MACRO OAI22SKND4
  CLASS CORE ;
  ORIGIN 0.0 0.0 ;
  SIZE 0.45 BY 0.3 ;
  SYMMETRY X Y ;
  PIN A1
    DIRECTION INPUT ;
    USE SIGNAL ;
    PORT
      LAYER M1 ;
      RECT 0.05 0.1 0.10 0.2 ;
    END
  END A1
  PIN A2
    DIRECTION INPUT ;
    USE SIGNAL ;
    PORT
      LAYER M1 ;
      RECT 0.11 0.1 0.16 0.2 ;
    END
  END A2
  PIN B1
    DIRECTION INPUT ;
    USE SIGNAL ;
    PORT
      LAYER M1 ;
      RECT 0.17 0.1 0.22 0.2 ;
    END
  END B1
  PIN B2
    DIRECTION INPUT ;
    USE SIGNAL ;
    PORT
      LAYER M1 ;
      RECT 0.23 0.1 0.28 0.2 ;
    END
  END B2
  PIN ZN
    DIRECTION OUTPUT ;
    USE SIGNAL ;
    PORT
      LAYER M1 ;
      RECT 0.29 0.1 0.34 0.2 ;
    END
  END ZN
END OAI22SKND4
MACRO OAI22SKND6
  CLASS CORE ;
  ORIGIN 0.0 0.0 ;
  SIZE 0.45 BY 0.3 ;
  SYMMETRY X Y ;
  PIN A1
    DIRECTION INPUT ;
    USE SIGNAL ;
    PORT
      LAYER M1 ;
      RECT 0.05 0.1 0.10 0.2 ;
    END
  END A1
  PIN A2
    DIRECTION INPUT ;
    USE SIGNAL ;
    PORT
      LAYER M1 ;
      RECT 0.11 0.1 0.16 0.2 ;
    END
  END A2
  PIN B1
    DIRECTION INPUT ;
    USE SIGNAL ;
    PORT
      LAYER M1 ;
      RECT 0.17 0.1 0.22 0.2 ;
    END
  END B1
  PIN B2
    DIRECTION INPUT ;
    USE SIGNAL ;
    PORT
      LAYER M1 ;
      RECT 0.23 0.1 0.28 0.2 ;
    END
  END B2
  PIN ZN
    DIRECTION OUTPUT ;
    USE SIGNAL ;
    PORT
      LAYER M1 ;
      RECT 0.29 0.1 0.34 0.2 ;
    END
  END ZN
END OAI22SKND6
MACRO OAI22SKND8
  CLASS CORE ;
  ORIGIN 0.0 0.0 ;
  SIZE 0.45 BY 0.3 ;
  SYMMETRY X Y ;
  PIN A1
    DIRECTION INPUT ;
    USE SIGNAL ;
    PORT
      LAYER M1 ;
      RECT 0.05 0.1 0.10 0.2 ;
    END
  END A1
  PIN A2
    DIRECTION INPUT ;
    USE SIGNAL ;
    PORT
      LAYER M1 ;
      RECT 0.11 0.1 0.16 0.2 ;
    END
  END A2
  PIN B1
    DIRECTION INPUT ;
    USE SIGNAL ;
    PORT
      LAYER M1 ;
      RECT 0.17 0.1 0.22 0.2 ;
    END
  END B1
  PIN B2
    DIRECTION INPUT ;
    USE SIGNAL ;
    PORT
      LAYER M1 ;
      RECT 0.23 0.1 0.28 0.2 ;
    END
  END B2
  PIN ZN
    DIRECTION OUTPUT ;
    USE SIGNAL ;
    PORT
      LAYER M1 ;
      RECT 0.29 0.1 0.34 0.2 ;
    END
  END ZN
END OAI22SKND8
MACRO OAI22SKPD1
  CLASS CORE ;
  ORIGIN 0.0 0.0 ;
  SIZE 0.45 BY 0.3 ;
  SYMMETRY X Y ;
  PIN A1
    DIRECTION INPUT ;
    USE SIGNAL ;
    PORT
      LAYER M1 ;
      RECT 0.05 0.1 0.10 0.2 ;
    END
  END A1
  PIN A2
    DIRECTION INPUT ;
    USE SIGNAL ;
    PORT
      LAYER M1 ;
      RECT 0.11 0.1 0.16 0.2 ;
    END
  END A2
  PIN B1
    DIRECTION INPUT ;
    USE SIGNAL ;
    PORT
      LAYER M1 ;
      RECT 0.17 0.1 0.22 0.2 ;
    END
  END B1
  PIN B2
    DIRECTION INPUT ;
    USE SIGNAL ;
    PORT
      LAYER M1 ;
      RECT 0.23 0.1 0.28 0.2 ;
    END
  END B2
  PIN ZN
    DIRECTION OUTPUT ;
    USE SIGNAL ;
    PORT
      LAYER M1 ;
      RECT 0.29 0.1 0.34 0.2 ;
    END
  END ZN
END OAI22SKPD1
MACRO OAI22SKPD2
  CLASS CORE ;
  ORIGIN 0.0 0.0 ;
  SIZE 0.45 BY 0.3 ;
  SYMMETRY X Y ;
  PIN A1
    DIRECTION INPUT ;
    USE SIGNAL ;
    PORT
      LAYER M1 ;
      RECT 0.05 0.1 0.10 0.2 ;
    END
  END A1
  PIN A2
    DIRECTION INPUT ;
    USE SIGNAL ;
    PORT
      LAYER M1 ;
      RECT 0.11 0.1 0.16 0.2 ;
    END
  END A2
  PIN B1
    DIRECTION INPUT ;
    USE SIGNAL ;
    PORT
      LAYER M1 ;
      RECT 0.17 0.1 0.22 0.2 ;
    END
  END B1
  PIN B2
    DIRECTION INPUT ;
    USE SIGNAL ;
    PORT
      LAYER M1 ;
      RECT 0.23 0.1 0.28 0.2 ;
    END
  END B2
  PIN ZN
    DIRECTION OUTPUT ;
    USE SIGNAL ;
    PORT
      LAYER M1 ;
      RECT 0.29 0.1 0.34 0.2 ;
    END
  END ZN
END OAI22SKPD2
MACRO OAI311D1
  CLASS CORE ;
  ORIGIN 0.0 0.0 ;
  SIZE 0.45 BY 0.3 ;
  SYMMETRY X Y ;
  PIN A1
    DIRECTION INPUT ;
    USE SIGNAL ;
    PORT
      LAYER M1 ;
      RECT 0.05 0.1 0.10 0.2 ;
    END
  END A1
  PIN A2
    DIRECTION INPUT ;
    USE SIGNAL ;
    PORT
      LAYER M1 ;
      RECT 0.10 0.1 0.15 0.2 ;
    END
  END A2
  PIN A3
    DIRECTION INPUT ;
    USE SIGNAL ;
    PORT
      LAYER M1 ;
      RECT 0.15 0.1 0.20 0.2 ;
    END
  END A3
  PIN B
    DIRECTION INPUT ;
    USE SIGNAL ;
    PORT
      LAYER M1 ;
      RECT 0.20 0.1 0.25 0.2 ;
    END
  END B
  PIN C
    DIRECTION INPUT ;
    USE SIGNAL ;
    PORT
      LAYER M1 ;
      RECT 0.25 0.1 0.30 0.2 ;
    END
  END C
  PIN ZN
    DIRECTION OUTPUT ;
    USE SIGNAL ;
    PORT
      LAYER M1 ;
      RECT 0.30 0.1 0.35 0.2 ;
    END
  END ZN
END OAI311D1
MACRO OAI31D1
  CLASS CORE ;
  ORIGIN 0.0 0.0 ;
  SIZE 0.45 BY 0.3 ;
  SYMMETRY X Y ;
  PIN A1
    DIRECTION INPUT ;
    USE SIGNAL ;
    PORT
      LAYER M1 ;
      RECT 0.05 0.1 0.10 0.2 ;
    END
  END A1
  PIN A2
    DIRECTION INPUT ;
    USE SIGNAL ;
    PORT
      LAYER M1 ;
      RECT 0.11 0.1 0.16 0.2 ;
    END
  END A2
  PIN A3
    DIRECTION INPUT ;
    USE SIGNAL ;
    PORT
      LAYER M1 ;
      RECT 0.17 0.1 0.22 0.2 ;
    END
  END A3
  PIN B
    DIRECTION INPUT ;
    USE SIGNAL ;
    PORT
      LAYER M1 ;
      RECT 0.23 0.1 0.28 0.2 ;
    END
  END B
  PIN ZN
    DIRECTION OUTPUT ;
    USE SIGNAL ;
    PORT
      LAYER M1 ;
      RECT 0.29 0.1 0.34 0.2 ;
    END
  END ZN
END OAI31D1
MACRO OAI31SKND1
  CLASS CORE ;
  ORIGIN 0.0 0.0 ;
  SIZE 0.45 BY 0.3 ;
  SYMMETRY X Y ;
  PIN A1
    DIRECTION INPUT ;
    USE SIGNAL ;
    PORT
      LAYER M1 ;
      RECT 0.05 0.1 0.10 0.2 ;
    END
  END A1
  PIN A2
    DIRECTION INPUT ;
    USE SIGNAL ;
    PORT
      LAYER M1 ;
      RECT 0.11 0.1 0.16 0.2 ;
    END
  END A2
  PIN A3
    DIRECTION INPUT ;
    USE SIGNAL ;
    PORT
      LAYER M1 ;
      RECT 0.17 0.1 0.22 0.2 ;
    END
  END A3
  PIN B
    DIRECTION INPUT ;
    USE SIGNAL ;
    PORT
      LAYER M1 ;
      RECT 0.23 0.1 0.28 0.2 ;
    END
  END B
  PIN ZN
    DIRECTION OUTPUT ;
    USE SIGNAL ;
    PORT
      LAYER M1 ;
      RECT 0.29 0.1 0.34 0.2 ;
    END
  END ZN
END OAI31SKND1
MACRO OAI31SKND2
  CLASS CORE ;
  ORIGIN 0.0 0.0 ;
  SIZE 0.45 BY 0.3 ;
  SYMMETRY X Y ;
  PIN A1
    DIRECTION INPUT ;
    USE SIGNAL ;
    PORT
      LAYER M1 ;
      RECT 0.05 0.1 0.10 0.2 ;
    END
  END A1
  PIN A2
    DIRECTION INPUT ;
    USE SIGNAL ;
    PORT
      LAYER M1 ;
      RECT 0.11 0.1 0.16 0.2 ;
    END
  END A2
  PIN A3
    DIRECTION INPUT ;
    USE SIGNAL ;
    PORT
      LAYER M1 ;
      RECT 0.17 0.1 0.22 0.2 ;
    END
  END A3
  PIN B
    DIRECTION INPUT ;
    USE SIGNAL ;
    PORT
      LAYER M1 ;
      RECT 0.23 0.1 0.28 0.2 ;
    END
  END B
  PIN ZN
    DIRECTION OUTPUT ;
    USE SIGNAL ;
    PORT
      LAYER M1 ;
      RECT 0.29 0.1 0.34 0.2 ;
    END
  END ZN
END OAI31SKND2
MACRO OAI31SKND4
  CLASS CORE ;
  ORIGIN 0.0 0.0 ;
  SIZE 0.45 BY 0.3 ;
  SYMMETRY X Y ;
  PIN A1
    DIRECTION INPUT ;
    USE SIGNAL ;
    PORT
      LAYER M1 ;
      RECT 0.05 0.1 0.10 0.2 ;
    END
  END A1
  PIN A2
    DIRECTION INPUT ;
    USE SIGNAL ;
    PORT
      LAYER M1 ;
      RECT 0.11 0.1 0.16 0.2 ;
    END
  END A2
  PIN A3
    DIRECTION INPUT ;
    USE SIGNAL ;
    PORT
      LAYER M1 ;
      RECT 0.17 0.1 0.22 0.2 ;
    END
  END A3
  PIN B
    DIRECTION INPUT ;
    USE SIGNAL ;
    PORT
      LAYER M1 ;
      RECT 0.23 0.1 0.28 0.2 ;
    END
  END B
  PIN ZN
    DIRECTION OUTPUT ;
    USE SIGNAL ;
    PORT
      LAYER M1 ;
      RECT 0.29 0.1 0.34 0.2 ;
    END
  END ZN
END OAI31SKND4
MACRO OAI31SKNOPTLD4
  CLASS CORE ;
  ORIGIN 0.0 0.0 ;
  SIZE 0.45 BY 0.3 ;
  SYMMETRY X Y ;
  PIN A1
    DIRECTION INPUT ;
    USE SIGNAL ;
    PORT
      LAYER M1 ;
      RECT 0.05 0.1 0.10 0.2 ;
    END
  END A1
  PIN A2
    DIRECTION INPUT ;
    USE SIGNAL ;
    PORT
      LAYER M1 ;
      RECT 0.11 0.1 0.16 0.2 ;
    END
  END A2
  PIN A3
    DIRECTION INPUT ;
    USE SIGNAL ;
    PORT
      LAYER M1 ;
      RECT 0.17 0.1 0.22 0.2 ;
    END
  END A3
  PIN B
    DIRECTION INPUT ;
    USE SIGNAL ;
    PORT
      LAYER M1 ;
      RECT 0.23 0.1 0.28 0.2 ;
    END
  END B
  PIN ZN
    DIRECTION OUTPUT ;
    USE SIGNAL ;
    PORT
      LAYER M1 ;
      RECT 0.29 0.1 0.34 0.2 ;
    END
  END ZN
END OAI31SKNOPTLD4
MACRO OAI31SKPD1
  CLASS CORE ;
  ORIGIN 0.0 0.0 ;
  SIZE 0.45 BY 0.3 ;
  SYMMETRY X Y ;
  PIN A1
    DIRECTION INPUT ;
    USE SIGNAL ;
    PORT
      LAYER M1 ;
      RECT 0.05 0.1 0.10 0.2 ;
    END
  END A1
  PIN A2
    DIRECTION INPUT ;
    USE SIGNAL ;
    PORT
      LAYER M1 ;
      RECT 0.11 0.1 0.16 0.2 ;
    END
  END A2
  PIN A3
    DIRECTION INPUT ;
    USE SIGNAL ;
    PORT
      LAYER M1 ;
      RECT 0.17 0.1 0.22 0.2 ;
    END
  END A3
  PIN B
    DIRECTION INPUT ;
    USE SIGNAL ;
    PORT
      LAYER M1 ;
      RECT 0.23 0.1 0.28 0.2 ;
    END
  END B
  PIN ZN
    DIRECTION OUTPUT ;
    USE SIGNAL ;
    PORT
      LAYER M1 ;
      RECT 0.29 0.1 0.34 0.2 ;
    END
  END ZN
END OAI31SKPD1
MACRO OAI31SKPD2
  CLASS CORE ;
  ORIGIN 0.0 0.0 ;
  SIZE 0.45 BY 0.3 ;
  SYMMETRY X Y ;
  PIN A1
    DIRECTION INPUT ;
    USE SIGNAL ;
    PORT
      LAYER M1 ;
      RECT 0.05 0.1 0.10 0.2 ;
    END
  END A1
  PIN A2
    DIRECTION INPUT ;
    USE SIGNAL ;
    PORT
      LAYER M1 ;
      RECT 0.11 0.1 0.16 0.2 ;
    END
  END A2
  PIN A3
    DIRECTION INPUT ;
    USE SIGNAL ;
    PORT
      LAYER M1 ;
      RECT 0.17 0.1 0.22 0.2 ;
    END
  END A3
  PIN B
    DIRECTION INPUT ;
    USE SIGNAL ;
    PORT
      LAYER M1 ;
      RECT 0.23 0.1 0.28 0.2 ;
    END
  END B
  PIN ZN
    DIRECTION OUTPUT ;
    USE SIGNAL ;
    PORT
      LAYER M1 ;
      RECT 0.29 0.1 0.34 0.2 ;
    END
  END ZN
END OAI31SKPD2
MACRO OAI32D0
  CLASS CORE ;
  ORIGIN 0.0 0.0 ;
  SIZE 0.45 BY 0.3 ;
  SYMMETRY X Y ;
  PIN A1
    DIRECTION INPUT ;
    USE SIGNAL ;
    PORT
      LAYER M1 ;
      RECT 0.05 0.1 0.10 0.2 ;
    END
  END A1
  PIN A2
    DIRECTION INPUT ;
    USE SIGNAL ;
    PORT
      LAYER M1 ;
      RECT 0.10 0.1 0.15 0.2 ;
    END
  END A2
  PIN A3
    DIRECTION INPUT ;
    USE SIGNAL ;
    PORT
      LAYER M1 ;
      RECT 0.15 0.1 0.20 0.2 ;
    END
  END A3
  PIN B1
    DIRECTION INPUT ;
    USE SIGNAL ;
    PORT
      LAYER M1 ;
      RECT 0.20 0.1 0.25 0.2 ;
    END
  END B1
  PIN B2
    DIRECTION INPUT ;
    USE SIGNAL ;
    PORT
      LAYER M1 ;
      RECT 0.25 0.1 0.30 0.2 ;
    END
  END B2
  PIN ZN
    DIRECTION OUTPUT ;
    USE SIGNAL ;
    PORT
      LAYER M1 ;
      RECT 0.30 0.1 0.35 0.2 ;
    END
  END ZN
END OAI32D0
MACRO OAI32D1
  CLASS CORE ;
  ORIGIN 0.0 0.0 ;
  SIZE 0.45 BY 0.3 ;
  SYMMETRY X Y ;
  PIN A1
    DIRECTION INPUT ;
    USE SIGNAL ;
    PORT
      LAYER M1 ;
      RECT 0.05 0.1 0.10 0.2 ;
    END
  END A1
  PIN A2
    DIRECTION INPUT ;
    USE SIGNAL ;
    PORT
      LAYER M1 ;
      RECT 0.10 0.1 0.15 0.2 ;
    END
  END A2
  PIN A3
    DIRECTION INPUT ;
    USE SIGNAL ;
    PORT
      LAYER M1 ;
      RECT 0.15 0.1 0.20 0.2 ;
    END
  END A3
  PIN B1
    DIRECTION INPUT ;
    USE SIGNAL ;
    PORT
      LAYER M1 ;
      RECT 0.20 0.1 0.25 0.2 ;
    END
  END B1
  PIN B2
    DIRECTION INPUT ;
    USE SIGNAL ;
    PORT
      LAYER M1 ;
      RECT 0.25 0.1 0.30 0.2 ;
    END
  END B2
  PIN ZN
    DIRECTION OUTPUT ;
    USE SIGNAL ;
    PORT
      LAYER M1 ;
      RECT 0.30 0.1 0.35 0.2 ;
    END
  END ZN
END OAI32D1
MACRO OAI33D0
  CLASS CORE ;
  ORIGIN 0.0 0.0 ;
  SIZE 0.45 BY 0.3 ;
  SYMMETRY X Y ;
  PIN A1
    DIRECTION INPUT ;
    USE SIGNAL ;
    PORT
      LAYER M1 ;
      RECT 0.05 0.1 0.10 0.2 ;
    END
  END A1
  PIN A2
    DIRECTION INPUT ;
    USE SIGNAL ;
    PORT
      LAYER M1 ;
      RECT 0.09 0.1 0.14 0.2 ;
    END
  END A2
  PIN A3
    DIRECTION INPUT ;
    USE SIGNAL ;
    PORT
      LAYER M1 ;
      RECT 0.14 0.1 0.19 0.2 ;
    END
  END A3
  PIN B1
    DIRECTION INPUT ;
    USE SIGNAL ;
    PORT
      LAYER M1 ;
      RECT 0.18 0.1 0.23 0.2 ;
    END
  END B1
  PIN B2
    DIRECTION INPUT ;
    USE SIGNAL ;
    PORT
      LAYER M1 ;
      RECT 0.22 0.1 0.27 0.2 ;
    END
  END B2
  PIN B3
    DIRECTION INPUT ;
    USE SIGNAL ;
    PORT
      LAYER M1 ;
      RECT 0.26 0.1 0.31 0.2 ;
    END
  END B3
  PIN ZN
    DIRECTION OUTPUT ;
    USE SIGNAL ;
    PORT
      LAYER M1 ;
      RECT 0.31 0.1 0.36 0.2 ;
    END
  END ZN
END OAI33D0
MACRO OAI33D2
  CLASS CORE ;
  ORIGIN 0.0 0.0 ;
  SIZE 0.45 BY 0.3 ;
  SYMMETRY X Y ;
  PIN A1
    DIRECTION INPUT ;
    USE SIGNAL ;
    PORT
      LAYER M1 ;
      RECT 0.05 0.1 0.10 0.2 ;
    END
  END A1
  PIN A2
    DIRECTION INPUT ;
    USE SIGNAL ;
    PORT
      LAYER M1 ;
      RECT 0.09 0.1 0.14 0.2 ;
    END
  END A2
  PIN A3
    DIRECTION INPUT ;
    USE SIGNAL ;
    PORT
      LAYER M1 ;
      RECT 0.14 0.1 0.19 0.2 ;
    END
  END A3
  PIN B1
    DIRECTION INPUT ;
    USE SIGNAL ;
    PORT
      LAYER M1 ;
      RECT 0.18 0.1 0.23 0.2 ;
    END
  END B1
  PIN B2
    DIRECTION INPUT ;
    USE SIGNAL ;
    PORT
      LAYER M1 ;
      RECT 0.22 0.1 0.27 0.2 ;
    END
  END B2
  PIN B3
    DIRECTION INPUT ;
    USE SIGNAL ;
    PORT
      LAYER M1 ;
      RECT 0.26 0.1 0.31 0.2 ;
    END
  END B3
  PIN ZN
    DIRECTION OUTPUT ;
    USE SIGNAL ;
    PORT
      LAYER M1 ;
      RECT 0.31 0.1 0.36 0.2 ;
    END
  END ZN
END OAI33D2
MACRO OAI33D4
  CLASS CORE ;
  ORIGIN 0.0 0.0 ;
  SIZE 0.45 BY 0.3 ;
  SYMMETRY X Y ;
  PIN A1
    DIRECTION INPUT ;
    USE SIGNAL ;
    PORT
      LAYER M1 ;
      RECT 0.05 0.1 0.10 0.2 ;
    END
  END A1
  PIN A2
    DIRECTION INPUT ;
    USE SIGNAL ;
    PORT
      LAYER M1 ;
      RECT 0.09 0.1 0.14 0.2 ;
    END
  END A2
  PIN A3
    DIRECTION INPUT ;
    USE SIGNAL ;
    PORT
      LAYER M1 ;
      RECT 0.14 0.1 0.19 0.2 ;
    END
  END A3
  PIN B1
    DIRECTION INPUT ;
    USE SIGNAL ;
    PORT
      LAYER M1 ;
      RECT 0.18 0.1 0.23 0.2 ;
    END
  END B1
  PIN B2
    DIRECTION INPUT ;
    USE SIGNAL ;
    PORT
      LAYER M1 ;
      RECT 0.22 0.1 0.27 0.2 ;
    END
  END B2
  PIN B3
    DIRECTION INPUT ;
    USE SIGNAL ;
    PORT
      LAYER M1 ;
      RECT 0.26 0.1 0.31 0.2 ;
    END
  END B3
  PIN ZN
    DIRECTION OUTPUT ;
    USE SIGNAL ;
    PORT
      LAYER M1 ;
      RECT 0.31 0.1 0.36 0.2 ;
    END
  END ZN
END OAI33D4
MACRO OAOI211D1
  CLASS CORE ;
  ORIGIN 0.0 0.0 ;
  SIZE 0.45 BY 0.3 ;
  SYMMETRY X Y ;
  PIN A1
    DIRECTION INPUT ;
    USE SIGNAL ;
    PORT
      LAYER M1 ;
      RECT 0.05 0.1 0.10 0.2 ;
    END
  END A1
  PIN A2
    DIRECTION INPUT ;
    USE SIGNAL ;
    PORT
      LAYER M1 ;
      RECT 0.11 0.1 0.16 0.2 ;
    END
  END A2
  PIN B
    DIRECTION INPUT ;
    USE SIGNAL ;
    PORT
      LAYER M1 ;
      RECT 0.17 0.1 0.22 0.2 ;
    END
  END B
  PIN C
    DIRECTION INPUT ;
    USE SIGNAL ;
    PORT
      LAYER M1 ;
      RECT 0.23 0.1 0.28 0.2 ;
    END
  END C
  PIN ZN
    DIRECTION OUTPUT ;
    USE SIGNAL ;
    PORT
      LAYER M1 ;
      RECT 0.29 0.1 0.34 0.2 ;
    END
  END ZN
END OAOI211D1
MACRO OAOI211D2
  CLASS CORE ;
  ORIGIN 0.0 0.0 ;
  SIZE 0.45 BY 0.3 ;
  SYMMETRY X Y ;
  PIN A1
    DIRECTION INPUT ;
    USE SIGNAL ;
    PORT
      LAYER M1 ;
      RECT 0.05 0.1 0.10 0.2 ;
    END
  END A1
  PIN A2
    DIRECTION INPUT ;
    USE SIGNAL ;
    PORT
      LAYER M1 ;
      RECT 0.11 0.1 0.16 0.2 ;
    END
  END A2
  PIN B
    DIRECTION INPUT ;
    USE SIGNAL ;
    PORT
      LAYER M1 ;
      RECT 0.17 0.1 0.22 0.2 ;
    END
  END B
  PIN C
    DIRECTION INPUT ;
    USE SIGNAL ;
    PORT
      LAYER M1 ;
      RECT 0.23 0.1 0.28 0.2 ;
    END
  END C
  PIN ZN
    DIRECTION OUTPUT ;
    USE SIGNAL ;
    PORT
      LAYER M1 ;
      RECT 0.29 0.1 0.34 0.2 ;
    END
  END ZN
END OAOI211D2
MACRO OAOI211D4
  CLASS CORE ;
  ORIGIN 0.0 0.0 ;
  SIZE 0.45 BY 0.3 ;
  SYMMETRY X Y ;
  PIN A1
    DIRECTION INPUT ;
    USE SIGNAL ;
    PORT
      LAYER M1 ;
      RECT 0.05 0.1 0.10 0.2 ;
    END
  END A1
  PIN A2
    DIRECTION INPUT ;
    USE SIGNAL ;
    PORT
      LAYER M1 ;
      RECT 0.11 0.1 0.16 0.2 ;
    END
  END A2
  PIN B
    DIRECTION INPUT ;
    USE SIGNAL ;
    PORT
      LAYER M1 ;
      RECT 0.17 0.1 0.22 0.2 ;
    END
  END B
  PIN C
    DIRECTION INPUT ;
    USE SIGNAL ;
    PORT
      LAYER M1 ;
      RECT 0.23 0.1 0.28 0.2 ;
    END
  END C
  PIN ZN
    DIRECTION OUTPUT ;
    USE SIGNAL ;
    PORT
      LAYER M1 ;
      RECT 0.29 0.1 0.34 0.2 ;
    END
  END ZN
END OAOI211D4
MACRO OIAI21D1
  CLASS CORE ;
  ORIGIN 0.0 0.0 ;
  SIZE 0.45 BY 0.3 ;
  SYMMETRY X Y ;
  PIN A1
    DIRECTION INPUT ;
    USE SIGNAL ;
    PORT
      LAYER M1 ;
      RECT 0.05 0.1 0.10 0.2 ;
    END
  END A1
  PIN A2
    DIRECTION INPUT ;
    USE SIGNAL ;
    PORT
      LAYER M1 ;
      RECT 0.12 0.1 0.17 0.2 ;
    END
  END A2
  PIN B
    DIRECTION INPUT ;
    USE SIGNAL ;
    PORT
      LAYER M1 ;
      RECT 0.20 0.1 0.25 0.2 ;
    END
  END B
  PIN ZN
    DIRECTION OUTPUT ;
    USE SIGNAL ;
    PORT
      LAYER M1 ;
      RECT 0.27 0.1 0.32 0.2 ;
    END
  END ZN
END OIAI21D1
MACRO OIAI21D2
  CLASS CORE ;
  ORIGIN 0.0 0.0 ;
  SIZE 0.45 BY 0.3 ;
  SYMMETRY X Y ;
  PIN A1
    DIRECTION INPUT ;
    USE SIGNAL ;
    PORT
      LAYER M1 ;
      RECT 0.05 0.1 0.10 0.2 ;
    END
  END A1
  PIN A2
    DIRECTION INPUT ;
    USE SIGNAL ;
    PORT
      LAYER M1 ;
      RECT 0.12 0.1 0.17 0.2 ;
    END
  END A2
  PIN B
    DIRECTION INPUT ;
    USE SIGNAL ;
    PORT
      LAYER M1 ;
      RECT 0.20 0.1 0.25 0.2 ;
    END
  END B
  PIN ZN
    DIRECTION OUTPUT ;
    USE SIGNAL ;
    PORT
      LAYER M1 ;
      RECT 0.27 0.1 0.32 0.2 ;
    END
  END ZN
END OIAI21D2
MACRO OIAI21D4
  CLASS CORE ;
  ORIGIN 0.0 0.0 ;
  SIZE 0.45 BY 0.3 ;
  SYMMETRY X Y ;
  PIN A1
    DIRECTION INPUT ;
    USE SIGNAL ;
    PORT
      LAYER M1 ;
      RECT 0.05 0.1 0.10 0.2 ;
    END
  END A1
  PIN A2
    DIRECTION INPUT ;
    USE SIGNAL ;
    PORT
      LAYER M1 ;
      RECT 0.12 0.1 0.17 0.2 ;
    END
  END A2
  PIN B
    DIRECTION INPUT ;
    USE SIGNAL ;
    PORT
      LAYER M1 ;
      RECT 0.20 0.1 0.25 0.2 ;
    END
  END B
  PIN ZN
    DIRECTION OUTPUT ;
    USE SIGNAL ;
    PORT
      LAYER M1 ;
      RECT 0.27 0.1 0.32 0.2 ;
    END
  END ZN
END OIAI21D4
MACRO OR2D1
  CLASS CORE ;
  ORIGIN 0.0 0.0 ;
  SIZE 0.45 BY 0.3 ;
  SYMMETRY X Y ;
  PIN A1
    DIRECTION INPUT ;
    USE SIGNAL ;
    PORT
      LAYER M1 ;
      RECT 0.05 0.1 0.10 0.2 ;
    END
  END A1
  PIN A2
    DIRECTION INPUT ;
    USE SIGNAL ;
    PORT
      LAYER M1 ;
      RECT 0.15 0.1 0.20 0.2 ;
    END
  END A2
  PIN Z
    DIRECTION OUTPUT ;
    USE SIGNAL ;
    PORT
      LAYER M1 ;
      RECT 0.25 0.1 0.30 0.2 ;
    END
  END Z
END OR2D1
MACRO OR2D2
  CLASS CORE ;
  ORIGIN 0.0 0.0 ;
  SIZE 0.45 BY 0.3 ;
  SYMMETRY X Y ;
  PIN A1
    DIRECTION INPUT ;
    USE SIGNAL ;
    PORT
      LAYER M1 ;
      RECT 0.05 0.1 0.10 0.2 ;
    END
  END A1
  PIN A2
    DIRECTION INPUT ;
    USE SIGNAL ;
    PORT
      LAYER M1 ;
      RECT 0.15 0.1 0.20 0.2 ;
    END
  END A2
  PIN Z
    DIRECTION OUTPUT ;
    USE SIGNAL ;
    PORT
      LAYER M1 ;
      RECT 0.25 0.1 0.30 0.2 ;
    END
  END Z
END OR2D2
MACRO OR2D3
  CLASS CORE ;
  ORIGIN 0.0 0.0 ;
  SIZE 0.45 BY 0.3 ;
  SYMMETRY X Y ;
  PIN A1
    DIRECTION INPUT ;
    USE SIGNAL ;
    PORT
      LAYER M1 ;
      RECT 0.05 0.1 0.10 0.2 ;
    END
  END A1
  PIN A2
    DIRECTION INPUT ;
    USE SIGNAL ;
    PORT
      LAYER M1 ;
      RECT 0.15 0.1 0.20 0.2 ;
    END
  END A2
  PIN Z
    DIRECTION OUTPUT ;
    USE SIGNAL ;
    PORT
      LAYER M1 ;
      RECT 0.25 0.1 0.30 0.2 ;
    END
  END Z
END OR2D3
MACRO OR2OPTLD4
  CLASS CORE ;
  ORIGIN 0.0 0.0 ;
  SIZE 0.45 BY 0.3 ;
  SYMMETRY X Y ;
  PIN A1
    DIRECTION INPUT ;
    USE SIGNAL ;
    PORT
      LAYER M1 ;
      RECT 0.05 0.1 0.10 0.2 ;
    END
  END A1
  PIN A2
    DIRECTION INPUT ;
    USE SIGNAL ;
    PORT
      LAYER M1 ;
      RECT 0.15 0.1 0.20 0.2 ;
    END
  END A2
  PIN Z
    DIRECTION OUTPUT ;
    USE SIGNAL ;
    PORT
      LAYER M1 ;
      RECT 0.25 0.1 0.30 0.2 ;
    END
  END Z
END OR2OPTLD4
MACRO OR2OPTLD6
  CLASS CORE ;
  ORIGIN 0.0 0.0 ;
  SIZE 0.45 BY 0.3 ;
  SYMMETRY X Y ;
  PIN A1
    DIRECTION INPUT ;
    USE SIGNAL ;
    PORT
      LAYER M1 ;
      RECT 0.05 0.1 0.10 0.2 ;
    END
  END A1
  PIN A2
    DIRECTION INPUT ;
    USE SIGNAL ;
    PORT
      LAYER M1 ;
      RECT 0.15 0.1 0.20 0.2 ;
    END
  END A2
  PIN Z
    DIRECTION OUTPUT ;
    USE SIGNAL ;
    PORT
      LAYER M1 ;
      RECT 0.25 0.1 0.30 0.2 ;
    END
  END Z
END OR2OPTLD6
MACRO OR2OPTLD8
  CLASS CORE ;
  ORIGIN 0.0 0.0 ;
  SIZE 0.45 BY 0.3 ;
  SYMMETRY X Y ;
  PIN A1
    DIRECTION INPUT ;
    USE SIGNAL ;
    PORT
      LAYER M1 ;
      RECT 0.05 0.1 0.10 0.2 ;
    END
  END A1
  PIN A2
    DIRECTION INPUT ;
    USE SIGNAL ;
    PORT
      LAYER M1 ;
      RECT 0.15 0.1 0.20 0.2 ;
    END
  END A2
  PIN Z
    DIRECTION OUTPUT ;
    USE SIGNAL ;
    PORT
      LAYER M1 ;
      RECT 0.25 0.1 0.30 0.2 ;
    END
  END Z
END OR2OPTLD8
MACRO OR3D1
  CLASS CORE ;
  ORIGIN 0.0 0.0 ;
  SIZE 0.6 BY 0.3 ;
  SYMMETRY X Y ;
  PIN A1
    DIRECTION INPUT ;
    USE SIGNAL ;
    PORT
      LAYER M1 ;
      RECT 0.05 0.1 0.10 0.2 ;
    END
  END A1
  PIN A2
    DIRECTION INPUT ;
    USE SIGNAL ;
    PORT
      LAYER M1 ;
      RECT 0.12 0.1 0.17 0.2 ;
    END
  END A2
  PIN A3
    DIRECTION INPUT ;
    USE SIGNAL ;
    PORT
      LAYER M1 ;
      RECT 0.20 0.1 0.25 0.2 ;
    END
  END A3
  PIN Z
    DIRECTION OUTPUT ;
    USE SIGNAL ;
    PORT
      LAYER M1 ;
      RECT 0.27 0.1 0.32 0.2 ;
    END
  END Z
END OR3D1
MACRO OR3D2
  CLASS CORE ;
  ORIGIN 0.0 0.0 ;
  SIZE 0.6 BY 0.3 ;
  SYMMETRY X Y ;
  PIN A1
    DIRECTION INPUT ;
    USE SIGNAL ;
    PORT
      LAYER M1 ;
      RECT 0.05 0.1 0.10 0.2 ;
    END
  END A1
  PIN A2
    DIRECTION INPUT ;
    USE SIGNAL ;
    PORT
      LAYER M1 ;
      RECT 0.12 0.1 0.17 0.2 ;
    END
  END A2
  PIN A3
    DIRECTION INPUT ;
    USE SIGNAL ;
    PORT
      LAYER M1 ;
      RECT 0.20 0.1 0.25 0.2 ;
    END
  END A3
  PIN Z
    DIRECTION OUTPUT ;
    USE SIGNAL ;
    PORT
      LAYER M1 ;
      RECT 0.27 0.1 0.32 0.2 ;
    END
  END Z
END OR3D2
MACRO OR3OPTLD4
  CLASS CORE ;
  ORIGIN 0.0 0.0 ;
  SIZE 0.6 BY 0.3 ;
  SYMMETRY X Y ;
  PIN A1
    DIRECTION INPUT ;
    USE SIGNAL ;
    PORT
      LAYER M1 ;
      RECT 0.05 0.1 0.10 0.2 ;
    END
  END A1
  PIN A2
    DIRECTION INPUT ;
    USE SIGNAL ;
    PORT
      LAYER M1 ;
      RECT 0.12 0.1 0.17 0.2 ;
    END
  END A2
  PIN A3
    DIRECTION INPUT ;
    USE SIGNAL ;
    PORT
      LAYER M1 ;
      RECT 0.20 0.1 0.25 0.2 ;
    END
  END A3
  PIN Z
    DIRECTION OUTPUT ;
    USE SIGNAL ;
    PORT
      LAYER M1 ;
      RECT 0.27 0.1 0.32 0.2 ;
    END
  END Z
END OR3OPTLD4
MACRO OR3OPTLD6
  CLASS CORE ;
  ORIGIN 0.0 0.0 ;
  SIZE 0.6 BY 0.3 ;
  SYMMETRY X Y ;
  PIN A1
    DIRECTION INPUT ;
    USE SIGNAL ;
    PORT
      LAYER M1 ;
      RECT 0.05 0.1 0.10 0.2 ;
    END
  END A1
  PIN A2
    DIRECTION INPUT ;
    USE SIGNAL ;
    PORT
      LAYER M1 ;
      RECT 0.12 0.1 0.17 0.2 ;
    END
  END A2
  PIN A3
    DIRECTION INPUT ;
    USE SIGNAL ;
    PORT
      LAYER M1 ;
      RECT 0.20 0.1 0.25 0.2 ;
    END
  END A3
  PIN Z
    DIRECTION OUTPUT ;
    USE SIGNAL ;
    PORT
      LAYER M1 ;
      RECT 0.27 0.1 0.32 0.2 ;
    END
  END Z
END OR3OPTLD6
MACRO OR3OPTLD8
  CLASS CORE ;
  ORIGIN 0.0 0.0 ;
  SIZE 0.6 BY 0.3 ;
  SYMMETRY X Y ;
  PIN A1
    DIRECTION INPUT ;
    USE SIGNAL ;
    PORT
      LAYER M1 ;
      RECT 0.05 0.1 0.10 0.2 ;
    END
  END A1
  PIN A2
    DIRECTION INPUT ;
    USE SIGNAL ;
    PORT
      LAYER M1 ;
      RECT 0.12 0.1 0.17 0.2 ;
    END
  END A2
  PIN A3
    DIRECTION INPUT ;
    USE SIGNAL ;
    PORT
      LAYER M1 ;
      RECT 0.20 0.1 0.25 0.2 ;
    END
  END A3
  PIN Z
    DIRECTION OUTPUT ;
    USE SIGNAL ;
    PORT
      LAYER M1 ;
      RECT 0.27 0.1 0.32 0.2 ;
    END
  END Z
END OR3OPTLD8
MACRO OR4D0
  CLASS CORE ;
  ORIGIN 0.0 0.0 ;
  SIZE 0.75 BY 0.3 ;
  SYMMETRY X Y ;
  PIN A1
    DIRECTION INPUT ;
    USE SIGNAL ;
    PORT
      LAYER M1 ;
      RECT 0.05 0.1 0.10 0.2 ;
    END
  END A1
  PIN A2
    DIRECTION INPUT ;
    USE SIGNAL ;
    PORT
      LAYER M1 ;
      RECT 0.11 0.1 0.16 0.2 ;
    END
  END A2
  PIN A3
    DIRECTION INPUT ;
    USE SIGNAL ;
    PORT
      LAYER M1 ;
      RECT 0.17 0.1 0.22 0.2 ;
    END
  END A3
  PIN A4
    DIRECTION INPUT ;
    USE SIGNAL ;
    PORT
      LAYER M1 ;
      RECT 0.23 0.1 0.28 0.2 ;
    END
  END A4
  PIN Z
    DIRECTION OUTPUT ;
    USE SIGNAL ;
    PORT
      LAYER M1 ;
      RECT 0.29 0.1 0.34 0.2 ;
    END
  END Z
END OR4D0
MACRO OR4D3
  CLASS CORE ;
  ORIGIN 0.0 0.0 ;
  SIZE 0.75 BY 0.3 ;
  SYMMETRY X Y ;
  PIN A1
    DIRECTION INPUT ;
    USE SIGNAL ;
    PORT
      LAYER M1 ;
      RECT 0.05 0.1 0.10 0.2 ;
    END
  END A1
  PIN A2
    DIRECTION INPUT ;
    USE SIGNAL ;
    PORT
      LAYER M1 ;
      RECT 0.11 0.1 0.16 0.2 ;
    END
  END A2
  PIN A3
    DIRECTION INPUT ;
    USE SIGNAL ;
    PORT
      LAYER M1 ;
      RECT 0.17 0.1 0.22 0.2 ;
    END
  END A3
  PIN A4
    DIRECTION INPUT ;
    USE SIGNAL ;
    PORT
      LAYER M1 ;
      RECT 0.23 0.1 0.28 0.2 ;
    END
  END A4
  PIN Z
    DIRECTION OUTPUT ;
    USE SIGNAL ;
    PORT
      LAYER M1 ;
      RECT 0.29 0.1 0.34 0.2 ;
    END
  END Z
END OR4D3
MACRO OR4OPTLD1
  CLASS CORE ;
  ORIGIN 0.0 0.0 ;
  SIZE 0.75 BY 0.3 ;
  SYMMETRY X Y ;
  PIN A1
    DIRECTION INPUT ;
    USE SIGNAL ;
    PORT
      LAYER M1 ;
      RECT 0.05 0.1 0.10 0.2 ;
    END
  END A1
  PIN A2
    DIRECTION INPUT ;
    USE SIGNAL ;
    PORT
      LAYER M1 ;
      RECT 0.11 0.1 0.16 0.2 ;
    END
  END A2
  PIN A3
    DIRECTION INPUT ;
    USE SIGNAL ;
    PORT
      LAYER M1 ;
      RECT 0.17 0.1 0.22 0.2 ;
    END
  END A3
  PIN A4
    DIRECTION INPUT ;
    USE SIGNAL ;
    PORT
      LAYER M1 ;
      RECT 0.23 0.1 0.28 0.2 ;
    END
  END A4
  PIN Z
    DIRECTION OUTPUT ;
    USE SIGNAL ;
    PORT
      LAYER M1 ;
      RECT 0.29 0.1 0.34 0.2 ;
    END
  END Z
END OR4OPTLD1
MACRO OR4OPTLD2
  CLASS CORE ;
  ORIGIN 0.0 0.0 ;
  SIZE 0.75 BY 0.3 ;
  SYMMETRY X Y ;
  PIN A1
    DIRECTION INPUT ;
    USE SIGNAL ;
    PORT
      LAYER M1 ;
      RECT 0.05 0.1 0.10 0.2 ;
    END
  END A1
  PIN A2
    DIRECTION INPUT ;
    USE SIGNAL ;
    PORT
      LAYER M1 ;
      RECT 0.11 0.1 0.16 0.2 ;
    END
  END A2
  PIN A3
    DIRECTION INPUT ;
    USE SIGNAL ;
    PORT
      LAYER M1 ;
      RECT 0.17 0.1 0.22 0.2 ;
    END
  END A3
  PIN A4
    DIRECTION INPUT ;
    USE SIGNAL ;
    PORT
      LAYER M1 ;
      RECT 0.23 0.1 0.28 0.2 ;
    END
  END A4
  PIN Z
    DIRECTION OUTPUT ;
    USE SIGNAL ;
    PORT
      LAYER M1 ;
      RECT 0.29 0.1 0.34 0.2 ;
    END
  END Z
END OR4OPTLD2
MACRO OR4OPTLD6
  CLASS CORE ;
  ORIGIN 0.0 0.0 ;
  SIZE 0.75 BY 0.3 ;
  SYMMETRY X Y ;
  PIN A1
    DIRECTION INPUT ;
    USE SIGNAL ;
    PORT
      LAYER M1 ;
      RECT 0.05 0.1 0.10 0.2 ;
    END
  END A1
  PIN A2
    DIRECTION INPUT ;
    USE SIGNAL ;
    PORT
      LAYER M1 ;
      RECT 0.11 0.1 0.16 0.2 ;
    END
  END A2
  PIN A3
    DIRECTION INPUT ;
    USE SIGNAL ;
    PORT
      LAYER M1 ;
      RECT 0.17 0.1 0.22 0.2 ;
    END
  END A3
  PIN A4
    DIRECTION INPUT ;
    USE SIGNAL ;
    PORT
      LAYER M1 ;
      RECT 0.23 0.1 0.28 0.2 ;
    END
  END A4
  PIN Z
    DIRECTION OUTPUT ;
    USE SIGNAL ;
    PORT
      LAYER M1 ;
      RECT 0.29 0.1 0.34 0.2 ;
    END
  END Z
END OR4OPTLD6
MACRO SDFKRPQD0
  CLASS CORE ;
  ORIGIN 0.0 0.0 ;
  SIZE 0.45 BY 0.3 ;
  SYMMETRY X Y ;
  PIN C
    DIRECTION INPUT ;
    USE SIGNAL ;
    PORT
      LAYER M1 ;
      RECT 0.05 0.1 0.10 0.2 ;
    END
  END C
  PIN CP
    DIRECTION INPUT ;
    USE SIGNAL ;
    PORT
      LAYER M1 ;
      RECT 0.10 0.1 0.15 0.2 ;
    END
  END CP
  PIN D
    DIRECTION INPUT ;
    USE SIGNAL ;
    PORT
      LAYER M1 ;
      RECT 0.15 0.1 0.20 0.2 ;
    END
  END D
  PIN Q
    DIRECTION OUTPUT ;
    USE SIGNAL ;
    PORT
      LAYER M1 ;
      RECT 0.20 0.1 0.25 0.2 ;
    END
  END Q
  PIN SE
    DIRECTION INPUT ;
    USE SIGNAL ;
    PORT
      LAYER M1 ;
      RECT 0.25 0.1 0.30 0.2 ;
    END
  END SE
  PIN SI
    DIRECTION INPUT ;
    USE SIGNAL ;
    PORT
      LAYER M1 ;
      RECT 0.30 0.1 0.35 0.2 ;
    END
  END SI
END SDFKRPQD0
MACRO SDFKRPQD1
  CLASS CORE ;
  ORIGIN 0.0 0.0 ;
  SIZE 0.45 BY 0.3 ;
  SYMMETRY X Y ;
  PIN C
    DIRECTION INPUT ;
    USE SIGNAL ;
    PORT
      LAYER M1 ;
      RECT 0.05 0.1 0.10 0.2 ;
    END
  END C
  PIN CP
    DIRECTION INPUT ;
    USE SIGNAL ;
    PORT
      LAYER M1 ;
      RECT 0.10 0.1 0.15 0.2 ;
    END
  END CP
  PIN D
    DIRECTION INPUT ;
    USE SIGNAL ;
    PORT
      LAYER M1 ;
      RECT 0.15 0.1 0.20 0.2 ;
    END
  END D
  PIN Q
    DIRECTION OUTPUT ;
    USE SIGNAL ;
    PORT
      LAYER M1 ;
      RECT 0.20 0.1 0.25 0.2 ;
    END
  END Q
  PIN SE
    DIRECTION INPUT ;
    USE SIGNAL ;
    PORT
      LAYER M1 ;
      RECT 0.25 0.1 0.30 0.2 ;
    END
  END SE
  PIN SI
    DIRECTION INPUT ;
    USE SIGNAL ;
    PORT
      LAYER M1 ;
      RECT 0.30 0.1 0.35 0.2 ;
    END
  END SI
END SDFKRPQD1
MACRO SDFKRPQD2
  CLASS CORE ;
  ORIGIN 0.0 0.0 ;
  SIZE 0.45 BY 0.3 ;
  SYMMETRY X Y ;
  PIN C
    DIRECTION INPUT ;
    USE SIGNAL ;
    PORT
      LAYER M1 ;
      RECT 0.05 0.1 0.10 0.2 ;
    END
  END C
  PIN CP
    DIRECTION INPUT ;
    USE SIGNAL ;
    PORT
      LAYER M1 ;
      RECT 0.10 0.1 0.15 0.2 ;
    END
  END CP
  PIN D
    DIRECTION INPUT ;
    USE SIGNAL ;
    PORT
      LAYER M1 ;
      RECT 0.15 0.1 0.20 0.2 ;
    END
  END D
  PIN Q
    DIRECTION OUTPUT ;
    USE SIGNAL ;
    PORT
      LAYER M1 ;
      RECT 0.20 0.1 0.25 0.2 ;
    END
  END Q
  PIN SE
    DIRECTION INPUT ;
    USE SIGNAL ;
    PORT
      LAYER M1 ;
      RECT 0.25 0.1 0.30 0.2 ;
    END
  END SE
  PIN SI
    DIRECTION INPUT ;
    USE SIGNAL ;
    PORT
      LAYER M1 ;
      RECT 0.30 0.1 0.35 0.2 ;
    END
  END SI
END SDFKRPQD2
MACRO SDFKSNQD0
  CLASS CORE ;
  ORIGIN 0.0 0.0 ;
  SIZE 0.45 BY 0.3 ;
  SYMMETRY X Y ;
  PIN CP
    DIRECTION INPUT ;
    USE SIGNAL ;
    PORT
      LAYER M1 ;
      RECT 0.05 0.1 0.10 0.2 ;
    END
  END CP
  PIN D
    DIRECTION INPUT ;
    USE SIGNAL ;
    PORT
      LAYER M1 ;
      RECT 0.10 0.1 0.15 0.2 ;
    END
  END D
  PIN Q
    DIRECTION OUTPUT ;
    USE SIGNAL ;
    PORT
      LAYER M1 ;
      RECT 0.15 0.1 0.20 0.2 ;
    END
  END Q
  PIN SE
    DIRECTION INPUT ;
    USE SIGNAL ;
    PORT
      LAYER M1 ;
      RECT 0.20 0.1 0.25 0.2 ;
    END
  END SE
  PIN SI
    DIRECTION INPUT ;
    USE SIGNAL ;
    PORT
      LAYER M1 ;
      RECT 0.25 0.1 0.30 0.2 ;
    END
  END SI
  PIN SN
    DIRECTION INPUT ;
    USE SIGNAL ;
    PORT
      LAYER M1 ;
      RECT 0.30 0.1 0.35 0.2 ;
    END
  END SN
END SDFKSNQD0
MACRO SDFKSNQD1
  CLASS CORE ;
  ORIGIN 0.0 0.0 ;
  SIZE 0.45 BY 0.3 ;
  SYMMETRY X Y ;
  PIN CP
    DIRECTION INPUT ;
    USE SIGNAL ;
    PORT
      LAYER M1 ;
      RECT 0.05 0.1 0.10 0.2 ;
    END
  END CP
  PIN D
    DIRECTION INPUT ;
    USE SIGNAL ;
    PORT
      LAYER M1 ;
      RECT 0.10 0.1 0.15 0.2 ;
    END
  END D
  PIN Q
    DIRECTION OUTPUT ;
    USE SIGNAL ;
    PORT
      LAYER M1 ;
      RECT 0.15 0.1 0.20 0.2 ;
    END
  END Q
  PIN SE
    DIRECTION INPUT ;
    USE SIGNAL ;
    PORT
      LAYER M1 ;
      RECT 0.20 0.1 0.25 0.2 ;
    END
  END SE
  PIN SI
    DIRECTION INPUT ;
    USE SIGNAL ;
    PORT
      LAYER M1 ;
      RECT 0.25 0.1 0.30 0.2 ;
    END
  END SI
  PIN SN
    DIRECTION INPUT ;
    USE SIGNAL ;
    PORT
      LAYER M1 ;
      RECT 0.30 0.1 0.35 0.2 ;
    END
  END SN
END SDFKSNQD1
MACRO SDFKSNQD2
  CLASS CORE ;
  ORIGIN 0.0 0.0 ;
  SIZE 0.45 BY 0.3 ;
  SYMMETRY X Y ;
  PIN CP
    DIRECTION INPUT ;
    USE SIGNAL ;
    PORT
      LAYER M1 ;
      RECT 0.05 0.1 0.10 0.2 ;
    END
  END CP
  PIN D
    DIRECTION INPUT ;
    USE SIGNAL ;
    PORT
      LAYER M1 ;
      RECT 0.10 0.1 0.15 0.2 ;
    END
  END D
  PIN Q
    DIRECTION OUTPUT ;
    USE SIGNAL ;
    PORT
      LAYER M1 ;
      RECT 0.15 0.1 0.20 0.2 ;
    END
  END Q
  PIN SE
    DIRECTION INPUT ;
    USE SIGNAL ;
    PORT
      LAYER M1 ;
      RECT 0.20 0.1 0.25 0.2 ;
    END
  END SE
  PIN SI
    DIRECTION INPUT ;
    USE SIGNAL ;
    PORT
      LAYER M1 ;
      RECT 0.25 0.1 0.30 0.2 ;
    END
  END SI
  PIN SN
    DIRECTION INPUT ;
    USE SIGNAL ;
    PORT
      LAYER M1 ;
      RECT 0.30 0.1 0.35 0.2 ;
    END
  END SN
END SDFKSNQD2
MACRO SDFKSRPQD0
  CLASS CORE ;
  ORIGIN 0.0 0.0 ;
  SIZE 0.45 BY 0.3 ;
  SYMMETRY X Y ;
  PIN C
    DIRECTION INPUT ;
    USE SIGNAL ;
    PORT
      LAYER M1 ;
      RECT 0.05 0.1 0.10 0.2 ;
    END
  END C
  PIN CP
    DIRECTION INPUT ;
    USE SIGNAL ;
    PORT
      LAYER M1 ;
      RECT 0.09 0.1 0.14 0.2 ;
    END
  END CP
  PIN D
    DIRECTION INPUT ;
    USE SIGNAL ;
    PORT
      LAYER M1 ;
      RECT 0.14 0.1 0.19 0.2 ;
    END
  END D
  PIN Q
    DIRECTION OUTPUT ;
    USE SIGNAL ;
    PORT
      LAYER M1 ;
      RECT 0.18 0.1 0.23 0.2 ;
    END
  END Q
  PIN SE
    DIRECTION INPUT ;
    USE SIGNAL ;
    PORT
      LAYER M1 ;
      RECT 0.22 0.1 0.27 0.2 ;
    END
  END SE
  PIN SI
    DIRECTION INPUT ;
    USE SIGNAL ;
    PORT
      LAYER M1 ;
      RECT 0.26 0.1 0.31 0.2 ;
    END
  END SI
  PIN SN
    DIRECTION INPUT ;
    USE SIGNAL ;
    PORT
      LAYER M1 ;
      RECT 0.31 0.1 0.36 0.2 ;
    END
  END SN
END SDFKSRPQD0
MACRO SDFQD0
  CLASS CORE ;
  ORIGIN 0.0 0.0 ;
  SIZE 0.45 BY 0.3 ;
  SYMMETRY X Y ;
  PIN CP
    DIRECTION INPUT ;
    USE SIGNAL ;
    PORT
      LAYER M1 ;
      RECT 0.05 0.1 0.10 0.2 ;
    END
  END CP
  PIN D
    DIRECTION INPUT ;
    USE SIGNAL ;
    PORT
      LAYER M1 ;
      RECT 0.11 0.1 0.16 0.2 ;
    END
  END D
  PIN Q
    DIRECTION OUTPUT ;
    USE SIGNAL ;
    PORT
      LAYER M1 ;
      RECT 0.17 0.1 0.22 0.2 ;
    END
  END Q
  PIN SE
    DIRECTION INPUT ;
    USE SIGNAL ;
    PORT
      LAYER M1 ;
      RECT 0.23 0.1 0.28 0.2 ;
    END
  END SE
  PIN SI
    DIRECTION INPUT ;
    USE SIGNAL ;
    PORT
      LAYER M1 ;
      RECT 0.29 0.1 0.34 0.2 ;
    END
  END SI
END SDFQD0
MACRO SDFQD1
  CLASS CORE ;
  ORIGIN 0.0 0.0 ;
  SIZE 0.45 BY 0.3 ;
  SYMMETRY X Y ;
  PIN CP
    DIRECTION INPUT ;
    USE SIGNAL ;
    PORT
      LAYER M1 ;
      RECT 0.05 0.1 0.10 0.2 ;
    END
  END CP
  PIN D
    DIRECTION INPUT ;
    USE SIGNAL ;
    PORT
      LAYER M1 ;
      RECT 0.11 0.1 0.16 0.2 ;
    END
  END D
  PIN Q
    DIRECTION OUTPUT ;
    USE SIGNAL ;
    PORT
      LAYER M1 ;
      RECT 0.17 0.1 0.22 0.2 ;
    END
  END Q
  PIN SE
    DIRECTION INPUT ;
    USE SIGNAL ;
    PORT
      LAYER M1 ;
      RECT 0.23 0.1 0.28 0.2 ;
    END
  END SE
  PIN SI
    DIRECTION INPUT ;
    USE SIGNAL ;
    PORT
      LAYER M1 ;
      RECT 0.29 0.1 0.34 0.2 ;
    END
  END SI
END SDFQD1
MACRO SDFQD2
  CLASS CORE ;
  ORIGIN 0.0 0.0 ;
  SIZE 0.45 BY 0.3 ;
  SYMMETRY X Y ;
  PIN CP
    DIRECTION INPUT ;
    USE SIGNAL ;
    PORT
      LAYER M1 ;
      RECT 0.05 0.1 0.10 0.2 ;
    END
  END CP
  PIN D
    DIRECTION INPUT ;
    USE SIGNAL ;
    PORT
      LAYER M1 ;
      RECT 0.11 0.1 0.16 0.2 ;
    END
  END D
  PIN Q
    DIRECTION OUTPUT ;
    USE SIGNAL ;
    PORT
      LAYER M1 ;
      RECT 0.17 0.1 0.22 0.2 ;
    END
  END Q
  PIN SE
    DIRECTION INPUT ;
    USE SIGNAL ;
    PORT
      LAYER M1 ;
      RECT 0.23 0.1 0.28 0.2 ;
    END
  END SE
  PIN SI
    DIRECTION INPUT ;
    USE SIGNAL ;
    PORT
      LAYER M1 ;
      RECT 0.29 0.1 0.34 0.2 ;
    END
  END SI
END SDFQD2
MACRO SDFQD4
  CLASS CORE ;
  ORIGIN 0.0 0.0 ;
  SIZE 0.45 BY 0.3 ;
  SYMMETRY X Y ;
  PIN CP
    DIRECTION INPUT ;
    USE SIGNAL ;
    PORT
      LAYER M1 ;
      RECT 0.05 0.1 0.10 0.2 ;
    END
  END CP
  PIN D
    DIRECTION INPUT ;
    USE SIGNAL ;
    PORT
      LAYER M1 ;
      RECT 0.11 0.1 0.16 0.2 ;
    END
  END D
  PIN Q
    DIRECTION OUTPUT ;
    USE SIGNAL ;
    PORT
      LAYER M1 ;
      RECT 0.17 0.1 0.22 0.2 ;
    END
  END Q
  PIN SE
    DIRECTION INPUT ;
    USE SIGNAL ;
    PORT
      LAYER M1 ;
      RECT 0.23 0.1 0.28 0.2 ;
    END
  END SE
  PIN SI
    DIRECTION INPUT ;
    USE SIGNAL ;
    PORT
      LAYER M1 ;
      RECT 0.29 0.1 0.34 0.2 ;
    END
  END SI
END SDFQD4
MACRO SDFQND0
  CLASS CORE ;
  ORIGIN 0.0 0.0 ;
  SIZE 0.45 BY 0.3 ;
  SYMMETRY X Y ;
  PIN CP
    DIRECTION INPUT ;
    USE SIGNAL ;
    PORT
      LAYER M1 ;
      RECT 0.05 0.1 0.10 0.2 ;
    END
  END CP
  PIN D
    DIRECTION INPUT ;
    USE SIGNAL ;
    PORT
      LAYER M1 ;
      RECT 0.11 0.1 0.16 0.2 ;
    END
  END D
  PIN QN
    DIRECTION OUTPUT ;
    USE SIGNAL ;
    PORT
      LAYER M1 ;
      RECT 0.17 0.1 0.22 0.2 ;
    END
  END QN
  PIN SE
    DIRECTION INPUT ;
    USE SIGNAL ;
    PORT
      LAYER M1 ;
      RECT 0.23 0.1 0.28 0.2 ;
    END
  END SE
  PIN SI
    DIRECTION INPUT ;
    USE SIGNAL ;
    PORT
      LAYER M1 ;
      RECT 0.29 0.1 0.34 0.2 ;
    END
  END SI
END SDFQND0
MACRO SDFQND2
  CLASS CORE ;
  ORIGIN 0.0 0.0 ;
  SIZE 0.45 BY 0.3 ;
  SYMMETRY X Y ;
  PIN CP
    DIRECTION INPUT ;
    USE SIGNAL ;
    PORT
      LAYER M1 ;
      RECT 0.05 0.1 0.10 0.2 ;
    END
  END CP
  PIN D
    DIRECTION INPUT ;
    USE SIGNAL ;
    PORT
      LAYER M1 ;
      RECT 0.11 0.1 0.16 0.2 ;
    END
  END D
  PIN QN
    DIRECTION OUTPUT ;
    USE SIGNAL ;
    PORT
      LAYER M1 ;
      RECT 0.17 0.1 0.22 0.2 ;
    END
  END QN
  PIN SE
    DIRECTION INPUT ;
    USE SIGNAL ;
    PORT
      LAYER M1 ;
      RECT 0.23 0.1 0.28 0.2 ;
    END
  END SE
  PIN SI
    DIRECTION INPUT ;
    USE SIGNAL ;
    PORT
      LAYER M1 ;
      RECT 0.29 0.1 0.34 0.2 ;
    END
  END SI
END SDFQND2
MACRO SDFQOPTBBD0
  CLASS CORE ;
  ORIGIN 0.0 0.0 ;
  SIZE 0.45 BY 0.3 ;
  SYMMETRY X Y ;
  PIN CP
    DIRECTION INPUT ;
    USE SIGNAL ;
    PORT
      LAYER M1 ;
      RECT 0.05 0.1 0.10 0.2 ;
    END
  END CP
  PIN D
    DIRECTION INPUT ;
    USE SIGNAL ;
    PORT
      LAYER M1 ;
      RECT 0.11 0.1 0.16 0.2 ;
    END
  END D
  PIN Q
    DIRECTION OUTPUT ;
    USE SIGNAL ;
    PORT
      LAYER M1 ;
      RECT 0.17 0.1 0.22 0.2 ;
    END
  END Q
  PIN SE
    DIRECTION INPUT ;
    USE SIGNAL ;
    PORT
      LAYER M1 ;
      RECT 0.23 0.1 0.28 0.2 ;
    END
  END SE
  PIN SI
    DIRECTION INPUT ;
    USE SIGNAL ;
    PORT
      LAYER M1 ;
      RECT 0.29 0.1 0.34 0.2 ;
    END
  END SI
END SDFQOPTBBD0
MACRO SDFQOPTBBD1
  CLASS CORE ;
  ORIGIN 0.0 0.0 ;
  SIZE 0.45 BY 0.3 ;
  SYMMETRY X Y ;
  PIN CP
    DIRECTION INPUT ;
    USE SIGNAL ;
    PORT
      LAYER M1 ;
      RECT 0.05 0.1 0.10 0.2 ;
    END
  END CP
  PIN D
    DIRECTION INPUT ;
    USE SIGNAL ;
    PORT
      LAYER M1 ;
      RECT 0.11 0.1 0.16 0.2 ;
    END
  END D
  PIN Q
    DIRECTION OUTPUT ;
    USE SIGNAL ;
    PORT
      LAYER M1 ;
      RECT 0.17 0.1 0.22 0.2 ;
    END
  END Q
  PIN SE
    DIRECTION INPUT ;
    USE SIGNAL ;
    PORT
      LAYER M1 ;
      RECT 0.23 0.1 0.28 0.2 ;
    END
  END SE
  PIN SI
    DIRECTION INPUT ;
    USE SIGNAL ;
    PORT
      LAYER M1 ;
      RECT 0.29 0.1 0.34 0.2 ;
    END
  END SI
END SDFQOPTBBD1
MACRO SDFQOPTBBD2
  CLASS CORE ;
  ORIGIN 0.0 0.0 ;
  SIZE 0.45 BY 0.3 ;
  SYMMETRY X Y ;
  PIN CP
    DIRECTION INPUT ;
    USE SIGNAL ;
    PORT
      LAYER M1 ;
      RECT 0.05 0.1 0.10 0.2 ;
    END
  END CP
  PIN D
    DIRECTION INPUT ;
    USE SIGNAL ;
    PORT
      LAYER M1 ;
      RECT 0.11 0.1 0.16 0.2 ;
    END
  END D
  PIN Q
    DIRECTION OUTPUT ;
    USE SIGNAL ;
    PORT
      LAYER M1 ;
      RECT 0.17 0.1 0.22 0.2 ;
    END
  END Q
  PIN SE
    DIRECTION INPUT ;
    USE SIGNAL ;
    PORT
      LAYER M1 ;
      RECT 0.23 0.1 0.28 0.2 ;
    END
  END SE
  PIN SI
    DIRECTION INPUT ;
    USE SIGNAL ;
    PORT
      LAYER M1 ;
      RECT 0.29 0.1 0.34 0.2 ;
    END
  END SI
END SDFQOPTBBD2
MACRO SDFQOPTBBD4
  CLASS CORE ;
  ORIGIN 0.0 0.0 ;
  SIZE 0.45 BY 0.3 ;
  SYMMETRY X Y ;
  PIN CP
    DIRECTION INPUT ;
    USE SIGNAL ;
    PORT
      LAYER M1 ;
      RECT 0.05 0.1 0.10 0.2 ;
    END
  END CP
  PIN D
    DIRECTION INPUT ;
    USE SIGNAL ;
    PORT
      LAYER M1 ;
      RECT 0.11 0.1 0.16 0.2 ;
    END
  END D
  PIN Q
    DIRECTION OUTPUT ;
    USE SIGNAL ;
    PORT
      LAYER M1 ;
      RECT 0.17 0.1 0.22 0.2 ;
    END
  END Q
  PIN SE
    DIRECTION INPUT ;
    USE SIGNAL ;
    PORT
      LAYER M1 ;
      RECT 0.23 0.1 0.28 0.2 ;
    END
  END SE
  PIN SI
    DIRECTION INPUT ;
    USE SIGNAL ;
    PORT
      LAYER M1 ;
      RECT 0.29 0.1 0.34 0.2 ;
    END
  END SI
END SDFQOPTBBD4
MACRO SDFQOPTBBOPTLD4
  CLASS CORE ;
  ORIGIN 0.0 0.0 ;
  SIZE 0.45 BY 0.3 ;
  SYMMETRY X Y ;
  PIN CP
    DIRECTION INPUT ;
    USE SIGNAL ;
    PORT
      LAYER M1 ;
      RECT 0.05 0.1 0.10 0.2 ;
    END
  END CP
  PIN D
    DIRECTION INPUT ;
    USE SIGNAL ;
    PORT
      LAYER M1 ;
      RECT 0.11 0.1 0.16 0.2 ;
    END
  END D
  PIN Q
    DIRECTION OUTPUT ;
    USE SIGNAL ;
    PORT
      LAYER M1 ;
      RECT 0.17 0.1 0.22 0.2 ;
    END
  END Q
  PIN SE
    DIRECTION INPUT ;
    USE SIGNAL ;
    PORT
      LAYER M1 ;
      RECT 0.23 0.1 0.28 0.2 ;
    END
  END SE
  PIN SI
    DIRECTION INPUT ;
    USE SIGNAL ;
    PORT
      LAYER M1 ;
      RECT 0.29 0.1 0.34 0.2 ;
    END
  END SI
END SDFQOPTBBOPTLD4
MACRO SDFQOPTBCD0
  CLASS CORE ;
  ORIGIN 0.0 0.0 ;
  SIZE 0.45 BY 0.3 ;
  SYMMETRY X Y ;
  PIN CP
    DIRECTION INPUT ;
    USE SIGNAL ;
    PORT
      LAYER M1 ;
      RECT 0.05 0.1 0.10 0.2 ;
    END
  END CP
  PIN D
    DIRECTION INPUT ;
    USE SIGNAL ;
    PORT
      LAYER M1 ;
      RECT 0.11 0.1 0.16 0.2 ;
    END
  END D
  PIN Q
    DIRECTION OUTPUT ;
    USE SIGNAL ;
    PORT
      LAYER M1 ;
      RECT 0.17 0.1 0.22 0.2 ;
    END
  END Q
  PIN SE
    DIRECTION INPUT ;
    USE SIGNAL ;
    PORT
      LAYER M1 ;
      RECT 0.23 0.1 0.28 0.2 ;
    END
  END SE
  PIN SI
    DIRECTION INPUT ;
    USE SIGNAL ;
    PORT
      LAYER M1 ;
      RECT 0.29 0.1 0.34 0.2 ;
    END
  END SI
END SDFQOPTBCD0
MACRO SDFQOPTBCD1
  CLASS CORE ;
  ORIGIN 0.0 0.0 ;
  SIZE 0.45 BY 0.3 ;
  SYMMETRY X Y ;
  PIN CP
    DIRECTION INPUT ;
    USE SIGNAL ;
    PORT
      LAYER M1 ;
      RECT 0.05 0.1 0.10 0.2 ;
    END
  END CP
  PIN D
    DIRECTION INPUT ;
    USE SIGNAL ;
    PORT
      LAYER M1 ;
      RECT 0.11 0.1 0.16 0.2 ;
    END
  END D
  PIN Q
    DIRECTION OUTPUT ;
    USE SIGNAL ;
    PORT
      LAYER M1 ;
      RECT 0.17 0.1 0.22 0.2 ;
    END
  END Q
  PIN SE
    DIRECTION INPUT ;
    USE SIGNAL ;
    PORT
      LAYER M1 ;
      RECT 0.23 0.1 0.28 0.2 ;
    END
  END SE
  PIN SI
    DIRECTION INPUT ;
    USE SIGNAL ;
    PORT
      LAYER M1 ;
      RECT 0.29 0.1 0.34 0.2 ;
    END
  END SI
END SDFQOPTBCD1
MACRO SDFQOPTBCD2
  CLASS CORE ;
  ORIGIN 0.0 0.0 ;
  SIZE 0.45 BY 0.3 ;
  SYMMETRY X Y ;
  PIN CP
    DIRECTION INPUT ;
    USE SIGNAL ;
    PORT
      LAYER M1 ;
      RECT 0.05 0.1 0.10 0.2 ;
    END
  END CP
  PIN D
    DIRECTION INPUT ;
    USE SIGNAL ;
    PORT
      LAYER M1 ;
      RECT 0.11 0.1 0.16 0.2 ;
    END
  END D
  PIN Q
    DIRECTION OUTPUT ;
    USE SIGNAL ;
    PORT
      LAYER M1 ;
      RECT 0.17 0.1 0.22 0.2 ;
    END
  END Q
  PIN SE
    DIRECTION INPUT ;
    USE SIGNAL ;
    PORT
      LAYER M1 ;
      RECT 0.23 0.1 0.28 0.2 ;
    END
  END SE
  PIN SI
    DIRECTION INPUT ;
    USE SIGNAL ;
    PORT
      LAYER M1 ;
      RECT 0.29 0.1 0.34 0.2 ;
    END
  END SI
END SDFQOPTBCD2
MACRO SDFQOPTBCD4
  CLASS CORE ;
  ORIGIN 0.0 0.0 ;
  SIZE 0.45 BY 0.3 ;
  SYMMETRY X Y ;
  PIN CP
    DIRECTION INPUT ;
    USE SIGNAL ;
    PORT
      LAYER M1 ;
      RECT 0.05 0.1 0.10 0.2 ;
    END
  END CP
  PIN D
    DIRECTION INPUT ;
    USE SIGNAL ;
    PORT
      LAYER M1 ;
      RECT 0.11 0.1 0.16 0.2 ;
    END
  END D
  PIN Q
    DIRECTION OUTPUT ;
    USE SIGNAL ;
    PORT
      LAYER M1 ;
      RECT 0.17 0.1 0.22 0.2 ;
    END
  END Q
  PIN SE
    DIRECTION INPUT ;
    USE SIGNAL ;
    PORT
      LAYER M1 ;
      RECT 0.23 0.1 0.28 0.2 ;
    END
  END SE
  PIN SI
    DIRECTION INPUT ;
    USE SIGNAL ;
    PORT
      LAYER M1 ;
      RECT 0.29 0.1 0.34 0.2 ;
    END
  END SI
END SDFQOPTBCD4
MACRO SDFQOPTBCUSS1D0
  CLASS CORE ;
  ORIGIN 0.0 0.0 ;
  SIZE 0.45 BY 0.3 ;
  SYMMETRY X Y ;
  PIN CP
    DIRECTION INPUT ;
    USE SIGNAL ;
    PORT
      LAYER M1 ;
      RECT 0.05 0.1 0.10 0.2 ;
    END
  END CP
  PIN D
    DIRECTION INPUT ;
    USE SIGNAL ;
    PORT
      LAYER M1 ;
      RECT 0.11 0.1 0.16 0.2 ;
    END
  END D
  PIN Q
    DIRECTION OUTPUT ;
    USE SIGNAL ;
    PORT
      LAYER M1 ;
      RECT 0.17 0.1 0.22 0.2 ;
    END
  END Q
  PIN SE
    DIRECTION INPUT ;
    USE SIGNAL ;
    PORT
      LAYER M1 ;
      RECT 0.23 0.1 0.28 0.2 ;
    END
  END SE
  PIN SI
    DIRECTION INPUT ;
    USE SIGNAL ;
    PORT
      LAYER M1 ;
      RECT 0.29 0.1 0.34 0.2 ;
    END
  END SI
END SDFQOPTBCUSS1D0
MACRO SDFQOPTBCUSS1D1
  CLASS CORE ;
  ORIGIN 0.0 0.0 ;
  SIZE 0.45 BY 0.3 ;
  SYMMETRY X Y ;
  PIN CP
    DIRECTION INPUT ;
    USE SIGNAL ;
    PORT
      LAYER M1 ;
      RECT 0.05 0.1 0.10 0.2 ;
    END
  END CP
  PIN D
    DIRECTION INPUT ;
    USE SIGNAL ;
    PORT
      LAYER M1 ;
      RECT 0.11 0.1 0.16 0.2 ;
    END
  END D
  PIN Q
    DIRECTION OUTPUT ;
    USE SIGNAL ;
    PORT
      LAYER M1 ;
      RECT 0.17 0.1 0.22 0.2 ;
    END
  END Q
  PIN SE
    DIRECTION INPUT ;
    USE SIGNAL ;
    PORT
      LAYER M1 ;
      RECT 0.23 0.1 0.28 0.2 ;
    END
  END SE
  PIN SI
    DIRECTION INPUT ;
    USE SIGNAL ;
    PORT
      LAYER M1 ;
      RECT 0.29 0.1 0.34 0.2 ;
    END
  END SI
END SDFQOPTBCUSS1D1
MACRO SDFQOPTBCUSS1D2
  CLASS CORE ;
  ORIGIN 0.0 0.0 ;
  SIZE 0.45 BY 0.3 ;
  SYMMETRY X Y ;
  PIN CP
    DIRECTION INPUT ;
    USE SIGNAL ;
    PORT
      LAYER M1 ;
      RECT 0.05 0.1 0.10 0.2 ;
    END
  END CP
  PIN D
    DIRECTION INPUT ;
    USE SIGNAL ;
    PORT
      LAYER M1 ;
      RECT 0.11 0.1 0.16 0.2 ;
    END
  END D
  PIN Q
    DIRECTION OUTPUT ;
    USE SIGNAL ;
    PORT
      LAYER M1 ;
      RECT 0.17 0.1 0.22 0.2 ;
    END
  END Q
  PIN SE
    DIRECTION INPUT ;
    USE SIGNAL ;
    PORT
      LAYER M1 ;
      RECT 0.23 0.1 0.28 0.2 ;
    END
  END SE
  PIN SI
    DIRECTION INPUT ;
    USE SIGNAL ;
    PORT
      LAYER M1 ;
      RECT 0.29 0.1 0.34 0.2 ;
    END
  END SI
END SDFQOPTBCUSS1D2
MACRO SDFQOPTLD4
  CLASS CORE ;
  ORIGIN 0.0 0.0 ;
  SIZE 0.45 BY 0.3 ;
  SYMMETRY X Y ;
  PIN CP
    DIRECTION INPUT ;
    USE SIGNAL ;
    PORT
      LAYER M1 ;
      RECT 0.05 0.1 0.10 0.2 ;
    END
  END CP
  PIN D
    DIRECTION INPUT ;
    USE SIGNAL ;
    PORT
      LAYER M1 ;
      RECT 0.11 0.1 0.16 0.2 ;
    END
  END D
  PIN Q
    DIRECTION OUTPUT ;
    USE SIGNAL ;
    PORT
      LAYER M1 ;
      RECT 0.17 0.1 0.22 0.2 ;
    END
  END Q
  PIN SE
    DIRECTION INPUT ;
    USE SIGNAL ;
    PORT
      LAYER M1 ;
      RECT 0.23 0.1 0.28 0.2 ;
    END
  END SE
  PIN SI
    DIRECTION INPUT ;
    USE SIGNAL ;
    PORT
      LAYER M1 ;
      RECT 0.29 0.1 0.34 0.2 ;
    END
  END SI
END SDFQOPTLD4
MACRO SDFQOPTQD0
  CLASS CORE ;
  ORIGIN 0.0 0.0 ;
  SIZE 0.45 BY 0.3 ;
  SYMMETRY X Y ;
  PIN CP
    DIRECTION INPUT ;
    USE SIGNAL ;
    PORT
      LAYER M1 ;
      RECT 0.05 0.1 0.10 0.2 ;
    END
  END CP
  PIN D
    DIRECTION INPUT ;
    USE SIGNAL ;
    PORT
      LAYER M1 ;
      RECT 0.11 0.1 0.16 0.2 ;
    END
  END D
  PIN Q
    DIRECTION OUTPUT ;
    USE SIGNAL ;
    PORT
      LAYER M1 ;
      RECT 0.17 0.1 0.22 0.2 ;
    END
  END Q
  PIN SE
    DIRECTION INPUT ;
    USE SIGNAL ;
    PORT
      LAYER M1 ;
      RECT 0.23 0.1 0.28 0.2 ;
    END
  END SE
  PIN SI
    DIRECTION INPUT ;
    USE SIGNAL ;
    PORT
      LAYER M1 ;
      RECT 0.29 0.1 0.34 0.2 ;
    END
  END SI
END SDFQOPTQD0
MACRO SDFQOPTQD1
  CLASS CORE ;
  ORIGIN 0.0 0.0 ;
  SIZE 0.45 BY 0.3 ;
  SYMMETRY X Y ;
  PIN CP
    DIRECTION INPUT ;
    USE SIGNAL ;
    PORT
      LAYER M1 ;
      RECT 0.05 0.1 0.10 0.2 ;
    END
  END CP
  PIN D
    DIRECTION INPUT ;
    USE SIGNAL ;
    PORT
      LAYER M1 ;
      RECT 0.11 0.1 0.16 0.2 ;
    END
  END D
  PIN Q
    DIRECTION OUTPUT ;
    USE SIGNAL ;
    PORT
      LAYER M1 ;
      RECT 0.17 0.1 0.22 0.2 ;
    END
  END Q
  PIN SE
    DIRECTION INPUT ;
    USE SIGNAL ;
    PORT
      LAYER M1 ;
      RECT 0.23 0.1 0.28 0.2 ;
    END
  END SE
  PIN SI
    DIRECTION INPUT ;
    USE SIGNAL ;
    PORT
      LAYER M1 ;
      RECT 0.29 0.1 0.34 0.2 ;
    END
  END SI
END SDFQOPTQD1
MACRO SDFQOPTQD2
  CLASS CORE ;
  ORIGIN 0.0 0.0 ;
  SIZE 0.45 BY 0.3 ;
  SYMMETRY X Y ;
  PIN CP
    DIRECTION INPUT ;
    USE SIGNAL ;
    PORT
      LAYER M1 ;
      RECT 0.05 0.1 0.10 0.2 ;
    END
  END CP
  PIN D
    DIRECTION INPUT ;
    USE SIGNAL ;
    PORT
      LAYER M1 ;
      RECT 0.11 0.1 0.16 0.2 ;
    END
  END D
  PIN Q
    DIRECTION OUTPUT ;
    USE SIGNAL ;
    PORT
      LAYER M1 ;
      RECT 0.17 0.1 0.22 0.2 ;
    END
  END Q
  PIN SE
    DIRECTION INPUT ;
    USE SIGNAL ;
    PORT
      LAYER M1 ;
      RECT 0.23 0.1 0.28 0.2 ;
    END
  END SE
  PIN SI
    DIRECTION INPUT ;
    USE SIGNAL ;
    PORT
      LAYER M1 ;
      RECT 0.29 0.1 0.34 0.2 ;
    END
  END SI
END SDFQOPTQD2
MACRO SDFRPQD0
  CLASS CORE ;
  ORIGIN 0.0 0.0 ;
  SIZE 0.45 BY 0.3 ;
  SYMMETRY X Y ;
  PIN CD
    DIRECTION INPUT ;
    USE SIGNAL ;
    PORT
      LAYER M1 ;
      RECT 0.05 0.1 0.10 0.2 ;
    END
  END CD
  PIN CP
    DIRECTION INPUT ;
    USE SIGNAL ;
    PORT
      LAYER M1 ;
      RECT 0.10 0.1 0.15 0.2 ;
    END
  END CP
  PIN D
    DIRECTION INPUT ;
    USE SIGNAL ;
    PORT
      LAYER M1 ;
      RECT 0.15 0.1 0.20 0.2 ;
    END
  END D
  PIN Q
    DIRECTION OUTPUT ;
    USE SIGNAL ;
    PORT
      LAYER M1 ;
      RECT 0.20 0.1 0.25 0.2 ;
    END
  END Q
  PIN SE
    DIRECTION INPUT ;
    USE SIGNAL ;
    PORT
      LAYER M1 ;
      RECT 0.25 0.1 0.30 0.2 ;
    END
  END SE
  PIN SI
    DIRECTION INPUT ;
    USE SIGNAL ;
    PORT
      LAYER M1 ;
      RECT 0.30 0.1 0.35 0.2 ;
    END
  END SI
END SDFRPQD0
MACRO SEDFQD1
  CLASS CORE ;
  ORIGIN 0.0 0.0 ;
  SIZE 0.45 BY 0.3 ;
  SYMMETRY X Y ;
  PIN CP
    DIRECTION INPUT ;
    USE SIGNAL ;
    PORT
      LAYER M1 ;
      RECT 0.05 0.1 0.10 0.2 ;
    END
  END CP
  PIN D
    DIRECTION INPUT ;
    USE SIGNAL ;
    PORT
      LAYER M1 ;
      RECT 0.10 0.1 0.15 0.2 ;
    END
  END D
  PIN E
    DIRECTION INPUT ;
    USE SIGNAL ;
    PORT
      LAYER M1 ;
      RECT 0.15 0.1 0.20 0.2 ;
    END
  END E
  PIN Q
    DIRECTION OUTPUT ;
    USE SIGNAL ;
    PORT
      LAYER M1 ;
      RECT 0.20 0.1 0.25 0.2 ;
    END
  END Q
  PIN SE
    DIRECTION INPUT ;
    USE SIGNAL ;
    PORT
      LAYER M1 ;
      RECT 0.25 0.1 0.30 0.2 ;
    END
  END SE
  PIN SI
    DIRECTION INPUT ;
    USE SIGNAL ;
    PORT
      LAYER M1 ;
      RECT 0.30 0.1 0.35 0.2 ;
    END
  END SI
END SEDFQD1
MACRO TIEHXP
  CLASS CORE ;
  ORIGIN 0.0 0.0 ;
  SIZE 0.45 BY 0.3 ;
  SYMMETRY X Y ;
  PIN Z
    DIRECTION OUTPUT ;
    USE SIGNAL ;
    PORT
      LAYER M1 ;
      RECT 0.05 0.1 0.10 0.2 ;
    END
  END Z
END TIEHXP
MACRO TIELXN
  CLASS CORE ;
  ORIGIN 0.0 0.0 ;
  SIZE 0.45 BY 0.3 ;
  SYMMETRY X Y ;
  PIN ZN
    DIRECTION OUTPUT ;
    USE SIGNAL ;
    PORT
      LAYER M1 ;
      RECT 0.05 0.1 0.10 0.2 ;
    END
  END ZN
END TIELXN
MACRO XNR2D0
  CLASS CORE ;
  ORIGIN 0.0 0.0 ;
  SIZE 0.45 BY 0.3 ;
  SYMMETRY X Y ;
  PIN A1
    DIRECTION INPUT ;
    USE SIGNAL ;
    PORT
      LAYER M1 ;
      RECT 0.05 0.1 0.10 0.2 ;
    END
  END A1
  PIN A2
    DIRECTION INPUT ;
    USE SIGNAL ;
    PORT
      LAYER M1 ;
      RECT 0.15 0.1 0.20 0.2 ;
    END
  END A2
  PIN ZN
    DIRECTION OUTPUT ;
    USE SIGNAL ;
    PORT
      LAYER M1 ;
      RECT 0.25 0.1 0.30 0.2 ;
    END
  END ZN
END XNR2D0
MACRO XNR2D6
  CLASS CORE ;
  ORIGIN 0.0 0.0 ;
  SIZE 0.45 BY 0.3 ;
  SYMMETRY X Y ;
  PIN A1
    DIRECTION INPUT ;
    USE SIGNAL ;
    PORT
      LAYER M1 ;
      RECT 0.05 0.1 0.10 0.2 ;
    END
  END A1
  PIN A2
    DIRECTION INPUT ;
    USE SIGNAL ;
    PORT
      LAYER M1 ;
      RECT 0.15 0.1 0.20 0.2 ;
    END
  END A2
  PIN ZN
    DIRECTION OUTPUT ;
    USE SIGNAL ;
    PORT
      LAYER M1 ;
      RECT 0.25 0.1 0.30 0.2 ;
    END
  END ZN
END XNR2D6
MACRO XNR2OPTLD1
  CLASS CORE ;
  ORIGIN 0.0 0.0 ;
  SIZE 0.45 BY 0.3 ;
  SYMMETRY X Y ;
  PIN A1
    DIRECTION INPUT ;
    USE SIGNAL ;
    PORT
      LAYER M1 ;
      RECT 0.05 0.1 0.10 0.2 ;
    END
  END A1
  PIN A2
    DIRECTION INPUT ;
    USE SIGNAL ;
    PORT
      LAYER M1 ;
      RECT 0.15 0.1 0.20 0.2 ;
    END
  END A2
  PIN ZN
    DIRECTION OUTPUT ;
    USE SIGNAL ;
    PORT
      LAYER M1 ;
      RECT 0.25 0.1 0.30 0.2 ;
    END
  END ZN
END XNR2OPTLD1
MACRO XNR2OPTLD2
  CLASS CORE ;
  ORIGIN 0.0 0.0 ;
  SIZE 0.45 BY 0.3 ;
  SYMMETRY X Y ;
  PIN A1
    DIRECTION INPUT ;
    USE SIGNAL ;
    PORT
      LAYER M1 ;
      RECT 0.05 0.1 0.10 0.2 ;
    END
  END A1
  PIN A2
    DIRECTION INPUT ;
    USE SIGNAL ;
    PORT
      LAYER M1 ;
      RECT 0.15 0.1 0.20 0.2 ;
    END
  END A2
  PIN ZN
    DIRECTION OUTPUT ;
    USE SIGNAL ;
    PORT
      LAYER M1 ;
      RECT 0.25 0.1 0.30 0.2 ;
    END
  END ZN
END XNR2OPTLD2
MACRO XNR2OPTLD4
  CLASS CORE ;
  ORIGIN 0.0 0.0 ;
  SIZE 0.45 BY 0.3 ;
  SYMMETRY X Y ;
  PIN A1
    DIRECTION INPUT ;
    USE SIGNAL ;
    PORT
      LAYER M1 ;
      RECT 0.05 0.1 0.10 0.2 ;
    END
  END A1
  PIN A2
    DIRECTION INPUT ;
    USE SIGNAL ;
    PORT
      LAYER M1 ;
      RECT 0.15 0.1 0.20 0.2 ;
    END
  END A2
  PIN ZN
    DIRECTION OUTPUT ;
    USE SIGNAL ;
    PORT
      LAYER M1 ;
      RECT 0.25 0.1 0.30 0.2 ;
    END
  END ZN
END XNR2OPTLD4
MACRO XNR2OPTLD6
  CLASS CORE ;
  ORIGIN 0.0 0.0 ;
  SIZE 0.45 BY 0.3 ;
  SYMMETRY X Y ;
  PIN A1
    DIRECTION INPUT ;
    USE SIGNAL ;
    PORT
      LAYER M1 ;
      RECT 0.05 0.1 0.10 0.2 ;
    END
  END A1
  PIN A2
    DIRECTION INPUT ;
    USE SIGNAL ;
    PORT
      LAYER M1 ;
      RECT 0.15 0.1 0.20 0.2 ;
    END
  END A2
  PIN ZN
    DIRECTION OUTPUT ;
    USE SIGNAL ;
    PORT
      LAYER M1 ;
      RECT 0.25 0.1 0.30 0.2 ;
    END
  END ZN
END XNR2OPTLD6
MACRO XNR3OPTLD2
  CLASS CORE ;
  ORIGIN 0.0 0.0 ;
  SIZE 0.45 BY 0.3 ;
  SYMMETRY X Y ;
  PIN A1
    DIRECTION INPUT ;
    USE SIGNAL ;
    PORT
      LAYER M1 ;
      RECT 0.05 0.1 0.10 0.2 ;
    END
  END A1
  PIN A2
    DIRECTION INPUT ;
    USE SIGNAL ;
    PORT
      LAYER M1 ;
      RECT 0.12 0.1 0.17 0.2 ;
    END
  END A2
  PIN A3
    DIRECTION INPUT ;
    USE SIGNAL ;
    PORT
      LAYER M1 ;
      RECT 0.20 0.1 0.25 0.2 ;
    END
  END A3
  PIN ZN
    DIRECTION OUTPUT ;
    USE SIGNAL ;
    PORT
      LAYER M1 ;
      RECT 0.27 0.1 0.32 0.2 ;
    END
  END ZN
END XNR3OPTLD2
MACRO XNR4D1
  CLASS CORE ;
  ORIGIN 0.0 0.0 ;
  SIZE 0.45 BY 0.3 ;
  SYMMETRY X Y ;
  PIN A1
    DIRECTION INPUT ;
    USE SIGNAL ;
    PORT
      LAYER M1 ;
      RECT 0.05 0.1 0.10 0.2 ;
    END
  END A1
  PIN A2
    DIRECTION INPUT ;
    USE SIGNAL ;
    PORT
      LAYER M1 ;
      RECT 0.11 0.1 0.16 0.2 ;
    END
  END A2
  PIN A3
    DIRECTION INPUT ;
    USE SIGNAL ;
    PORT
      LAYER M1 ;
      RECT 0.17 0.1 0.22 0.2 ;
    END
  END A3
  PIN A4
    DIRECTION INPUT ;
    USE SIGNAL ;
    PORT
      LAYER M1 ;
      RECT 0.23 0.1 0.28 0.2 ;
    END
  END A4
  PIN ZN
    DIRECTION OUTPUT ;
    USE SIGNAL ;
    PORT
      LAYER M1 ;
      RECT 0.29 0.1 0.34 0.2 ;
    END
  END ZN
END XNR4D1
MACRO XNR4D2
  CLASS CORE ;
  ORIGIN 0.0 0.0 ;
  SIZE 0.45 BY 0.3 ;
  SYMMETRY X Y ;
  PIN A1
    DIRECTION INPUT ;
    USE SIGNAL ;
    PORT
      LAYER M1 ;
      RECT 0.05 0.1 0.10 0.2 ;
    END
  END A1
  PIN A2
    DIRECTION INPUT ;
    USE SIGNAL ;
    PORT
      LAYER M1 ;
      RECT 0.11 0.1 0.16 0.2 ;
    END
  END A2
  PIN A3
    DIRECTION INPUT ;
    USE SIGNAL ;
    PORT
      LAYER M1 ;
      RECT 0.17 0.1 0.22 0.2 ;
    END
  END A3
  PIN A4
    DIRECTION INPUT ;
    USE SIGNAL ;
    PORT
      LAYER M1 ;
      RECT 0.23 0.1 0.28 0.2 ;
    END
  END A4
  PIN ZN
    DIRECTION OUTPUT ;
    USE SIGNAL ;
    PORT
      LAYER M1 ;
      RECT 0.29 0.1 0.34 0.2 ;
    END
  END ZN
END XNR4D2
MACRO XOR2D0
  CLASS CORE ;
  ORIGIN 0.0 0.0 ;
  SIZE 0.45 BY 0.3 ;
  SYMMETRY X Y ;
  PIN A1
    DIRECTION INPUT ;
    USE SIGNAL ;
    PORT
      LAYER M1 ;
      RECT 0.05 0.1 0.10 0.2 ;
    END
  END A1
  PIN A2
    DIRECTION INPUT ;
    USE SIGNAL ;
    PORT
      LAYER M1 ;
      RECT 0.15 0.1 0.20 0.2 ;
    END
  END A2
  PIN Z
    DIRECTION OUTPUT ;
    USE SIGNAL ;
    PORT
      LAYER M1 ;
      RECT 0.25 0.1 0.30 0.2 ;
    END
  END Z
END XOR2D0
MACRO XOR2D3
  CLASS CORE ;
  ORIGIN 0.0 0.0 ;
  SIZE 0.45 BY 0.3 ;
  SYMMETRY X Y ;
  PIN A1
    DIRECTION INPUT ;
    USE SIGNAL ;
    PORT
      LAYER M1 ;
      RECT 0.05 0.1 0.10 0.2 ;
    END
  END A1
  PIN A2
    DIRECTION INPUT ;
    USE SIGNAL ;
    PORT
      LAYER M1 ;
      RECT 0.15 0.1 0.20 0.2 ;
    END
  END A2
  PIN Z
    DIRECTION OUTPUT ;
    USE SIGNAL ;
    PORT
      LAYER M1 ;
      RECT 0.25 0.1 0.30 0.2 ;
    END
  END Z
END XOR2D3
MACRO XOR2D4
  CLASS CORE ;
  ORIGIN 0.0 0.0 ;
  SIZE 0.45 BY 0.3 ;
  SYMMETRY X Y ;
  PIN A1
    DIRECTION INPUT ;
    USE SIGNAL ;
    PORT
      LAYER M1 ;
      RECT 0.05 0.1 0.10 0.2 ;
    END
  END A1
  PIN A2
    DIRECTION INPUT ;
    USE SIGNAL ;
    PORT
      LAYER M1 ;
      RECT 0.15 0.1 0.20 0.2 ;
    END
  END A2
  PIN Z
    DIRECTION OUTPUT ;
    USE SIGNAL ;
    PORT
      LAYER M1 ;
      RECT 0.25 0.1 0.30 0.2 ;
    END
  END Z
END XOR2D4
MACRO XOR2D6
  CLASS CORE ;
  ORIGIN 0.0 0.0 ;
  SIZE 0.45 BY 0.3 ;
  SYMMETRY X Y ;
  PIN A1
    DIRECTION INPUT ;
    USE SIGNAL ;
    PORT
      LAYER M1 ;
      RECT 0.05 0.1 0.10 0.2 ;
    END
  END A1
  PIN A2
    DIRECTION INPUT ;
    USE SIGNAL ;
    PORT
      LAYER M1 ;
      RECT 0.15 0.1 0.20 0.2 ;
    END
  END A2
  PIN Z
    DIRECTION OUTPUT ;
    USE SIGNAL ;
    PORT
      LAYER M1 ;
      RECT 0.25 0.1 0.30 0.2 ;
    END
  END Z
END XOR2D6
MACRO XOR2OPTLD1
  CLASS CORE ;
  ORIGIN 0.0 0.0 ;
  SIZE 0.45 BY 0.3 ;
  SYMMETRY X Y ;
  PIN A1
    DIRECTION INPUT ;
    USE SIGNAL ;
    PORT
      LAYER M1 ;
      RECT 0.05 0.1 0.10 0.2 ;
    END
  END A1
  PIN A2
    DIRECTION INPUT ;
    USE SIGNAL ;
    PORT
      LAYER M1 ;
      RECT 0.15 0.1 0.20 0.2 ;
    END
  END A2
  PIN Z
    DIRECTION OUTPUT ;
    USE SIGNAL ;
    PORT
      LAYER M1 ;
      RECT 0.25 0.1 0.30 0.2 ;
    END
  END Z
END XOR2OPTLD1
MACRO XOR2OPTLD2
  CLASS CORE ;
  ORIGIN 0.0 0.0 ;
  SIZE 0.45 BY 0.3 ;
  SYMMETRY X Y ;
  PIN A1
    DIRECTION INPUT ;
    USE SIGNAL ;
    PORT
      LAYER M1 ;
      RECT 0.05 0.1 0.10 0.2 ;
    END
  END A1
  PIN A2
    DIRECTION INPUT ;
    USE SIGNAL ;
    PORT
      LAYER M1 ;
      RECT 0.15 0.1 0.20 0.2 ;
    END
  END A2
  PIN Z
    DIRECTION OUTPUT ;
    USE SIGNAL ;
    PORT
      LAYER M1 ;
      RECT 0.25 0.1 0.30 0.2 ;
    END
  END Z
END XOR2OPTLD2
MACRO XOR2OPTLD6
  CLASS CORE ;
  ORIGIN 0.0 0.0 ;
  SIZE 0.45 BY 0.3 ;
  SYMMETRY X Y ;
  PIN A1
    DIRECTION INPUT ;
    USE SIGNAL ;
    PORT
      LAYER M1 ;
      RECT 0.05 0.1 0.10 0.2 ;
    END
  END A1
  PIN A2
    DIRECTION INPUT ;
    USE SIGNAL ;
    PORT
      LAYER M1 ;
      RECT 0.15 0.1 0.20 0.2 ;
    END
  END A2
  PIN Z
    DIRECTION OUTPUT ;
    USE SIGNAL ;
    PORT
      LAYER M1 ;
      RECT 0.25 0.1 0.30 0.2 ;
    END
  END Z
END XOR2OPTLD6
MACRO XOR3D0
  CLASS CORE ;
  ORIGIN 0.0 0.0 ;
  SIZE 0.45 BY 0.3 ;
  SYMMETRY X Y ;
  PIN A1
    DIRECTION INPUT ;
    USE SIGNAL ;
    PORT
      LAYER M1 ;
      RECT 0.05 0.1 0.10 0.2 ;
    END
  END A1
  PIN A2
    DIRECTION INPUT ;
    USE SIGNAL ;
    PORT
      LAYER M1 ;
      RECT 0.12 0.1 0.17 0.2 ;
    END
  END A2
  PIN A3
    DIRECTION INPUT ;
    USE SIGNAL ;
    PORT
      LAYER M1 ;
      RECT 0.20 0.1 0.25 0.2 ;
    END
  END A3
  PIN Z
    DIRECTION OUTPUT ;
    USE SIGNAL ;
    PORT
      LAYER M1 ;
      RECT 0.27 0.1 0.32 0.2 ;
    END
  END Z
END XOR3D0
MACRO XOR3D2
  CLASS CORE ;
  ORIGIN 0.0 0.0 ;
  SIZE 0.45 BY 0.3 ;
  SYMMETRY X Y ;
  PIN A1
    DIRECTION INPUT ;
    USE SIGNAL ;
    PORT
      LAYER M1 ;
      RECT 0.05 0.1 0.10 0.2 ;
    END
  END A1
  PIN A2
    DIRECTION INPUT ;
    USE SIGNAL ;
    PORT
      LAYER M1 ;
      RECT 0.12 0.1 0.17 0.2 ;
    END
  END A2
  PIN A3
    DIRECTION INPUT ;
    USE SIGNAL ;
    PORT
      LAYER M1 ;
      RECT 0.20 0.1 0.25 0.2 ;
    END
  END A3
  PIN Z
    DIRECTION OUTPUT ;
    USE SIGNAL ;
    PORT
      LAYER M1 ;
      RECT 0.27 0.1 0.32 0.2 ;
    END
  END Z
END XOR3D2
MACRO XOR3D4
  CLASS CORE ;
  ORIGIN 0.0 0.0 ;
  SIZE 0.45 BY 0.3 ;
  SYMMETRY X Y ;
  PIN A1
    DIRECTION INPUT ;
    USE SIGNAL ;
    PORT
      LAYER M1 ;
      RECT 0.05 0.1 0.10 0.2 ;
    END
  END A1
  PIN A2
    DIRECTION INPUT ;
    USE SIGNAL ;
    PORT
      LAYER M1 ;
      RECT 0.12 0.1 0.17 0.2 ;
    END
  END A2
  PIN A3
    DIRECTION INPUT ;
    USE SIGNAL ;
    PORT
      LAYER M1 ;
      RECT 0.20 0.1 0.25 0.2 ;
    END
  END A3
  PIN Z
    DIRECTION OUTPUT ;
    USE SIGNAL ;
    PORT
      LAYER M1 ;
      RECT 0.27 0.1 0.32 0.2 ;
    END
  END Z
END XOR3D4
MACRO XOR3OPTLD4
  CLASS CORE ;
  ORIGIN 0.0 0.0 ;
  SIZE 0.45 BY 0.3 ;
  SYMMETRY X Y ;
  PIN A1
    DIRECTION INPUT ;
    USE SIGNAL ;
    PORT
      LAYER M1 ;
      RECT 0.05 0.1 0.10 0.2 ;
    END
  END A1
  PIN A2
    DIRECTION INPUT ;
    USE SIGNAL ;
    PORT
      LAYER M1 ;
      RECT 0.12 0.1 0.17 0.2 ;
    END
  END A2
  PIN A3
    DIRECTION INPUT ;
    USE SIGNAL ;
    PORT
      LAYER M1 ;
      RECT 0.20 0.1 0.25 0.2 ;
    END
  END A3
  PIN Z
    DIRECTION OUTPUT ;
    USE SIGNAL ;
    PORT
      LAYER M1 ;
      RECT 0.27 0.1 0.32 0.2 ;
    END
  END Z
END XOR3OPTLD4
MACRO XOR4D0
  CLASS CORE ;
  ORIGIN 0.0 0.0 ;
  SIZE 0.45 BY 0.3 ;
  SYMMETRY X Y ;
  PIN A1
    DIRECTION INPUT ;
    USE SIGNAL ;
    PORT
      LAYER M1 ;
      RECT 0.05 0.1 0.10 0.2 ;
    END
  END A1
  PIN A2
    DIRECTION INPUT ;
    USE SIGNAL ;
    PORT
      LAYER M1 ;
      RECT 0.11 0.1 0.16 0.2 ;
    END
  END A2
  PIN A3
    DIRECTION INPUT ;
    USE SIGNAL ;
    PORT
      LAYER M1 ;
      RECT 0.17 0.1 0.22 0.2 ;
    END
  END A3
  PIN A4
    DIRECTION INPUT ;
    USE SIGNAL ;
    PORT
      LAYER M1 ;
      RECT 0.23 0.1 0.28 0.2 ;
    END
  END A4
  PIN Z
    DIRECTION OUTPUT ;
    USE SIGNAL ;
    PORT
      LAYER M1 ;
      RECT 0.29 0.1 0.34 0.2 ;
    END
  END Z
END XOR4D0
MACRO XOR4D2
  CLASS CORE ;
  ORIGIN 0.0 0.0 ;
  SIZE 0.45 BY 0.3 ;
  SYMMETRY X Y ;
  PIN A1
    DIRECTION INPUT ;
    USE SIGNAL ;
    PORT
      LAYER M1 ;
      RECT 0.05 0.1 0.10 0.2 ;
    END
  END A1
  PIN A2
    DIRECTION INPUT ;
    USE SIGNAL ;
    PORT
      LAYER M1 ;
      RECT 0.11 0.1 0.16 0.2 ;
    END
  END A2
  PIN A3
    DIRECTION INPUT ;
    USE SIGNAL ;
    PORT
      LAYER M1 ;
      RECT 0.17 0.1 0.22 0.2 ;
    END
  END A3
  PIN A4
    DIRECTION INPUT ;
    USE SIGNAL ;
    PORT
      LAYER M1 ;
      RECT 0.23 0.1 0.28 0.2 ;
    END
  END A4
  PIN Z
    DIRECTION OUTPUT ;
    USE SIGNAL ;
    PORT
      LAYER M1 ;
      RECT 0.29 0.1 0.34 0.2 ;
    END
  END Z
END XOR4D2
MACRO XOR4D4
  CLASS CORE ;
  ORIGIN 0.0 0.0 ;
  SIZE 0.45 BY 0.3 ;
  SYMMETRY X Y ;
  PIN A1
    DIRECTION INPUT ;
    USE SIGNAL ;
    PORT
      LAYER M1 ;
      RECT 0.05 0.1 0.10 0.2 ;
    END
  END A1
  PIN A2
    DIRECTION INPUT ;
    USE SIGNAL ;
    PORT
      LAYER M1 ;
      RECT 0.11 0.1 0.16 0.2 ;
    END
  END A2
  PIN A3
    DIRECTION INPUT ;
    USE SIGNAL ;
    PORT
      LAYER M1 ;
      RECT 0.17 0.1 0.22 0.2 ;
    END
  END A3
  PIN A4
    DIRECTION INPUT ;
    USE SIGNAL ;
    PORT
      LAYER M1 ;
      RECT 0.23 0.1 0.28 0.2 ;
    END
  END A4
  PIN Z
    DIRECTION OUTPUT ;
    USE SIGNAL ;
    PORT
      LAYER M1 ;
      RECT 0.29 0.1 0.34 0.2 ;
    END
  END Z
END XOR4D4
